VERSION 5.8 ;
BUSBITCHARS "[]" ;
DIVIDERCHAR "/" ;
UNITS
    DATABASE MICRONS 1000 ;
END UNITS

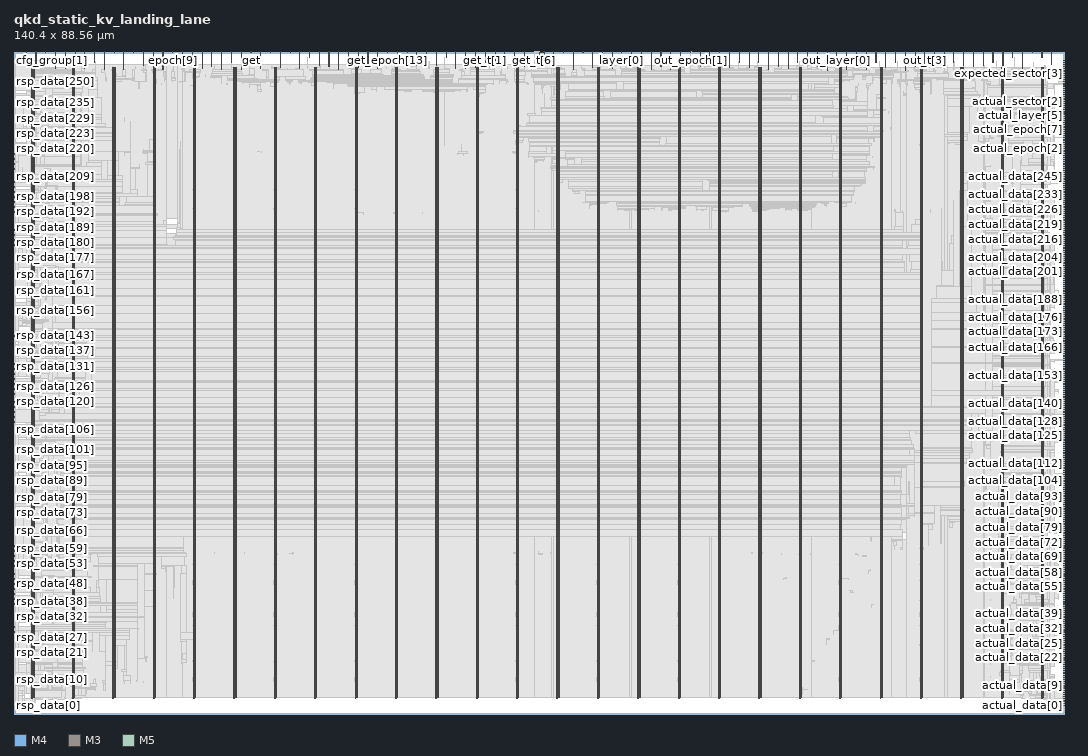
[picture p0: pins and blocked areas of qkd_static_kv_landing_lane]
MACRO qkd_static_kv_landing_lane
  FOREIGN qkd_static_kv_landing_lane 0 0 ;
  CLASS BLOCK ;
  SIZE 140.4 BY 88.56 ;
  PIN actual_data[0]
    DIRECTION INPUT ;
    USE SIGNAL ;
    PORT
      LAYER M4 ;
        RECT  140.316 1.152 140.4 1.176 ;
    END
  END actual_data[0]
  PIN actual_data[100]
    DIRECTION INPUT ;
    USE SIGNAL ;
    PORT
      LAYER M4 ;
        RECT  140.316 30 140.4 30.024 ;
    END
  END actual_data[100]
  PIN actual_data[101]
    DIRECTION INPUT ;
    USE SIGNAL ;
    PORT
      LAYER M4 ;
        RECT  140.316 30.288 140.4 30.312 ;
    END
  END actual_data[101]
  PIN actual_data[102]
    DIRECTION INPUT ;
    USE SIGNAL ;
    PORT
      LAYER M4 ;
        RECT  140.316 30.576 140.4 30.6 ;
    END
  END actual_data[102]
  PIN actual_data[103]
    DIRECTION INPUT ;
    USE SIGNAL ;
    PORT
      LAYER M4 ;
        RECT  140.316 30.864 140.4 30.888 ;
    END
  END actual_data[103]
  PIN actual_data[104]
    DIRECTION INPUT ;
    USE SIGNAL ;
    PORT
      LAYER M4 ;
        RECT  140.316 31.152 140.4 31.176 ;
    END
  END actual_data[104]
  PIN actual_data[105]
    DIRECTION INPUT ;
    USE SIGNAL ;
    PORT
      LAYER M4 ;
        RECT  140.316 31.44 140.4 31.464 ;
    END
  END actual_data[105]
  PIN actual_data[106]
    DIRECTION INPUT ;
    USE SIGNAL ;
    PORT
      LAYER M4 ;
        RECT  140.316 31.728 140.4 31.752 ;
    END
  END actual_data[106]
  PIN actual_data[107]
    DIRECTION INPUT ;
    USE SIGNAL ;
    PORT
      LAYER M4 ;
        RECT  140.316 32.016 140.4 32.04 ;
    END
  END actual_data[107]
  PIN actual_data[108]
    DIRECTION INPUT ;
    USE SIGNAL ;
    PORT
      LAYER M4 ;
        RECT  140.316 32.304 140.4 32.328 ;
    END
  END actual_data[108]
  PIN actual_data[109]
    DIRECTION INPUT ;
    USE SIGNAL ;
    PORT
      LAYER M4 ;
        RECT  140.316 32.592 140.4 32.616 ;
    END
  END actual_data[109]
  PIN actual_data[10]
    DIRECTION INPUT ;
    USE SIGNAL ;
    PORT
      LAYER M4 ;
        RECT  140.316 4.032 140.4 4.056 ;
    END
  END actual_data[10]
  PIN actual_data[110]
    DIRECTION INPUT ;
    USE SIGNAL ;
    PORT
      LAYER M4 ;
        RECT  140.316 32.88 140.4 32.904 ;
    END
  END actual_data[110]
  PIN actual_data[111]
    DIRECTION INPUT ;
    USE SIGNAL ;
    PORT
      LAYER M4 ;
        RECT  140.316 33.168 140.4 33.192 ;
    END
  END actual_data[111]
  PIN actual_data[112]
    DIRECTION INPUT ;
    USE SIGNAL ;
    PORT
      LAYER M4 ;
        RECT  140.316 33.456 140.4 33.48 ;
    END
  END actual_data[112]
  PIN actual_data[113]
    DIRECTION INPUT ;
    USE SIGNAL ;
    PORT
      LAYER M4 ;
        RECT  140.316 33.744 140.4 33.768 ;
    END
  END actual_data[113]
  PIN actual_data[114]
    DIRECTION INPUT ;
    USE SIGNAL ;
    PORT
      LAYER M4 ;
        RECT  140.316 34.032 140.4 34.056 ;
    END
  END actual_data[114]
  PIN actual_data[115]
    DIRECTION INPUT ;
    USE SIGNAL ;
    PORT
      LAYER M4 ;
        RECT  140.316 34.32 140.4 34.344 ;
    END
  END actual_data[115]
  PIN actual_data[116]
    DIRECTION INPUT ;
    USE SIGNAL ;
    PORT
      LAYER M4 ;
        RECT  140.316 34.608 140.4 34.632 ;
    END
  END actual_data[116]
  PIN actual_data[117]
    DIRECTION INPUT ;
    USE SIGNAL ;
    PORT
      LAYER M4 ;
        RECT  140.316 34.896 140.4 34.92 ;
    END
  END actual_data[117]
  PIN actual_data[118]
    DIRECTION INPUT ;
    USE SIGNAL ;
    PORT
      LAYER M4 ;
        RECT  140.316 35.184 140.4 35.208 ;
    END
  END actual_data[118]
  PIN actual_data[119]
    DIRECTION INPUT ;
    USE SIGNAL ;
    PORT
      LAYER M4 ;
        RECT  140.316 35.472 140.4 35.496 ;
    END
  END actual_data[119]
  PIN actual_data[11]
    DIRECTION INPUT ;
    USE SIGNAL ;
    PORT
      LAYER M4 ;
        RECT  140.316 4.32 140.4 4.344 ;
    END
  END actual_data[11]
  PIN actual_data[120]
    DIRECTION INPUT ;
    USE SIGNAL ;
    PORT
      LAYER M4 ;
        RECT  140.316 35.76 140.4 35.784 ;
    END
  END actual_data[120]
  PIN actual_data[121]
    DIRECTION INPUT ;
    USE SIGNAL ;
    PORT
      LAYER M4 ;
        RECT  140.316 36.048 140.4 36.072 ;
    END
  END actual_data[121]
  PIN actual_data[122]
    DIRECTION INPUT ;
    USE SIGNAL ;
    PORT
      LAYER M4 ;
        RECT  140.316 36.336 140.4 36.36 ;
    END
  END actual_data[122]
  PIN actual_data[123]
    DIRECTION INPUT ;
    USE SIGNAL ;
    PORT
      LAYER M4 ;
        RECT  140.316 36.624 140.4 36.648 ;
    END
  END actual_data[123]
  PIN actual_data[124]
    DIRECTION INPUT ;
    USE SIGNAL ;
    PORT
      LAYER M4 ;
        RECT  140.316 36.912 140.4 36.936 ;
    END
  END actual_data[124]
  PIN actual_data[125]
    DIRECTION INPUT ;
    USE SIGNAL ;
    PORT
      LAYER M4 ;
        RECT  140.316 37.2 140.4 37.224 ;
    END
  END actual_data[125]
  PIN actual_data[126]
    DIRECTION INPUT ;
    USE SIGNAL ;
    PORT
      LAYER M4 ;
        RECT  140.316 37.488 140.4 37.512 ;
    END
  END actual_data[126]
  PIN actual_data[127]
    DIRECTION INPUT ;
    USE SIGNAL ;
    PORT
      LAYER M4 ;
        RECT  140.316 37.776 140.4 37.8 ;
    END
  END actual_data[127]
  PIN actual_data[128]
    DIRECTION INPUT ;
    USE SIGNAL ;
    PORT
      LAYER M4 ;
        RECT  140.316 38.064 140.4 38.088 ;
    END
  END actual_data[128]
  PIN actual_data[129]
    DIRECTION INPUT ;
    USE SIGNAL ;
    PORT
      LAYER M4 ;
        RECT  140.316 38.352 140.4 38.376 ;
    END
  END actual_data[129]
  PIN actual_data[12]
    DIRECTION INPUT ;
    USE SIGNAL ;
    PORT
      LAYER M4 ;
        RECT  140.316 4.608 140.4 4.632 ;
    END
  END actual_data[12]
  PIN actual_data[130]
    DIRECTION INPUT ;
    USE SIGNAL ;
    PORT
      LAYER M4 ;
        RECT  140.316 38.64 140.4 38.664 ;
    END
  END actual_data[130]
  PIN actual_data[131]
    DIRECTION INPUT ;
    USE SIGNAL ;
    PORT
      LAYER M4 ;
        RECT  140.316 38.928 140.4 38.952 ;
    END
  END actual_data[131]
  PIN actual_data[132]
    DIRECTION INPUT ;
    USE SIGNAL ;
    PORT
      LAYER M4 ;
        RECT  140.316 39.216 140.4 39.24 ;
    END
  END actual_data[132]
  PIN actual_data[133]
    DIRECTION INPUT ;
    USE SIGNAL ;
    PORT
      LAYER M4 ;
        RECT  140.316 39.504 140.4 39.528 ;
    END
  END actual_data[133]
  PIN actual_data[134]
    DIRECTION INPUT ;
    USE SIGNAL ;
    PORT
      LAYER M4 ;
        RECT  140.316 39.792 140.4 39.816 ;
    END
  END actual_data[134]
  PIN actual_data[135]
    DIRECTION INPUT ;
    USE SIGNAL ;
    PORT
      LAYER M4 ;
        RECT  140.316 40.08 140.4 40.104 ;
    END
  END actual_data[135]
  PIN actual_data[136]
    DIRECTION INPUT ;
    USE SIGNAL ;
    PORT
      LAYER M4 ;
        RECT  140.316 40.368 140.4 40.392 ;
    END
  END actual_data[136]
  PIN actual_data[137]
    DIRECTION INPUT ;
    USE SIGNAL ;
    PORT
      LAYER M4 ;
        RECT  140.316 40.656 140.4 40.68 ;
    END
  END actual_data[137]
  PIN actual_data[138]
    DIRECTION INPUT ;
    USE SIGNAL ;
    PORT
      LAYER M4 ;
        RECT  140.316 40.944 140.4 40.968 ;
    END
  END actual_data[138]
  PIN actual_data[139]
    DIRECTION INPUT ;
    USE SIGNAL ;
    PORT
      LAYER M4 ;
        RECT  140.316 41.232 140.4 41.256 ;
    END
  END actual_data[139]
  PIN actual_data[13]
    DIRECTION INPUT ;
    USE SIGNAL ;
    PORT
      LAYER M4 ;
        RECT  140.316 4.896 140.4 4.92 ;
    END
  END actual_data[13]
  PIN actual_data[140]
    DIRECTION INPUT ;
    USE SIGNAL ;
    PORT
      LAYER M4 ;
        RECT  140.316 41.52 140.4 41.544 ;
    END
  END actual_data[140]
  PIN actual_data[141]
    DIRECTION INPUT ;
    USE SIGNAL ;
    PORT
      LAYER M4 ;
        RECT  140.316 41.808 140.4 41.832 ;
    END
  END actual_data[141]
  PIN actual_data[142]
    DIRECTION INPUT ;
    USE SIGNAL ;
    PORT
      LAYER M4 ;
        RECT  140.316 42.096 140.4 42.12 ;
    END
  END actual_data[142]
  PIN actual_data[143]
    DIRECTION INPUT ;
    USE SIGNAL ;
    PORT
      LAYER M4 ;
        RECT  140.316 42.384 140.4 42.408 ;
    END
  END actual_data[143]
  PIN actual_data[144]
    DIRECTION INPUT ;
    USE SIGNAL ;
    PORT
      LAYER M4 ;
        RECT  140.316 42.672 140.4 42.696 ;
    END
  END actual_data[144]
  PIN actual_data[145]
    DIRECTION INPUT ;
    USE SIGNAL ;
    PORT
      LAYER M4 ;
        RECT  140.316 42.96 140.4 42.984 ;
    END
  END actual_data[145]
  PIN actual_data[146]
    DIRECTION INPUT ;
    USE SIGNAL ;
    PORT
      LAYER M4 ;
        RECT  140.316 43.248 140.4 43.272 ;
    END
  END actual_data[146]
  PIN actual_data[147]
    DIRECTION INPUT ;
    USE SIGNAL ;
    PORT
      LAYER M4 ;
        RECT  140.316 43.536 140.4 43.56 ;
    END
  END actual_data[147]
  PIN actual_data[148]
    DIRECTION INPUT ;
    USE SIGNAL ;
    PORT
      LAYER M4 ;
        RECT  140.316 43.824 140.4 43.848 ;
    END
  END actual_data[148]
  PIN actual_data[149]
    DIRECTION INPUT ;
    USE SIGNAL ;
    PORT
      LAYER M4 ;
        RECT  140.316 44.112 140.4 44.136 ;
    END
  END actual_data[149]
  PIN actual_data[14]
    DIRECTION INPUT ;
    USE SIGNAL ;
    PORT
      LAYER M4 ;
        RECT  140.316 5.184 140.4 5.208 ;
    END
  END actual_data[14]
  PIN actual_data[150]
    DIRECTION INPUT ;
    USE SIGNAL ;
    PORT
      LAYER M4 ;
        RECT  140.316 44.4 140.4 44.424 ;
    END
  END actual_data[150]
  PIN actual_data[151]
    DIRECTION INPUT ;
    USE SIGNAL ;
    PORT
      LAYER M4 ;
        RECT  140.316 44.688 140.4 44.712 ;
    END
  END actual_data[151]
  PIN actual_data[152]
    DIRECTION INPUT ;
    USE SIGNAL ;
    PORT
      LAYER M4 ;
        RECT  140.316 44.976 140.4 45 ;
    END
  END actual_data[152]
  PIN actual_data[153]
    DIRECTION INPUT ;
    USE SIGNAL ;
    PORT
      LAYER M4 ;
        RECT  140.316 45.264 140.4 45.288 ;
    END
  END actual_data[153]
  PIN actual_data[154]
    DIRECTION INPUT ;
    USE SIGNAL ;
    PORT
      LAYER M4 ;
        RECT  140.316 45.552 140.4 45.576 ;
    END
  END actual_data[154]
  PIN actual_data[155]
    DIRECTION INPUT ;
    USE SIGNAL ;
    PORT
      LAYER M4 ;
        RECT  140.316 45.84 140.4 45.864 ;
    END
  END actual_data[155]
  PIN actual_data[156]
    DIRECTION INPUT ;
    USE SIGNAL ;
    PORT
      LAYER M4 ;
        RECT  140.316 46.128 140.4 46.152 ;
    END
  END actual_data[156]
  PIN actual_data[157]
    DIRECTION INPUT ;
    USE SIGNAL ;
    PORT
      LAYER M4 ;
        RECT  140.316 46.416 140.4 46.44 ;
    END
  END actual_data[157]
  PIN actual_data[158]
    DIRECTION INPUT ;
    USE SIGNAL ;
    PORT
      LAYER M4 ;
        RECT  140.316 46.704 140.4 46.728 ;
    END
  END actual_data[158]
  PIN actual_data[159]
    DIRECTION INPUT ;
    USE SIGNAL ;
    PORT
      LAYER M4 ;
        RECT  140.316 46.992 140.4 47.016 ;
    END
  END actual_data[159]
  PIN actual_data[15]
    DIRECTION INPUT ;
    USE SIGNAL ;
    PORT
      LAYER M4 ;
        RECT  140.316 5.472 140.4 5.496 ;
    END
  END actual_data[15]
  PIN actual_data[160]
    DIRECTION INPUT ;
    USE SIGNAL ;
    PORT
      LAYER M4 ;
        RECT  140.316 47.28 140.4 47.304 ;
    END
  END actual_data[160]
  PIN actual_data[161]
    DIRECTION INPUT ;
    USE SIGNAL ;
    PORT
      LAYER M4 ;
        RECT  140.316 47.568 140.4 47.592 ;
    END
  END actual_data[161]
  PIN actual_data[162]
    DIRECTION INPUT ;
    USE SIGNAL ;
    PORT
      LAYER M4 ;
        RECT  140.316 47.856 140.4 47.88 ;
    END
  END actual_data[162]
  PIN actual_data[163]
    DIRECTION INPUT ;
    USE SIGNAL ;
    PORT
      LAYER M4 ;
        RECT  140.316 48.144 140.4 48.168 ;
    END
  END actual_data[163]
  PIN actual_data[164]
    DIRECTION INPUT ;
    USE SIGNAL ;
    PORT
      LAYER M4 ;
        RECT  140.316 48.432 140.4 48.456 ;
    END
  END actual_data[164]
  PIN actual_data[165]
    DIRECTION INPUT ;
    USE SIGNAL ;
    PORT
      LAYER M4 ;
        RECT  140.316 48.72 140.4 48.744 ;
    END
  END actual_data[165]
  PIN actual_data[166]
    DIRECTION INPUT ;
    USE SIGNAL ;
    PORT
      LAYER M4 ;
        RECT  140.316 49.008 140.4 49.032 ;
    END
  END actual_data[166]
  PIN actual_data[167]
    DIRECTION INPUT ;
    USE SIGNAL ;
    PORT
      LAYER M4 ;
        RECT  140.316 49.296 140.4 49.32 ;
    END
  END actual_data[167]
  PIN actual_data[168]
    DIRECTION INPUT ;
    USE SIGNAL ;
    PORT
      LAYER M4 ;
        RECT  140.316 49.584 140.4 49.608 ;
    END
  END actual_data[168]
  PIN actual_data[169]
    DIRECTION INPUT ;
    USE SIGNAL ;
    PORT
      LAYER M4 ;
        RECT  140.316 49.872 140.4 49.896 ;
    END
  END actual_data[169]
  PIN actual_data[16]
    DIRECTION INPUT ;
    USE SIGNAL ;
    PORT
      LAYER M4 ;
        RECT  140.316 5.76 140.4 5.784 ;
    END
  END actual_data[16]
  PIN actual_data[170]
    DIRECTION INPUT ;
    USE SIGNAL ;
    PORT
      LAYER M4 ;
        RECT  140.316 50.16 140.4 50.184 ;
    END
  END actual_data[170]
  PIN actual_data[171]
    DIRECTION INPUT ;
    USE SIGNAL ;
    PORT
      LAYER M4 ;
        RECT  140.316 50.448 140.4 50.472 ;
    END
  END actual_data[171]
  PIN actual_data[172]
    DIRECTION INPUT ;
    USE SIGNAL ;
    PORT
      LAYER M4 ;
        RECT  140.316 50.784 140.4 50.808 ;
    END
  END actual_data[172]
  PIN actual_data[173]
    DIRECTION INPUT ;
    USE SIGNAL ;
    PORT
      LAYER M4 ;
        RECT  140.316 51.072 140.4 51.096 ;
    END
  END actual_data[173]
  PIN actual_data[174]
    DIRECTION INPUT ;
    USE SIGNAL ;
    PORT
      LAYER M4 ;
        RECT  140.316 51.36 140.4 51.384 ;
    END
  END actual_data[174]
  PIN actual_data[175]
    DIRECTION INPUT ;
    USE SIGNAL ;
    PORT
      LAYER M4 ;
        RECT  140.316 51.648 140.4 51.672 ;
    END
  END actual_data[175]
  PIN actual_data[176]
    DIRECTION INPUT ;
    USE SIGNAL ;
    PORT
      LAYER M4 ;
        RECT  140.316 51.936 140.4 51.96 ;
    END
  END actual_data[176]
  PIN actual_data[177]
    DIRECTION INPUT ;
    USE SIGNAL ;
    PORT
      LAYER M4 ;
        RECT  140.316 52.224 140.4 52.248 ;
    END
  END actual_data[177]
  PIN actual_data[178]
    DIRECTION INPUT ;
    USE SIGNAL ;
    PORT
      LAYER M4 ;
        RECT  140.316 52.512 140.4 52.536 ;
    END
  END actual_data[178]
  PIN actual_data[179]
    DIRECTION INPUT ;
    USE SIGNAL ;
    PORT
      LAYER M4 ;
        RECT  140.316 52.8 140.4 52.824 ;
    END
  END actual_data[179]
  PIN actual_data[17]
    DIRECTION INPUT ;
    USE SIGNAL ;
    PORT
      LAYER M4 ;
        RECT  140.316 6.048 140.4 6.072 ;
    END
  END actual_data[17]
  PIN actual_data[180]
    DIRECTION INPUT ;
    USE SIGNAL ;
    PORT
      LAYER M4 ;
        RECT  140.316 53.088 140.4 53.112 ;
    END
  END actual_data[180]
  PIN actual_data[181]
    DIRECTION INPUT ;
    USE SIGNAL ;
    PORT
      LAYER M4 ;
        RECT  140.316 53.376 140.4 53.4 ;
    END
  END actual_data[181]
  PIN actual_data[182]
    DIRECTION INPUT ;
    USE SIGNAL ;
    PORT
      LAYER M4 ;
        RECT  140.316 53.664 140.4 53.688 ;
    END
  END actual_data[182]
  PIN actual_data[183]
    DIRECTION INPUT ;
    USE SIGNAL ;
    PORT
      LAYER M4 ;
        RECT  140.316 53.952 140.4 53.976 ;
    END
  END actual_data[183]
  PIN actual_data[184]
    DIRECTION INPUT ;
    USE SIGNAL ;
    PORT
      LAYER M4 ;
        RECT  140.316 54.24 140.4 54.264 ;
    END
  END actual_data[184]
  PIN actual_data[185]
    DIRECTION INPUT ;
    USE SIGNAL ;
    PORT
      LAYER M4 ;
        RECT  140.316 54.528 140.4 54.552 ;
    END
  END actual_data[185]
  PIN actual_data[186]
    DIRECTION INPUT ;
    USE SIGNAL ;
    PORT
      LAYER M4 ;
        RECT  140.316 54.816 140.4 54.84 ;
    END
  END actual_data[186]
  PIN actual_data[187]
    DIRECTION INPUT ;
    USE SIGNAL ;
    PORT
      LAYER M4 ;
        RECT  140.316 55.104 140.4 55.128 ;
    END
  END actual_data[187]
  PIN actual_data[188]
    DIRECTION INPUT ;
    USE SIGNAL ;
    PORT
      LAYER M4 ;
        RECT  140.316 55.392 140.4 55.416 ;
    END
  END actual_data[188]
  PIN actual_data[189]
    DIRECTION INPUT ;
    USE SIGNAL ;
    PORT
      LAYER M4 ;
        RECT  140.316 55.68 140.4 55.704 ;
    END
  END actual_data[189]
  PIN actual_data[18]
    DIRECTION INPUT ;
    USE SIGNAL ;
    PORT
      LAYER M4 ;
        RECT  140.316 6.336 140.4 6.36 ;
    END
  END actual_data[18]
  PIN actual_data[190]
    DIRECTION INPUT ;
    USE SIGNAL ;
    PORT
      LAYER M4 ;
        RECT  140.316 55.968 140.4 55.992 ;
    END
  END actual_data[190]
  PIN actual_data[191]
    DIRECTION INPUT ;
    USE SIGNAL ;
    PORT
      LAYER M4 ;
        RECT  140.316 56.256 140.4 56.28 ;
    END
  END actual_data[191]
  PIN actual_data[192]
    DIRECTION INPUT ;
    USE SIGNAL ;
    PORT
      LAYER M4 ;
        RECT  140.316 56.544 140.4 56.568 ;
    END
  END actual_data[192]
  PIN actual_data[193]
    DIRECTION INPUT ;
    USE SIGNAL ;
    PORT
      LAYER M4 ;
        RECT  140.316 56.832 140.4 56.856 ;
    END
  END actual_data[193]
  PIN actual_data[194]
    DIRECTION INPUT ;
    USE SIGNAL ;
    PORT
      LAYER M4 ;
        RECT  140.316 57.12 140.4 57.144 ;
    END
  END actual_data[194]
  PIN actual_data[195]
    DIRECTION INPUT ;
    USE SIGNAL ;
    PORT
      LAYER M4 ;
        RECT  140.316 57.408 140.4 57.432 ;
    END
  END actual_data[195]
  PIN actual_data[196]
    DIRECTION INPUT ;
    USE SIGNAL ;
    PORT
      LAYER M4 ;
        RECT  140.316 57.696 140.4 57.72 ;
    END
  END actual_data[196]
  PIN actual_data[197]
    DIRECTION INPUT ;
    USE SIGNAL ;
    PORT
      LAYER M4 ;
        RECT  140.316 57.984 140.4 58.008 ;
    END
  END actual_data[197]
  PIN actual_data[198]
    DIRECTION INPUT ;
    USE SIGNAL ;
    PORT
      LAYER M4 ;
        RECT  140.316 58.272 140.4 58.296 ;
    END
  END actual_data[198]
  PIN actual_data[199]
    DIRECTION INPUT ;
    USE SIGNAL ;
    PORT
      LAYER M4 ;
        RECT  140.316 58.56 140.4 58.584 ;
    END
  END actual_data[199]
  PIN actual_data[19]
    DIRECTION INPUT ;
    USE SIGNAL ;
    PORT
      LAYER M4 ;
        RECT  140.316 6.624 140.4 6.648 ;
    END
  END actual_data[19]
  PIN actual_data[1]
    DIRECTION INPUT ;
    USE SIGNAL ;
    PORT
      LAYER M4 ;
        RECT  140.316 1.44 140.4 1.464 ;
    END
  END actual_data[1]
  PIN actual_data[200]
    DIRECTION INPUT ;
    USE SIGNAL ;
    PORT
      LAYER M4 ;
        RECT  140.316 58.848 140.4 58.872 ;
    END
  END actual_data[200]
  PIN actual_data[201]
    DIRECTION INPUT ;
    USE SIGNAL ;
    PORT
      LAYER M4 ;
        RECT  140.316 59.136 140.4 59.16 ;
    END
  END actual_data[201]
  PIN actual_data[202]
    DIRECTION INPUT ;
    USE SIGNAL ;
    PORT
      LAYER M4 ;
        RECT  140.316 59.424 140.4 59.448 ;
    END
  END actual_data[202]
  PIN actual_data[203]
    DIRECTION INPUT ;
    USE SIGNAL ;
    PORT
      LAYER M4 ;
        RECT  140.316 59.712 140.4 59.736 ;
    END
  END actual_data[203]
  PIN actual_data[204]
    DIRECTION INPUT ;
    USE SIGNAL ;
    PORT
      LAYER M4 ;
        RECT  140.316 60 140.4 60.024 ;
    END
  END actual_data[204]
  PIN actual_data[205]
    DIRECTION INPUT ;
    USE SIGNAL ;
    PORT
      LAYER M4 ;
        RECT  140.316 60.288 140.4 60.312 ;
    END
  END actual_data[205]
  PIN actual_data[206]
    DIRECTION INPUT ;
    USE SIGNAL ;
    PORT
      LAYER M4 ;
        RECT  140.316 60.576 140.4 60.6 ;
    END
  END actual_data[206]
  PIN actual_data[207]
    DIRECTION INPUT ;
    USE SIGNAL ;
    PORT
      LAYER M4 ;
        RECT  140.316 60.864 140.4 60.888 ;
    END
  END actual_data[207]
  PIN actual_data[208]
    DIRECTION INPUT ;
    USE SIGNAL ;
    PORT
      LAYER M4 ;
        RECT  140.316 61.152 140.4 61.176 ;
    END
  END actual_data[208]
  PIN actual_data[209]
    DIRECTION INPUT ;
    USE SIGNAL ;
    PORT
      LAYER M4 ;
        RECT  140.316 61.44 140.4 61.464 ;
    END
  END actual_data[209]
  PIN actual_data[20]
    DIRECTION INPUT ;
    USE SIGNAL ;
    PORT
      LAYER M4 ;
        RECT  140.316 6.912 140.4 6.936 ;
    END
  END actual_data[20]
  PIN actual_data[210]
    DIRECTION INPUT ;
    USE SIGNAL ;
    PORT
      LAYER M4 ;
        RECT  140.316 61.728 140.4 61.752 ;
    END
  END actual_data[210]
  PIN actual_data[211]
    DIRECTION INPUT ;
    USE SIGNAL ;
    PORT
      LAYER M4 ;
        RECT  140.316 62.016 140.4 62.04 ;
    END
  END actual_data[211]
  PIN actual_data[212]
    DIRECTION INPUT ;
    USE SIGNAL ;
    PORT
      LAYER M4 ;
        RECT  140.316 62.304 140.4 62.328 ;
    END
  END actual_data[212]
  PIN actual_data[213]
    DIRECTION INPUT ;
    USE SIGNAL ;
    PORT
      LAYER M4 ;
        RECT  140.316 62.592 140.4 62.616 ;
    END
  END actual_data[213]
  PIN actual_data[214]
    DIRECTION INPUT ;
    USE SIGNAL ;
    PORT
      LAYER M4 ;
        RECT  140.316 62.88 140.4 62.904 ;
    END
  END actual_data[214]
  PIN actual_data[215]
    DIRECTION INPUT ;
    USE SIGNAL ;
    PORT
      LAYER M4 ;
        RECT  140.316 63.168 140.4 63.192 ;
    END
  END actual_data[215]
  PIN actual_data[216]
    DIRECTION INPUT ;
    USE SIGNAL ;
    PORT
      LAYER M4 ;
        RECT  140.316 63.456 140.4 63.48 ;
    END
  END actual_data[216]
  PIN actual_data[217]
    DIRECTION INPUT ;
    USE SIGNAL ;
    PORT
      LAYER M4 ;
        RECT  140.316 63.744 140.4 63.768 ;
    END
  END actual_data[217]
  PIN actual_data[218]
    DIRECTION INPUT ;
    USE SIGNAL ;
    PORT
      LAYER M4 ;
        RECT  140.316 64.032 140.4 64.056 ;
    END
  END actual_data[218]
  PIN actual_data[219]
    DIRECTION INPUT ;
    USE SIGNAL ;
    PORT
      LAYER M4 ;
        RECT  140.316 64.32 140.4 64.344 ;
    END
  END actual_data[219]
  PIN actual_data[21]
    DIRECTION INPUT ;
    USE SIGNAL ;
    PORT
      LAYER M4 ;
        RECT  140.316 7.2 140.4 7.224 ;
    END
  END actual_data[21]
  PIN actual_data[220]
    DIRECTION INPUT ;
    USE SIGNAL ;
    PORT
      LAYER M4 ;
        RECT  140.316 64.608 140.4 64.632 ;
    END
  END actual_data[220]
  PIN actual_data[221]
    DIRECTION INPUT ;
    USE SIGNAL ;
    PORT
      LAYER M4 ;
        RECT  140.316 64.896 140.4 64.92 ;
    END
  END actual_data[221]
  PIN actual_data[222]
    DIRECTION INPUT ;
    USE SIGNAL ;
    PORT
      LAYER M4 ;
        RECT  140.316 65.184 140.4 65.208 ;
    END
  END actual_data[222]
  PIN actual_data[223]
    DIRECTION INPUT ;
    USE SIGNAL ;
    PORT
      LAYER M4 ;
        RECT  140.316 65.472 140.4 65.496 ;
    END
  END actual_data[223]
  PIN actual_data[224]
    DIRECTION INPUT ;
    USE SIGNAL ;
    PORT
      LAYER M4 ;
        RECT  140.316 65.76 140.4 65.784 ;
    END
  END actual_data[224]
  PIN actual_data[225]
    DIRECTION INPUT ;
    USE SIGNAL ;
    PORT
      LAYER M4 ;
        RECT  140.316 66.048 140.4 66.072 ;
    END
  END actual_data[225]
  PIN actual_data[226]
    DIRECTION INPUT ;
    USE SIGNAL ;
    PORT
      LAYER M4 ;
        RECT  140.316 66.336 140.4 66.36 ;
    END
  END actual_data[226]
  PIN actual_data[227]
    DIRECTION INPUT ;
    USE SIGNAL ;
    PORT
      LAYER M4 ;
        RECT  140.316 66.624 140.4 66.648 ;
    END
  END actual_data[227]
  PIN actual_data[228]
    DIRECTION INPUT ;
    USE SIGNAL ;
    PORT
      LAYER M4 ;
        RECT  140.316 66.912 140.4 66.936 ;
    END
  END actual_data[228]
  PIN actual_data[229]
    DIRECTION INPUT ;
    USE SIGNAL ;
    PORT
      LAYER M4 ;
        RECT  140.316 67.2 140.4 67.224 ;
    END
  END actual_data[229]
  PIN actual_data[22]
    DIRECTION INPUT ;
    USE SIGNAL ;
    PORT
      LAYER M4 ;
        RECT  140.316 7.488 140.4 7.512 ;
    END
  END actual_data[22]
  PIN actual_data[230]
    DIRECTION INPUT ;
    USE SIGNAL ;
    PORT
      LAYER M4 ;
        RECT  140.316 67.488 140.4 67.512 ;
    END
  END actual_data[230]
  PIN actual_data[231]
    DIRECTION INPUT ;
    USE SIGNAL ;
    PORT
      LAYER M4 ;
        RECT  140.316 67.776 140.4 67.8 ;
    END
  END actual_data[231]
  PIN actual_data[232]
    DIRECTION INPUT ;
    USE SIGNAL ;
    PORT
      LAYER M4 ;
        RECT  140.316 68.064 140.4 68.088 ;
    END
  END actual_data[232]
  PIN actual_data[233]
    DIRECTION INPUT ;
    USE SIGNAL ;
    PORT
      LAYER M4 ;
        RECT  140.316 68.352 140.4 68.376 ;
    END
  END actual_data[233]
  PIN actual_data[234]
    DIRECTION INPUT ;
    USE SIGNAL ;
    PORT
      LAYER M4 ;
        RECT  140.316 68.64 140.4 68.664 ;
    END
  END actual_data[234]
  PIN actual_data[235]
    DIRECTION INPUT ;
    USE SIGNAL ;
    PORT
      LAYER M4 ;
        RECT  140.316 68.928 140.4 68.952 ;
    END
  END actual_data[235]
  PIN actual_data[236]
    DIRECTION INPUT ;
    USE SIGNAL ;
    PORT
      LAYER M4 ;
        RECT  140.316 69.216 140.4 69.24 ;
    END
  END actual_data[236]
  PIN actual_data[237]
    DIRECTION INPUT ;
    USE SIGNAL ;
    PORT
      LAYER M4 ;
        RECT  140.316 69.504 140.4 69.528 ;
    END
  END actual_data[237]
  PIN actual_data[238]
    DIRECTION INPUT ;
    USE SIGNAL ;
    PORT
      LAYER M4 ;
        RECT  140.316 69.792 140.4 69.816 ;
    END
  END actual_data[238]
  PIN actual_data[239]
    DIRECTION INPUT ;
    USE SIGNAL ;
    PORT
      LAYER M4 ;
        RECT  140.316 70.08 140.4 70.104 ;
    END
  END actual_data[239]
  PIN actual_data[23]
    DIRECTION INPUT ;
    USE SIGNAL ;
    PORT
      LAYER M4 ;
        RECT  140.316 7.776 140.4 7.8 ;
    END
  END actual_data[23]
  PIN actual_data[240]
    DIRECTION INPUT ;
    USE SIGNAL ;
    PORT
      LAYER M4 ;
        RECT  140.316 70.368 140.4 70.392 ;
    END
  END actual_data[240]
  PIN actual_data[241]
    DIRECTION INPUT ;
    USE SIGNAL ;
    PORT
      LAYER M4 ;
        RECT  140.316 70.656 140.4 70.68 ;
    END
  END actual_data[241]
  PIN actual_data[242]
    DIRECTION INPUT ;
    USE SIGNAL ;
    PORT
      LAYER M4 ;
        RECT  140.316 70.944 140.4 70.968 ;
    END
  END actual_data[242]
  PIN actual_data[243]
    DIRECTION INPUT ;
    USE SIGNAL ;
    PORT
      LAYER M4 ;
        RECT  140.316 71.232 140.4 71.256 ;
    END
  END actual_data[243]
  PIN actual_data[244]
    DIRECTION INPUT ;
    USE SIGNAL ;
    PORT
      LAYER M4 ;
        RECT  140.316 71.52 140.4 71.544 ;
    END
  END actual_data[244]
  PIN actual_data[245]
    DIRECTION INPUT ;
    USE SIGNAL ;
    PORT
      LAYER M4 ;
        RECT  140.316 71.808 140.4 71.832 ;
    END
  END actual_data[245]
  PIN actual_data[246]
    DIRECTION INPUT ;
    USE SIGNAL ;
    PORT
      LAYER M4 ;
        RECT  140.316 72.096 140.4 72.12 ;
    END
  END actual_data[246]
  PIN actual_data[247]
    DIRECTION INPUT ;
    USE SIGNAL ;
    PORT
      LAYER M4 ;
        RECT  140.316 72.384 140.4 72.408 ;
    END
  END actual_data[247]
  PIN actual_data[248]
    DIRECTION INPUT ;
    USE SIGNAL ;
    PORT
      LAYER M4 ;
        RECT  140.316 72.672 140.4 72.696 ;
    END
  END actual_data[248]
  PIN actual_data[249]
    DIRECTION INPUT ;
    USE SIGNAL ;
    PORT
      LAYER M4 ;
        RECT  140.316 72.96 140.4 72.984 ;
    END
  END actual_data[249]
  PIN actual_data[24]
    DIRECTION INPUT ;
    USE SIGNAL ;
    PORT
      LAYER M4 ;
        RECT  140.316 8.064 140.4 8.088 ;
    END
  END actual_data[24]
  PIN actual_data[250]
    DIRECTION INPUT ;
    USE SIGNAL ;
    PORT
      LAYER M4 ;
        RECT  140.316 73.248 140.4 73.272 ;
    END
  END actual_data[250]
  PIN actual_data[251]
    DIRECTION INPUT ;
    USE SIGNAL ;
    PORT
      LAYER M4 ;
        RECT  140.316 73.536 140.4 73.56 ;
    END
  END actual_data[251]
  PIN actual_data[252]
    DIRECTION INPUT ;
    USE SIGNAL ;
    PORT
      LAYER M4 ;
        RECT  140.316 73.824 140.4 73.848 ;
    END
  END actual_data[252]
  PIN actual_data[253]
    DIRECTION INPUT ;
    USE SIGNAL ;
    PORT
      LAYER M4 ;
        RECT  140.316 74.112 140.4 74.136 ;
    END
  END actual_data[253]
  PIN actual_data[254]
    DIRECTION INPUT ;
    USE SIGNAL ;
    PORT
      LAYER M4 ;
        RECT  140.316 74.4 140.4 74.424 ;
    END
  END actual_data[254]
  PIN actual_data[255]
    DIRECTION INPUT ;
    USE SIGNAL ;
    PORT
      LAYER M4 ;
        RECT  140.316 74.688 140.4 74.712 ;
    END
  END actual_data[255]
  PIN actual_data[25]
    DIRECTION INPUT ;
    USE SIGNAL ;
    PORT
      LAYER M4 ;
        RECT  140.316 8.352 140.4 8.376 ;
    END
  END actual_data[25]
  PIN actual_data[26]
    DIRECTION INPUT ;
    USE SIGNAL ;
    PORT
      LAYER M4 ;
        RECT  140.316 8.64 140.4 8.664 ;
    END
  END actual_data[26]
  PIN actual_data[27]
    DIRECTION INPUT ;
    USE SIGNAL ;
    PORT
      LAYER M4 ;
        RECT  140.316 8.928 140.4 8.952 ;
    END
  END actual_data[27]
  PIN actual_data[28]
    DIRECTION INPUT ;
    USE SIGNAL ;
    PORT
      LAYER M4 ;
        RECT  140.316 9.216 140.4 9.24 ;
    END
  END actual_data[28]
  PIN actual_data[29]
    DIRECTION INPUT ;
    USE SIGNAL ;
    PORT
      LAYER M4 ;
        RECT  140.316 9.504 140.4 9.528 ;
    END
  END actual_data[29]
  PIN actual_data[2]
    DIRECTION INPUT ;
    USE SIGNAL ;
    PORT
      LAYER M4 ;
        RECT  140.316 1.728 140.4 1.752 ;
    END
  END actual_data[2]
  PIN actual_data[30]
    DIRECTION INPUT ;
    USE SIGNAL ;
    PORT
      LAYER M4 ;
        RECT  140.316 9.792 140.4 9.816 ;
    END
  END actual_data[30]
  PIN actual_data[31]
    DIRECTION INPUT ;
    USE SIGNAL ;
    PORT
      LAYER M4 ;
        RECT  140.316 10.08 140.4 10.104 ;
    END
  END actual_data[31]
  PIN actual_data[32]
    DIRECTION INPUT ;
    USE SIGNAL ;
    PORT
      LAYER M4 ;
        RECT  140.316 10.368 140.4 10.392 ;
    END
  END actual_data[32]
  PIN actual_data[33]
    DIRECTION INPUT ;
    USE SIGNAL ;
    PORT
      LAYER M4 ;
        RECT  140.316 10.656 140.4 10.68 ;
    END
  END actual_data[33]
  PIN actual_data[34]
    DIRECTION INPUT ;
    USE SIGNAL ;
    PORT
      LAYER M4 ;
        RECT  140.316 10.944 140.4 10.968 ;
    END
  END actual_data[34]
  PIN actual_data[35]
    DIRECTION INPUT ;
    USE SIGNAL ;
    PORT
      LAYER M4 ;
        RECT  140.316 11.232 140.4 11.256 ;
    END
  END actual_data[35]
  PIN actual_data[36]
    DIRECTION INPUT ;
    USE SIGNAL ;
    PORT
      LAYER M4 ;
        RECT  140.316 11.52 140.4 11.544 ;
    END
  END actual_data[36]
  PIN actual_data[37]
    DIRECTION INPUT ;
    USE SIGNAL ;
    PORT
      LAYER M4 ;
        RECT  140.316 11.808 140.4 11.832 ;
    END
  END actual_data[37]
  PIN actual_data[38]
    DIRECTION INPUT ;
    USE SIGNAL ;
    PORT
      LAYER M4 ;
        RECT  140.316 12.096 140.4 12.12 ;
    END
  END actual_data[38]
  PIN actual_data[39]
    DIRECTION INPUT ;
    USE SIGNAL ;
    PORT
      LAYER M4 ;
        RECT  140.316 12.384 140.4 12.408 ;
    END
  END actual_data[39]
  PIN actual_data[3]
    DIRECTION INPUT ;
    USE SIGNAL ;
    PORT
      LAYER M4 ;
        RECT  140.316 2.016 140.4 2.04 ;
    END
  END actual_data[3]
  PIN actual_data[40]
    DIRECTION INPUT ;
    USE SIGNAL ;
    PORT
      LAYER M4 ;
        RECT  140.316 12.672 140.4 12.696 ;
    END
  END actual_data[40]
  PIN actual_data[41]
    DIRECTION INPUT ;
    USE SIGNAL ;
    PORT
      LAYER M4 ;
        RECT  140.316 12.96 140.4 12.984 ;
    END
  END actual_data[41]
  PIN actual_data[42]
    DIRECTION INPUT ;
    USE SIGNAL ;
    PORT
      LAYER M4 ;
        RECT  140.316 13.248 140.4 13.272 ;
    END
  END actual_data[42]
  PIN actual_data[43]
    DIRECTION INPUT ;
    USE SIGNAL ;
    PORT
      LAYER M4 ;
        RECT  140.316 13.536 140.4 13.56 ;
    END
  END actual_data[43]
  PIN actual_data[44]
    DIRECTION INPUT ;
    USE SIGNAL ;
    PORT
      LAYER M4 ;
        RECT  140.316 13.824 140.4 13.848 ;
    END
  END actual_data[44]
  PIN actual_data[45]
    DIRECTION INPUT ;
    USE SIGNAL ;
    PORT
      LAYER M4 ;
        RECT  140.316 14.112 140.4 14.136 ;
    END
  END actual_data[45]
  PIN actual_data[46]
    DIRECTION INPUT ;
    USE SIGNAL ;
    PORT
      LAYER M4 ;
        RECT  140.316 14.4 140.4 14.424 ;
    END
  END actual_data[46]
  PIN actual_data[47]
    DIRECTION INPUT ;
    USE SIGNAL ;
    PORT
      LAYER M4 ;
        RECT  140.316 14.688 140.4 14.712 ;
    END
  END actual_data[47]
  PIN actual_data[48]
    DIRECTION INPUT ;
    USE SIGNAL ;
    PORT
      LAYER M4 ;
        RECT  140.316 14.976 140.4 15 ;
    END
  END actual_data[48]
  PIN actual_data[49]
    DIRECTION INPUT ;
    USE SIGNAL ;
    PORT
      LAYER M4 ;
        RECT  140.316 15.264 140.4 15.288 ;
    END
  END actual_data[49]
  PIN actual_data[4]
    DIRECTION INPUT ;
    USE SIGNAL ;
    PORT
      LAYER M4 ;
        RECT  140.316 2.304 140.4 2.328 ;
    END
  END actual_data[4]
  PIN actual_data[50]
    DIRECTION INPUT ;
    USE SIGNAL ;
    PORT
      LAYER M4 ;
        RECT  140.316 15.552 140.4 15.576 ;
    END
  END actual_data[50]
  PIN actual_data[51]
    DIRECTION INPUT ;
    USE SIGNAL ;
    PORT
      LAYER M4 ;
        RECT  140.316 15.84 140.4 15.864 ;
    END
  END actual_data[51]
  PIN actual_data[52]
    DIRECTION INPUT ;
    USE SIGNAL ;
    PORT
      LAYER M4 ;
        RECT  140.316 16.128 140.4 16.152 ;
    END
  END actual_data[52]
  PIN actual_data[53]
    DIRECTION INPUT ;
    USE SIGNAL ;
    PORT
      LAYER M4 ;
        RECT  140.316 16.416 140.4 16.44 ;
    END
  END actual_data[53]
  PIN actual_data[54]
    DIRECTION INPUT ;
    USE SIGNAL ;
    PORT
      LAYER M4 ;
        RECT  140.316 16.704 140.4 16.728 ;
    END
  END actual_data[54]
  PIN actual_data[55]
    DIRECTION INPUT ;
    USE SIGNAL ;
    PORT
      LAYER M4 ;
        RECT  140.316 16.992 140.4 17.016 ;
    END
  END actual_data[55]
  PIN actual_data[56]
    DIRECTION INPUT ;
    USE SIGNAL ;
    PORT
      LAYER M4 ;
        RECT  140.316 17.28 140.4 17.304 ;
    END
  END actual_data[56]
  PIN actual_data[57]
    DIRECTION INPUT ;
    USE SIGNAL ;
    PORT
      LAYER M4 ;
        RECT  140.316 17.568 140.4 17.592 ;
    END
  END actual_data[57]
  PIN actual_data[58]
    DIRECTION INPUT ;
    USE SIGNAL ;
    PORT
      LAYER M4 ;
        RECT  140.316 17.856 140.4 17.88 ;
    END
  END actual_data[58]
  PIN actual_data[59]
    DIRECTION INPUT ;
    USE SIGNAL ;
    PORT
      LAYER M4 ;
        RECT  140.316 18.144 140.4 18.168 ;
    END
  END actual_data[59]
  PIN actual_data[5]
    DIRECTION INPUT ;
    USE SIGNAL ;
    PORT
      LAYER M4 ;
        RECT  140.316 2.592 140.4 2.616 ;
    END
  END actual_data[5]
  PIN actual_data[60]
    DIRECTION INPUT ;
    USE SIGNAL ;
    PORT
      LAYER M4 ;
        RECT  140.316 18.432 140.4 18.456 ;
    END
  END actual_data[60]
  PIN actual_data[61]
    DIRECTION INPUT ;
    USE SIGNAL ;
    PORT
      LAYER M4 ;
        RECT  140.316 18.72 140.4 18.744 ;
    END
  END actual_data[61]
  PIN actual_data[62]
    DIRECTION INPUT ;
    USE SIGNAL ;
    PORT
      LAYER M4 ;
        RECT  140.316 19.008 140.4 19.032 ;
    END
  END actual_data[62]
  PIN actual_data[63]
    DIRECTION INPUT ;
    USE SIGNAL ;
    PORT
      LAYER M4 ;
        RECT  140.316 19.296 140.4 19.32 ;
    END
  END actual_data[63]
  PIN actual_data[64]
    DIRECTION INPUT ;
    USE SIGNAL ;
    PORT
      LAYER M4 ;
        RECT  140.316 19.584 140.4 19.608 ;
    END
  END actual_data[64]
  PIN actual_data[65]
    DIRECTION INPUT ;
    USE SIGNAL ;
    PORT
      LAYER M4 ;
        RECT  140.316 19.872 140.4 19.896 ;
    END
  END actual_data[65]
  PIN actual_data[66]
    DIRECTION INPUT ;
    USE SIGNAL ;
    PORT
      LAYER M4 ;
        RECT  140.316 20.16 140.4 20.184 ;
    END
  END actual_data[66]
  PIN actual_data[67]
    DIRECTION INPUT ;
    USE SIGNAL ;
    PORT
      LAYER M4 ;
        RECT  140.316 20.448 140.4 20.472 ;
    END
  END actual_data[67]
  PIN actual_data[68]
    DIRECTION INPUT ;
    USE SIGNAL ;
    PORT
      LAYER M4 ;
        RECT  140.316 20.736 140.4 20.76 ;
    END
  END actual_data[68]
  PIN actual_data[69]
    DIRECTION INPUT ;
    USE SIGNAL ;
    PORT
      LAYER M4 ;
        RECT  140.316 21.024 140.4 21.048 ;
    END
  END actual_data[69]
  PIN actual_data[6]
    DIRECTION INPUT ;
    USE SIGNAL ;
    PORT
      LAYER M4 ;
        RECT  140.316 2.88 140.4 2.904 ;
    END
  END actual_data[6]
  PIN actual_data[70]
    DIRECTION INPUT ;
    USE SIGNAL ;
    PORT
      LAYER M4 ;
        RECT  140.316 21.312 140.4 21.336 ;
    END
  END actual_data[70]
  PIN actual_data[71]
    DIRECTION INPUT ;
    USE SIGNAL ;
    PORT
      LAYER M4 ;
        RECT  140.316 21.6 140.4 21.624 ;
    END
  END actual_data[71]
  PIN actual_data[72]
    DIRECTION INPUT ;
    USE SIGNAL ;
    PORT
      LAYER M4 ;
        RECT  140.316 21.888 140.4 21.912 ;
    END
  END actual_data[72]
  PIN actual_data[73]
    DIRECTION INPUT ;
    USE SIGNAL ;
    PORT
      LAYER M4 ;
        RECT  140.316 22.176 140.4 22.2 ;
    END
  END actual_data[73]
  PIN actual_data[74]
    DIRECTION INPUT ;
    USE SIGNAL ;
    PORT
      LAYER M4 ;
        RECT  140.316 22.464 140.4 22.488 ;
    END
  END actual_data[74]
  PIN actual_data[75]
    DIRECTION INPUT ;
    USE SIGNAL ;
    PORT
      LAYER M4 ;
        RECT  140.316 22.752 140.4 22.776 ;
    END
  END actual_data[75]
  PIN actual_data[76]
    DIRECTION INPUT ;
    USE SIGNAL ;
    PORT
      LAYER M4 ;
        RECT  140.316 23.04 140.4 23.064 ;
    END
  END actual_data[76]
  PIN actual_data[77]
    DIRECTION INPUT ;
    USE SIGNAL ;
    PORT
      LAYER M4 ;
        RECT  140.316 23.328 140.4 23.352 ;
    END
  END actual_data[77]
  PIN actual_data[78]
    DIRECTION INPUT ;
    USE SIGNAL ;
    PORT
      LAYER M4 ;
        RECT  140.316 23.616 140.4 23.64 ;
    END
  END actual_data[78]
  PIN actual_data[79]
    DIRECTION INPUT ;
    USE SIGNAL ;
    PORT
      LAYER M4 ;
        RECT  140.316 23.904 140.4 23.928 ;
    END
  END actual_data[79]
  PIN actual_data[7]
    DIRECTION INPUT ;
    USE SIGNAL ;
    PORT
      LAYER M4 ;
        RECT  140.316 3.168 140.4 3.192 ;
    END
  END actual_data[7]
  PIN actual_data[80]
    DIRECTION INPUT ;
    USE SIGNAL ;
    PORT
      LAYER M4 ;
        RECT  140.316 24.192 140.4 24.216 ;
    END
  END actual_data[80]
  PIN actual_data[81]
    DIRECTION INPUT ;
    USE SIGNAL ;
    PORT
      LAYER M4 ;
        RECT  140.316 24.48 140.4 24.504 ;
    END
  END actual_data[81]
  PIN actual_data[82]
    DIRECTION INPUT ;
    USE SIGNAL ;
    PORT
      LAYER M4 ;
        RECT  140.316 24.816 140.4 24.84 ;
    END
  END actual_data[82]
  PIN actual_data[83]
    DIRECTION INPUT ;
    USE SIGNAL ;
    PORT
      LAYER M4 ;
        RECT  140.316 25.104 140.4 25.128 ;
    END
  END actual_data[83]
  PIN actual_data[84]
    DIRECTION INPUT ;
    USE SIGNAL ;
    PORT
      LAYER M4 ;
        RECT  140.316 25.392 140.4 25.416 ;
    END
  END actual_data[84]
  PIN actual_data[85]
    DIRECTION INPUT ;
    USE SIGNAL ;
    PORT
      LAYER M4 ;
        RECT  140.316 25.68 140.4 25.704 ;
    END
  END actual_data[85]
  PIN actual_data[86]
    DIRECTION INPUT ;
    USE SIGNAL ;
    PORT
      LAYER M4 ;
        RECT  140.316 25.968 140.4 25.992 ;
    END
  END actual_data[86]
  PIN actual_data[87]
    DIRECTION INPUT ;
    USE SIGNAL ;
    PORT
      LAYER M4 ;
        RECT  140.316 26.256 140.4 26.28 ;
    END
  END actual_data[87]
  PIN actual_data[88]
    DIRECTION INPUT ;
    USE SIGNAL ;
    PORT
      LAYER M4 ;
        RECT  140.316 26.544 140.4 26.568 ;
    END
  END actual_data[88]
  PIN actual_data[89]
    DIRECTION INPUT ;
    USE SIGNAL ;
    PORT
      LAYER M4 ;
        RECT  140.316 26.832 140.4 26.856 ;
    END
  END actual_data[89]
  PIN actual_data[8]
    DIRECTION INPUT ;
    USE SIGNAL ;
    PORT
      LAYER M4 ;
        RECT  140.316 3.456 140.4 3.48 ;
    END
  END actual_data[8]
  PIN actual_data[90]
    DIRECTION INPUT ;
    USE SIGNAL ;
    PORT
      LAYER M4 ;
        RECT  140.316 27.12 140.4 27.144 ;
    END
  END actual_data[90]
  PIN actual_data[91]
    DIRECTION INPUT ;
    USE SIGNAL ;
    PORT
      LAYER M4 ;
        RECT  140.316 27.408 140.4 27.432 ;
    END
  END actual_data[91]
  PIN actual_data[92]
    DIRECTION INPUT ;
    USE SIGNAL ;
    PORT
      LAYER M4 ;
        RECT  140.316 27.696 140.4 27.72 ;
    END
  END actual_data[92]
  PIN actual_data[93]
    DIRECTION INPUT ;
    USE SIGNAL ;
    PORT
      LAYER M4 ;
        RECT  140.316 27.984 140.4 28.008 ;
    END
  END actual_data[93]
  PIN actual_data[94]
    DIRECTION INPUT ;
    USE SIGNAL ;
    PORT
      LAYER M4 ;
        RECT  140.316 28.272 140.4 28.296 ;
    END
  END actual_data[94]
  PIN actual_data[95]
    DIRECTION INPUT ;
    USE SIGNAL ;
    PORT
      LAYER M4 ;
        RECT  140.316 28.56 140.4 28.584 ;
    END
  END actual_data[95]
  PIN actual_data[96]
    DIRECTION INPUT ;
    USE SIGNAL ;
    PORT
      LAYER M4 ;
        RECT  140.316 28.848 140.4 28.872 ;
    END
  END actual_data[96]
  PIN actual_data[97]
    DIRECTION INPUT ;
    USE SIGNAL ;
    PORT
      LAYER M4 ;
        RECT  140.316 29.136 140.4 29.16 ;
    END
  END actual_data[97]
  PIN actual_data[98]
    DIRECTION INPUT ;
    USE SIGNAL ;
    PORT
      LAYER M4 ;
        RECT  140.316 29.424 140.4 29.448 ;
    END
  END actual_data[98]
  PIN actual_data[99]
    DIRECTION INPUT ;
    USE SIGNAL ;
    PORT
      LAYER M4 ;
        RECT  140.316 29.712 140.4 29.736 ;
    END
  END actual_data[99]
  PIN actual_data[9]
    DIRECTION INPUT ;
    USE SIGNAL ;
    PORT
      LAYER M4 ;
        RECT  140.316 3.744 140.4 3.768 ;
    END
  END actual_data[9]
  PIN actual_epoch[0]
    DIRECTION INPUT ;
    USE SIGNAL ;
    PORT
      LAYER M4 ;
        RECT  140.316 74.976 140.4 75 ;
    END
  END actual_epoch[0]
  PIN actual_epoch[10]
    DIRECTION INPUT ;
    USE SIGNAL ;
    PORT
      LAYER M4 ;
        RECT  140.316 77.904 140.4 77.928 ;
    END
  END actual_epoch[10]
  PIN actual_epoch[11]
    DIRECTION INPUT ;
    USE SIGNAL ;
    PORT
      LAYER M4 ;
        RECT  140.316 78.192 140.4 78.216 ;
    END
  END actual_epoch[11]
  PIN actual_epoch[12]
    DIRECTION INPUT ;
    USE SIGNAL ;
    PORT
      LAYER M4 ;
        RECT  140.316 78.48 140.4 78.504 ;
    END
  END actual_epoch[12]
  PIN actual_epoch[13]
    DIRECTION INPUT ;
    USE SIGNAL ;
    PORT
      LAYER M4 ;
        RECT  140.316 78.768 140.4 78.792 ;
    END
  END actual_epoch[13]
  PIN actual_epoch[14]
    DIRECTION INPUT ;
    USE SIGNAL ;
    PORT
      LAYER M4 ;
        RECT  140.316 79.056 140.4 79.08 ;
    END
  END actual_epoch[14]
  PIN actual_epoch[15]
    DIRECTION INPUT ;
    USE SIGNAL ;
    PORT
      LAYER M4 ;
        RECT  140.316 79.344 140.4 79.368 ;
    END
  END actual_epoch[15]
  PIN actual_epoch[1]
    DIRECTION INPUT ;
    USE SIGNAL ;
    PORT
      LAYER M4 ;
        RECT  140.316 75.264 140.4 75.288 ;
    END
  END actual_epoch[1]
  PIN actual_epoch[2]
    DIRECTION INPUT ;
    USE SIGNAL ;
    PORT
      LAYER M4 ;
        RECT  140.316 75.552 140.4 75.576 ;
    END
  END actual_epoch[2]
  PIN actual_epoch[3]
    DIRECTION INPUT ;
    USE SIGNAL ;
    PORT
      LAYER M4 ;
        RECT  140.316 75.84 140.4 75.864 ;
    END
  END actual_epoch[3]
  PIN actual_epoch[4]
    DIRECTION INPUT ;
    USE SIGNAL ;
    PORT
      LAYER M4 ;
        RECT  140.316 76.128 140.4 76.152 ;
    END
  END actual_epoch[4]
  PIN actual_epoch[5]
    DIRECTION INPUT ;
    USE SIGNAL ;
    PORT
      LAYER M4 ;
        RECT  140.316 76.416 140.4 76.44 ;
    END
  END actual_epoch[5]
  PIN actual_epoch[6]
    DIRECTION INPUT ;
    USE SIGNAL ;
    PORT
      LAYER M4 ;
        RECT  140.316 76.752 140.4 76.776 ;
    END
  END actual_epoch[6]
  PIN actual_epoch[7]
    DIRECTION INPUT ;
    USE SIGNAL ;
    PORT
      LAYER M4 ;
        RECT  140.316 77.04 140.4 77.064 ;
    END
  END actual_epoch[7]
  PIN actual_epoch[8]
    DIRECTION INPUT ;
    USE SIGNAL ;
    PORT
      LAYER M4 ;
        RECT  140.316 77.328 140.4 77.352 ;
    END
  END actual_epoch[8]
  PIN actual_epoch[9]
    DIRECTION INPUT ;
    USE SIGNAL ;
    PORT
      LAYER M4 ;
        RECT  140.316 77.616 140.4 77.64 ;
    END
  END actual_epoch[9]
  PIN actual_layer[0]
    DIRECTION INPUT ;
    USE SIGNAL ;
    PORT
      LAYER M4 ;
        RECT  140.316 79.632 140.4 79.656 ;
    END
  END actual_layer[0]
  PIN actual_layer[1]
    DIRECTION INPUT ;
    USE SIGNAL ;
    PORT
      LAYER M4 ;
        RECT  140.316 79.92 140.4 79.944 ;
    END
  END actual_layer[1]
  PIN actual_layer[2]
    DIRECTION INPUT ;
    USE SIGNAL ;
    PORT
      LAYER M4 ;
        RECT  140.316 80.208 140.4 80.232 ;
    END
  END actual_layer[2]
  PIN actual_layer[3]
    DIRECTION INPUT ;
    USE SIGNAL ;
    PORT
      LAYER M4 ;
        RECT  140.316 80.496 140.4 80.52 ;
    END
  END actual_layer[3]
  PIN actual_layer[4]
    DIRECTION INPUT ;
    USE SIGNAL ;
    PORT
      LAYER M4 ;
        RECT  140.316 80.784 140.4 80.808 ;
    END
  END actual_layer[4]
  PIN actual_layer[5]
    DIRECTION INPUT ;
    USE SIGNAL ;
    PORT
      LAYER M4 ;
        RECT  140.316 81.072 140.4 81.096 ;
    END
  END actual_layer[5]
  PIN actual_sector[0]
    DIRECTION INPUT ;
    USE SIGNAL ;
    PORT
      LAYER M4 ;
        RECT  140.316 81.36 140.4 81.384 ;
    END
  END actual_sector[0]
  PIN actual_sector[1]
    DIRECTION INPUT ;
    USE SIGNAL ;
    PORT
      LAYER M4 ;
        RECT  140.316 81.648 140.4 81.672 ;
    END
  END actual_sector[1]
  PIN actual_sector[2]
    DIRECTION INPUT ;
    USE SIGNAL ;
    PORT
      LAYER M4 ;
        RECT  140.316 81.936 140.4 81.96 ;
    END
  END actual_sector[2]
  PIN actual_sector[3]
    DIRECTION INPUT ;
    USE SIGNAL ;
    PORT
      LAYER M4 ;
        RECT  140.316 82.224 140.4 82.248 ;
    END
  END actual_sector[3]
  PIN actual_sector[4]
    DIRECTION INPUT ;
    USE SIGNAL ;
    PORT
      LAYER M4 ;
        RECT  140.316 82.512 140.4 82.536 ;
    END
  END actual_sector[4]
  PIN actual_sector[5]
    DIRECTION INPUT ;
    USE SIGNAL ;
    PORT
      LAYER M4 ;
        RECT  140.316 82.8 140.4 82.824 ;
    END
  END actual_sector[5]
  PIN actual_sector[6]
    DIRECTION INPUT ;
    USE SIGNAL ;
    PORT
      LAYER M4 ;
        RECT  140.316 83.088 140.4 83.112 ;
    END
  END actual_sector[6]
  PIN actual_sector[7]
    DIRECTION INPUT ;
    USE SIGNAL ;
    PORT
      LAYER M4 ;
        RECT  140.316 83.376 140.4 83.4 ;
    END
  END actual_sector[7]
  PIN actual_sector[8]
    DIRECTION INPUT ;
    USE SIGNAL ;
    PORT
      LAYER M4 ;
        RECT  140.316 83.664 140.4 83.688 ;
    END
  END actual_sector[8]
  PIN actual_sector[9]
    DIRECTION INPUT ;
    USE SIGNAL ;
    PORT
      LAYER M4 ;
        RECT  140.316 83.952 140.4 83.976 ;
    END
  END actual_sector[9]
  PIN actual_valid
    DIRECTION INPUT ;
    USE SIGNAL ;
    PORT
      LAYER M4 ;
        RECT  140.316 84.24 140.4 84.264 ;
    END
  END actual_valid
  PIN arm
    DIRECTION INPUT ;
    USE SIGNAL ;
    PORT
      LAYER M3 ;
        RECT  1.656 88.522 1.674 88.56 ;
    END
    PORT
      LAYER M3 ;
        RECT  1.656 86.717 1.674 88.541 ;
    END
  END arm
  PIN cfg_group[0]
    DIRECTION INPUT ;
    USE SIGNAL ;
    PORT
      LAYER M5 ;
        RECT  2.928 88.476 2.952 88.56 ;
    END
    PORT
      LAYER M5 ;
        RECT  2.928 86.423 2.952 88.528 ;
    END
  END cfg_group[0]
  PIN cfg_group[1]
    DIRECTION INPUT ;
    USE SIGNAL ;
    PORT
      LAYER M3 ;
        RECT  4.248 88.522 4.266 88.56 ;
    END
    PORT
      LAYER M3 ;
        RECT  4.248 88.459 4.266 88.541 ;
    END
  END cfg_group[1]
  PIN cfg_group[2]
    DIRECTION INPUT ;
    USE SIGNAL ;
    PORT
      LAYER M5 ;
        RECT  5.568 88.476 5.592 88.56 ;
    END
    PORT
      LAYER M5 ;
        RECT  5.568 86.293 5.592 88.528 ;
    END
  END cfg_group[2]
  PIN cfg_stack[0]
    DIRECTION INPUT ;
    USE SIGNAL ;
    PORT
      LAYER M3 ;
        RECT  6.876 88.522 6.894 88.56 ;
    END
    PORT
      LAYER M3 ;
        RECT  6.876 86.369 6.894 88.541 ;
    END
  END cfg_stack[0]
  PIN cfg_stack[1]
    DIRECTION INPUT ;
    USE SIGNAL ;
    PORT
      LAYER M5 ;
        RECT  8.16 88.476 8.184 88.56 ;
    END
    PORT
      LAYER M5 ;
        RECT  8.16 87.445 8.184 88.528 ;
    END
  END cfg_stack[1]
  PIN ck
    DIRECTION INPUT ;
    USE SIGNAL ;
    PORT
      LAYER M3 ;
        RECT  70.2 88.522 70.218 88.56 ;
    END
  END ck
  PIN epoch[0]
    DIRECTION INPUT ;
    USE SIGNAL ;
    PORT
      LAYER M3 ;
        RECT  9.468 88.522 9.486 88.56 ;
    END
    PORT
      LAYER M3 ;
        RECT  9.468 86.261 9.486 88.541 ;
    END
  END epoch[0]
  PIN epoch[10]
    DIRECTION INPUT ;
    USE SIGNAL ;
    PORT
      LAYER M3 ;
        RECT  22.536 88.522 22.554 88.56 ;
    END
    PORT
      LAYER M3 ;
        RECT  22.536 86.684 22.554 88.541 ;
    END
  END epoch[10]
  PIN epoch[11]
    DIRECTION INPUT ;
    USE SIGNAL ;
    PORT
      LAYER M5 ;
        RECT  23.856 88.476 23.88 88.56 ;
    END
    PORT
      LAYER M5 ;
        RECT  23.856 87.157 23.88 88.528 ;
    END
  END epoch[11]
  PIN epoch[12]
    DIRECTION INPUT ;
    USE SIGNAL ;
    PORT
      LAYER M3 ;
        RECT  25.164 88.522 25.182 88.56 ;
    END
    PORT
      LAYER M3 ;
        RECT  25.164 86.305 25.182 88.541 ;
    END
  END epoch[12]
  PIN epoch[13]
    DIRECTION INPUT ;
    USE SIGNAL ;
    PORT
      LAYER M5 ;
        RECT  26.448 88.476 26.472 88.56 ;
    END
    PORT
      LAYER M5 ;
        RECT  26.448 86.629 26.472 88.528 ;
    END
  END epoch[13]
  PIN epoch[14]
    DIRECTION INPUT ;
    USE SIGNAL ;
    PORT
      LAYER M3 ;
        RECT  27.756 88.522 27.774 88.56 ;
    END
    PORT
      LAYER M3 ;
        RECT  27.756 86.225 27.774 88.541 ;
    END
  END epoch[14]
  PIN epoch[15]
    DIRECTION INPUT ;
    USE SIGNAL ;
    PORT
      LAYER M5 ;
        RECT  29.04 88.476 29.064 88.56 ;
    END
    PORT
      LAYER M5 ;
        RECT  29.04 87.157 29.064 88.528 ;
    END
  END epoch[15]
  PIN epoch[1]
    DIRECTION INPUT ;
    USE SIGNAL ;
    PORT
      LAYER M5 ;
        RECT  10.8 88.476 10.824 88.56 ;
    END
    PORT
      LAYER M5 ;
        RECT  10.8 87.157 10.824 88.528 ;
    END
  END epoch[1]
  PIN epoch[2]
    DIRECTION INPUT ;
    USE SIGNAL ;
    PORT
      LAYER M3 ;
        RECT  12.096 88.522 12.114 88.56 ;
    END
    PORT
      LAYER M3 ;
        RECT  12.096 86.225 12.114 88.541 ;
    END
  END epoch[2]
  PIN epoch[3]
    DIRECTION INPUT ;
    USE SIGNAL ;
    PORT
      LAYER M5 ;
        RECT  13.392 88.476 13.416 88.56 ;
    END
    PORT
      LAYER M5 ;
        RECT  13.392 88.451 13.416 88.528 ;
    END
  END epoch[3]
  PIN epoch[4]
    DIRECTION INPUT ;
    USE SIGNAL ;
    PORT
      LAYER M3 ;
        RECT  14.688 88.522 14.706 88.56 ;
    END
    PORT
      LAYER M3 ;
        RECT  14.688 86.225 14.706 88.541 ;
    END
  END epoch[4]
  PIN epoch[5]
    DIRECTION INPUT ;
    USE SIGNAL ;
    PORT
      LAYER M5 ;
        RECT  15.984 88.476 16.008 88.56 ;
    END
    PORT
      LAYER M5 ;
        RECT  15.984 88.451 16.008 88.528 ;
    END
  END epoch[5]
  PIN epoch[6]
    DIRECTION INPUT ;
    USE SIGNAL ;
    PORT
      LAYER M3 ;
        RECT  17.316 88.522 17.334 88.56 ;
    END
    PORT
      LAYER M3 ;
        RECT  17.316 86.684 17.334 88.541 ;
    END
  END epoch[6]
  PIN epoch[7]
    DIRECTION INPUT ;
    USE SIGNAL ;
    PORT
      LAYER M5 ;
        RECT  18.624 88.476 18.648 88.56 ;
    END
    PORT
      LAYER M5 ;
        RECT  18.624 86.423 18.648 88.528 ;
    END
  END epoch[7]
  PIN epoch[8]
    DIRECTION INPUT ;
    USE SIGNAL ;
    PORT
      LAYER M3 ;
        RECT  19.908 88.522 19.926 88.56 ;
    END
    PORT
      LAYER M3 ;
        RECT  19.908 86.189 19.926 88.541 ;
    END
  END epoch[8]
  PIN epoch[9]
    DIRECTION INPUT ;
    USE SIGNAL ;
    PORT
      LAYER M5 ;
        RECT  21.216 88.476 21.24 88.56 ;
    END
    PORT
      LAYER M5 ;
        RECT  21.216 88.451 21.24 88.528 ;
    END
  END epoch[9]
  PIN expected_put
    DIRECTION INPUT ;
    USE SIGNAL ;
    PORT
      LAYER M4 ;
        RECT  140.316 84.528 140.4 84.552 ;
    END
  END expected_put
  PIN expected_sector[0]
    DIRECTION INPUT ;
    USE SIGNAL ;
    PORT
      LAYER M4 ;
        RECT  140.316 84.816 140.4 84.84 ;
    END
  END expected_sector[0]
  PIN expected_sector[1]
    DIRECTION INPUT ;
    USE SIGNAL ;
    PORT
      LAYER M4 ;
        RECT  140.316 85.104 140.4 85.128 ;
    END
  END expected_sector[1]
  PIN expected_sector[2]
    DIRECTION INPUT ;
    USE SIGNAL ;
    PORT
      LAYER M4 ;
        RECT  140.316 85.392 140.4 85.416 ;
    END
  END expected_sector[2]
  PIN expected_sector[3]
    DIRECTION INPUT ;
    USE SIGNAL ;
    PORT
      LAYER M4 ;
        RECT  140.316 85.68 140.4 85.704 ;
    END
  END expected_sector[3]
  PIN expected_sector[4]
    DIRECTION INPUT ;
    USE SIGNAL ;
    PORT
      LAYER M4 ;
        RECT  140.316 85.968 140.4 85.992 ;
    END
  END expected_sector[4]
  PIN expected_sector[5]
    DIRECTION INPUT ;
    USE SIGNAL ;
    PORT
      LAYER M4 ;
        RECT  140.316 86.256 140.4 86.28 ;
    END
  END expected_sector[5]
  PIN expected_sector[6]
    DIRECTION INPUT ;
    USE SIGNAL ;
    PORT
      LAYER M4 ;
        RECT  140.316 86.544 140.4 86.568 ;
    END
  END expected_sector[6]
  PIN expected_sector[7]
    DIRECTION INPUT ;
    USE SIGNAL ;
    PORT
      LAYER M4 ;
        RECT  140.316 86.832 140.4 86.856 ;
    END
  END expected_sector[7]
  PIN expected_sector[8]
    DIRECTION INPUT ;
    USE SIGNAL ;
    PORT
      LAYER M4 ;
        RECT  140.316 87.12 140.4 87.144 ;
    END
  END expected_sector[8]
  PIN expected_sector[9]
    DIRECTION INPUT ;
    USE SIGNAL ;
    PORT
      LAYER M4 ;
        RECT  140.316 87.408 140.4 87.432 ;
    END
  END expected_sector[9]
  PIN fault
    DIRECTION OUTPUT ;
    USE SIGNAL ;
    PORT
      LAYER M3 ;
        RECT  30.384 88.522 30.402 88.56 ;
    END
    PORT
      LAYER M3 ;
        RECT  30.384 86.225 30.402 88.541 ;
    END
  END fault
  PIN get
    DIRECTION INPUT ;
    USE SIGNAL ;
    PORT
      LAYER M5 ;
        RECT  31.68 88.476 31.704 88.56 ;
    END
    PORT
      LAYER M5 ;
        RECT  31.68 88.451 31.704 88.528 ;
    END
  END get
  PIN get_epoch[0]
    DIRECTION INPUT ;
    USE SIGNAL ;
    PORT
      LAYER M3 ;
        RECT  32.976 88.522 32.994 88.56 ;
    END
    PORT
      LAYER M3 ;
        RECT  32.976 86.305 32.994 88.541 ;
    END
  END get_epoch[0]
  PIN get_epoch[10]
    DIRECTION INPUT ;
    USE SIGNAL ;
    PORT
      LAYER M3 ;
        RECT  46.044 88.522 46.062 88.56 ;
    END
    PORT
      LAYER M3 ;
        RECT  46.044 86.417 46.062 88.541 ;
    END
  END get_epoch[10]
  PIN get_epoch[11]
    DIRECTION INPUT ;
    USE SIGNAL ;
    PORT
      LAYER M5 ;
        RECT  47.328 88.476 47.352 88.56 ;
    END
    PORT
      LAYER M5 ;
        RECT  47.328 86.581 47.352 88.528 ;
    END
  END get_epoch[11]
  PIN get_epoch[12]
    DIRECTION INPUT ;
    USE SIGNAL ;
    PORT
      LAYER M3 ;
        RECT  48.636 88.522 48.654 88.56 ;
    END
    PORT
      LAYER M3 ;
        RECT  48.636 86.261 48.654 88.541 ;
    END
  END get_epoch[12]
  PIN get_epoch[13]
    DIRECTION INPUT ;
    USE SIGNAL ;
    PORT
      LAYER M5 ;
        RECT  49.968 88.476 49.992 88.56 ;
    END
    PORT
      LAYER M5 ;
        RECT  49.968 88.451 49.992 88.528 ;
    END
  END get_epoch[13]
  PIN get_epoch[14]
    DIRECTION INPUT ;
    USE SIGNAL ;
    PORT
      LAYER M3 ;
        RECT  51.264 88.522 51.282 88.56 ;
    END
    PORT
      LAYER M3 ;
        RECT  51.264 86.684 51.282 88.541 ;
    END
  END get_epoch[14]
  PIN get_epoch[15]
    DIRECTION INPUT ;
    USE SIGNAL ;
    PORT
      LAYER M5 ;
        RECT  52.56 88.476 52.584 88.56 ;
    END
    PORT
      LAYER M5 ;
        RECT  52.56 88.451 52.584 88.528 ;
    END
  END get_epoch[15]
  PIN get_epoch[1]
    DIRECTION INPUT ;
    USE SIGNAL ;
    PORT
      LAYER M5 ;
        RECT  34.272 88.476 34.296 88.56 ;
    END
    PORT
      LAYER M5 ;
        RECT  34.272 88.451 34.296 88.528 ;
    END
  END get_epoch[1]
  PIN get_epoch[2]
    DIRECTION INPUT ;
    USE SIGNAL ;
    PORT
      LAYER M3 ;
        RECT  35.604 88.522 35.622 88.56 ;
    END
    PORT
      LAYER M3 ;
        RECT  35.604 86.417 35.622 88.541 ;
    END
  END get_epoch[2]
  PIN get_epoch[3]
    DIRECTION INPUT ;
    USE SIGNAL ;
    PORT
      LAYER M5 ;
        RECT  36.912 88.476 36.936 88.56 ;
    END
    PORT
      LAYER M5 ;
        RECT  36.912 88.451 36.936 88.528 ;
    END
  END get_epoch[3]
  PIN get_epoch[4]
    DIRECTION INPUT ;
    USE SIGNAL ;
    PORT
      LAYER M3 ;
        RECT  38.196 88.522 38.214 88.56 ;
    END
    PORT
      LAYER M3 ;
        RECT  38.196 86.333 38.214 88.541 ;
    END
  END get_epoch[4]
  PIN get_epoch[5]
    DIRECTION INPUT ;
    USE SIGNAL ;
    PORT
      LAYER M5 ;
        RECT  39.504 88.476 39.528 88.56 ;
    END
    PORT
      LAYER M5 ;
        RECT  39.504 87.781 39.528 88.528 ;
    END
  END get_epoch[5]
  PIN get_epoch[6]
    DIRECTION INPUT ;
    USE SIGNAL ;
    PORT
      LAYER M3 ;
        RECT  40.824 88.522 40.842 88.56 ;
    END
    PORT
      LAYER M3 ;
        RECT  40.824 86.684 40.842 88.541 ;
    END
  END get_epoch[6]
  PIN get_epoch[7]
    DIRECTION INPUT ;
    USE SIGNAL ;
    PORT
      LAYER M5 ;
        RECT  42.096 88.476 42.12 88.56 ;
    END
    PORT
      LAYER M5 ;
        RECT  42.096 86.581 42.12 88.528 ;
    END
  END get_epoch[7]
  PIN get_epoch[8]
    DIRECTION INPUT ;
    USE SIGNAL ;
    PORT
      LAYER M3 ;
        RECT  43.416 88.522 43.434 88.56 ;
    END
    PORT
      LAYER M3 ;
        RECT  43.416 86.225 43.434 88.541 ;
    END
  END get_epoch[8]
  PIN get_epoch[9]
    DIRECTION INPUT ;
    USE SIGNAL ;
    PORT
      LAYER M5 ;
        RECT  44.736 88.476 44.76 88.56 ;
    END
    PORT
      LAYER M5 ;
        RECT  44.736 86.581 44.76 88.528 ;
    END
  END get_epoch[9]
  PIN get_layer[0]
    DIRECTION INPUT ;
    USE SIGNAL ;
    PORT
      LAYER M3 ;
        RECT  53.856 88.522 53.874 88.56 ;
    END
    PORT
      LAYER M3 ;
        RECT  53.856 86.684 53.874 88.541 ;
    END
  END get_layer[0]
  PIN get_layer[1]
    DIRECTION INPUT ;
    USE SIGNAL ;
    PORT
      LAYER M5 ;
        RECT  55.152 88.476 55.176 88.56 ;
    END
    PORT
      LAYER M5 ;
        RECT  55.152 87.157 55.176 88.528 ;
    END
  END get_layer[1]
  PIN get_layer[2]
    DIRECTION INPUT ;
    USE SIGNAL ;
    PORT
      LAYER M3 ;
        RECT  56.484 88.522 56.502 88.56 ;
    END
    PORT
      LAYER M3 ;
        RECT  56.484 86.684 56.502 88.541 ;
    END
  END get_layer[2]
  PIN get_layer[3]
    DIRECTION INPUT ;
    USE SIGNAL ;
    PORT
      LAYER M5 ;
        RECT  57.792 88.476 57.816 88.56 ;
    END
    PORT
      LAYER M5 ;
        RECT  57.792 87.781 57.816 88.528 ;
    END
  END get_layer[3]
  PIN get_layer[4]
    DIRECTION INPUT ;
    USE SIGNAL ;
    PORT
      LAYER M3 ;
        RECT  59.076 88.522 59.094 88.56 ;
    END
    PORT
      LAYER M3 ;
        RECT  59.076 86.305 59.094 88.541 ;
    END
  END get_layer[4]
  PIN get_layer[5]
    DIRECTION INPUT ;
    USE SIGNAL ;
    PORT
      LAYER M5 ;
        RECT  60.384 88.476 60.408 88.56 ;
    END
    PORT
      LAYER M5 ;
        RECT  60.384 86.341 60.408 88.528 ;
    END
  END get_layer[5]
  PIN get_t[0]
    DIRECTION INPUT ;
    USE SIGNAL ;
    PORT
      LAYER M3 ;
        RECT  61.704 88.522 61.722 88.56 ;
    END
    PORT
      LAYER M3 ;
        RECT  61.704 86.417 61.722 88.541 ;
    END
  END get_t[0]
  PIN get_t[10]
    DIRECTION INPUT ;
    USE SIGNAL ;
    PORT
      LAYER M3 ;
        RECT  74.772 88.522 74.79 88.56 ;
    END
    PORT
      LAYER M3 ;
        RECT  74.772 86.225 74.79 88.541 ;
    END
  END get_t[10]
  PIN get_t[11]
    DIRECTION INPUT ;
    USE SIGNAL ;
    PORT
      LAYER M5 ;
        RECT  76.08 88.476 76.104 88.56 ;
    END
    PORT
      LAYER M5 ;
        RECT  76.08 88.451 76.104 88.528 ;
    END
  END get_t[11]
  PIN get_t[12]
    DIRECTION INPUT ;
    USE SIGNAL ;
    PORT
      LAYER M3 ;
        RECT  77.364 88.522 77.382 88.56 ;
    END
    PORT
      LAYER M3 ;
        RECT  77.364 86.417 77.382 88.541 ;
    END
  END get_t[12]
  PIN get_t[13]
    DIRECTION INPUT ;
    USE SIGNAL ;
    PORT
      LAYER M5 ;
        RECT  78.672 88.476 78.696 88.56 ;
    END
    PORT
      LAYER M5 ;
        RECT  78.672 88.405 78.696 88.528 ;
    END
  END get_t[13]
  PIN get_t[1]
    DIRECTION INPUT ;
    USE SIGNAL ;
    PORT
      LAYER M5 ;
        RECT  63.024 88.476 63.048 88.56 ;
    END
    PORT
      LAYER M5 ;
        RECT  63.024 87.157 63.048 88.528 ;
    END
  END get_t[1]
  PIN get_t[2]
    DIRECTION INPUT ;
    USE SIGNAL ;
    PORT
      LAYER M3 ;
        RECT  64.332 88.522 64.35 88.56 ;
    END
    PORT
      LAYER M3 ;
        RECT  64.332 86.729 64.35 88.541 ;
    END
  END get_t[2]
  PIN get_t[3]
    DIRECTION INPUT ;
    USE SIGNAL ;
    PORT
      LAYER M5 ;
        RECT  65.616 88.476 65.64 88.56 ;
    END
    PORT
      LAYER M5 ;
        RECT  65.616 86.581 65.64 88.528 ;
    END
  END get_t[3]
  PIN get_t[4]
    DIRECTION INPUT ;
    USE SIGNAL ;
    PORT
      LAYER M3 ;
        RECT  66.924 88.522 66.942 88.56 ;
    END
    PORT
      LAYER M3 ;
        RECT  66.924 86.417 66.942 88.541 ;
    END
  END get_t[4]
  PIN get_t[5]
    DIRECTION INPUT ;
    USE SIGNAL ;
    PORT
      LAYER M5 ;
        RECT  68.208 88.476 68.232 88.56 ;
    END
    PORT
      LAYER M5 ;
        RECT  68.208 86.581 68.232 88.528 ;
    END
  END get_t[5]
  PIN get_t[6]
    DIRECTION INPUT ;
    USE SIGNAL ;
    PORT
      LAYER M3 ;
        RECT  69.552 88.522 69.57 88.56 ;
    END
  END get_t[6]
  PIN get_t[7]
    DIRECTION INPUT ;
    USE SIGNAL ;
    PORT
      LAYER M5 ;
        RECT  70.848 88.476 70.872 88.56 ;
    END
    PORT
      LAYER M5 ;
        RECT  70.224 87.781 70.872 88.499 ;
    END
    PORT
      LAYER M5 ;
        RECT  70.848 88.499 70.872 88.528 ;
    END
  END get_t[7]
  PIN get_t[8]
    DIRECTION INPUT ;
    USE SIGNAL ;
    PORT
      LAYER M3 ;
        RECT  72.144 88.522 72.162 88.56 ;
    END
    PORT
      LAYER M3 ;
        RECT  72.144 86.729 72.162 88.541 ;
    END
  END get_t[8]
  PIN get_t[9]
    DIRECTION INPUT ;
    USE SIGNAL ;
    PORT
      LAYER M5 ;
        RECT  73.44 88.476 73.464 88.56 ;
    END
    PORT
      LAYER M5 ;
        RECT  73.44 88.451 73.464 88.528 ;
    END
  END get_t[9]
  PIN get_v
    DIRECTION INPUT ;
    USE SIGNAL ;
    PORT
      LAYER M3 ;
        RECT  79.992 88.522 80.01 88.56 ;
    END
    PORT
      LAYER M3 ;
        RECT  79.992 86.369 80.01 88.541 ;
    END
  END get_v
  PIN layer[0]
    DIRECTION INPUT ;
    USE SIGNAL ;
    PORT
      LAYER M5 ;
        RECT  81.264 88.476 81.288 88.56 ;
    END
    PORT
      LAYER M5 ;
        RECT  81.264 88.451 81.288 88.528 ;
    END
  END layer[0]
  PIN layer[1]
    DIRECTION INPUT ;
    USE SIGNAL ;
    PORT
      LAYER M3 ;
        RECT  82.584 88.522 82.602 88.56 ;
    END
    PORT
      LAYER M3 ;
        RECT  82.584 86.729 82.602 88.541 ;
    END
  END layer[1]
  PIN layer[2]
    DIRECTION INPUT ;
    USE SIGNAL ;
    PORT
      LAYER M5 ;
        RECT  83.904 88.476 83.928 88.56 ;
    END
    PORT
      LAYER M5 ;
        RECT  83.904 87.781 83.928 88.528 ;
    END
  END layer[2]
  PIN layer[3]
    DIRECTION INPUT ;
    USE SIGNAL ;
    PORT
      LAYER M3 ;
        RECT  85.212 88.522 85.23 88.56 ;
    END
    PORT
      LAYER M3 ;
        RECT  85.212 86.225 85.23 88.541 ;
    END
  END layer[3]
  PIN layer[4]
    DIRECTION INPUT ;
    USE SIGNAL ;
    PORT
      LAYER M5 ;
        RECT  86.496 88.476 86.52 88.56 ;
    END
    PORT
      LAYER M5 ;
        RECT  86.496 86.581 86.52 88.528 ;
    END
  END layer[4]
  PIN layer[5]
    DIRECTION INPUT ;
    USE SIGNAL ;
    PORT
      LAYER M3 ;
        RECT  87.804 88.522 87.822 88.56 ;
    END
    PORT
      LAYER M3 ;
        RECT  87.804 86.225 87.822 88.541 ;
    END
  END layer[5]
  PIN out_epoch[0]
    DIRECTION OUTPUT ;
    USE SIGNAL ;
    PORT
      LAYER M5 ;
        RECT  89.136 88.476 89.16 88.56 ;
    END
    PORT
      LAYER M5 ;
        RECT  89.136 87.157 89.16 88.528 ;
    END
  END out_epoch[0]
  PIN out_epoch[10]
    DIRECTION OUTPUT ;
    USE SIGNAL ;
    PORT
      LAYER M5 ;
        RECT  102.192 88.476 102.216 88.56 ;
    END
    PORT
      LAYER M5 ;
        RECT  102.192 86.629 102.216 88.528 ;
    END
  END out_epoch[10]
  PIN out_epoch[11]
    DIRECTION OUTPUT ;
    USE SIGNAL ;
    PORT
      LAYER M3 ;
        RECT  103.5 88.522 103.518 88.56 ;
    END
    PORT
      LAYER M3 ;
        RECT  103.5 86.369 103.518 88.541 ;
    END
  END out_epoch[11]
  PIN out_epoch[12]
    DIRECTION OUTPUT ;
    USE SIGNAL ;
    PORT
      LAYER M5 ;
        RECT  104.784 88.476 104.808 88.56 ;
    END
    PORT
      LAYER M5 ;
        RECT  104.784 87.157 104.808 88.528 ;
    END
  END out_epoch[12]
  PIN out_epoch[13]
    DIRECTION OUTPUT ;
    USE SIGNAL ;
    PORT
      LAYER M3 ;
        RECT  106.092 88.522 106.11 88.56 ;
    END
    PORT
      LAYER M3 ;
        RECT  106.092 86.684 106.11 88.541 ;
    END
  END out_epoch[13]
  PIN out_epoch[14]
    DIRECTION OUTPUT ;
    USE SIGNAL ;
    PORT
      LAYER M5 ;
        RECT  107.376 88.476 107.4 88.56 ;
    END
    PORT
      LAYER M5 ;
        RECT  107.376 86.629 107.4 88.528 ;
    END
  END out_epoch[14]
  PIN out_epoch[15]
    DIRECTION OUTPUT ;
    USE SIGNAL ;
    PORT
      LAYER M3 ;
        RECT  108.72 88.522 108.738 88.56 ;
    END
    PORT
      LAYER M3 ;
        RECT  108.72 86.027 108.738 88.541 ;
    END
  END out_epoch[15]
  PIN out_epoch[1]
    DIRECTION OUTPUT ;
    USE SIGNAL ;
    PORT
      LAYER M3 ;
        RECT  90.432 88.522 90.45 88.56 ;
    END
    PORT
      LAYER M3 ;
        RECT  90.432 88.501 90.522 88.529 ;
    END
    PORT
      LAYER M3 ;
        RECT  90.432 88.529 90.45 88.541 ;
    END
  END out_epoch[1]
  PIN out_epoch[2]
    DIRECTION OUTPUT ;
    USE SIGNAL ;
    PORT
      LAYER M5 ;
        RECT  91.728 88.476 91.752 88.56 ;
    END
    PORT
      LAYER M5 ;
        RECT  91.728 86.581 91.752 88.528 ;
    END
  END out_epoch[2]
  PIN out_epoch[3]
    DIRECTION OUTPUT ;
    USE SIGNAL ;
    PORT
      LAYER M3 ;
        RECT  93.024 88.522 93.042 88.56 ;
    END
    PORT
      LAYER M3 ;
        RECT  93.024 86.729 93.042 88.541 ;
    END
  END out_epoch[3]
  PIN out_epoch[4]
    DIRECTION OUTPUT ;
    USE SIGNAL ;
    PORT
      LAYER M5 ;
        RECT  94.32 88.476 94.344 88.56 ;
    END
    PORT
      LAYER M5 ;
        RECT  94.32 88.405 94.344 88.528 ;
    END
  END out_epoch[4]
  PIN out_epoch[5]
    DIRECTION OUTPUT ;
    USE SIGNAL ;
    PORT
      LAYER M3 ;
        RECT  95.652 88.522 95.67 88.56 ;
    END
    PORT
      LAYER M3 ;
        RECT  95.652 86.459 95.67 88.541 ;
    END
  END out_epoch[5]
  PIN out_epoch[6]
    DIRECTION OUTPUT ;
    USE SIGNAL ;
    PORT
      LAYER M5 ;
        RECT  96.96 88.476 96.984 88.56 ;
    END
    PORT
      LAYER M5 ;
        RECT  96.96 87.157 96.984 88.528 ;
    END
  END out_epoch[6]
  PIN out_epoch[7]
    DIRECTION OUTPUT ;
    USE SIGNAL ;
    PORT
      LAYER M3 ;
        RECT  98.28 88.522 98.298 88.56 ;
    END
    PORT
      LAYER M3 ;
        RECT  98.28 86.495 98.298 88.541 ;
    END
  END out_epoch[7]
  PIN out_epoch[8]
    DIRECTION OUTPUT ;
    USE SIGNAL ;
    PORT
      LAYER M5 ;
        RECT  99.552 88.476 99.576 88.56 ;
    END
    PORT
      LAYER M5 ;
        RECT  99.552 87.157 99.576 88.528 ;
    END
  END out_epoch[8]
  PIN out_epoch[9]
    DIRECTION OUTPUT ;
    USE SIGNAL ;
    PORT
      LAYER M3 ;
        RECT  100.872 88.522 100.89 88.56 ;
    END
    PORT
      LAYER M3 ;
        RECT  100.872 86.189 100.89 88.541 ;
    END
  END out_epoch[9]
  PIN out_layer[0]
    DIRECTION OUTPUT ;
    USE SIGNAL ;
    PORT
      LAYER M5 ;
        RECT  110.016 88.476 110.04 88.56 ;
    END
    PORT
      LAYER M5 ;
        RECT  110.016 87.733 110.04 88.528 ;
    END
  END out_layer[0]
  PIN out_layer[1]
    DIRECTION OUTPUT ;
    USE SIGNAL ;
    PORT
      LAYER M3 ;
        RECT  111.312 88.522 111.33 88.56 ;
    END
    PORT
      LAYER M3 ;
        RECT  111.312 86.225 111.33 88.541 ;
    END
  END out_layer[1]
  PIN out_layer[2]
    DIRECTION OUTPUT ;
    USE SIGNAL ;
    PORT
      LAYER M5 ;
        RECT  112.608 88.476 112.632 88.56 ;
    END
    PORT
      LAYER M5 ;
        RECT  112.608 87.157 112.632 88.528 ;
    END
  END out_layer[2]
  PIN out_layer[3]
    DIRECTION OUTPUT ;
    USE SIGNAL ;
    PORT
      LAYER M3 ;
        RECT  113.94 88.522 113.958 88.56 ;
    END
    PORT
      LAYER M3 ;
        RECT  113.94 86.225 113.958 88.541 ;
    END
  END out_layer[3]
  PIN out_layer[4]
    DIRECTION OUTPUT ;
    USE SIGNAL ;
    PORT
      LAYER M5 ;
        RECT  115.248 88.476 115.272 88.56 ;
    END
    PORT
      LAYER M5 ;
        RECT  115.248 87.157 115.272 88.528 ;
    END
  END out_layer[4]
  PIN out_layer[5]
    DIRECTION OUTPUT ;
    USE SIGNAL ;
    PORT
      LAYER M3 ;
        RECT  116.532 88.522 116.55 88.56 ;
    END
    PORT
      LAYER M3 ;
        RECT  116.532 86.417 116.55 88.541 ;
    END
  END out_layer[5]
  PIN out_t[0]
    DIRECTION OUTPUT ;
    USE SIGNAL ;
    PORT
      LAYER M5 ;
        RECT  117.84 88.476 117.864 88.56 ;
    END
    PORT
      LAYER M5 ;
        RECT  117.84 87.157 117.864 88.528 ;
    END
  END out_t[0]
  PIN out_t[10]
    DIRECTION OUTPUT ;
    USE SIGNAL ;
    PORT
      LAYER M5 ;
        RECT  130.896 88.476 130.92 88.56 ;
    END
    PORT
      LAYER M5 ;
        RECT  130.896 87.157 130.92 88.528 ;
    END
  END out_t[10]
  PIN out_t[11]
    DIRECTION OUTPUT ;
    USE SIGNAL ;
    PORT
      LAYER M3 ;
        RECT  132.228 88.522 132.246 88.56 ;
    END
    PORT
      LAYER M3 ;
        RECT  132.228 86.684 132.246 88.541 ;
    END
  END out_t[11]
  PIN out_t[12]
    DIRECTION OUTPUT ;
    USE SIGNAL ;
    PORT
      LAYER M5 ;
        RECT  133.536 88.476 133.56 88.56 ;
    END
    PORT
      LAYER M5 ;
        RECT  133.536 87.733 133.56 88.528 ;
    END
  END out_t[12]
  PIN out_t[13]
    DIRECTION OUTPUT ;
    USE SIGNAL ;
    PORT
      LAYER M3 ;
        RECT  134.82 88.522 134.838 88.56 ;
    END
    PORT
      LAYER M3 ;
        RECT  134.82 86.369 134.838 88.541 ;
    END
  END out_t[13]
  PIN out_t[1]
    DIRECTION OUTPUT ;
    USE SIGNAL ;
    PORT
      LAYER M3 ;
        RECT  119.16 88.522 119.178 88.56 ;
    END
    PORT
      LAYER M3 ;
        RECT  119.16 85.991 119.178 88.541 ;
    END
  END out_t[1]
  PIN out_t[2]
    DIRECTION OUTPUT ;
    USE SIGNAL ;
    PORT
      LAYER M5 ;
        RECT  120.48 88.476 120.504 88.56 ;
    END
    PORT
      LAYER M5 ;
        RECT  120.48 86.629 120.504 88.528 ;
    END
  END out_t[2]
  PIN out_t[3]
    DIRECTION OUTPUT ;
    USE SIGNAL ;
    PORT
      LAYER M3 ;
        RECT  121.752 88.522 121.77 88.56 ;
    END
    PORT
      LAYER M3 ;
        RECT  121.752 86.417 121.77 88.541 ;
    END
  END out_t[3]
  PIN out_t[4]
    DIRECTION OUTPUT ;
    USE SIGNAL ;
    PORT
      LAYER M5 ;
        RECT  123.072 88.476 123.096 88.56 ;
    END
    PORT
      LAYER M5 ;
        RECT  123.072 86.629 123.096 88.528 ;
    END
  END out_t[4]
  PIN out_t[5]
    DIRECTION OUTPUT ;
    USE SIGNAL ;
    PORT
      LAYER M3 ;
        RECT  124.38 88.522 124.398 88.56 ;
    END
    PORT
      LAYER M3 ;
        RECT  124.38 86.684 124.398 88.541 ;
    END
  END out_t[5]
  PIN out_t[6]
    DIRECTION OUTPUT ;
    USE SIGNAL ;
    PORT
      LAYER M5 ;
        RECT  125.664 88.476 125.688 88.56 ;
    END
    PORT
      LAYER M5 ;
        RECT  125.664 87.157 125.688 88.528 ;
    END
  END out_t[6]
  PIN out_t[7]
    DIRECTION OUTPUT ;
    USE SIGNAL ;
    PORT
      LAYER M3 ;
        RECT  126.972 88.522 126.99 88.56 ;
    END
    PORT
      LAYER M3 ;
        RECT  126.972 86.684 126.99 88.541 ;
    END
  END out_t[7]
  PIN out_t[8]
    DIRECTION OUTPUT ;
    USE SIGNAL ;
    PORT
      LAYER M5 ;
        RECT  128.304 88.476 128.328 88.56 ;
    END
    PORT
      LAYER M5 ;
        RECT  128.304 86.629 128.328 88.528 ;
    END
  END out_t[8]
  PIN out_t[9]
    DIRECTION OUTPUT ;
    USE SIGNAL ;
    PORT
      LAYER M3 ;
        RECT  129.6 88.522 129.618 88.56 ;
    END
    PORT
      LAYER M3 ;
        RECT  129.6 86.684 129.618 88.541 ;
    END
  END out_t[9]
  PIN out_v
    DIRECTION OUTPUT ;
    USE SIGNAL ;
    PORT
      LAYER M5 ;
        RECT  136.128 88.476 136.152 88.56 ;
    END
    PORT
      LAYER M5 ;
        RECT  136.128 88.451 136.152 88.528 ;
    END
  END out_v
  PIN out_valid
    DIRECTION OUTPUT ;
    USE SIGNAL ;
    PORT
      LAYER M3 ;
        RECT  137.448 88.522 137.466 88.56 ;
    END
    PORT
      LAYER M3 ;
        RECT  137.448 87.787 137.466 88.541 ;
    END
  END out_valid
  PIN rsp_data[0]
    DIRECTION OUTPUT ;
    USE SIGNAL ;
    PORT
      LAYER M4 ;
        RECT  0 1.152 0.084 1.176 ;
    END
  END rsp_data[0]
  PIN rsp_data[100]
    DIRECTION OUTPUT ;
    USE SIGNAL ;
    PORT
      LAYER M4 ;
        RECT  0 34.992 0.084 35.016 ;
    END
  END rsp_data[100]
  PIN rsp_data[101]
    DIRECTION OUTPUT ;
    USE SIGNAL ;
    PORT
      LAYER M4 ;
        RECT  0 35.328 0.084 35.352 ;
    END
  END rsp_data[101]
  PIN rsp_data[102]
    DIRECTION OUTPUT ;
    USE SIGNAL ;
    PORT
      LAYER M4 ;
        RECT  0 35.664 0.084 35.688 ;
    END
  END rsp_data[102]
  PIN rsp_data[103]
    DIRECTION OUTPUT ;
    USE SIGNAL ;
    PORT
      LAYER M4 ;
        RECT  0 36 0.084 36.024 ;
    END
  END rsp_data[103]
  PIN rsp_data[104]
    DIRECTION OUTPUT ;
    USE SIGNAL ;
    PORT
      LAYER M4 ;
        RECT  0 36.336 0.084 36.36 ;
    END
  END rsp_data[104]
  PIN rsp_data[105]
    DIRECTION OUTPUT ;
    USE SIGNAL ;
    PORT
      LAYER M4 ;
        RECT  0 36.672 0.084 36.696 ;
    END
  END rsp_data[105]
  PIN rsp_data[106]
    DIRECTION OUTPUT ;
    USE SIGNAL ;
    PORT
      LAYER M4 ;
        RECT  0 37.008 0.084 37.032 ;
    END
  END rsp_data[106]
  PIN rsp_data[107]
    DIRECTION OUTPUT ;
    USE SIGNAL ;
    PORT
      LAYER M4 ;
        RECT  0 37.344 0.084 37.368 ;
    END
  END rsp_data[107]
  PIN rsp_data[108]
    DIRECTION OUTPUT ;
    USE SIGNAL ;
    PORT
      LAYER M4 ;
        RECT  0 37.68 0.084 37.704 ;
    END
  END rsp_data[108]
  PIN rsp_data[109]
    DIRECTION OUTPUT ;
    USE SIGNAL ;
    PORT
      LAYER M4 ;
        RECT  0 38.016 0.084 38.04 ;
    END
  END rsp_data[109]
  PIN rsp_data[10]
    DIRECTION OUTPUT ;
    USE SIGNAL ;
    PORT
      LAYER M4 ;
        RECT  0 4.56 0.084 4.584 ;
    END
  END rsp_data[10]
  PIN rsp_data[110]
    DIRECTION OUTPUT ;
    USE SIGNAL ;
    PORT
      LAYER M4 ;
        RECT  0 38.352 0.084 38.376 ;
    END
  END rsp_data[110]
  PIN rsp_data[111]
    DIRECTION OUTPUT ;
    USE SIGNAL ;
    PORT
      LAYER M4 ;
        RECT  0 38.688 0.084 38.712 ;
    END
  END rsp_data[111]
  PIN rsp_data[112]
    DIRECTION OUTPUT ;
    USE SIGNAL ;
    PORT
      LAYER M4 ;
        RECT  0 39.024 0.084 39.048 ;
    END
  END rsp_data[112]
  PIN rsp_data[113]
    DIRECTION OUTPUT ;
    USE SIGNAL ;
    PORT
      LAYER M4 ;
        RECT  0 39.36 0.084 39.384 ;
    END
  END rsp_data[113]
  PIN rsp_data[114]
    DIRECTION OUTPUT ;
    USE SIGNAL ;
    PORT
      LAYER M4 ;
        RECT  0 39.696 0.084 39.72 ;
    END
  END rsp_data[114]
  PIN rsp_data[115]
    DIRECTION OUTPUT ;
    USE SIGNAL ;
    PORT
      LAYER M4 ;
        RECT  0 40.032 0.084 40.056 ;
    END
  END rsp_data[115]
  PIN rsp_data[116]
    DIRECTION OUTPUT ;
    USE SIGNAL ;
    PORT
      LAYER M4 ;
        RECT  0 40.368 0.084 40.392 ;
    END
  END rsp_data[116]
  PIN rsp_data[117]
    DIRECTION OUTPUT ;
    USE SIGNAL ;
    PORT
      LAYER M4 ;
        RECT  0 40.704 0.084 40.728 ;
    END
  END rsp_data[117]
  PIN rsp_data[118]
    DIRECTION OUTPUT ;
    USE SIGNAL ;
    PORT
      LAYER M4 ;
        RECT  0 41.04 0.084 41.064 ;
    END
  END rsp_data[118]
  PIN rsp_data[119]
    DIRECTION OUTPUT ;
    USE SIGNAL ;
    PORT
      LAYER M4 ;
        RECT  0 41.376 0.084 41.4 ;
    END
  END rsp_data[119]
  PIN rsp_data[11]
    DIRECTION OUTPUT ;
    USE SIGNAL ;
    PORT
      LAYER M4 ;
        RECT  0 4.896 0.084 4.92 ;
    END
  END rsp_data[11]
  PIN rsp_data[120]
    DIRECTION OUTPUT ;
    USE SIGNAL ;
    PORT
      LAYER M4 ;
        RECT  0 41.712 0.084 41.736 ;
    END
  END rsp_data[120]
  PIN rsp_data[121]
    DIRECTION OUTPUT ;
    USE SIGNAL ;
    PORT
      LAYER M4 ;
        RECT  0 42.048 0.084 42.072 ;
    END
  END rsp_data[121]
  PIN rsp_data[122]
    DIRECTION OUTPUT ;
    USE SIGNAL ;
    PORT
      LAYER M4 ;
        RECT  0 42.432 0.084 42.456 ;
    END
  END rsp_data[122]
  PIN rsp_data[123]
    DIRECTION OUTPUT ;
    USE SIGNAL ;
    PORT
      LAYER M4 ;
        RECT  0 42.768 0.084 42.792 ;
    END
  END rsp_data[123]
  PIN rsp_data[124]
    DIRECTION OUTPUT ;
    USE SIGNAL ;
    PORT
      LAYER M4 ;
        RECT  0 43.104 0.084 43.128 ;
    END
  END rsp_data[124]
  PIN rsp_data[125]
    DIRECTION OUTPUT ;
    USE SIGNAL ;
    PORT
      LAYER M4 ;
        RECT  0 43.44 0.084 43.464 ;
    END
  END rsp_data[125]
  PIN rsp_data[126]
    DIRECTION OUTPUT ;
    USE SIGNAL ;
    PORT
      LAYER M4 ;
        RECT  0 43.776 0.084 43.8 ;
    END
  END rsp_data[126]
  PIN rsp_data[127]
    DIRECTION OUTPUT ;
    USE SIGNAL ;
    PORT
      LAYER M4 ;
        RECT  0 44.112 0.084 44.136 ;
    END
  END rsp_data[127]
  PIN rsp_data[128]
    DIRECTION OUTPUT ;
    USE SIGNAL ;
    PORT
      LAYER M4 ;
        RECT  0 44.448 0.084 44.472 ;
    END
  END rsp_data[128]
  PIN rsp_data[129]
    DIRECTION OUTPUT ;
    USE SIGNAL ;
    PORT
      LAYER M4 ;
        RECT  0 44.784 0.084 44.808 ;
    END
  END rsp_data[129]
  PIN rsp_data[12]
    DIRECTION OUTPUT ;
    USE SIGNAL ;
    PORT
      LAYER M4 ;
        RECT  0 5.232 0.084 5.256 ;
    END
  END rsp_data[12]
  PIN rsp_data[130]
    DIRECTION OUTPUT ;
    USE SIGNAL ;
    PORT
      LAYER M4 ;
        RECT  0 45.12 0.084 45.144 ;
    END
  END rsp_data[130]
  PIN rsp_data[131]
    DIRECTION OUTPUT ;
    USE SIGNAL ;
    PORT
      LAYER M4 ;
        RECT  0 45.456 0.084 45.48 ;
    END
  END rsp_data[131]
  PIN rsp_data[132]
    DIRECTION OUTPUT ;
    USE SIGNAL ;
    PORT
      LAYER M4 ;
        RECT  0 45.792 0.084 45.816 ;
    END
  END rsp_data[132]
  PIN rsp_data[133]
    DIRECTION OUTPUT ;
    USE SIGNAL ;
    PORT
      LAYER M4 ;
        RECT  0 46.128 0.084 46.152 ;
    END
  END rsp_data[133]
  PIN rsp_data[134]
    DIRECTION OUTPUT ;
    USE SIGNAL ;
    PORT
      LAYER M4 ;
        RECT  0 46.464 0.084 46.488 ;
    END
  END rsp_data[134]
  PIN rsp_data[135]
    DIRECTION OUTPUT ;
    USE SIGNAL ;
    PORT
      LAYER M4 ;
        RECT  0 46.8 0.084 46.824 ;
    END
  END rsp_data[135]
  PIN rsp_data[136]
    DIRECTION OUTPUT ;
    USE SIGNAL ;
    PORT
      LAYER M4 ;
        RECT  0 47.136 0.084 47.16 ;
    END
  END rsp_data[136]
  PIN rsp_data[137]
    DIRECTION OUTPUT ;
    USE SIGNAL ;
    PORT
      LAYER M4 ;
        RECT  0 47.472 0.084 47.496 ;
    END
  END rsp_data[137]
  PIN rsp_data[138]
    DIRECTION OUTPUT ;
    USE SIGNAL ;
    PORT
      LAYER M4 ;
        RECT  0 47.808 0.084 47.832 ;
    END
  END rsp_data[138]
  PIN rsp_data[139]
    DIRECTION OUTPUT ;
    USE SIGNAL ;
    PORT
      LAYER M4 ;
        RECT  0 48.144 0.084 48.168 ;
    END
  END rsp_data[139]
  PIN rsp_data[13]
    DIRECTION OUTPUT ;
    USE SIGNAL ;
    PORT
      LAYER M4 ;
        RECT  0 5.568 0.084 5.592 ;
    END
  END rsp_data[13]
  PIN rsp_data[140]
    DIRECTION OUTPUT ;
    USE SIGNAL ;
    PORT
      LAYER M4 ;
        RECT  0 48.48 0.084 48.504 ;
    END
  END rsp_data[140]
  PIN rsp_data[141]
    DIRECTION OUTPUT ;
    USE SIGNAL ;
    PORT
      LAYER M4 ;
        RECT  0 48.816 0.084 48.84 ;
    END
  END rsp_data[141]
  PIN rsp_data[142]
    DIRECTION OUTPUT ;
    USE SIGNAL ;
    PORT
      LAYER M4 ;
        RECT  0 49.152 0.084 49.176 ;
    END
  END rsp_data[142]
  PIN rsp_data[143]
    DIRECTION OUTPUT ;
    USE SIGNAL ;
    PORT
      LAYER M4 ;
        RECT  0 49.488 0.084 49.512 ;
    END
  END rsp_data[143]
  PIN rsp_data[144]
    DIRECTION OUTPUT ;
    USE SIGNAL ;
    PORT
      LAYER M4 ;
        RECT  0 49.824 0.084 49.848 ;
    END
  END rsp_data[144]
  PIN rsp_data[145]
    DIRECTION OUTPUT ;
    USE SIGNAL ;
    PORT
      LAYER M4 ;
        RECT  0 50.208 0.084 50.232 ;
    END
  END rsp_data[145]
  PIN rsp_data[146]
    DIRECTION OUTPUT ;
    USE SIGNAL ;
    PORT
      LAYER M4 ;
        RECT  0 50.544 0.084 50.568 ;
    END
  END rsp_data[146]
  PIN rsp_data[147]
    DIRECTION OUTPUT ;
    USE SIGNAL ;
    PORT
      LAYER M4 ;
        RECT  0 50.88 0.084 50.904 ;
    END
  END rsp_data[147]
  PIN rsp_data[148]
    DIRECTION OUTPUT ;
    USE SIGNAL ;
    PORT
      LAYER M4 ;
        RECT  0 51.216 0.084 51.24 ;
    END
  END rsp_data[148]
  PIN rsp_data[149]
    DIRECTION OUTPUT ;
    USE SIGNAL ;
    PORT
      LAYER M4 ;
        RECT  0 51.552 0.084 51.576 ;
    END
  END rsp_data[149]
  PIN rsp_data[14]
    DIRECTION OUTPUT ;
    USE SIGNAL ;
    PORT
      LAYER M4 ;
        RECT  0 5.904 0.084 5.928 ;
    END
  END rsp_data[14]
  PIN rsp_data[150]
    DIRECTION OUTPUT ;
    USE SIGNAL ;
    PORT
      LAYER M4 ;
        RECT  0 51.888 0.084 51.912 ;
    END
  END rsp_data[150]
  PIN rsp_data[151]
    DIRECTION OUTPUT ;
    USE SIGNAL ;
    PORT
      LAYER M4 ;
        RECT  0 52.224 0.084 52.248 ;
    END
  END rsp_data[151]
  PIN rsp_data[152]
    DIRECTION OUTPUT ;
    USE SIGNAL ;
    PORT
      LAYER M4 ;
        RECT  0 52.56 0.084 52.584 ;
    END
  END rsp_data[152]
  PIN rsp_data[153]
    DIRECTION OUTPUT ;
    USE SIGNAL ;
    PORT
      LAYER M4 ;
        RECT  0 52.896 0.084 52.92 ;
    END
  END rsp_data[153]
  PIN rsp_data[154]
    DIRECTION OUTPUT ;
    USE SIGNAL ;
    PORT
      LAYER M4 ;
        RECT  0 53.232 0.084 53.256 ;
    END
  END rsp_data[154]
  PIN rsp_data[155]
    DIRECTION OUTPUT ;
    USE SIGNAL ;
    PORT
      LAYER M4 ;
        RECT  0 53.568 0.084 53.592 ;
    END
  END rsp_data[155]
  PIN rsp_data[156]
    DIRECTION OUTPUT ;
    USE SIGNAL ;
    PORT
      LAYER M4 ;
        RECT  0 53.904 0.084 53.928 ;
    END
  END rsp_data[156]
  PIN rsp_data[157]
    DIRECTION OUTPUT ;
    USE SIGNAL ;
    PORT
      LAYER M4 ;
        RECT  0 54.24 0.084 54.264 ;
    END
  END rsp_data[157]
  PIN rsp_data[158]
    DIRECTION OUTPUT ;
    USE SIGNAL ;
    PORT
      LAYER M4 ;
        RECT  0 54.576 0.084 54.6 ;
    END
  END rsp_data[158]
  PIN rsp_data[159]
    DIRECTION OUTPUT ;
    USE SIGNAL ;
    PORT
      LAYER M4 ;
        RECT  0 54.912 0.084 54.936 ;
    END
  END rsp_data[159]
  PIN rsp_data[15]
    DIRECTION OUTPUT ;
    USE SIGNAL ;
    PORT
      LAYER M4 ;
        RECT  0 6.24 0.084 6.264 ;
    END
  END rsp_data[15]
  PIN rsp_data[160]
    DIRECTION OUTPUT ;
    USE SIGNAL ;
    PORT
      LAYER M4 ;
        RECT  0 55.248 0.084 55.272 ;
    END
  END rsp_data[160]
  PIN rsp_data[161]
    DIRECTION OUTPUT ;
    USE SIGNAL ;
    PORT
      LAYER M4 ;
        RECT  0 55.584 0.084 55.608 ;
    END
  END rsp_data[161]
  PIN rsp_data[162]
    DIRECTION OUTPUT ;
    USE SIGNAL ;
    PORT
      LAYER M4 ;
        RECT  0 55.92 0.084 55.944 ;
    END
  END rsp_data[162]
  PIN rsp_data[163]
    DIRECTION OUTPUT ;
    USE SIGNAL ;
    PORT
      LAYER M4 ;
        RECT  0 56.256 0.084 56.28 ;
    END
  END rsp_data[163]
  PIN rsp_data[164]
    DIRECTION OUTPUT ;
    USE SIGNAL ;
    PORT
      LAYER M4 ;
        RECT  0 56.592 0.084 56.616 ;
    END
  END rsp_data[164]
  PIN rsp_data[165]
    DIRECTION OUTPUT ;
    USE SIGNAL ;
    PORT
      LAYER M4 ;
        RECT  0 56.928 0.084 56.952 ;
    END
  END rsp_data[165]
  PIN rsp_data[166]
    DIRECTION OUTPUT ;
    USE SIGNAL ;
    PORT
      LAYER M4 ;
        RECT  0 57.264 0.084 57.288 ;
    END
  END rsp_data[166]
  PIN rsp_data[167]
    DIRECTION OUTPUT ;
    USE SIGNAL ;
    PORT
      LAYER M4 ;
        RECT  0 57.648 0.084 57.672 ;
    END
  END rsp_data[167]
  PIN rsp_data[168]
    DIRECTION OUTPUT ;
    USE SIGNAL ;
    PORT
      LAYER M4 ;
        RECT  0 57.984 0.084 58.008 ;
    END
  END rsp_data[168]
  PIN rsp_data[169]
    DIRECTION OUTPUT ;
    USE SIGNAL ;
    PORT
      LAYER M4 ;
        RECT  0 58.32 0.084 58.344 ;
    END
  END rsp_data[169]
  PIN rsp_data[16]
    DIRECTION OUTPUT ;
    USE SIGNAL ;
    PORT
      LAYER M4 ;
        RECT  0 6.576 0.084 6.6 ;
    END
  END rsp_data[16]
  PIN rsp_data[170]
    DIRECTION OUTPUT ;
    USE SIGNAL ;
    PORT
      LAYER M4 ;
        RECT  0 58.656 0.084 58.68 ;
    END
  END rsp_data[170]
  PIN rsp_data[171]
    DIRECTION OUTPUT ;
    USE SIGNAL ;
    PORT
      LAYER M4 ;
        RECT  0 58.992 0.084 59.016 ;
    END
  END rsp_data[171]
  PIN rsp_data[172]
    DIRECTION OUTPUT ;
    USE SIGNAL ;
    PORT
      LAYER M4 ;
        RECT  0 59.328 0.084 59.352 ;
    END
  END rsp_data[172]
  PIN rsp_data[173]
    DIRECTION OUTPUT ;
    USE SIGNAL ;
    PORT
      LAYER M4 ;
        RECT  0 59.664 0.084 59.688 ;
    END
  END rsp_data[173]
  PIN rsp_data[174]
    DIRECTION OUTPUT ;
    USE SIGNAL ;
    PORT
      LAYER M4 ;
        RECT  0 60 0.084 60.024 ;
    END
  END rsp_data[174]
  PIN rsp_data[175]
    DIRECTION OUTPUT ;
    USE SIGNAL ;
    PORT
      LAYER M4 ;
        RECT  0 60.336 0.084 60.36 ;
    END
  END rsp_data[175]
  PIN rsp_data[176]
    DIRECTION OUTPUT ;
    USE SIGNAL ;
    PORT
      LAYER M4 ;
        RECT  0 60.672 0.084 60.696 ;
    END
  END rsp_data[176]
  PIN rsp_data[177]
    DIRECTION OUTPUT ;
    USE SIGNAL ;
    PORT
      LAYER M4 ;
        RECT  0 61.008 0.084 61.032 ;
    END
  END rsp_data[177]
  PIN rsp_data[178]
    DIRECTION OUTPUT ;
    USE SIGNAL ;
    PORT
      LAYER M4 ;
        RECT  0 61.344 0.084 61.368 ;
    END
  END rsp_data[178]
  PIN rsp_data[179]
    DIRECTION OUTPUT ;
    USE SIGNAL ;
    PORT
      LAYER M4 ;
        RECT  0 61.68 0.084 61.704 ;
    END
  END rsp_data[179]
  PIN rsp_data[17]
    DIRECTION OUTPUT ;
    USE SIGNAL ;
    PORT
      LAYER M4 ;
        RECT  0 6.912 0.084 6.936 ;
    END
  END rsp_data[17]
  PIN rsp_data[180]
    DIRECTION OUTPUT ;
    USE SIGNAL ;
    PORT
      LAYER M4 ;
        RECT  0 62.016 0.084 62.04 ;
    END
  END rsp_data[180]
  PIN rsp_data[181]
    DIRECTION OUTPUT ;
    USE SIGNAL ;
    PORT
      LAYER M4 ;
        RECT  0 62.352 0.084 62.376 ;
    END
  END rsp_data[181]
  PIN rsp_data[182]
    DIRECTION OUTPUT ;
    USE SIGNAL ;
    PORT
      LAYER M4 ;
        RECT  0 62.688 0.084 62.712 ;
    END
  END rsp_data[182]
  PIN rsp_data[183]
    DIRECTION OUTPUT ;
    USE SIGNAL ;
    PORT
      LAYER M4 ;
        RECT  0 63.024 0.084 63.048 ;
    END
  END rsp_data[183]
  PIN rsp_data[184]
    DIRECTION OUTPUT ;
    USE SIGNAL ;
    PORT
      LAYER M4 ;
        RECT  0 63.36 0.084 63.384 ;
    END
  END rsp_data[184]
  PIN rsp_data[185]
    DIRECTION OUTPUT ;
    USE SIGNAL ;
    PORT
      LAYER M4 ;
        RECT  0 63.696 0.084 63.72 ;
    END
  END rsp_data[185]
  PIN rsp_data[186]
    DIRECTION OUTPUT ;
    USE SIGNAL ;
    PORT
      LAYER M4 ;
        RECT  0 64.032 0.084 64.056 ;
    END
  END rsp_data[186]
  PIN rsp_data[187]
    DIRECTION OUTPUT ;
    USE SIGNAL ;
    PORT
      LAYER M4 ;
        RECT  0 64.368 0.084 64.392 ;
    END
  END rsp_data[187]
  PIN rsp_data[188]
    DIRECTION OUTPUT ;
    USE SIGNAL ;
    PORT
      LAYER M4 ;
        RECT  0 64.704 0.084 64.728 ;
    END
  END rsp_data[188]
  PIN rsp_data[189]
    DIRECTION OUTPUT ;
    USE SIGNAL ;
    PORT
      LAYER M4 ;
        RECT  0 65.04 0.084 65.064 ;
    END
  END rsp_data[189]
  PIN rsp_data[18]
    DIRECTION OUTPUT ;
    USE SIGNAL ;
    PORT
      LAYER M4 ;
        RECT  0 7.248 0.084 7.272 ;
    END
  END rsp_data[18]
  PIN rsp_data[190]
    DIRECTION OUTPUT ;
    USE SIGNAL ;
    PORT
      LAYER M4 ;
        RECT  0 65.424 0.084 65.448 ;
    END
  END rsp_data[190]
  PIN rsp_data[191]
    DIRECTION OUTPUT ;
    USE SIGNAL ;
    PORT
      LAYER M4 ;
        RECT  0 65.76 0.084 65.784 ;
    END
  END rsp_data[191]
  PIN rsp_data[192]
    DIRECTION OUTPUT ;
    USE SIGNAL ;
    PORT
      LAYER M4 ;
        RECT  0 66.096 0.084 66.12 ;
    END
  END rsp_data[192]
  PIN rsp_data[193]
    DIRECTION OUTPUT ;
    USE SIGNAL ;
    PORT
      LAYER M4 ;
        RECT  0 66.432 0.084 66.456 ;
    END
  END rsp_data[193]
  PIN rsp_data[194]
    DIRECTION OUTPUT ;
    USE SIGNAL ;
    PORT
      LAYER M4 ;
        RECT  0 66.768 0.084 66.792 ;
    END
  END rsp_data[194]
  PIN rsp_data[195]
    DIRECTION OUTPUT ;
    USE SIGNAL ;
    PORT
      LAYER M4 ;
        RECT  0 67.104 0.084 67.128 ;
    END
  END rsp_data[195]
  PIN rsp_data[196]
    DIRECTION OUTPUT ;
    USE SIGNAL ;
    PORT
      LAYER M4 ;
        RECT  0 67.44 0.084 67.464 ;
    END
  END rsp_data[196]
  PIN rsp_data[197]
    DIRECTION OUTPUT ;
    USE SIGNAL ;
    PORT
      LAYER M4 ;
        RECT  0 67.776 0.084 67.8 ;
    END
  END rsp_data[197]
  PIN rsp_data[198]
    DIRECTION OUTPUT ;
    USE SIGNAL ;
    PORT
      LAYER M4 ;
        RECT  0 68.112 0.084 68.136 ;
    END
  END rsp_data[198]
  PIN rsp_data[199]
    DIRECTION OUTPUT ;
    USE SIGNAL ;
    PORT
      LAYER M4 ;
        RECT  0 68.448 0.084 68.472 ;
    END
  END rsp_data[199]
  PIN rsp_data[19]
    DIRECTION OUTPUT ;
    USE SIGNAL ;
    PORT
      LAYER M4 ;
        RECT  0 7.584 0.084 7.608 ;
    END
  END rsp_data[19]
  PIN rsp_data[1]
    DIRECTION OUTPUT ;
    USE SIGNAL ;
    PORT
      LAYER M4 ;
        RECT  0 1.488 0.084 1.512 ;
    END
  END rsp_data[1]
  PIN rsp_data[200]
    DIRECTION OUTPUT ;
    USE SIGNAL ;
    PORT
      LAYER M4 ;
        RECT  0 68.784 0.084 68.808 ;
    END
  END rsp_data[200]
  PIN rsp_data[201]
    DIRECTION OUTPUT ;
    USE SIGNAL ;
    PORT
      LAYER M4 ;
        RECT  0 69.12 0.084 69.144 ;
    END
  END rsp_data[201]
  PIN rsp_data[202]
    DIRECTION OUTPUT ;
    USE SIGNAL ;
    PORT
      LAYER M4 ;
        RECT  0 69.456 0.084 69.48 ;
    END
  END rsp_data[202]
  PIN rsp_data[203]
    DIRECTION OUTPUT ;
    USE SIGNAL ;
    PORT
      LAYER M4 ;
        RECT  0 69.792 0.084 69.816 ;
    END
  END rsp_data[203]
  PIN rsp_data[204]
    DIRECTION OUTPUT ;
    USE SIGNAL ;
    PORT
      LAYER M4 ;
        RECT  0 70.128 0.084 70.152 ;
    END
  END rsp_data[204]
  PIN rsp_data[205]
    DIRECTION OUTPUT ;
    USE SIGNAL ;
    PORT
      LAYER M4 ;
        RECT  0 70.464 0.084 70.488 ;
    END
  END rsp_data[205]
  PIN rsp_data[206]
    DIRECTION OUTPUT ;
    USE SIGNAL ;
    PORT
      LAYER M4 ;
        RECT  0 70.8 0.084 70.824 ;
    END
  END rsp_data[206]
  PIN rsp_data[207]
    DIRECTION OUTPUT ;
    USE SIGNAL ;
    PORT
      LAYER M4 ;
        RECT  0 71.136 0.084 71.16 ;
    END
  END rsp_data[207]
  PIN rsp_data[208]
    DIRECTION OUTPUT ;
    USE SIGNAL ;
    PORT
      LAYER M4 ;
        RECT  0 71.472 0.084 71.496 ;
    END
  END rsp_data[208]
  PIN rsp_data[209]
    DIRECTION OUTPUT ;
    USE SIGNAL ;
    PORT
      LAYER M4 ;
        RECT  0 71.808 0.084 71.832 ;
    END
  END rsp_data[209]
  PIN rsp_data[20]
    DIRECTION OUTPUT ;
    USE SIGNAL ;
    PORT
      LAYER M4 ;
        RECT  0 7.92 0.084 7.944 ;
    END
  END rsp_data[20]
  PIN rsp_data[210]
    DIRECTION OUTPUT ;
    USE SIGNAL ;
    PORT
      LAYER M4 ;
        RECT  0 72.144 0.084 72.168 ;
    END
  END rsp_data[210]
  PIN rsp_data[211]
    DIRECTION OUTPUT ;
    USE SIGNAL ;
    PORT
      LAYER M4 ;
        RECT  0 72.48 0.084 72.504 ;
    END
  END rsp_data[211]
  PIN rsp_data[212]
    DIRECTION OUTPUT ;
    USE SIGNAL ;
    PORT
      LAYER M4 ;
        RECT  0 72.864 0.084 72.888 ;
    END
  END rsp_data[212]
  PIN rsp_data[213]
    DIRECTION OUTPUT ;
    USE SIGNAL ;
    PORT
      LAYER M4 ;
        RECT  0 73.2 0.084 73.224 ;
    END
  END rsp_data[213]
  PIN rsp_data[214]
    DIRECTION OUTPUT ;
    USE SIGNAL ;
    PORT
      LAYER M4 ;
        RECT  0 73.536 0.084 73.56 ;
    END
  END rsp_data[214]
  PIN rsp_data[215]
    DIRECTION OUTPUT ;
    USE SIGNAL ;
    PORT
      LAYER M4 ;
        RECT  0 73.872 0.084 73.896 ;
    END
  END rsp_data[215]
  PIN rsp_data[216]
    DIRECTION OUTPUT ;
    USE SIGNAL ;
    PORT
      LAYER M4 ;
        RECT  0 74.208 0.084 74.232 ;
    END
  END rsp_data[216]
  PIN rsp_data[217]
    DIRECTION OUTPUT ;
    USE SIGNAL ;
    PORT
      LAYER M4 ;
        RECT  0 74.544 0.084 74.568 ;
    END
  END rsp_data[217]
  PIN rsp_data[218]
    DIRECTION OUTPUT ;
    USE SIGNAL ;
    PORT
      LAYER M4 ;
        RECT  0 74.88 0.084 74.904 ;
    END
  END rsp_data[218]
  PIN rsp_data[219]
    DIRECTION OUTPUT ;
    USE SIGNAL ;
    PORT
      LAYER M4 ;
        RECT  0 75.216 0.084 75.24 ;
    END
  END rsp_data[219]
  PIN rsp_data[21]
    DIRECTION OUTPUT ;
    USE SIGNAL ;
    PORT
      LAYER M4 ;
        RECT  0 8.256 0.084 8.28 ;
    END
  END rsp_data[21]
  PIN rsp_data[220]
    DIRECTION OUTPUT ;
    USE SIGNAL ;
    PORT
      LAYER M4 ;
        RECT  0 75.552 0.084 75.576 ;
    END
  END rsp_data[220]
  PIN rsp_data[221]
    DIRECTION OUTPUT ;
    USE SIGNAL ;
    PORT
      LAYER M4 ;
        RECT  0 75.888 0.084 75.912 ;
    END
  END rsp_data[221]
  PIN rsp_data[222]
    DIRECTION OUTPUT ;
    USE SIGNAL ;
    PORT
      LAYER M4 ;
        RECT  0 76.224 0.084 76.248 ;
    END
  END rsp_data[222]
  PIN rsp_data[223]
    DIRECTION OUTPUT ;
    USE SIGNAL ;
    PORT
      LAYER M4 ;
        RECT  0 76.56 0.084 76.584 ;
    END
  END rsp_data[223]
  PIN rsp_data[224]
    DIRECTION OUTPUT ;
    USE SIGNAL ;
    PORT
      LAYER M4 ;
        RECT  0 76.896 0.084 76.92 ;
    END
  END rsp_data[224]
  PIN rsp_data[225]
    DIRECTION OUTPUT ;
    USE SIGNAL ;
    PORT
      LAYER M4 ;
        RECT  0 77.232 0.084 77.256 ;
    END
  END rsp_data[225]
  PIN rsp_data[226]
    DIRECTION OUTPUT ;
    USE SIGNAL ;
    PORT
      LAYER M4 ;
        RECT  0 77.568 0.084 77.592 ;
    END
  END rsp_data[226]
  PIN rsp_data[227]
    DIRECTION OUTPUT ;
    USE SIGNAL ;
    PORT
      LAYER M4 ;
        RECT  0 77.904 0.084 77.928 ;
    END
  END rsp_data[227]
  PIN rsp_data[228]
    DIRECTION OUTPUT ;
    USE SIGNAL ;
    PORT
      LAYER M4 ;
        RECT  0 78.24 0.084 78.264 ;
    END
  END rsp_data[228]
  PIN rsp_data[229]
    DIRECTION OUTPUT ;
    USE SIGNAL ;
    PORT
      LAYER M4 ;
        RECT  0 78.576 0.084 78.6 ;
    END
  END rsp_data[229]
  PIN rsp_data[22]
    DIRECTION OUTPUT ;
    USE SIGNAL ;
    PORT
      LAYER M4 ;
        RECT  0 8.592 0.084 8.616 ;
    END
  END rsp_data[22]
  PIN rsp_data[230]
    DIRECTION OUTPUT ;
    USE SIGNAL ;
    PORT
      LAYER M4 ;
        RECT  0 78.912 0.084 78.936 ;
    END
  END rsp_data[230]
  PIN rsp_data[231]
    DIRECTION OUTPUT ;
    USE SIGNAL ;
    PORT
      LAYER M4 ;
        RECT  0 79.248 0.084 79.272 ;
    END
  END rsp_data[231]
  PIN rsp_data[232]
    DIRECTION OUTPUT ;
    USE SIGNAL ;
    PORT
      LAYER M4 ;
        RECT  0 79.584 0.084 79.608 ;
    END
  END rsp_data[232]
  PIN rsp_data[233]
    DIRECTION OUTPUT ;
    USE SIGNAL ;
    PORT
      LAYER M4 ;
        RECT  0 79.92 0.084 79.944 ;
    END
  END rsp_data[233]
  PIN rsp_data[234]
    DIRECTION OUTPUT ;
    USE SIGNAL ;
    PORT
      LAYER M4 ;
        RECT  0 80.256 0.084 80.28 ;
    END
  END rsp_data[234]
  PIN rsp_data[235]
    DIRECTION OUTPUT ;
    USE SIGNAL ;
    PORT
      LAYER M4 ;
        RECT  0 80.64 0.084 80.664 ;
    END
  END rsp_data[235]
  PIN rsp_data[236]
    DIRECTION OUTPUT ;
    USE SIGNAL ;
    PORT
      LAYER M4 ;
        RECT  0 80.976 0.084 81 ;
    END
  END rsp_data[236]
  PIN rsp_data[237]
    DIRECTION OUTPUT ;
    USE SIGNAL ;
    PORT
      LAYER M4 ;
        RECT  0 81.312 0.084 81.336 ;
    END
  END rsp_data[237]
  PIN rsp_data[238]
    DIRECTION OUTPUT ;
    USE SIGNAL ;
    PORT
      LAYER M4 ;
        RECT  0 81.648 0.084 81.672 ;
    END
  END rsp_data[238]
  PIN rsp_data[239]
    DIRECTION OUTPUT ;
    USE SIGNAL ;
    PORT
      LAYER M4 ;
        RECT  0 81.984 0.084 82.008 ;
    END
  END rsp_data[239]
  PIN rsp_data[23]
    DIRECTION OUTPUT ;
    USE SIGNAL ;
    PORT
      LAYER M4 ;
        RECT  0 8.928 0.084 8.952 ;
    END
  END rsp_data[23]
  PIN rsp_data[240]
    DIRECTION OUTPUT ;
    USE SIGNAL ;
    PORT
      LAYER M4 ;
        RECT  0 82.32 0.084 82.344 ;
    END
  END rsp_data[240]
  PIN rsp_data[241]
    DIRECTION OUTPUT ;
    USE SIGNAL ;
    PORT
      LAYER M4 ;
        RECT  0 82.656 0.084 82.68 ;
    END
  END rsp_data[241]
  PIN rsp_data[242]
    DIRECTION OUTPUT ;
    USE SIGNAL ;
    PORT
      LAYER M4 ;
        RECT  0 82.992 0.084 83.016 ;
    END
  END rsp_data[242]
  PIN rsp_data[243]
    DIRECTION OUTPUT ;
    USE SIGNAL ;
    PORT
      LAYER M4 ;
        RECT  0 83.328 0.084 83.352 ;
    END
  END rsp_data[243]
  PIN rsp_data[244]
    DIRECTION OUTPUT ;
    USE SIGNAL ;
    PORT
      LAYER M4 ;
        RECT  0 83.664 0.084 83.688 ;
    END
  END rsp_data[244]
  PIN rsp_data[245]
    DIRECTION OUTPUT ;
    USE SIGNAL ;
    PORT
      LAYER M4 ;
        RECT  0 84 0.084 84.024 ;
    END
  END rsp_data[245]
  PIN rsp_data[246]
    DIRECTION OUTPUT ;
    USE SIGNAL ;
    PORT
      LAYER M4 ;
        RECT  0 84.336 0.084 84.36 ;
    END
  END rsp_data[246]
  PIN rsp_data[247]
    DIRECTION OUTPUT ;
    USE SIGNAL ;
    PORT
      LAYER M4 ;
        RECT  0 84.672 0.084 84.696 ;
    END
  END rsp_data[247]
  PIN rsp_data[248]
    DIRECTION OUTPUT ;
    USE SIGNAL ;
    PORT
      LAYER M4 ;
        RECT  0 85.008 0.084 85.032 ;
    END
  END rsp_data[248]
  PIN rsp_data[249]
    DIRECTION OUTPUT ;
    USE SIGNAL ;
    PORT
      LAYER M4 ;
        RECT  0 85.344 0.084 85.368 ;
    END
  END rsp_data[249]
  PIN rsp_data[24]
    DIRECTION OUTPUT ;
    USE SIGNAL ;
    PORT
      LAYER M4 ;
        RECT  0 9.264 0.084 9.288 ;
    END
  END rsp_data[24]
  PIN rsp_data[250]
    DIRECTION OUTPUT ;
    USE SIGNAL ;
    PORT
      LAYER M4 ;
        RECT  0 85.68 0.084 85.704 ;
    END
  END rsp_data[250]
  PIN rsp_data[251]
    DIRECTION OUTPUT ;
    USE SIGNAL ;
    PORT
      LAYER M4 ;
        RECT  0 86.016 0.084 86.04 ;
    END
  END rsp_data[251]
  PIN rsp_data[252]
    DIRECTION OUTPUT ;
    USE SIGNAL ;
    PORT
      LAYER M4 ;
        RECT  0 86.352 0.084 86.376 ;
    END
  END rsp_data[252]
  PIN rsp_data[253]
    DIRECTION OUTPUT ;
    USE SIGNAL ;
    PORT
      LAYER M4 ;
        RECT  0 86.688 0.084 86.712 ;
    END
  END rsp_data[253]
  PIN rsp_data[254]
    DIRECTION OUTPUT ;
    USE SIGNAL ;
    PORT
      LAYER M4 ;
        RECT  0 87.024 0.084 87.048 ;
    END
  END rsp_data[254]
  PIN rsp_data[255]
    DIRECTION OUTPUT ;
    USE SIGNAL ;
    PORT
      LAYER M4 ;
        RECT  0 87.36 0.084 87.384 ;
    END
  END rsp_data[255]
  PIN rsp_data[25]
    DIRECTION OUTPUT ;
    USE SIGNAL ;
    PORT
      LAYER M4 ;
        RECT  0 9.6 0.084 9.624 ;
    END
  END rsp_data[25]
  PIN rsp_data[26]
    DIRECTION OUTPUT ;
    USE SIGNAL ;
    PORT
      LAYER M4 ;
        RECT  0 9.936 0.084 9.96 ;
    END
  END rsp_data[26]
  PIN rsp_data[27]
    DIRECTION OUTPUT ;
    USE SIGNAL ;
    PORT
      LAYER M4 ;
        RECT  0 10.272 0.084 10.296 ;
    END
  END rsp_data[27]
  PIN rsp_data[28]
    DIRECTION OUTPUT ;
    USE SIGNAL ;
    PORT
      LAYER M4 ;
        RECT  0 10.608 0.084 10.632 ;
    END
  END rsp_data[28]
  PIN rsp_data[29]
    DIRECTION OUTPUT ;
    USE SIGNAL ;
    PORT
      LAYER M4 ;
        RECT  0 10.944 0.084 10.968 ;
    END
  END rsp_data[29]
  PIN rsp_data[2]
    DIRECTION OUTPUT ;
    USE SIGNAL ;
    PORT
      LAYER M4 ;
        RECT  0 1.824 0.084 1.848 ;
    END
  END rsp_data[2]
  PIN rsp_data[30]
    DIRECTION OUTPUT ;
    USE SIGNAL ;
    PORT
      LAYER M4 ;
        RECT  0 11.28 0.084 11.304 ;
    END
  END rsp_data[30]
  PIN rsp_data[31]
    DIRECTION OUTPUT ;
    USE SIGNAL ;
    PORT
      LAYER M4 ;
        RECT  0 11.616 0.084 11.64 ;
    END
  END rsp_data[31]
  PIN rsp_data[32]
    DIRECTION OUTPUT ;
    USE SIGNAL ;
    PORT
      LAYER M4 ;
        RECT  0 12 0.084 12.024 ;
    END
  END rsp_data[32]
  PIN rsp_data[33]
    DIRECTION OUTPUT ;
    USE SIGNAL ;
    PORT
      LAYER M4 ;
        RECT  0 12.336 0.084 12.36 ;
    END
  END rsp_data[33]
  PIN rsp_data[34]
    DIRECTION OUTPUT ;
    USE SIGNAL ;
    PORT
      LAYER M4 ;
        RECT  0 12.672 0.084 12.696 ;
    END
  END rsp_data[34]
  PIN rsp_data[35]
    DIRECTION OUTPUT ;
    USE SIGNAL ;
    PORT
      LAYER M4 ;
        RECT  0 13.008 0.084 13.032 ;
    END
  END rsp_data[35]
  PIN rsp_data[36]
    DIRECTION OUTPUT ;
    USE SIGNAL ;
    PORT
      LAYER M4 ;
        RECT  0 13.344 0.084 13.368 ;
    END
  END rsp_data[36]
  PIN rsp_data[37]
    DIRECTION OUTPUT ;
    USE SIGNAL ;
    PORT
      LAYER M4 ;
        RECT  0 13.68 0.084 13.704 ;
    END
  END rsp_data[37]
  PIN rsp_data[38]
    DIRECTION OUTPUT ;
    USE SIGNAL ;
    PORT
      LAYER M4 ;
        RECT  0 14.016 0.084 14.04 ;
    END
  END rsp_data[38]
  PIN rsp_data[39]
    DIRECTION OUTPUT ;
    USE SIGNAL ;
    PORT
      LAYER M4 ;
        RECT  0 14.352 0.084 14.376 ;
    END
  END rsp_data[39]
  PIN rsp_data[3]
    DIRECTION OUTPUT ;
    USE SIGNAL ;
    PORT
      LAYER M4 ;
        RECT  0 2.16 0.084 2.184 ;
    END
  END rsp_data[3]
  PIN rsp_data[40]
    DIRECTION OUTPUT ;
    USE SIGNAL ;
    PORT
      LAYER M4 ;
        RECT  0 14.688 0.084 14.712 ;
    END
  END rsp_data[40]
  PIN rsp_data[41]
    DIRECTION OUTPUT ;
    USE SIGNAL ;
    PORT
      LAYER M4 ;
        RECT  0 15.024 0.084 15.048 ;
    END
  END rsp_data[41]
  PIN rsp_data[42]
    DIRECTION OUTPUT ;
    USE SIGNAL ;
    PORT
      LAYER M4 ;
        RECT  0 15.36 0.084 15.384 ;
    END
  END rsp_data[42]
  PIN rsp_data[43]
    DIRECTION OUTPUT ;
    USE SIGNAL ;
    PORT
      LAYER M4 ;
        RECT  0 15.696 0.084 15.72 ;
    END
  END rsp_data[43]
  PIN rsp_data[44]
    DIRECTION OUTPUT ;
    USE SIGNAL ;
    PORT
      LAYER M4 ;
        RECT  0 16.032 0.084 16.056 ;
    END
  END rsp_data[44]
  PIN rsp_data[45]
    DIRECTION OUTPUT ;
    USE SIGNAL ;
    PORT
      LAYER M4 ;
        RECT  0 16.368 0.084 16.392 ;
    END
  END rsp_data[45]
  PIN rsp_data[46]
    DIRECTION OUTPUT ;
    USE SIGNAL ;
    PORT
      LAYER M4 ;
        RECT  0 16.704 0.084 16.728 ;
    END
  END rsp_data[46]
  PIN rsp_data[47]
    DIRECTION OUTPUT ;
    USE SIGNAL ;
    PORT
      LAYER M4 ;
        RECT  0 17.04 0.084 17.064 ;
    END
  END rsp_data[47]
  PIN rsp_data[48]
    DIRECTION OUTPUT ;
    USE SIGNAL ;
    PORT
      LAYER M4 ;
        RECT  0 17.376 0.084 17.4 ;
    END
  END rsp_data[48]
  PIN rsp_data[49]
    DIRECTION OUTPUT ;
    USE SIGNAL ;
    PORT
      LAYER M4 ;
        RECT  0 17.712 0.084 17.736 ;
    END
  END rsp_data[49]
  PIN rsp_data[4]
    DIRECTION OUTPUT ;
    USE SIGNAL ;
    PORT
      LAYER M4 ;
        RECT  0 2.496 0.084 2.52 ;
    END
  END rsp_data[4]
  PIN rsp_data[50]
    DIRECTION OUTPUT ;
    USE SIGNAL ;
    PORT
      LAYER M4 ;
        RECT  0 18.048 0.084 18.072 ;
    END
  END rsp_data[50]
  PIN rsp_data[51]
    DIRECTION OUTPUT ;
    USE SIGNAL ;
    PORT
      LAYER M4 ;
        RECT  0 18.384 0.084 18.408 ;
    END
  END rsp_data[51]
  PIN rsp_data[52]
    DIRECTION OUTPUT ;
    USE SIGNAL ;
    PORT
      LAYER M4 ;
        RECT  0 18.72 0.084 18.744 ;
    END
  END rsp_data[52]
  PIN rsp_data[53]
    DIRECTION OUTPUT ;
    USE SIGNAL ;
    PORT
      LAYER M4 ;
        RECT  0 19.056 0.084 19.08 ;
    END
  END rsp_data[53]
  PIN rsp_data[54]
    DIRECTION OUTPUT ;
    USE SIGNAL ;
    PORT
      LAYER M4 ;
        RECT  0 19.44 0.084 19.464 ;
    END
  END rsp_data[54]
  PIN rsp_data[55]
    DIRECTION OUTPUT ;
    USE SIGNAL ;
    PORT
      LAYER M4 ;
        RECT  0 19.776 0.084 19.8 ;
    END
  END rsp_data[55]
  PIN rsp_data[56]
    DIRECTION OUTPUT ;
    USE SIGNAL ;
    PORT
      LAYER M4 ;
        RECT  0 20.112 0.084 20.136 ;
    END
  END rsp_data[56]
  PIN rsp_data[57]
    DIRECTION OUTPUT ;
    USE SIGNAL ;
    PORT
      LAYER M4 ;
        RECT  0 20.448 0.084 20.472 ;
    END
  END rsp_data[57]
  PIN rsp_data[58]
    DIRECTION OUTPUT ;
    USE SIGNAL ;
    PORT
      LAYER M4 ;
        RECT  0 20.784 0.084 20.808 ;
    END
  END rsp_data[58]
  PIN rsp_data[59]
    DIRECTION OUTPUT ;
    USE SIGNAL ;
    PORT
      LAYER M4 ;
        RECT  0 21.12 0.084 21.144 ;
    END
  END rsp_data[59]
  PIN rsp_data[5]
    DIRECTION OUTPUT ;
    USE SIGNAL ;
    PORT
      LAYER M4 ;
        RECT  0 2.832 0.084 2.856 ;
    END
  END rsp_data[5]
  PIN rsp_data[60]
    DIRECTION OUTPUT ;
    USE SIGNAL ;
    PORT
      LAYER M4 ;
        RECT  0 21.456 0.084 21.48 ;
    END
  END rsp_data[60]
  PIN rsp_data[61]
    DIRECTION OUTPUT ;
    USE SIGNAL ;
    PORT
      LAYER M4 ;
        RECT  0 21.792 0.084 21.816 ;
    END
  END rsp_data[61]
  PIN rsp_data[62]
    DIRECTION OUTPUT ;
    USE SIGNAL ;
    PORT
      LAYER M4 ;
        RECT  0 22.128 0.084 22.152 ;
    END
  END rsp_data[62]
  PIN rsp_data[63]
    DIRECTION OUTPUT ;
    USE SIGNAL ;
    PORT
      LAYER M4 ;
        RECT  0 22.464 0.084 22.488 ;
    END
  END rsp_data[63]
  PIN rsp_data[64]
    DIRECTION OUTPUT ;
    USE SIGNAL ;
    PORT
      LAYER M4 ;
        RECT  0 22.8 0.084 22.824 ;
    END
  END rsp_data[64]
  PIN rsp_data[65]
    DIRECTION OUTPUT ;
    USE SIGNAL ;
    PORT
      LAYER M4 ;
        RECT  0 23.136 0.084 23.16 ;
    END
  END rsp_data[65]
  PIN rsp_data[66]
    DIRECTION OUTPUT ;
    USE SIGNAL ;
    PORT
      LAYER M4 ;
        RECT  0 23.472 0.084 23.496 ;
    END
  END rsp_data[66]
  PIN rsp_data[67]
    DIRECTION OUTPUT ;
    USE SIGNAL ;
    PORT
      LAYER M4 ;
        RECT  0 23.808 0.084 23.832 ;
    END
  END rsp_data[67]
  PIN rsp_data[68]
    DIRECTION OUTPUT ;
    USE SIGNAL ;
    PORT
      LAYER M4 ;
        RECT  0 24.144 0.084 24.168 ;
    END
  END rsp_data[68]
  PIN rsp_data[69]
    DIRECTION OUTPUT ;
    USE SIGNAL ;
    PORT
      LAYER M4 ;
        RECT  0 24.48 0.084 24.504 ;
    END
  END rsp_data[69]
  PIN rsp_data[6]
    DIRECTION OUTPUT ;
    USE SIGNAL ;
    PORT
      LAYER M4 ;
        RECT  0 3.168 0.084 3.192 ;
    END
  END rsp_data[6]
  PIN rsp_data[70]
    DIRECTION OUTPUT ;
    USE SIGNAL ;
    PORT
      LAYER M4 ;
        RECT  0 24.816 0.084 24.84 ;
    END
  END rsp_data[70]
  PIN rsp_data[71]
    DIRECTION OUTPUT ;
    USE SIGNAL ;
    PORT
      LAYER M4 ;
        RECT  0 25.152 0.084 25.176 ;
    END
  END rsp_data[71]
  PIN rsp_data[72]
    DIRECTION OUTPUT ;
    USE SIGNAL ;
    PORT
      LAYER M4 ;
        RECT  0 25.488 0.084 25.512 ;
    END
  END rsp_data[72]
  PIN rsp_data[73]
    DIRECTION OUTPUT ;
    USE SIGNAL ;
    PORT
      LAYER M4 ;
        RECT  0 25.824 0.084 25.848 ;
    END
  END rsp_data[73]
  PIN rsp_data[74]
    DIRECTION OUTPUT ;
    USE SIGNAL ;
    PORT
      LAYER M4 ;
        RECT  0 26.16 0.084 26.184 ;
    END
  END rsp_data[74]
  PIN rsp_data[75]
    DIRECTION OUTPUT ;
    USE SIGNAL ;
    PORT
      LAYER M4 ;
        RECT  0 26.496 0.084 26.52 ;
    END
  END rsp_data[75]
  PIN rsp_data[76]
    DIRECTION OUTPUT ;
    USE SIGNAL ;
    PORT
      LAYER M4 ;
        RECT  0 26.832 0.084 26.856 ;
    END
  END rsp_data[76]
  PIN rsp_data[77]
    DIRECTION OUTPUT ;
    USE SIGNAL ;
    PORT
      LAYER M4 ;
        RECT  0 27.216 0.084 27.24 ;
    END
  END rsp_data[77]
  PIN rsp_data[78]
    DIRECTION OUTPUT ;
    USE SIGNAL ;
    PORT
      LAYER M4 ;
        RECT  0 27.552 0.084 27.576 ;
    END
  END rsp_data[78]
  PIN rsp_data[79]
    DIRECTION OUTPUT ;
    USE SIGNAL ;
    PORT
      LAYER M4 ;
        RECT  0 27.888 0.084 27.912 ;
    END
  END rsp_data[79]
  PIN rsp_data[7]
    DIRECTION OUTPUT ;
    USE SIGNAL ;
    PORT
      LAYER M4 ;
        RECT  0 3.504 0.084 3.528 ;
    END
  END rsp_data[7]
  PIN rsp_data[80]
    DIRECTION OUTPUT ;
    USE SIGNAL ;
    PORT
      LAYER M4 ;
        RECT  0 28.224 0.084 28.248 ;
    END
  END rsp_data[80]
  PIN rsp_data[81]
    DIRECTION OUTPUT ;
    USE SIGNAL ;
    PORT
      LAYER M4 ;
        RECT  0 28.56 0.084 28.584 ;
    END
  END rsp_data[81]
  PIN rsp_data[82]
    DIRECTION OUTPUT ;
    USE SIGNAL ;
    PORT
      LAYER M4 ;
        RECT  0 28.896 0.084 28.92 ;
    END
  END rsp_data[82]
  PIN rsp_data[83]
    DIRECTION OUTPUT ;
    USE SIGNAL ;
    PORT
      LAYER M4 ;
        RECT  0 29.232 0.084 29.256 ;
    END
  END rsp_data[83]
  PIN rsp_data[84]
    DIRECTION OUTPUT ;
    USE SIGNAL ;
    PORT
      LAYER M4 ;
        RECT  0 29.568 0.084 29.592 ;
    END
  END rsp_data[84]
  PIN rsp_data[85]
    DIRECTION OUTPUT ;
    USE SIGNAL ;
    PORT
      LAYER M4 ;
        RECT  0 29.904 0.084 29.928 ;
    END
  END rsp_data[85]
  PIN rsp_data[86]
    DIRECTION OUTPUT ;
    USE SIGNAL ;
    PORT
      LAYER M4 ;
        RECT  0 30.24 0.084 30.264 ;
    END
  END rsp_data[86]
  PIN rsp_data[87]
    DIRECTION OUTPUT ;
    USE SIGNAL ;
    PORT
      LAYER M4 ;
        RECT  0 30.576 0.084 30.6 ;
    END
  END rsp_data[87]
  PIN rsp_data[88]
    DIRECTION OUTPUT ;
    USE SIGNAL ;
    PORT
      LAYER M4 ;
        RECT  0 30.912 0.084 30.936 ;
    END
  END rsp_data[88]
  PIN rsp_data[89]
    DIRECTION OUTPUT ;
    USE SIGNAL ;
    PORT
      LAYER M4 ;
        RECT  0 31.248 0.084 31.272 ;
    END
  END rsp_data[89]
  PIN rsp_data[8]
    DIRECTION OUTPUT ;
    USE SIGNAL ;
    PORT
      LAYER M4 ;
        RECT  0 3.84 0.084 3.864 ;
    END
  END rsp_data[8]
  PIN rsp_data[90]
    DIRECTION OUTPUT ;
    USE SIGNAL ;
    PORT
      LAYER M4 ;
        RECT  0 31.584 0.084 31.608 ;
    END
  END rsp_data[90]
  PIN rsp_data[91]
    DIRECTION OUTPUT ;
    USE SIGNAL ;
    PORT
      LAYER M4 ;
        RECT  0 31.92 0.084 31.944 ;
    END
  END rsp_data[91]
  PIN rsp_data[92]
    DIRECTION OUTPUT ;
    USE SIGNAL ;
    PORT
      LAYER M4 ;
        RECT  0 32.256 0.084 32.28 ;
    END
  END rsp_data[92]
  PIN rsp_data[93]
    DIRECTION OUTPUT ;
    USE SIGNAL ;
    PORT
      LAYER M4 ;
        RECT  0 32.592 0.084 32.616 ;
    END
  END rsp_data[93]
  PIN rsp_data[94]
    DIRECTION OUTPUT ;
    USE SIGNAL ;
    PORT
      LAYER M4 ;
        RECT  0 32.928 0.084 32.952 ;
    END
  END rsp_data[94]
  PIN rsp_data[95]
    DIRECTION OUTPUT ;
    USE SIGNAL ;
    PORT
      LAYER M4 ;
        RECT  0 33.264 0.084 33.288 ;
    END
  END rsp_data[95]
  PIN rsp_data[96]
    DIRECTION OUTPUT ;
    USE SIGNAL ;
    PORT
      LAYER M4 ;
        RECT  0 33.6 0.084 33.624 ;
    END
  END rsp_data[96]
  PIN rsp_data[97]
    DIRECTION OUTPUT ;
    USE SIGNAL ;
    PORT
      LAYER M4 ;
        RECT  0 33.936 0.084 33.96 ;
    END
  END rsp_data[97]
  PIN rsp_data[98]
    DIRECTION OUTPUT ;
    USE SIGNAL ;
    PORT
      LAYER M4 ;
        RECT  0 34.272 0.084 34.296 ;
    END
  END rsp_data[98]
  PIN rsp_data[99]
    DIRECTION OUTPUT ;
    USE SIGNAL ;
    PORT
      LAYER M4 ;
        RECT  0 34.608 0.084 34.632 ;
    END
  END rsp_data[99]
  PIN rsp_data[9]
    DIRECTION OUTPUT ;
    USE SIGNAL ;
    PORT
      LAYER M4 ;
        RECT  0 4.224 0.084 4.248 ;
    END
  END rsp_data[9]
  PIN rst_n
    DIRECTION INPUT ;
    USE SIGNAL ;
    PORT
      LAYER M5 ;
        RECT  138.72 88.476 138.744 88.56 ;
    END
    PORT
      LAYER M5 ;
        RECT  138.72 86.867 138.744 88.528 ;
    END
  END rst_n
  PIN VDD
    DIRECTION INOUT ;
    USE POWER ;
    PORT
      LAYER M5 ;
        RECT  137.592 2.151 137.712 86.409 ;
        RECT  132.192 2.151 132.312 86.409 ;
        RECT  126.792 2.151 126.912 86.409 ;
        RECT  121.392 2.151 121.512 86.409 ;
        RECT  115.992 2.151 116.112 86.409 ;
        RECT  110.592 2.151 110.712 86.409 ;
        RECT  105.192 2.151 105.312 86.409 ;
        RECT  99.792 2.151 99.912 86.409 ;
        RECT  94.392 2.151 94.512 86.409 ;
        RECT  88.992 2.151 89.112 86.409 ;
        RECT  83.592 2.151 83.712 86.409 ;
        RECT  78.192 2.151 78.312 86.409 ;
        RECT  72.792 2.151 72.912 86.409 ;
        RECT  67.392 2.151 67.512 86.409 ;
        RECT  61.992 2.151 62.112 86.409 ;
        RECT  56.592 2.151 56.712 86.409 ;
        RECT  51.192 2.151 51.312 86.409 ;
        RECT  45.792 2.151 45.912 86.409 ;
        RECT  40.392 2.151 40.512 86.409 ;
        RECT  34.992 2.151 35.112 86.409 ;
        RECT  29.592 2.151 29.712 86.409 ;
        RECT  24.192 2.151 24.312 86.409 ;
        RECT  18.792 2.151 18.912 86.409 ;
        RECT  13.392 2.151 13.512 86.409 ;
        RECT  7.992 2.151 8.112 86.409 ;
        RECT  2.592 2.151 2.712 86.409 ;
    END
  END VDD
  PIN VSS
    DIRECTION INOUT ;
    USE GROUND ;
    PORT
      LAYER M5 ;
        RECT  137.4 2.137 137.52 86.423 ;
        RECT  132 2.137 132.12 86.423 ;
        RECT  126.6 2.137 126.72 86.423 ;
        RECT  121.2 2.137 121.32 86.423 ;
        RECT  115.8 2.137 115.92 86.423 ;
        RECT  110.4 2.137 110.52 86.423 ;
        RECT  105 2.137 105.12 86.423 ;
        RECT  99.6 2.137 99.72 86.423 ;
        RECT  94.2 2.137 94.32 86.423 ;
        RECT  88.8 2.137 88.92 86.423 ;
        RECT  83.4 2.137 83.52 86.423 ;
        RECT  78 2.137 78.12 86.423 ;
        RECT  72.6 2.137 72.72 86.423 ;
        RECT  67.2 2.137 67.32 86.423 ;
        RECT  61.8 2.137 61.92 86.423 ;
        RECT  56.4 2.137 56.52 86.423 ;
        RECT  51 2.137 51.12 86.423 ;
        RECT  45.6 2.137 45.72 86.423 ;
        RECT  40.2 2.137 40.32 86.423 ;
        RECT  34.8 2.137 34.92 86.423 ;
        RECT  29.4 2.137 29.52 86.423 ;
        RECT  24 2.137 24.12 86.423 ;
        RECT  18.6 2.137 18.72 86.423 ;
        RECT  13.2 2.137 13.32 86.423 ;
        RECT  7.8 2.137 7.92 86.423 ;
        RECT  2.4 2.137 2.52 86.423 ;
    END
  END VSS
  # OT_OBS_CLOSED layer=M5 d_um=1.536 added=281
  OBS
    LAYER RVTN ;
     RECT  2.16 2.16 138.24 2.295 ;
     RECT  2.16 2.565 138.24 2.835 ;
     RECT  2.16 3.105 138.24 3.375 ;
     RECT  2.16 3.645 138.24 3.915 ;
     RECT  2.16 4.185 138.24 4.455 ;
     RECT  2.16 4.725 138.24 4.995 ;
     RECT  2.16 5.265 138.24 5.535 ;
     RECT  2.16 5.805 138.24 6.075 ;
     RECT  2.16 6.345 138.24 6.615 ;
     RECT  2.16 6.885 138.24 7.155 ;
     RECT  2.16 7.425 138.24 7.695 ;
     RECT  2.16 7.965 138.24 8.235 ;
     RECT  2.16 8.505 138.24 8.775 ;
     RECT  2.16 9.045 138.24 9.315 ;
     RECT  2.16 9.585 138.24 9.855 ;
     RECT  2.16 10.125 138.24 10.395 ;
     RECT  2.16 10.665 138.24 10.935 ;
     RECT  2.16 11.205 138.24 11.475 ;
     RECT  2.16 11.745 138.24 12.015 ;
     RECT  2.16 12.285 138.24 12.555 ;
     RECT  2.16 12.825 138.24 13.095 ;
     RECT  2.16 13.365 138.24 13.635 ;
     RECT  2.16 13.905 138.24 14.175 ;
     RECT  2.16 14.445 138.24 14.715 ;
     RECT  2.16 14.985 138.24 15.255 ;
     RECT  2.16 15.525 138.24 15.795 ;
     RECT  2.16 16.065 138.24 16.335 ;
     RECT  2.16 16.605 138.24 16.875 ;
     RECT  2.16 17.145 138.24 17.415 ;
     RECT  2.16 17.685 138.24 17.955 ;
     RECT  2.16 18.225 138.24 18.495 ;
     RECT  2.16 18.765 138.24 19.035 ;
     RECT  2.16 19.305 138.24 19.575 ;
     RECT  2.16 19.845 138.24 20.115 ;
     RECT  2.16 20.385 138.24 20.655 ;
     RECT  2.16 20.925 138.24 21.195 ;
     RECT  2.16 21.465 138.24 21.6 ;
     RECT  2.16 21.6 20.412 21.735 ;
     RECT  119.34 21.6 138.24 21.735 ;
     RECT  2.16 22.005 20.412 22.275 ;
     RECT  119.34 22.005 138.24 22.275 ;
     RECT  2.16 22.545 20.412 22.815 ;
     RECT  119.34 22.545 138.24 22.815 ;
     RECT  2.16 23.085 20.412 23.355 ;
     RECT  119.34 23.085 138.24 23.355 ;
     RECT  2.16 23.625 20.412 23.895 ;
     RECT  119.34 23.625 138.24 23.895 ;
     RECT  2.16 24.165 20.412 24.435 ;
     RECT  119.34 24.165 138.24 24.435 ;
     RECT  2.16 24.705 20.412 24.975 ;
     RECT  119.34 24.705 138.24 24.975 ;
     RECT  2.16 25.245 20.412 25.515 ;
     RECT  119.34 25.245 138.24 25.515 ;
     RECT  2.16 25.785 20.412 26.055 ;
     RECT  119.34 25.785 138.24 26.055 ;
     RECT  2.16 26.325 20.412 26.595 ;
     RECT  119.34 26.325 138.24 26.595 ;
     RECT  2.16 26.865 20.412 27.135 ;
     RECT  119.34 26.865 138.24 27.135 ;
     RECT  2.16 27.405 20.412 27.675 ;
     RECT  119.34 27.405 138.24 27.675 ;
     RECT  2.16 27.945 20.412 28.215 ;
     RECT  119.34 27.945 138.24 28.215 ;
     RECT  2.16 28.485 20.412 28.755 ;
     RECT  119.34 28.485 138.24 28.755 ;
     RECT  2.16 29.025 20.412 29.295 ;
     RECT  119.34 29.025 138.24 29.295 ;
     RECT  2.16 29.565 20.412 29.835 ;
     RECT  119.34 29.565 138.24 29.835 ;
     RECT  2.16 30.105 20.412 30.375 ;
     RECT  119.34 30.105 138.24 30.375 ;
     RECT  2.16 30.645 20.412 30.915 ;
     RECT  119.34 30.645 138.24 30.915 ;
     RECT  2.16 31.185 20.412 31.455 ;
     RECT  119.34 31.185 138.24 31.455 ;
     RECT  2.16 31.725 20.412 31.995 ;
     RECT  119.34 31.725 138.24 31.995 ;
     RECT  2.16 32.265 20.412 32.535 ;
     RECT  119.34 32.265 138.24 32.535 ;
     RECT  2.16 32.805 20.412 33.075 ;
     RECT  119.34 32.805 138.24 33.075 ;
     RECT  2.16 33.345 20.412 33.615 ;
     RECT  119.34 33.345 138.24 33.615 ;
     RECT  2.16 33.885 20.412 34.155 ;
     RECT  119.34 33.885 138.24 34.155 ;
     RECT  2.16 34.425 20.412 34.695 ;
     RECT  119.34 34.425 138.24 34.695 ;
     RECT  2.16 34.965 20.412 35.235 ;
     RECT  119.34 34.965 138.24 35.235 ;
     RECT  2.16 35.505 20.412 35.775 ;
     RECT  119.34 35.505 138.24 35.775 ;
     RECT  2.16 36.045 20.412 36.315 ;
     RECT  119.34 36.045 138.24 36.315 ;
     RECT  2.16 36.585 20.412 36.855 ;
     RECT  119.34 36.585 138.24 36.855 ;
     RECT  2.16 37.125 20.412 37.395 ;
     RECT  119.34 37.125 138.24 37.395 ;
     RECT  2.16 37.665 20.412 37.935 ;
     RECT  119.34 37.665 138.24 37.935 ;
     RECT  2.16 38.205 20.412 38.475 ;
     RECT  119.34 38.205 138.24 38.475 ;
     RECT  2.16 38.745 20.412 39.015 ;
     RECT  119.34 38.745 138.24 39.015 ;
     RECT  2.16 39.285 20.412 39.555 ;
     RECT  119.34 39.285 138.24 39.555 ;
     RECT  2.16 39.825 20.412 40.095 ;
     RECT  119.34 39.825 138.24 40.095 ;
     RECT  2.16 40.365 20.412 40.635 ;
     RECT  119.34 40.365 138.24 40.635 ;
     RECT  2.16 40.905 20.412 41.175 ;
     RECT  119.34 40.905 138.24 41.175 ;
     RECT  2.16 41.445 20.412 41.715 ;
     RECT  119.34 41.445 138.24 41.715 ;
     RECT  2.16 41.985 20.412 42.255 ;
     RECT  119.34 41.985 138.24 42.255 ;
     RECT  2.16 42.525 20.412 42.795 ;
     RECT  119.34 42.525 138.24 42.795 ;
     RECT  2.16 43.065 20.412 43.335 ;
     RECT  119.34 43.065 138.24 43.335 ;
     RECT  2.16 43.605 20.412 43.875 ;
     RECT  119.34 43.605 138.24 43.875 ;
     RECT  2.16 44.145 20.412 44.415 ;
     RECT  119.34 44.145 138.24 44.415 ;
     RECT  2.16 44.685 20.412 44.955 ;
     RECT  119.34 44.685 138.24 44.955 ;
     RECT  2.16 45.225 20.412 45.495 ;
     RECT  119.34 45.225 138.24 45.495 ;
     RECT  2.16 45.765 20.412 46.035 ;
     RECT  119.34 45.765 138.24 46.035 ;
     RECT  2.16 46.305 20.412 46.575 ;
     RECT  119.34 46.305 138.24 46.575 ;
     RECT  2.16 46.845 20.412 47.115 ;
     RECT  119.34 46.845 138.24 47.115 ;
     RECT  2.16 47.385 20.412 47.655 ;
     RECT  119.34 47.385 138.24 47.655 ;
     RECT  2.16 47.925 20.412 48.195 ;
     RECT  119.34 47.925 138.24 48.195 ;
     RECT  2.16 48.465 20.412 48.735 ;
     RECT  119.34 48.465 138.24 48.735 ;
     RECT  2.16 49.005 20.412 49.275 ;
     RECT  119.34 49.005 138.24 49.275 ;
     RECT  2.16 49.545 20.412 49.815 ;
     RECT  119.34 49.545 138.24 49.815 ;
     RECT  2.16 50.085 20.412 50.355 ;
     RECT  119.34 50.085 138.24 50.355 ;
     RECT  2.16 50.625 20.412 50.895 ;
     RECT  119.34 50.625 138.24 50.895 ;
     RECT  2.16 51.165 20.412 51.435 ;
     RECT  119.34 51.165 138.24 51.435 ;
     RECT  2.16 51.705 20.412 51.975 ;
     RECT  119.34 51.705 138.24 51.975 ;
     RECT  2.16 52.245 20.412 52.515 ;
     RECT  119.34 52.245 138.24 52.515 ;
     RECT  2.16 52.785 20.412 53.055 ;
     RECT  119.34 52.785 138.24 53.055 ;
     RECT  2.16 53.325 20.412 53.595 ;
     RECT  119.34 53.325 138.24 53.595 ;
     RECT  2.16 53.865 20.412 54.135 ;
     RECT  119.34 53.865 138.24 54.135 ;
     RECT  2.16 54.405 20.412 54.675 ;
     RECT  119.34 54.405 138.24 54.675 ;
     RECT  2.16 54.945 20.412 55.215 ;
     RECT  119.34 54.945 138.24 55.215 ;
     RECT  2.16 55.485 20.412 55.755 ;
     RECT  119.34 55.485 138.24 55.755 ;
     RECT  2.16 56.025 20.412 56.295 ;
     RECT  119.34 56.025 138.24 56.295 ;
     RECT  2.16 56.565 20.412 56.835 ;
     RECT  119.34 56.565 138.24 56.835 ;
     RECT  2.16 57.105 20.412 57.375 ;
     RECT  119.34 57.105 138.24 57.375 ;
     RECT  2.16 57.645 20.412 57.915 ;
     RECT  119.34 57.645 138.24 57.915 ;
     RECT  2.16 58.185 20.412 58.455 ;
     RECT  119.34 58.185 138.24 58.455 ;
     RECT  2.16 58.725 20.412 58.995 ;
     RECT  119.34 58.725 138.24 58.995 ;
     RECT  2.16 59.265 20.412 59.535 ;
     RECT  119.34 59.265 138.24 59.535 ;
     RECT  2.16 59.805 20.412 60.075 ;
     RECT  119.34 59.805 138.24 60.075 ;
     RECT  2.16 60.345 20.412 60.615 ;
     RECT  119.34 60.345 138.24 60.615 ;
     RECT  2.16 60.885 20.412 61.155 ;
     RECT  119.34 60.885 138.24 61.155 ;
     RECT  2.16 61.425 20.412 61.695 ;
     RECT  119.34 61.425 138.24 61.695 ;
     RECT  2.16 61.965 20.412 62.235 ;
     RECT  119.34 61.965 138.24 62.235 ;
     RECT  2.16 62.505 20.412 62.775 ;
     RECT  119.34 62.505 138.24 62.775 ;
     RECT  2.16 63.045 20.412 63.315 ;
     RECT  119.34 63.045 138.24 63.315 ;
     RECT  2.16 63.585 20.412 63.855 ;
     RECT  119.34 63.585 138.24 63.855 ;
     RECT  2.16 64.125 20.412 64.395 ;
     RECT  119.34 64.125 138.24 64.395 ;
     RECT  2.16 64.665 20.412 64.935 ;
     RECT  119.34 64.665 138.24 64.935 ;
     RECT  2.16 65.205 20.412 65.475 ;
     RECT  119.34 65.205 138.24 65.475 ;
     RECT  2.16 65.745 20.412 66.015 ;
     RECT  119.34 65.745 138.24 66.015 ;
     RECT  2.16 66.285 20.412 66.555 ;
     RECT  119.34 66.285 138.24 66.555 ;
     RECT  2.16 66.825 20.412 66.96 ;
     RECT  119.34 66.825 138.24 66.96 ;
     RECT  2.16 66.96 138.24 67.095 ;
     RECT  2.16 67.365 138.24 67.635 ;
     RECT  2.16 67.905 138.24 68.175 ;
     RECT  2.16 68.445 138.24 68.715 ;
     RECT  2.16 68.985 138.24 69.255 ;
     RECT  2.16 69.525 138.24 69.795 ;
     RECT  2.16 70.065 138.24 70.335 ;
     RECT  2.16 70.605 138.24 70.875 ;
     RECT  2.16 71.145 138.24 71.415 ;
     RECT  2.16 71.685 138.24 71.955 ;
     RECT  2.16 72.225 138.24 72.495 ;
     RECT  2.16 72.765 138.24 73.035 ;
     RECT  2.16 73.305 138.24 73.575 ;
     RECT  2.16 73.845 138.24 74.115 ;
     RECT  2.16 74.385 138.24 74.655 ;
     RECT  2.16 74.925 138.24 75.195 ;
     RECT  2.16 75.465 138.24 75.735 ;
     RECT  2.16 76.005 138.24 76.275 ;
     RECT  2.16 76.545 138.24 76.815 ;
     RECT  2.16 77.085 138.24 77.355 ;
     RECT  2.16 77.625 138.24 77.895 ;
     RECT  2.16 78.165 138.24 78.435 ;
     RECT  2.16 78.705 138.24 78.975 ;
     RECT  2.16 79.245 138.24 79.515 ;
     RECT  2.16 79.785 138.24 80.055 ;
     RECT  2.16 80.325 138.24 80.595 ;
     RECT  2.16 80.865 138.24 81.135 ;
     RECT  2.16 81.405 138.24 81.675 ;
     RECT  2.16 81.945 138.24 82.215 ;
     RECT  2.16 82.485 138.24 82.755 ;
     RECT  2.16 83.025 138.24 83.295 ;
     RECT  2.16 83.565 138.24 83.835 ;
     RECT  2.16 84.105 138.24 84.375 ;
     RECT  2.16 84.645 138.24 84.915 ;
     RECT  2.16 85.185 138.24 85.455 ;
     RECT  2.16 85.725 138.24 85.995 ;
     RECT  2.16 86.265 138.24 86.4 ;
    LAYER RVTP ;
     RECT  2.16 2.295 138.24 2.565 ;
     RECT  2.16 2.835 138.24 3.105 ;
     RECT  2.16 3.375 138.24 3.645 ;
     RECT  2.16 3.915 138.24 4.185 ;
     RECT  2.16 4.455 138.24 4.725 ;
     RECT  2.16 4.995 138.24 5.265 ;
     RECT  2.16 5.535 138.24 5.805 ;
     RECT  2.16 6.075 138.24 6.345 ;
     RECT  2.16 6.615 138.24 6.885 ;
     RECT  2.16 7.155 138.24 7.425 ;
     RECT  2.16 7.695 138.24 7.965 ;
     RECT  2.16 8.235 138.24 8.505 ;
     RECT  2.16 8.775 138.24 9.045 ;
     RECT  2.16 9.315 138.24 9.585 ;
     RECT  2.16 9.855 138.24 10.125 ;
     RECT  2.16 10.395 138.24 10.665 ;
     RECT  2.16 10.935 138.24 11.205 ;
     RECT  2.16 11.475 138.24 11.745 ;
     RECT  2.16 12.015 138.24 12.285 ;
     RECT  2.16 12.555 138.24 12.825 ;
     RECT  2.16 13.095 138.24 13.365 ;
     RECT  2.16 13.635 138.24 13.905 ;
     RECT  2.16 14.175 138.24 14.445 ;
     RECT  2.16 14.715 138.24 14.985 ;
     RECT  2.16 15.255 138.24 15.525 ;
     RECT  2.16 15.795 138.24 16.065 ;
     RECT  2.16 16.335 138.24 16.605 ;
     RECT  2.16 16.875 138.24 17.145 ;
     RECT  2.16 17.415 138.24 17.685 ;
     RECT  2.16 17.955 138.24 18.225 ;
     RECT  2.16 18.495 138.24 18.765 ;
     RECT  2.16 19.035 138.24 19.305 ;
     RECT  2.16 19.575 138.24 19.845 ;
     RECT  2.16 20.115 138.24 20.385 ;
     RECT  2.16 20.655 138.24 20.925 ;
     RECT  2.16 21.195 138.24 21.465 ;
     RECT  2.16 21.735 20.412 22.005 ;
     RECT  119.34 21.735 138.24 22.005 ;
     RECT  2.16 22.275 20.412 22.545 ;
     RECT  119.34 22.275 138.24 22.545 ;
     RECT  2.16 22.815 20.412 23.085 ;
     RECT  119.34 22.815 138.24 23.085 ;
     RECT  2.16 23.355 20.412 23.625 ;
     RECT  119.34 23.355 138.24 23.625 ;
     RECT  2.16 23.895 20.412 24.165 ;
     RECT  119.34 23.895 138.24 24.165 ;
     RECT  2.16 24.435 20.412 24.705 ;
     RECT  119.34 24.435 138.24 24.705 ;
     RECT  2.16 24.975 20.412 25.245 ;
     RECT  119.34 24.975 138.24 25.245 ;
     RECT  2.16 25.515 20.412 25.785 ;
     RECT  119.34 25.515 138.24 25.785 ;
     RECT  2.16 26.055 20.412 26.325 ;
     RECT  119.34 26.055 138.24 26.325 ;
     RECT  2.16 26.595 20.412 26.865 ;
     RECT  119.34 26.595 138.24 26.865 ;
     RECT  2.16 27.135 20.412 27.405 ;
     RECT  119.34 27.135 138.24 27.405 ;
     RECT  2.16 27.675 20.412 27.945 ;
     RECT  119.34 27.675 138.24 27.945 ;
     RECT  2.16 28.215 20.412 28.485 ;
     RECT  119.34 28.215 138.24 28.485 ;
     RECT  2.16 28.755 20.412 29.025 ;
     RECT  119.34 28.755 138.24 29.025 ;
     RECT  2.16 29.295 20.412 29.565 ;
     RECT  119.34 29.295 138.24 29.565 ;
     RECT  2.16 29.835 20.412 30.105 ;
     RECT  119.34 29.835 138.24 30.105 ;
     RECT  2.16 30.375 20.412 30.645 ;
     RECT  119.34 30.375 138.24 30.645 ;
     RECT  2.16 30.915 20.412 31.185 ;
     RECT  119.34 30.915 138.24 31.185 ;
     RECT  2.16 31.455 20.412 31.725 ;
     RECT  119.34 31.455 138.24 31.725 ;
     RECT  2.16 31.995 20.412 32.265 ;
     RECT  119.34 31.995 138.24 32.265 ;
     RECT  2.16 32.535 20.412 32.805 ;
     RECT  119.34 32.535 138.24 32.805 ;
     RECT  2.16 33.075 20.412 33.345 ;
     RECT  119.34 33.075 138.24 33.345 ;
     RECT  2.16 33.615 20.412 33.885 ;
     RECT  119.34 33.615 138.24 33.885 ;
     RECT  2.16 34.155 20.412 34.425 ;
     RECT  119.34 34.155 138.24 34.425 ;
     RECT  2.16 34.695 20.412 34.965 ;
     RECT  119.34 34.695 138.24 34.965 ;
     RECT  2.16 35.235 20.412 35.505 ;
     RECT  119.34 35.235 138.24 35.505 ;
     RECT  2.16 35.775 20.412 36.045 ;
     RECT  119.34 35.775 138.24 36.045 ;
     RECT  2.16 36.315 20.412 36.585 ;
     RECT  119.34 36.315 138.24 36.585 ;
     RECT  2.16 36.855 20.412 37.125 ;
     RECT  119.34 36.855 138.24 37.125 ;
     RECT  2.16 37.395 20.412 37.665 ;
     RECT  119.34 37.395 138.24 37.665 ;
     RECT  2.16 37.935 20.412 38.205 ;
     RECT  119.34 37.935 138.24 38.205 ;
     RECT  2.16 38.475 20.412 38.745 ;
     RECT  119.34 38.475 138.24 38.745 ;
     RECT  2.16 39.015 20.412 39.285 ;
     RECT  119.34 39.015 138.24 39.285 ;
     RECT  2.16 39.555 20.412 39.825 ;
     RECT  119.34 39.555 138.24 39.825 ;
     RECT  2.16 40.095 20.412 40.365 ;
     RECT  119.34 40.095 138.24 40.365 ;
     RECT  2.16 40.635 20.412 40.905 ;
     RECT  119.34 40.635 138.24 40.905 ;
     RECT  2.16 41.175 20.412 41.445 ;
     RECT  119.34 41.175 138.24 41.445 ;
     RECT  2.16 41.715 20.412 41.985 ;
     RECT  119.34 41.715 138.24 41.985 ;
     RECT  2.16 42.255 20.412 42.525 ;
     RECT  119.34 42.255 138.24 42.525 ;
     RECT  2.16 42.795 20.412 43.065 ;
     RECT  119.34 42.795 138.24 43.065 ;
     RECT  2.16 43.335 20.412 43.605 ;
     RECT  119.34 43.335 138.24 43.605 ;
     RECT  2.16 43.875 20.412 44.145 ;
     RECT  119.34 43.875 138.24 44.145 ;
     RECT  2.16 44.415 20.412 44.685 ;
     RECT  119.34 44.415 138.24 44.685 ;
     RECT  2.16 44.955 20.412 45.225 ;
     RECT  119.34 44.955 138.24 45.225 ;
     RECT  2.16 45.495 20.412 45.765 ;
     RECT  119.34 45.495 138.24 45.765 ;
     RECT  2.16 46.035 20.412 46.305 ;
     RECT  119.34 46.035 138.24 46.305 ;
     RECT  2.16 46.575 20.412 46.845 ;
     RECT  119.34 46.575 138.24 46.845 ;
     RECT  2.16 47.115 20.412 47.385 ;
     RECT  119.34 47.115 138.24 47.385 ;
     RECT  2.16 47.655 20.412 47.925 ;
     RECT  119.34 47.655 138.24 47.925 ;
     RECT  2.16 48.195 20.412 48.465 ;
     RECT  119.34 48.195 138.24 48.465 ;
     RECT  2.16 48.735 20.412 49.005 ;
     RECT  119.34 48.735 138.24 49.005 ;
     RECT  2.16 49.275 20.412 49.545 ;
     RECT  119.34 49.275 138.24 49.545 ;
     RECT  2.16 49.815 20.412 50.085 ;
     RECT  119.34 49.815 138.24 50.085 ;
     RECT  2.16 50.355 20.412 50.625 ;
     RECT  119.34 50.355 138.24 50.625 ;
     RECT  2.16 50.895 20.412 51.165 ;
     RECT  119.34 50.895 138.24 51.165 ;
     RECT  2.16 51.435 20.412 51.705 ;
     RECT  119.34 51.435 138.24 51.705 ;
     RECT  2.16 51.975 20.412 52.245 ;
     RECT  119.34 51.975 138.24 52.245 ;
     RECT  2.16 52.515 20.412 52.785 ;
     RECT  119.34 52.515 138.24 52.785 ;
     RECT  2.16 53.055 20.412 53.325 ;
     RECT  119.34 53.055 138.24 53.325 ;
     RECT  2.16 53.595 20.412 53.865 ;
     RECT  119.34 53.595 138.24 53.865 ;
     RECT  2.16 54.135 20.412 54.405 ;
     RECT  119.34 54.135 138.24 54.405 ;
     RECT  2.16 54.675 20.412 54.945 ;
     RECT  119.34 54.675 138.24 54.945 ;
     RECT  2.16 55.215 20.412 55.485 ;
     RECT  119.34 55.215 138.24 55.485 ;
     RECT  2.16 55.755 20.412 56.025 ;
     RECT  119.34 55.755 138.24 56.025 ;
     RECT  2.16 56.295 20.412 56.565 ;
     RECT  119.34 56.295 138.24 56.565 ;
     RECT  2.16 56.835 20.412 57.105 ;
     RECT  119.34 56.835 138.24 57.105 ;
     RECT  2.16 57.375 20.412 57.645 ;
     RECT  119.34 57.375 138.24 57.645 ;
     RECT  2.16 57.915 20.412 58.185 ;
     RECT  119.34 57.915 138.24 58.185 ;
     RECT  2.16 58.455 20.412 58.725 ;
     RECT  119.34 58.455 138.24 58.725 ;
     RECT  2.16 58.995 20.412 59.265 ;
     RECT  119.34 58.995 138.24 59.265 ;
     RECT  2.16 59.535 20.412 59.805 ;
     RECT  119.34 59.535 138.24 59.805 ;
     RECT  2.16 60.075 20.412 60.345 ;
     RECT  119.34 60.075 138.24 60.345 ;
     RECT  2.16 60.615 20.412 60.885 ;
     RECT  119.34 60.615 138.24 60.885 ;
     RECT  2.16 61.155 20.412 61.425 ;
     RECT  119.34 61.155 138.24 61.425 ;
     RECT  2.16 61.695 20.412 61.965 ;
     RECT  119.34 61.695 138.24 61.965 ;
     RECT  2.16 62.235 20.412 62.505 ;
     RECT  119.34 62.235 138.24 62.505 ;
     RECT  2.16 62.775 20.412 63.045 ;
     RECT  119.34 62.775 138.24 63.045 ;
     RECT  2.16 63.315 20.412 63.585 ;
     RECT  119.34 63.315 138.24 63.585 ;
     RECT  2.16 63.855 20.412 64.125 ;
     RECT  119.34 63.855 138.24 64.125 ;
     RECT  2.16 64.395 20.412 64.665 ;
     RECT  119.34 64.395 138.24 64.665 ;
     RECT  2.16 64.935 20.412 65.205 ;
     RECT  119.34 64.935 138.24 65.205 ;
     RECT  2.16 65.475 20.412 65.745 ;
     RECT  119.34 65.475 138.24 65.745 ;
     RECT  2.16 66.015 20.412 66.285 ;
     RECT  119.34 66.015 138.24 66.285 ;
     RECT  2.16 66.555 20.412 66.825 ;
     RECT  119.34 66.555 138.24 66.825 ;
     RECT  2.16 67.095 138.24 67.365 ;
     RECT  2.16 67.635 138.24 67.905 ;
     RECT  2.16 68.175 138.24 68.445 ;
     RECT  2.16 68.715 138.24 68.985 ;
     RECT  2.16 69.255 138.24 69.525 ;
     RECT  2.16 69.795 138.24 70.065 ;
     RECT  2.16 70.335 138.24 70.605 ;
     RECT  2.16 70.875 138.24 71.145 ;
     RECT  2.16 71.415 138.24 71.685 ;
     RECT  2.16 71.955 138.24 72.225 ;
     RECT  2.16 72.495 138.24 72.765 ;
     RECT  2.16 73.035 138.24 73.305 ;
     RECT  2.16 73.575 138.24 73.845 ;
     RECT  2.16 74.115 138.24 74.385 ;
     RECT  2.16 74.655 138.24 74.925 ;
     RECT  2.16 75.195 138.24 75.465 ;
     RECT  2.16 75.735 138.24 76.005 ;
     RECT  2.16 76.275 138.24 76.545 ;
     RECT  2.16 76.815 138.24 77.085 ;
     RECT  2.16 77.355 138.24 77.625 ;
     RECT  2.16 77.895 138.24 78.165 ;
     RECT  2.16 78.435 138.24 78.705 ;
     RECT  2.16 78.975 138.24 79.245 ;
     RECT  2.16 79.515 138.24 79.785 ;
     RECT  2.16 80.055 138.24 80.325 ;
     RECT  2.16 80.595 138.24 80.865 ;
     RECT  2.16 81.135 138.24 81.405 ;
     RECT  2.16 81.675 138.24 81.945 ;
     RECT  2.16 82.215 138.24 82.485 ;
     RECT  2.16 82.755 138.24 83.025 ;
     RECT  2.16 83.295 138.24 83.565 ;
     RECT  2.16 83.835 138.24 84.105 ;
     RECT  2.16 84.375 138.24 84.645 ;
     RECT  2.16 84.915 138.24 85.185 ;
     RECT  2.16 85.455 138.24 85.725 ;
     RECT  2.16 85.995 138.24 86.265 ;
    LAYER M1 ;
     RECT  2.16 2.151 138.24 21.609 ;
     RECT  22.464 23.76 117.288 64.824 ;
     RECT  2.16 21.609 20.412 66.951 ;
     RECT  119.34 21.609 138.24 66.951 ;
     RECT  2.16 66.951 138.24 86.409 ;
    LAYER M2 ;
     RECT  0.103 38.376 0.139 38.394 ;
     RECT  0.103 55.926 0.139 58.554 ;
     RECT  0.139 84.276 0.175 84.294 ;
     RECT  0.103 8.244 0.535 11.124 ;
     RECT  0.103 18.126 0.535 18.144 ;
     RECT  0.103 19.476 0.535 19.494 ;
     RECT  0.103 20.466 0.535 21.996 ;
     RECT  0.103 32.706 0.535 32.994 ;
     RECT  0.103 35.406 0.535 35.424 ;
     RECT  0.103 37.296 0.535 37.314 ;
     RECT  0.103 39.726 0.535 39.744 ;
     RECT  0.103 41.076 0.535 41.634 ;
     RECT  0.103 45.126 0.535 46.764 ;
     RECT  0.103 47.826 0.535 48.186 ;
     RECT  0.103 49.176 0.535 49.464 ;
     RECT  0.103 50.436 0.535 50.814 ;
     RECT  0.103 53.334 0.535 53.352 ;
     RECT  0.103 59.706 0.535 60.264 ;
     RECT  0.103 61.596 0.535 61.614 ;
     RECT  0.103 67.266 0.535 67.824 ;
     RECT  0.103 71.856 0.535 73.764 ;
     RECT  0.103 74.556 0.535 74.844 ;
     RECT  0.175 84.276 0.535 84.744 ;
     RECT  0.535 61.164 1.147 62.226 ;
     RECT  0.535 63.018 1.147 63.036 ;
     RECT  0.535 19.476 1.219 21.996 ;
     RECT  0.103 80.136 1.291 80.154 ;
     RECT  0.535 85.806 1.651 85.824 ;
     RECT  0.103 2.808 1.723 6.678 ;
     RECT  0.535 7.506 1.723 11.124 ;
     RECT  0.103 25.146 1.723 26.514 ;
     RECT  0.103 28.926 1.723 30.564 ;
     RECT  0.535 32.238 1.723 32.994 ;
     RECT  0.535 35.316 1.723 35.424 ;
     RECT  0.535 36.936 1.723 37.314 ;
     RECT  0.103 42.426 1.723 42.444 ;
     RECT  0.103 43.776 1.723 44.064 ;
     RECT  0.535 45.126 1.723 48.186 ;
     RECT  0.103 51.786 1.723 51.894 ;
     RECT  0.535 52.686 1.723 53.352 ;
     RECT  0.103 54.576 1.723 55.044 ;
     RECT  1.147 61.164 1.723 63.036 ;
     RECT  0.535 67.176 1.723 67.824 ;
     RECT  0.103 68.886 1.723 69.354 ;
     RECT  0.103 76.248 1.723 76.464 ;
     RECT  0.103 77.256 1.723 78.624 ;
     RECT  0.103 82.656 1.723 82.944 ;
     RECT  0.535 84.078 1.723 84.744 ;
     RECT  0.139 38.376 1.759 38.736 ;
     RECT  1.723 42.426 1.759 42.624 ;
     RECT  0.139 55.926 1.759 58.716 ;
     RECT  1.723 77.256 1.759 78.966 ;
     RECT  1.723 2.808 2.16 11.394 ;
     RECT  0.103 12.186 2.16 13.392 ;
     RECT  0.103 14.184 2.16 14.202 ;
     RECT  0.103 15.228 2.16 15.246 ;
     RECT  0.103 16.236 2.16 16.794 ;
     RECT  0.535 17.694 2.16 18.144 ;
     RECT  1.219 19.476 2.16 22.644 ;
     RECT  1.723 25.146 2.16 26.784 ;
     RECT  0.103 27.684 2.16 28.134 ;
     RECT  1.723 28.926 2.16 31.104 ;
     RECT  1.723 31.896 2.16 32.994 ;
     RECT  0.103 34.056 2.16 34.074 ;
     RECT  1.723 35.316 2.16 37.584 ;
     RECT  1.759 38.376 2.16 38.934 ;
     RECT  0.535 39.726 2.16 41.634 ;
     RECT  1.759 42.426 2.16 42.714 ;
     RECT  1.723 43.776 2.16 44.334 ;
     RECT  1.723 45.126 2.16 48.384 ;
     RECT  0.535 49.176 2.16 50.886 ;
     RECT  1.723 51.786 2.16 53.784 ;
     RECT  1.723 54.576 2.16 55.134 ;
     RECT  1.759 55.926 2.16 58.914 ;
     RECT  0.535 59.706 2.16 60.336 ;
     RECT  1.723 61.164 2.16 63.234 ;
     RECT  0.103 64.026 2.16 65.664 ;
     RECT  1.723 67.176 2.16 69.714 ;
     RECT  0.103 70.506 2.16 71.064 ;
     RECT  0.535 71.856 2.16 75.222 ;
     RECT  1.723 76.176 2.16 76.464 ;
     RECT  1.759 77.256 2.16 79.164 ;
     RECT  1.291 80.064 2.16 80.154 ;
     RECT  0.103 81.036 2.16 81.702 ;
     RECT  1.723 82.656 2.16 83.214 ;
     RECT  1.723 84.006 2.16 84.744 ;
     RECT  1.651 85.806 2.16 86.058 ;
     RECT  2.16 2.151 2.335 86.409 ;
     RECT  2.335 2.07 2.731 86.409 ;
     RECT  2.731 2.07 3.055 86.454 ;
     RECT  3.055 1.998 3.487 86.454 ;
     RECT  3.487 1.926 5.207 86.454 ;
     RECT  5.207 1.926 6.871 86.409 ;
     RECT  6.871 1.926 7.799 86.904 ;
     RECT  7.799 2.106 9.059 86.904 ;
     RECT  9.059 2.151 20.412 86.904 ;
     RECT  20.412 60.696 20.435 61.254 ;
     RECT  20.412 25.524 20.471 41.094 ;
     RECT  20.471 28.926 20.507 41.094 ;
     RECT  20.412 48.978 20.507 58.644 ;
     RECT  20.507 28.926 21.047 30.132 ;
     RECT  20.412 45.54 21.083 45.954 ;
     RECT  20.507 48.978 21.083 50.184 ;
     RECT  21.083 48.978 21.119 48.996 ;
     RECT  21.083 49.788 21.307 50.184 ;
     RECT  20.507 50.976 21.307 58.644 ;
     RECT  21.307 49.788 21.343 58.644 ;
     RECT  20.435 61.236 21.379 61.254 ;
     RECT  21.343 49.788 21.443 58.716 ;
     RECT  21.379 61.128 21.479 61.254 ;
     RECT  20.507 30.888 21.515 41.094 ;
     RECT  21.515 30.888 21.551 32.364 ;
     RECT  21.443 49.788 21.659 58.644 ;
     RECT  20.412 62.01 21.659 64.224 ;
     RECT  20.412 42.498 21.695 44.604 ;
     RECT  21.659 49.788 21.695 50.148 ;
     RECT  21.659 52.866 21.695 56.394 ;
     RECT  21.659 57.546 21.695 57.564 ;
     RECT  21.659 62.01 21.695 63.27 ;
     RECT  21.659 64.206 21.695 64.224 ;
     RECT  21.659 50.976 21.731 52.119 ;
     RECT  21.695 53.028 21.731 55.98 ;
     RECT  20.412 64.98 21.919 65.466 ;
     RECT  20.412 66.222 21.919 86.904 ;
     RECT  20.412 48.096 22.099 48.114 ;
     RECT  21.695 42.498 22.207 42.894 ;
     RECT  22.099 48.096 22.207 48.294 ;
     RECT  20.412 2.151 22.464 23.922 ;
     RECT  20.471 25.524 22.464 28.134 ;
     RECT  21.047 29.466 22.464 30.132 ;
     RECT  21.551 31.23 22.464 32.364 ;
     RECT  21.515 33.12 22.464 41.094 ;
     RECT  22.207 41.994 22.464 42.894 ;
     RECT  21.695 43.776 22.464 44.604 ;
     RECT  21.083 45.54 22.464 45.558 ;
     RECT  22.207 47.736 22.464 48.294 ;
     RECT  21.695 49.788 22.464 50.076 ;
     RECT  21.731 51.336 22.464 52.119 ;
     RECT  21.731 53.028 22.464 53.046 ;
     RECT  21.731 54.036 22.464 55.98 ;
     RECT  21.479 61.236 22.464 61.254 ;
     RECT  21.695 62.046 22.464 62.694 ;
     RECT  21.919 64.98 22.464 86.904 ;
     RECT  22.464 2.151 69.611 86.904 ;
     RECT  69.611 2.151 71.887 86.679 ;
     RECT  71.887 2.151 72.167 86.724 ;
     RECT  72.167 2.151 82.363 86.679 ;
     RECT  82.363 2.151 82.607 86.724 ;
     RECT  90.427 88.506 90.527 88.524 ;
     RECT  82.607 2.151 93.019 86.679 ;
     RECT  93.019 2.151 93.263 86.724 ;
     RECT  93.263 2.151 106.583 86.679 ;
     RECT  106.583 2.151 117.288 86.409 ;
     RECT  117.288 24.336 118.255 28.044 ;
     RECT  117.288 29.232 118.471 36.882 ;
     RECT  117.288 38.016 118.471 40.428 ;
     RECT  118.255 24.336 118.543 28.278 ;
     RECT  118.543 24.336 118.579 28.314 ;
     RECT  118.471 29.232 118.579 40.428 ;
     RECT  117.288 41.454 118.579 86.409 ;
     RECT  117.288 2.151 119.34 23.346 ;
     RECT  118.579 24.336 119.34 86.409 ;
     RECT  119.34 2.151 124.375 86.409 ;
     RECT  124.375 2.151 124.799 86.679 ;
     RECT  124.799 2.151 126.931 86.409 ;
     RECT  126.931 2.151 126.995 86.679 ;
     RECT  126.995 2.151 129.595 86.409 ;
     RECT  129.595 2.151 129.767 86.679 ;
     RECT  129.767 2.151 132.151 86.409 ;
     RECT  132.151 2.151 132.251 86.679 ;
     RECT  132.251 2.151 134.707 86.409 ;
     RECT  134.707 2.106 136.759 86.409 ;
     RECT  136.759 2.034 137.623 86.409 ;
     RECT  137.623 1.998 138.24 86.409 ;
     RECT  138.24 1.998 138.479 23.346 ;
     RECT  138.24 24.21 138.479 64.386 ;
     RECT  138.479 1.998 138.515 17.676 ;
     RECT  138.479 25.56 138.515 64.386 ;
     RECT  138.24 80.334 138.515 82.008 ;
     RECT  138.515 1.998 138.551 7.218 ;
     RECT  138.479 18.54 138.551 23.346 ;
     RECT  138.515 25.56 138.551 47.34 ;
     RECT  138.515 48.168 138.551 62.838 ;
     RECT  138.24 65.142 138.551 68.976 ;
     RECT  138.24 69.804 138.551 70.092 ;
     RECT  138.24 70.848 138.551 72.288 ;
     RECT  138.24 73.278 138.551 77.958 ;
     RECT  138.24 79.02 138.947 79.038 ;
     RECT  138.24 83.61 139.019 84.366 ;
     RECT  138.551 48.168 139.055 50.148 ;
     RECT  138.551 74.97 139.055 77.958 ;
     RECT  138.551 1.998 139.091 5.328 ;
     RECT  138.551 6.354 139.091 7.218 ;
     RECT  138.515 8.208 139.091 11.844 ;
     RECT  138.515 12.87 139.091 17.676 ;
     RECT  138.551 18.54 139.091 23.184 ;
     RECT  138.551 25.56 139.091 26.586 ;
     RECT  138.551 27.72 139.091 35.028 ;
     RECT  138.551 35.82 139.091 46.098 ;
     RECT  138.551 47.088 139.091 47.34 ;
     RECT  139.055 48.168 139.091 49.878 ;
     RECT  138.551 50.94 139.091 51.768 ;
     RECT  138.551 52.794 139.091 53.388 ;
     RECT  138.551 54.378 139.091 62.766 ;
     RECT  138.515 63.828 139.091 63.846 ;
     RECT  138.551 65.142 139.091 68.166 ;
     RECT  138.551 68.958 139.091 68.976 ;
     RECT  138.551 69.804 139.091 69.822 ;
     RECT  138.551 71.73 139.091 72.288 ;
     RECT  138.551 73.278 139.091 74.106 ;
     RECT  139.055 74.97 139.091 74.988 ;
     RECT  139.055 75.78 139.091 77.958 ;
     RECT  138.515 80.91 139.091 82.008 ;
     RECT  139.019 83.646 139.091 84.366 ;
     RECT  139.091 19.044 139.127 19.062 ;
     RECT  139.091 45.702 139.127 46.098 ;
     RECT  139.091 59.814 139.127 59.832 ;
     RECT  139.091 74.088 139.127 74.106 ;
     RECT  139.091 81.45 139.127 82.008 ;
     RECT  138.24 85.23 139.127 85.752 ;
     RECT  139.091 15.498 139.631 16.56 ;
     RECT  139.091 20.088 139.631 21.69 ;
     RECT  138.479 24.21 139.631 24.732 ;
     RECT  139.091 36.558 139.631 37.188 ;
     RECT  139.091 41.418 139.631 41.94 ;
     RECT  139.091 43.11 139.631 43.326 ;
     RECT  139.091 48.78 139.631 48.798 ;
     RECT  139.091 52.794 139.631 52.812 ;
     RECT  139.091 56.61 139.631 56.628 ;
     RECT  139.091 65.142 139.631 65.736 ;
     RECT  139.127 81.684 139.631 82.008 ;
     RECT  139.091 84.15 139.631 84.366 ;
     RECT  139.091 33.696 139.667 33.714 ;
     RECT  139.631 81.684 139.667 81.702 ;
     RECT  139.127 85.734 139.667 85.752 ;
     RECT  139.091 2.07 140.279 3.474 ;
     RECT  140.279 2.07 140.315 2.088 ;
     RECT  140.279 2.916 140.315 3.474 ;
     RECT  139.091 10.44 140.315 10.458 ;
     RECT  139.091 11.52 140.315 11.538 ;
     RECT  139.631 16.11 140.315 16.56 ;
     RECT  139.631 20.592 140.315 20.61 ;
     RECT  139.631 21.672 140.315 21.69 ;
     RECT  139.631 24.714 140.315 24.732 ;
     RECT  139.091 31.428 140.315 32.094 ;
     RECT  139.091 40.032 140.315 40.662 ;
     RECT  139.631 41.652 140.315 41.94 ;
     RECT  139.091 44.388 140.315 44.406 ;
     RECT  139.127 45.702 140.315 45.72 ;
     RECT  139.091 47.322 140.315 47.34 ;
     RECT  139.091 61.704 140.315 61.722 ;
     RECT  139.091 62.748 140.315 62.766 ;
     RECT  139.631 65.142 140.315 65.16 ;
     RECT  139.091 66.798 140.315 67.86 ;
     RECT  138.551 70.92 140.315 70.938 ;
     RECT  139.091 77.13 140.315 77.148 ;
     RECT  139.631 84.15 140.315 84.168 ;
    LAYER M3 ;
     RECT  2.844 1.483 2.862 1.819 ;
     RECT  2.556 1.819 2.862 1.921 ;
     RECT  138.024 1.435 138.042 1.993 ;
     RECT  140.292 1.147 140.31 2.011 ;
     RECT  2.556 1.921 3.51 2.065 ;
     RECT  5.616 1.993 5.634 2.101 ;
     RECT  7.776 1.921 7.794 2.101 ;
     RECT  136.764 2.029 136.782 2.101 ;
     RECT  137.628 1.993 138.042 2.101 ;
     RECT  7.704 2.101 7.794 2.143 ;
     RECT  2.34 2.065 3.51 2.191 ;
     RECT  4.392 2.065 4.41 2.191 ;
     RECT  5.544 2.101 5.634 2.191 ;
     RECT  9.036 2.101 9.054 2.191 ;
     RECT  136.764 2.101 138.114 2.191 ;
     RECT  2.34 2.191 5.634 2.219 ;
     RECT  6.804 2.101 6.822 2.219 ;
     RECT  7.704 2.143 7.905 2.219 ;
     RECT  136.62 2.191 138.114 2.219 ;
     RECT  134.712 2.101 134.73 2.227 ;
     RECT  2.415 2.219 5.634 2.263 ;
     RECT  7.815 2.219 7.905 2.263 ;
     RECT  8.964 2.191 9.558 2.263 ;
     RECT  134.712 2.227 134.802 2.263 ;
     RECT  140.256 2.011 140.31 2.399 ;
     RECT  13.215 2.143 13.305 2.413 ;
     RECT  18.615 2.143 18.705 2.413 ;
     RECT  24.015 2.143 24.105 2.413 ;
     RECT  29.415 2.143 29.505 2.413 ;
     RECT  34.815 2.143 34.905 2.413 ;
     RECT  40.215 2.143 40.305 2.413 ;
     RECT  45.615 2.143 45.705 2.413 ;
     RECT  51.015 2.143 51.105 2.413 ;
     RECT  56.415 2.143 56.505 2.413 ;
     RECT  61.815 2.143 61.905 2.413 ;
     RECT  67.215 2.143 67.305 2.413 ;
     RECT  72.615 2.143 72.705 2.413 ;
     RECT  78.015 2.143 78.105 2.413 ;
     RECT  83.415 2.143 83.505 2.413 ;
     RECT  88.815 2.143 88.905 2.413 ;
     RECT  94.215 2.143 94.305 2.413 ;
     RECT  99.615 2.143 99.705 2.413 ;
     RECT  105.015 2.143 105.105 2.413 ;
     RECT  110.415 2.143 110.505 2.413 ;
     RECT  115.815 2.143 115.905 2.413 ;
     RECT  121.215 2.143 121.305 2.413 ;
     RECT  126.615 2.143 126.705 2.413 ;
     RECT  132.015 2.143 132.105 2.413 ;
     RECT  134.64 2.263 134.802 2.461 ;
     RECT  135.756 2.371 135.774 2.461 ;
     RECT  136.62 2.219 138.042 2.461 ;
     RECT  7.815 2.263 9.558 2.489 ;
     RECT  1.404 1.147 1.422 2.491 ;
     RECT  134.604 2.461 134.802 2.491 ;
     RECT  9.396 2.489 9.558 2.561 ;
     RECT  105.015 2.413 105.297 2.587 ;
     RECT  134.532 2.491 134.946 2.587 ;
     RECT  134.352 2.587 134.946 2.641 ;
     RECT  135.756 2.461 138.042 2.669 ;
     RECT  135.756 2.669 136.062 2.767 ;
     RECT  134.028 2.641 134.946 2.795 ;
     RECT  136.8 2.669 138.042 2.795 ;
     RECT  9.54 2.561 9.558 2.803 ;
     RECT  133.092 2.605 133.11 2.813 ;
     RECT  134.28 2.795 134.946 2.861 ;
     RECT  134.568 2.861 134.946 3.001 ;
     RECT  135.684 2.767 136.062 3.001 ;
     RECT  2.415 2.263 6.354 3.145 ;
     RECT  0.108 2.059 0.126 3.163 ;
     RECT  1.152 2.491 1.422 3.163 ;
     RECT  2.415 3.145 6.462 3.181 ;
     RECT  105.015 2.587 105.462 3.271 ;
     RECT  2.415 3.181 6.786 3.299 ;
     RECT  9.54 2.803 9.666 3.307 ;
     RECT  10.836 3.109 10.854 3.307 ;
     RECT  105.015 3.271 106.038 3.341 ;
     RECT  7.815 2.489 8.586 3.343 ;
     RECT  9.54 3.307 10.854 3.343 ;
     RECT  2.415 3.299 6.462 3.407 ;
     RECT  2.415 3.407 3.726 3.451 ;
     RECT  134.568 3.001 136.062 3.451 ;
     RECT  136.8 2.795 137.898 3.451 ;
     RECT  140.292 2.399 140.31 3.479 ;
     RECT  105.015 3.341 105.426 3.547 ;
     RECT  4.5 3.407 6.462 3.569 ;
     RECT  104.976 3.547 105.426 3.569 ;
     RECT  7.815 3.343 10.854 3.605 ;
     RECT  7.815 3.605 9.018 3.649 ;
     RECT  10.26 3.605 10.854 3.649 ;
     RECT  0.108 3.163 1.422 3.677 ;
     RECT  132.015 2.413 132.297 3.685 ;
     RECT  134.568 3.451 137.898 3.685 ;
     RECT  139.068 1.723 139.086 3.685 ;
     RECT  131.94 3.685 132.297 3.721 ;
     RECT  133.056 2.911 133.074 3.721 ;
     RECT  104.976 3.569 105.297 3.749 ;
     RECT  134.568 3.685 139.086 3.749 ;
     RECT  138.528 3.749 139.086 3.773 ;
     RECT  134.568 3.749 137.697 3.835 ;
     RECT  7.344 3.649 9.018 3.911 ;
     RECT  134.532 3.835 137.697 3.983 ;
     RECT  12.024 3.145 12.186 3.991 ;
     RECT  10.26 3.649 11.07 4.109 ;
     RECT  131.94 3.721 133.074 4.181 ;
     RECT  2.304 3.451 3.726 4.216 ;
     RECT  4.5 3.569 6.39 4.216 ;
     RECT  2.304 4.216 6.39 4.253 ;
     RECT  135.504 3.983 137.697 4.253 ;
     RECT  11.916 3.991 12.186 4.261 ;
     RECT  134.496 4.225 134.514 4.261 ;
     RECT  135.504 4.253 136.422 4.289 ;
     RECT  24.015 2.413 24.297 4.351 ;
     RECT  34.815 2.413 35.097 4.351 ;
     RECT  45.615 2.413 45.897 4.351 ;
     RECT  56.415 2.413 56.697 4.351 ;
     RECT  67.215 2.413 67.497 4.351 ;
     RECT  78.015 2.413 78.297 4.351 ;
     RECT  88.815 2.413 89.097 4.351 ;
     RECT  99.615 2.413 99.897 4.351 ;
     RECT  110.415 2.413 110.697 4.351 ;
     RECT  121.215 2.413 121.497 4.351 ;
     RECT  131.94 4.181 132.297 4.351 ;
     RECT  14.724 4.117 14.742 4.363 ;
     RECT  15.552 4.117 15.57 4.379 ;
     RECT  17.28 4.261 17.298 4.379 ;
     RECT  131.904 4.351 132.297 4.397 ;
     RECT  135.54 4.289 136.422 4.397 ;
     RECT  11.808 4.261 12.186 4.415 ;
     RECT  7.38 3.911 9.018 4.423 ;
     RECT  16.344 4.387 16.362 4.445 ;
     RECT  135.54 4.397 136.314 4.445 ;
     RECT  4.572 4.253 6.39 4.531 ;
     RECT  14.616 4.363 14.742 4.531 ;
     RECT  137.196 4.253 137.697 4.531 ;
     RECT  133.056 4.181 133.074 4.555 ;
     RECT  133.956 4.261 134.514 4.555 ;
     RECT  10.584 4.109 10.854 4.649 ;
     RECT  137.196 4.531 137.934 4.649 ;
     RECT  10.836 4.649 10.854 4.757 ;
     RECT  1.404 3.677 1.422 4.793 ;
     RECT  4.572 4.531 6.57 4.801 ;
     RECT  7.38 4.423 9.234 4.801 ;
     RECT  0.108 3.677 0.558 4.829 ;
     RECT  139.068 3.773 139.086 4.891 ;
     RECT  34.704 4.351 35.097 4.925 ;
     RECT  110.304 4.351 110.697 4.925 ;
     RECT  23.904 4.351 24.297 4.928 ;
     RECT  45.504 4.351 45.897 4.928 ;
     RECT  56.304 4.351 56.697 4.928 ;
     RECT  67.104 4.351 67.497 4.928 ;
     RECT  77.904 4.351 78.297 4.928 ;
     RECT  88.704 4.351 89.097 4.928 ;
     RECT  99.504 4.351 99.897 4.928 ;
     RECT  121.104 4.351 121.497 4.928 ;
     RECT  138.456 4.891 139.086 4.991 ;
     RECT  130.536 4.891 130.554 5.021 ;
     RECT  4.572 4.801 9.234 5.035 ;
     RECT  137.196 4.649 137.697 5.071 ;
     RECT  14.616 4.531 15.534 5.131 ;
     RECT  132.015 4.397 132.297 5.131 ;
     RECT  133.056 4.555 134.514 5.131 ;
     RECT  14.58 5.131 15.534 5.189 ;
     RECT  133.056 5.131 134.622 5.213 ;
     RECT  2.304 4.253 3.618 5.233 ;
     RECT  134.388 5.213 134.622 5.269 ;
     RECT  4.572 5.035 9.306 5.305 ;
     RECT  138.492 4.991 139.086 5.333 ;
     RECT  2.304 5.233 3.726 5.341 ;
     RECT  4.536 5.305 9.306 5.341 ;
     RECT  134.388 5.269 134.766 5.431 ;
     RECT  131.796 5.131 132.297 5.495 ;
     RECT  135.72 4.445 136.314 5.563 ;
     RECT  137.088 5.071 137.697 5.563 ;
     RECT  133.056 5.213 133.29 5.597 ;
     RECT  131.94 5.495 132.297 5.611 ;
     RECT  133.056 5.597 133.074 5.611 ;
     RECT  14.58 5.189 14.994 5.737 ;
     RECT  135.72 5.563 137.697 5.755 ;
     RECT  138.492 5.333 138.546 5.755 ;
     RECT  134.388 5.431 134.838 5.765 ;
     RECT  131.94 5.611 133.074 5.789 ;
     RECT  2.304 5.341 9.306 5.801 ;
     RECT  135.72 5.755 138.546 5.803 ;
     RECT  14.364 5.737 14.994 5.999 ;
     RECT  13.215 2.413 13.497 6.043 ;
     RECT  135.684 5.803 138.546 6.077 ;
     RECT  4.068 5.801 9.306 6.115 ;
     RECT  135.684 6.077 137.97 6.143 ;
     RECT  0.108 4.829 0.126 6.151 ;
     RECT  0.108 6.151 0.558 6.269 ;
     RECT  4.068 6.115 9.522 6.269 ;
     RECT  134.46 5.765 134.838 6.421 ;
     RECT  135.684 6.143 137.862 6.421 ;
     RECT  12.168 4.415 12.186 6.547 ;
     RECT  13.215 6.043 13.878 6.547 ;
     RECT  2.304 5.801 3.294 6.655 ;
     RECT  4.068 6.269 9.162 6.655 ;
     RECT  134.46 6.421 137.862 6.655 ;
     RECT  132.015 5.789 133.074 6.691 ;
     RECT  133.992 6.655 137.862 6.691 ;
     RECT  2.304 6.655 9.162 6.781 ;
     RECT  132.015 6.691 137.862 6.845 ;
     RECT  22.428 6.691 22.446 6.925 ;
     RECT  1.728 6.781 9.162 6.941 ;
     RECT  132.015 6.845 134.55 6.961 ;
     RECT  34.815 4.925 35.097 7.045 ;
     RECT  24.015 4.928 24.297 7.051 ;
     RECT  45.615 4.928 45.897 7.051 ;
     RECT  56.415 4.928 56.697 7.051 ;
     RECT  67.215 4.928 67.497 7.051 ;
     RECT  78.015 4.928 78.297 7.051 ;
     RECT  88.815 4.928 89.097 7.051 ;
     RECT  99.615 4.928 99.897 7.051 ;
     RECT  12.168 6.547 13.878 7.079 ;
     RECT  132.015 6.961 133.398 7.079 ;
     RECT  34.704 7.045 35.097 7.085 ;
     RECT  23.904 7.051 24.297 7.088 ;
     RECT  45.504 7.051 45.897 7.088 ;
     RECT  56.304 7.051 56.697 7.088 ;
     RECT  67.104 7.051 67.497 7.088 ;
     RECT  77.904 7.051 78.297 7.088 ;
     RECT  88.704 7.051 89.097 7.088 ;
     RECT  99.504 7.051 99.897 7.088 ;
     RECT  106.74 7.051 107.046 7.088 ;
     RECT  106.74 7.088 106.758 7.133 ;
     RECT  135.432 6.845 137.862 7.195 ;
     RECT  139.068 6.331 139.086 7.195 ;
     RECT  135.432 7.195 139.086 7.223 ;
     RECT  22.428 6.925 23.058 7.231 ;
     RECT  134.532 6.961 134.55 7.259 ;
     RECT  0.108 6.269 0.126 7.277 ;
     RECT  22.428 7.231 23.13 7.349 ;
     RECT  130.536 6.619 130.554 7.349 ;
     RECT  16.488 4.531 16.506 7.357 ;
     RECT  17.64 7.051 17.658 7.357 ;
     RECT  16.488 7.357 17.658 7.421 ;
     RECT  135.432 7.223 138.51 7.421 ;
     RECT  17.424 7.421 17.658 7.501 ;
     RECT  0.54 7.501 0.558 7.613 ;
     RECT  17.424 7.501 17.802 7.655 ;
     RECT  132.015 7.079 133.362 7.709 ;
     RECT  133.056 7.709 133.362 7.861 ;
     RECT  135.432 7.421 137.697 7.861 ;
     RECT  134.244 7.771 134.406 7.889 ;
     RECT  134.388 7.889 134.406 8.041 ;
     RECT  135.144 7.861 137.697 8.041 ;
     RECT  133.056 7.861 133.47 8.045 ;
     RECT  138.456 7.421 138.51 8.059 ;
     RECT  22.356 7.393 22.374 8.131 ;
     RECT  23.112 7.349 23.13 8.131 ;
     RECT  17.424 7.655 17.514 8.159 ;
     RECT  12.168 7.079 12.186 8.311 ;
     RECT  2.304 6.941 9.162 8.401 ;
     RECT  1.728 8.401 9.162 8.429 ;
     RECT  1.728 8.429 6.894 8.621 ;
     RECT  134.388 8.041 137.697 8.635 ;
     RECT  138.456 8.059 139.086 8.635 ;
     RECT  7.815 8.429 9.162 8.671 ;
     RECT  134.388 8.635 139.086 8.771 ;
     RECT  134.388 8.771 137.697 8.813 ;
     RECT  132.015 7.709 132.297 8.941 ;
     RECT  133.056 8.045 133.362 8.941 ;
     RECT  132.015 8.941 133.362 9.121 ;
     RECT  7.815 8.671 9.45 9.211 ;
     RECT  13.215 7.079 13.878 9.211 ;
     RECT  14.724 5.999 14.994 9.211 ;
     RECT  121.215 4.928 121.497 9.211 ;
     RECT  132.015 9.121 133.47 9.211 ;
     RECT  131.904 9.211 133.47 9.239 ;
     RECT  2.304 8.621 6.894 9.247 ;
     RECT  7.704 9.211 9.45 9.247 ;
     RECT  121.104 9.211 121.497 9.248 ;
     RECT  131.904 9.239 133.182 9.248 ;
     RECT  134.388 8.813 135.306 9.275 ;
     RECT  130.536 9.391 130.554 9.509 ;
     RECT  134.316 9.391 134.334 9.509 ;
     RECT  135.252 9.275 135.306 9.545 ;
     RECT  0.108 8.239 0.126 9.553 ;
     RECT  22.356 8.131 23.13 9.661 ;
     RECT  136.332 8.813 137.697 9.661 ;
     RECT  135.396 9.661 135.414 9.725 ;
     RECT  2.304 9.247 9.45 9.751 ;
     RECT  10.512 8.401 10.53 9.751 ;
     RECT  2.304 9.751 10.53 9.779 ;
     RECT  2.415 9.779 3.438 9.851 ;
     RECT  139.068 8.771 139.086 9.851 ;
     RECT  136.188 9.661 137.697 9.895 ;
     RECT  22.32 9.661 23.13 9.931 ;
     RECT  24.015 7.088 24.297 9.931 ;
     RECT  13.215 9.211 14.994 10.021 ;
     RECT  18.615 2.413 18.897 10.021 ;
     RECT  108.684 9.307 108.702 10.021 ;
     RECT  132.015 9.248 133.182 10.021 ;
     RECT  108.684 10.021 108.99 10.049 ;
     RECT  108.972 10.049 108.99 10.061 ;
     RECT  132.015 10.021 133.542 10.061 ;
     RECT  18.615 10.021 18.954 10.121 ;
     RECT  135.504 9.895 137.697 10.121 ;
     RECT  132.015 10.061 133.506 10.165 ;
     RECT  0.108 9.553 0.162 10.301 ;
     RECT  136.188 10.121 137.697 10.319 ;
     RECT  134.28 10.201 134.298 10.355 ;
     RECT  138.528 10.357 138.546 10.397 ;
     RECT  140.292 10.075 140.31 10.463 ;
     RECT  11.484 8.311 12.186 10.561 ;
     RECT  13.215 10.021 15.39 10.561 ;
     RECT  131.976 10.165 133.506 10.637 ;
     RECT  137.415 10.319 137.697 10.741 ;
     RECT  4.428 9.779 10.53 10.843 ;
     RECT  11.484 10.561 15.39 10.843 ;
     RECT  22.32 9.931 24.297 10.859 ;
     RECT  2.415 9.851 3.258 10.975 ;
     RECT  133.056 10.637 133.506 11.083 ;
     RECT  135.072 10.741 135.09 11.083 ;
     RECT  136.188 10.319 136.566 11.083 ;
     RECT  2.304 10.975 3.258 11.101 ;
     RECT  109.584 10.603 109.602 11.101 ;
     RECT  110.415 4.925 110.697 11.101 ;
     RECT  109.584 11.101 110.697 11.129 ;
     RECT  133.056 11.083 133.65 11.129 ;
     RECT  109.908 11.129 110.697 11.165 ;
     RECT  137.415 10.741 137.826 11.201 ;
     RECT  2.304 11.101 3.582 11.209 ;
     RECT  4.428 10.843 15.39 11.209 ;
     RECT  137.415 11.201 137.754 11.227 ;
     RECT  135.072 11.083 136.566 11.245 ;
     RECT  16.488 7.421 16.506 11.281 ;
     RECT  134.712 11.245 136.566 11.281 ;
     RECT  137.376 11.227 137.754 11.281 ;
     RECT  133.056 11.129 133.506 11.315 ;
     RECT  2.304 11.209 15.39 11.371 ;
     RECT  16.488 11.281 16.65 11.371 ;
     RECT  131.976 10.637 132.297 11.371 ;
     RECT  133.056 11.315 133.074 11.371 ;
     RECT  1.728 11.371 16.65 11.399 ;
     RECT  131.976 11.371 133.074 11.471 ;
     RECT  134.388 11.281 137.754 11.471 ;
     RECT  140.292 11.227 140.31 11.543 ;
     RECT  137.304 11.471 137.754 11.579 ;
     RECT  1.728 11.399 12.186 11.645 ;
     RECT  24.015 10.859 24.297 11.803 ;
     RECT  34.815 7.085 35.097 11.803 ;
     RECT  45.615 7.088 45.897 11.803 ;
     RECT  56.415 7.088 56.697 11.803 ;
     RECT  67.215 7.088 67.497 11.803 ;
     RECT  78.015 7.088 78.297 11.803 ;
     RECT  88.815 7.088 89.097 11.803 ;
     RECT  99.615 7.088 99.897 11.803 ;
     RECT  121.215 9.248 121.497 11.803 ;
     RECT  131.976 11.471 132.297 11.803 ;
     RECT  131.436 11.803 132.297 11.821 ;
     RECT  23.904 11.803 24.297 11.849 ;
     RECT  34.704 11.803 35.097 11.849 ;
     RECT  45.504 11.803 45.897 11.849 ;
     RECT  56.304 11.803 56.697 11.849 ;
     RECT  67.104 11.803 67.497 11.849 ;
     RECT  77.904 11.803 78.297 11.849 ;
     RECT  88.704 11.803 89.097 11.849 ;
     RECT  99.504 11.803 99.897 11.849 ;
     RECT  110.304 11.165 110.697 11.849 ;
     RECT  121.104 11.803 121.497 11.849 ;
     RECT  139.068 10.651 139.086 11.849 ;
     RECT  2.415 11.645 12.186 11.975 ;
     RECT  131.292 11.821 132.297 11.975 ;
     RECT  134.388 11.471 136.386 11.975 ;
     RECT  137.376 11.579 137.754 11.975 ;
     RECT  134.532 11.975 136.386 11.981 ;
     RECT  7.704 11.975 12.186 12.181 ;
     RECT  133.056 11.471 133.074 12.269 ;
     RECT  7.704 12.181 12.366 12.325 ;
     RECT  13.215 11.399 16.506 12.325 ;
     RECT  0.108 10.301 0.126 12.331 ;
     RECT  134.604 11.981 136.386 12.517 ;
     RECT  137.376 11.975 137.697 12.517 ;
     RECT  0.108 12.331 0.558 12.551 ;
     RECT  138.456 12.091 138.51 12.667 ;
     RECT  2.415 11.975 6.75 12.721 ;
     RECT  2.415 12.721 6.858 12.865 ;
     RECT  7.704 12.325 16.506 12.865 ;
     RECT  2.415 12.865 16.506 12.901 ;
     RECT  17.424 8.159 17.442 12.901 ;
     RECT  134.604 12.517 137.697 12.901 ;
     RECT  134.244 12.901 137.697 12.955 ;
     RECT  138.456 12.667 139.086 12.955 ;
     RECT  24.015 11.849 24.297 12.991 ;
     RECT  34.815 11.849 35.097 12.991 ;
     RECT  45.615 11.849 45.897 12.991 ;
     RECT  56.415 11.849 56.697 12.991 ;
     RECT  67.215 11.849 67.497 12.991 ;
     RECT  78.015 11.849 78.297 12.991 ;
     RECT  88.815 11.849 89.097 12.991 ;
     RECT  99.615 11.849 99.897 12.991 ;
     RECT  110.415 11.849 110.697 12.991 ;
     RECT  121.215 11.849 121.497 12.991 ;
     RECT  2.415 12.901 17.442 13.003 ;
     RECT  2.304 13.003 17.442 13.019 ;
     RECT  134.244 12.955 139.086 13.091 ;
     RECT  133.164 12.865 133.182 13.261 ;
     RECT  134.244 13.091 137.697 13.261 ;
     RECT  133.164 13.261 137.697 13.325 ;
     RECT  2.304 13.019 16.506 13.559 ;
     RECT  34.704 12.991 35.097 13.565 ;
     RECT  110.304 12.991 110.697 13.565 ;
     RECT  23.904 12.991 24.297 13.568 ;
     RECT  45.504 12.991 45.897 13.568 ;
     RECT  56.304 12.991 56.697 13.568 ;
     RECT  67.104 12.991 67.497 13.568 ;
     RECT  77.904 12.991 78.297 13.568 ;
     RECT  88.704 12.991 89.097 13.568 ;
     RECT  99.504 12.991 99.897 13.568 ;
     RECT  121.104 12.991 121.497 13.568 ;
     RECT  130.536 12.859 130.554 13.661 ;
     RECT  0.108 12.551 0.126 13.915 ;
     RECT  12.384 13.559 16.506 13.945 ;
     RECT  0.108 13.915 0.162 14.045 ;
     RECT  133.164 13.325 133.326 14.045 ;
     RECT  134.1 13.325 137.697 14.071 ;
     RECT  118.872 14.107 118.89 14.144 ;
     RECT  0.108 14.045 0.126 14.207 ;
     RECT  117.324 14.071 117.342 14.237 ;
     RECT  17.424 13.019 17.442 14.413 ;
     RECT  18.615 10.121 18.897 14.413 ;
     RECT  2.304 13.559 11.502 14.485 ;
     RECT  12.384 13.945 16.578 14.485 ;
     RECT  134.064 14.071 137.697 14.521 ;
     RECT  114.624 14.251 114.642 14.611 ;
     RECT  114.624 14.611 114.93 14.639 ;
     RECT  114.912 14.639 114.93 14.669 ;
     RECT  133.164 14.045 133.182 14.675 ;
     RECT  134.064 14.521 137.934 14.675 ;
     RECT  135.072 14.675 137.934 14.677 ;
     RECT  139.068 13.091 139.086 14.677 ;
     RECT  135.072 14.677 139.086 14.783 ;
     RECT  134.064 14.675 134.082 14.791 ;
     RECT  2.304 14.485 16.578 14.819 ;
     RECT  133.344 14.791 134.082 14.861 ;
     RECT  2.34 14.819 16.578 14.909 ;
     RECT  135.072 14.783 138.366 14.957 ;
     RECT  2.34 14.909 11.502 15.053 ;
     RECT  121.215 13.568 121.497 15.151 ;
     RECT  121.104 15.151 121.497 15.197 ;
     RECT  2.34 15.053 2.97 15.251 ;
     RECT  136.692 14.957 138.366 15.251 ;
     RECT  130.536 15.163 130.554 15.293 ;
     RECT  135.072 14.957 135.81 15.323 ;
     RECT  133.704 14.861 134.082 15.359 ;
     RECT  3.744 15.053 11.502 15.449 ;
     RECT  133.704 15.359 133.722 15.521 ;
     RECT  139.608 15.259 139.626 15.521 ;
     RECT  2.34 15.251 2.934 15.565 ;
     RECT  3.78 15.449 11.502 15.719 ;
     RECT  136.692 15.251 137.697 15.727 ;
     RECT  135.684 15.323 135.81 15.961 ;
     RECT  136.548 15.727 137.697 15.961 ;
     RECT  134.46 15.565 134.73 16.061 ;
     RECT  132.015 11.975 132.297 16.141 ;
     RECT  135.684 15.961 137.697 16.171 ;
     RECT  3.78 15.719 11.394 16.259 ;
     RECT  2.304 15.565 2.934 16.267 ;
     RECT  3.78 16.259 10.242 16.267 ;
     RECT  134.856 16.171 137.697 16.295 ;
     RECT  112.176 16.231 112.194 16.301 ;
     RECT  132.015 16.141 132.786 16.411 ;
     RECT  111.852 16.303 112.086 16.501 ;
     RECT  111.744 16.501 112.086 16.529 ;
     RECT  111.744 16.529 111.762 16.541 ;
     RECT  17.424 14.413 18.897 16.565 ;
     RECT  140.292 15.835 140.31 16.565 ;
     RECT  135.36 16.295 137.697 16.681 ;
     RECT  0.108 15.019 0.126 16.799 ;
     RECT  135.36 16.681 138.114 16.799 ;
     RECT  2.304 16.267 10.242 16.871 ;
     RECT  11.088 16.259 11.394 16.871 ;
     RECT  21.348 15.421 21.366 16.951 ;
     RECT  139.068 15.547 139.086 16.951 ;
     RECT  138.528 16.951 139.086 17.021 ;
     RECT  133.92 16.141 133.938 17.077 ;
     RECT  135.36 16.799 137.754 17.083 ;
     RECT  134.964 17.083 137.754 17.105 ;
     RECT  133.92 17.077 134.226 17.221 ;
     RECT  134.964 17.105 137.697 17.221 ;
     RECT  132.015 16.411 132.894 17.275 ;
     RECT  133.92 17.221 137.697 17.275 ;
     RECT  24.015 13.568 24.297 17.311 ;
     RECT  34.815 13.565 35.097 17.311 ;
     RECT  45.615 13.568 45.897 17.311 ;
     RECT  56.415 13.568 56.697 17.311 ;
     RECT  67.215 13.568 67.497 17.311 ;
     RECT  78.015 13.568 78.297 17.311 ;
     RECT  88.815 13.568 89.097 17.311 ;
     RECT  99.615 13.568 99.897 17.311 ;
     RECT  110.415 13.565 110.697 17.311 ;
     RECT  112.392 17.311 112.41 17.357 ;
     RECT  21.348 16.951 21.402 17.383 ;
     RECT  132.015 17.275 137.697 17.411 ;
     RECT  112.068 17.419 112.086 17.456 ;
     RECT  139.068 17.021 139.086 17.681 ;
     RECT  0.54 17.689 0.558 17.741 ;
     RECT  121.215 15.197 121.497 17.851 ;
     RECT  130.536 17.707 130.554 17.851 ;
     RECT  11.088 16.871 11.286 17.879 ;
     RECT  133.236 17.411 137.697 17.879 ;
     RECT  34.704 17.311 35.097 17.885 ;
     RECT  110.304 17.311 110.697 17.885 ;
     RECT  23.904 17.311 24.297 17.888 ;
     RECT  45.504 17.311 45.897 17.888 ;
     RECT  56.304 17.311 56.697 17.888 ;
     RECT  67.104 17.311 67.497 17.888 ;
     RECT  77.904 17.311 78.297 17.888 ;
     RECT  88.704 17.311 89.097 17.888 ;
     RECT  99.504 17.311 99.897 17.888 ;
     RECT  121.104 17.851 121.497 17.888 ;
     RECT  130.536 17.851 130.662 17.981 ;
     RECT  11.268 17.879 11.286 17.995 ;
     RECT  12.384 14.909 16.578 17.995 ;
     RECT  102.888 17.947 102.906 18.121 ;
     RECT  110.415 17.885 110.697 18.121 ;
     RECT  111.564 17.995 111.582 18.121 ;
     RECT  132.015 17.411 132.39 18.139 ;
     RECT  133.236 17.879 133.254 18.139 ;
     RECT  134.028 17.879 137.697 18.139 ;
     RECT  138.456 17.851 138.474 18.139 ;
     RECT  102.888 18.121 103.23 18.149 ;
     RECT  110.415 18.121 111.582 18.149 ;
     RECT  110.415 18.149 111.294 18.173 ;
     RECT  132.015 18.139 133.254 18.173 ;
     RECT  133.092 18.173 133.254 18.185 ;
     RECT  134.028 18.139 138.474 18.185 ;
     RECT  103.212 18.149 103.23 18.221 ;
     RECT  136.692 18.185 138.474 18.221 ;
     RECT  133.236 18.185 133.254 18.269 ;
     RECT  2.304 16.871 9.774 18.301 ;
     RECT  2.304 18.301 10.422 18.419 ;
     RECT  0.108 18.043 0.126 18.509 ;
     RECT  134.028 18.185 135.846 18.661 ;
     RECT  17.46 16.565 18.897 18.667 ;
     RECT  139.068 18.427 139.086 18.715 ;
     RECT  133.956 18.661 135.846 18.749 ;
     RECT  17.46 18.667 18.99 18.797 ;
     RECT  130.536 17.981 130.554 18.797 ;
     RECT  134.676 18.749 135.846 18.797 ;
     RECT  22.32 10.859 23.13 18.833 ;
     RECT  136.692 18.221 137.697 18.931 ;
     RECT  139.068 18.715 139.122 19.067 ;
     RECT  135.18 18.797 135.846 19.139 ;
     RECT  114.192 18.811 114.21 19.201 ;
     RECT  2.304 18.419 9.774 19.229 ;
     RECT  114.192 19.201 114.498 19.229 ;
     RECT  114.48 19.229 114.498 19.277 ;
     RECT  139.068 19.067 139.086 19.291 ;
     RECT  138.492 19.291 139.086 19.337 ;
     RECT  133.848 19.237 133.866 19.339 ;
     RECT  133.2 19.339 133.866 19.345 ;
     RECT  2.376 19.229 2.862 19.373 ;
     RECT  133.056 19.345 133.866 19.373 ;
     RECT  20.268 19.075 20.286 19.471 ;
     RECT  0.108 19.435 0.126 19.499 ;
     RECT  133.056 19.373 133.362 19.571 ;
     RECT  2.376 19.373 2.826 19.643 ;
     RECT  135.54 19.139 135.846 19.651 ;
     RECT  136.656 18.931 137.697 19.651 ;
     RECT  11.268 17.995 16.578 19.741 ;
     RECT  19.728 19.471 20.286 19.741 ;
     RECT  21.348 17.383 21.438 19.741 ;
     RECT  139.068 19.337 139.086 19.867 ;
     RECT  19.728 19.741 21.438 19.885 ;
     RECT  22.356 18.833 23.13 19.885 ;
     RECT  10.62 19.741 16.578 19.913 ;
     RECT  19.728 19.885 23.13 19.913 ;
     RECT  134.532 19.849 134.55 19.915 ;
     RECT  135.54 19.651 137.697 19.915 ;
     RECT  3.636 19.229 9.774 19.949 ;
     RECT  133.2 19.571 133.362 19.997 ;
     RECT  34.815 17.885 35.097 20.005 ;
     RECT  110.415 18.173 110.697 20.005 ;
     RECT  24.015 17.888 24.297 20.011 ;
     RECT  45.615 17.888 45.897 20.011 ;
     RECT  56.415 17.888 56.697 20.011 ;
     RECT  67.215 17.888 67.497 20.011 ;
     RECT  78.015 17.888 78.297 20.011 ;
     RECT  88.815 17.888 89.097 20.011 ;
     RECT  99.615 17.888 99.897 20.011 ;
     RECT  121.215 17.888 121.497 20.011 ;
     RECT  132.015 18.173 132.297 20.011 ;
     RECT  34.704 20.005 35.097 20.045 ;
     RECT  110.304 20.005 110.697 20.045 ;
     RECT  23.904 20.011 24.297 20.048 ;
     RECT  45.504 20.011 45.897 20.048 ;
     RECT  56.304 20.011 56.697 20.048 ;
     RECT  67.104 20.011 67.497 20.048 ;
     RECT  77.904 20.011 78.297 20.048 ;
     RECT  88.704 20.011 89.097 20.048 ;
     RECT  99.504 20.011 99.897 20.048 ;
     RECT  121.104 20.011 121.497 20.048 ;
     RECT  131.904 20.011 132.297 20.048 ;
     RECT  139.068 19.867 139.626 20.111 ;
     RECT  0.54 20.011 0.558 20.141 ;
     RECT  2.376 19.643 2.754 20.155 ;
     RECT  11.268 19.913 16.578 20.155 ;
     RECT  17.46 18.797 18.897 20.155 ;
     RECT  2.304 20.155 2.754 20.345 ;
     RECT  3.708 19.949 9.774 20.425 ;
     RECT  140.292 20.443 140.31 20.615 ;
     RECT  2.415 20.345 2.754 20.695 ;
     RECT  132.015 20.048 132.297 20.731 ;
     RECT  133.2 19.997 133.218 20.731 ;
     RECT  2.415 20.695 2.898 20.821 ;
     RECT  132.015 20.731 133.254 20.821 ;
     RECT  132.015 20.821 133.434 20.885 ;
     RECT  134.532 19.915 137.697 20.929 ;
     RECT  2.415 20.821 2.97 20.965 ;
     RECT  3.708 20.425 10.206 20.965 ;
     RECT  11.268 20.155 18.897 21.001 ;
     RECT  19.728 19.913 22.77 21.001 ;
     RECT  139.068 20.111 139.086 21.019 ;
     RECT  11.268 21.001 22.77 21.091 ;
     RECT  11.268 21.091 23.022 21.115 ;
     RECT  113.436 21.091 114.03 21.149 ;
     RECT  114.012 21.149 114.03 21.245 ;
     RECT  139.068 21.019 139.626 21.263 ;
     RECT  133.056 20.885 133.434 21.271 ;
     RECT  134.244 20.929 137.697 21.271 ;
     RECT  24.015 20.048 24.297 21.347 ;
     RECT  29.415 2.413 29.697 21.347 ;
     RECT  40.215 2.413 40.497 21.347 ;
     RECT  45.615 20.048 45.897 21.347 ;
     RECT  51.015 2.413 51.297 21.347 ;
     RECT  56.415 20.048 56.697 21.347 ;
     RECT  61.815 2.413 62.097 21.347 ;
     RECT  67.215 20.048 67.497 21.347 ;
     RECT  72.615 2.413 72.897 21.347 ;
     RECT  78.015 20.048 78.297 21.347 ;
     RECT  83.415 2.413 83.697 21.347 ;
     RECT  88.815 20.048 89.097 21.347 ;
     RECT  94.215 2.413 94.497 21.347 ;
     RECT  105.015 3.749 105.297 21.347 ;
     RECT  110.415 20.045 110.697 21.347 ;
     RECT  115.815 2.413 116.097 21.347 ;
     RECT  105.015 21.347 105.105 21.352 ;
     RECT  2.415 20.965 10.206 21.361 ;
     RECT  34.815 20.045 35.097 21.361 ;
     RECT  99.615 20.048 99.897 21.361 ;
     RECT  112.86 21.259 112.878 21.361 ;
     RECT  104.94 21.352 105.105 21.389 ;
     RECT  112.572 21.361 112.878 21.389 ;
     RECT  34.815 21.361 35.19 21.397 ;
     RECT  37.224 21.352 37.242 21.397 ;
     RECT  67.215 21.347 67.305 21.397 ;
     RECT  71.82 21.361 71.838 21.397 ;
     RECT  99.615 21.361 99.99 21.397 ;
     RECT  71.748 21.397 71.838 21.433 ;
     RECT  98.676 21.397 98.694 21.433 ;
     RECT  99.615 21.397 100.062 21.433 ;
     RECT  132.015 20.885 132.297 21.433 ;
     RECT  106.488 21.361 106.506 21.437 ;
     RECT  34.776 21.397 35.19 21.451 ;
     RECT  37.224 21.397 37.35 21.451 ;
     RECT  70.128 21.361 70.722 21.461 ;
     RECT  71.676 21.433 71.838 21.461 ;
     RECT  2.415 21.361 10.422 21.469 ;
     RECT  11.196 21.115 23.022 21.469 ;
     RECT  71.676 21.461 71.766 21.485 ;
     RECT  99.54 21.433 100.134 21.485 ;
     RECT  102.6 21.355 102.618 21.485 ;
     RECT  112.572 21.389 112.59 21.485 ;
     RECT  2.415 21.469 23.022 21.497 ;
     RECT  34.776 21.451 35.298 21.497 ;
     RECT  36.9 21.451 37.35 21.497 ;
     RECT  37.296 21.497 37.35 21.506 ;
     RECT  66.744 21.397 67.305 21.533 ;
     RECT  71.748 21.485 71.766 21.533 ;
     RECT  98.604 21.433 98.694 21.533 ;
     RECT  130.536 21.199 130.554 21.541 ;
     RECT  24.015 21.347 24.21 21.617 ;
     RECT  29.415 21.347 29.61 21.617 ;
     RECT  34.815 21.497 34.974 21.617 ;
     RECT  40.215 21.347 40.305 21.617 ;
     RECT  45.615 21.347 45.705 21.617 ;
     RECT  51.015 21.347 51.105 21.617 ;
     RECT  56.415 21.347 56.505 21.617 ;
     RECT  61.815 21.347 61.905 21.617 ;
     RECT  67.215 21.533 67.305 21.617 ;
     RECT  72.615 21.347 72.705 21.617 ;
     RECT  78.015 21.347 78.105 21.617 ;
     RECT  83.415 21.347 83.505 21.617 ;
     RECT  88.815 21.347 88.905 21.617 ;
     RECT  94.215 21.347 94.305 21.617 ;
     RECT  99.615 21.485 100.134 21.617 ;
     RECT  105.015 21.389 105.105 21.617 ;
     RECT  110.415 21.347 110.505 21.617 ;
     RECT  115.815 21.347 115.905 21.617 ;
     RECT  24.192 21.617 24.21 21.629 ;
     RECT  26.784 21.499 26.802 21.629 ;
     RECT  29.592 21.617 29.61 21.629 ;
     RECT  30.78 21.499 30.798 21.629 ;
     RECT  2.415 21.497 22.986 21.659 ;
     RECT  34.956 21.617 34.974 21.659 ;
     RECT  37.296 21.506 37.314 21.659 ;
     RECT  98.604 21.533 98.622 21.659 ;
     RECT  99.972 21.617 100.134 21.659 ;
     RECT  139.068 21.263 139.086 21.667 ;
     RECT  70.128 21.461 70.146 21.677 ;
     RECT  99.972 21.659 99.99 21.677 ;
     RECT  140.292 21.595 140.31 21.695 ;
     RECT  2.415 21.659 22.698 21.811 ;
     RECT  121.215 20.048 121.497 21.973 ;
     RECT  118.584 21.973 118.602 21.979 ;
     RECT  0.108 20.443 0.126 22.001 ;
     RECT  121.215 21.973 121.554 22.072 ;
     RECT  130.536 21.541 130.626 22.081 ;
     RECT  131.652 21.433 132.297 22.081 ;
     RECT  133.056 21.271 137.697 22.081 ;
     RECT  121.104 22.072 121.554 22.109 ;
     RECT  130.536 22.081 130.662 22.109 ;
     RECT  2.304 21.811 22.698 22.123 ;
     RECT  118.584 21.979 118.854 22.199 ;
     RECT  121.215 22.109 121.554 22.199 ;
     RECT  130.572 22.109 130.662 22.199 ;
     RECT  138.492 21.667 139.086 22.235 ;
     RECT  2.268 22.123 22.698 22.271 ;
     RECT  117.72 21.973 117.738 22.477 ;
     RECT  117.648 22.477 117.738 22.513 ;
     RECT  1.224 21.451 1.242 22.649 ;
     RECT  117.648 22.513 117.954 23.017 ;
     RECT  131.652 22.081 137.697 23.017 ;
     RECT  114.66 23.089 114.678 23.161 ;
     RECT  130.608 22.199 130.626 23.161 ;
     RECT  130.536 23.161 130.626 23.189 ;
     RECT  139.068 22.235 139.086 23.189 ;
     RECT  117.432 23.017 117.954 23.251 ;
     RECT  118.836 22.199 118.854 23.251 ;
     RECT  130.536 23.189 130.554 23.279 ;
     RECT  117.432 23.251 118.854 23.287 ;
     RECT  131.652 23.017 137.826 23.317 ;
     RECT  131.652 23.317 138.546 23.357 ;
     RECT  131.652 23.357 137.97 23.693 ;
     RECT  2.304 22.271 22.698 23.76 ;
     RECT  114.588 23.161 114.678 23.76 ;
     RECT  117.324 23.287 118.854 23.76 ;
     RECT  139.608 23.899 139.626 24.187 ;
     RECT  139.068 24.187 139.626 24.233 ;
     RECT  139.068 24.233 139.086 24.503 ;
     RECT  122.292 22.549 122.31 24.619 ;
     RECT  2.304 23.76 118.854 24.629 ;
     RECT  122.292 24.619 122.814 24.667 ;
     RECT  140.292 24.475 140.31 24.737 ;
     RECT  131.652 23.693 137.697 24.811 ;
     RECT  126.615 2.413 126.897 24.907 ;
     RECT  125.424 24.955 125.442 25.003 ;
     RECT  131.652 24.811 137.97 25.043 ;
     RECT  138.456 25.099 138.474 25.241 ;
     RECT  121.215 22.199 121.497 25.291 ;
     RECT  122.256 24.667 122.814 25.291 ;
     RECT  2.304 24.629 118.602 25.387 ;
     RECT  121.215 25.291 122.814 25.483 ;
     RECT  125.136 25.003 125.442 25.579 ;
     RECT  125.136 25.579 125.694 25.681 ;
     RECT  126.576 24.907 126.897 25.681 ;
     RECT  2.304 25.387 118.638 25.963 ;
     RECT  119.376 25.099 119.394 25.963 ;
     RECT  2.304 25.963 119.394 25.979 ;
     RECT  125.136 25.681 126.897 26.023 ;
     RECT  2.415 25.979 119.394 26.155 ;
     RECT  2.415 26.155 119.718 26.321 ;
     RECT  124.776 26.023 126.897 26.347 ;
     RECT  0.108 25.141 0.126 26.528 ;
     RECT  119.376 26.321 119.718 26.563 ;
     RECT  120.456 26.401 120.474 26.563 ;
     RECT  123.948 22.819 123.966 26.587 ;
     RECT  124.776 26.347 126.954 26.587 ;
     RECT  139.068 25.387 139.086 26.591 ;
     RECT  131.652 25.043 137.697 26.671 ;
     RECT  2.415 26.321 118.638 26.761 ;
     RECT  119.376 26.563 120.474 26.761 ;
     RECT  121.215 25.483 123.138 26.761 ;
     RECT  119.376 26.761 123.138 26.789 ;
     RECT  131.652 26.671 138.114 26.789 ;
     RECT  1.728 26.761 118.638 26.861 ;
     RECT  120.456 26.789 123.138 26.969 ;
     RECT  130.536 26.329 130.554 27.103 ;
     RECT  130.536 27.103 130.626 27.131 ;
     RECT  123.948 26.587 126.954 27.163 ;
     RECT  130.608 27.131 130.626 27.203 ;
     RECT  123.948 27.163 127.062 27.329 ;
     RECT  138.492 26.827 138.546 27.365 ;
     RECT  2.376 26.861 118.638 27.607 ;
     RECT  123.948 27.329 126.954 27.629 ;
     RECT  119.376 26.789 119.61 27.679 ;
     RECT  120.456 26.969 120.474 27.679 ;
     RECT  2.304 27.607 118.638 27.739 ;
     RECT  119.376 27.679 120.474 27.739 ;
     RECT  2.304 27.739 120.474 27.824 ;
     RECT  121.215 26.969 123.138 27.883 ;
     RECT  123.948 27.629 126.897 27.883 ;
     RECT  2.304 27.824 118.638 28.013 ;
     RECT  130.608 27.949 130.626 28.021 ;
     RECT  130.536 28.021 130.626 28.049 ;
     RECT  130.536 28.049 130.554 28.139 ;
     RECT  119.376 27.824 120.474 28.211 ;
     RECT  139.032 27.403 139.086 28.555 ;
     RECT  2.304 28.013 118.602 28.679 ;
     RECT  138.456 28.555 139.086 28.751 ;
     RECT  2.376 28.679 118.602 29.323 ;
     RECT  119.376 28.211 119.718 29.323 ;
     RECT  2.376 29.323 119.718 29.363 ;
     RECT  2.376 29.363 118.71 29.641 ;
     RECT  119.664 29.363 119.718 29.669 ;
     RECT  2.304 29.641 118.71 29.759 ;
     RECT  2.415 29.759 118.71 29.831 ;
     RECT  2.415 29.831 118.674 29.867 ;
     RECT  130.536 29.083 130.554 29.867 ;
     RECT  1.152 28.891 1.17 30.029 ;
     RECT  0.108 27.547 0.126 30.235 ;
     RECT  120.456 28.211 120.474 30.271 ;
     RECT  121.215 27.883 126.897 30.271 ;
     RECT  0.108 30.235 0.162 30.299 ;
     RECT  120.456 30.271 126.897 30.317 ;
     RECT  121.215 30.317 126.897 30.379 ;
     RECT  129.96 30.043 129.978 30.479 ;
     RECT  2.415 29.867 118.602 30.509 ;
     RECT  0.108 30.299 0.126 30.605 ;
     RECT  2.415 30.509 117.738 30.613 ;
     RECT  131.652 26.789 137.697 30.907 ;
     RECT  131.112 30.907 137.697 31.081 ;
     RECT  121.215 30.379 127.134 31.109 ;
     RECT  119.664 29.669 119.682 31.133 ;
     RECT  139.068 28.751 139.086 31.523 ;
     RECT  131.112 31.081 137.754 31.559 ;
     RECT  118.584 30.509 118.602 31.627 ;
     RECT  1.728 30.613 117.738 31.723 ;
     RECT  118.584 31.627 118.638 31.723 ;
     RECT  130.536 31.729 130.554 31.829 ;
     RECT  1.728 31.723 118.638 31.949 ;
     RECT  131.652 31.559 137.754 32.011 ;
     RECT  140.292 31.147 140.31 32.099 ;
     RECT  2.304 31.949 118.638 32.189 ;
     RECT  131.652 32.011 137.97 32.189 ;
     RECT  2.415 32.189 118.638 32.237 ;
     RECT  0.54 32.233 0.558 32.285 ;
     RECT  9.432 32.237 118.638 32.297 ;
     RECT  132.015 32.189 137.97 32.297 ;
     RECT  9.468 32.297 118.638 32.395 ;
     RECT  9.468 32.395 118.674 32.971 ;
     RECT  0.108 32.587 0.126 32.999 ;
     RECT  130.536 32.611 130.554 32.999 ;
     RECT  9.468 32.971 119.394 33.043 ;
     RECT  132.015 32.297 137.697 33.151 ;
     RECT  9.396 33.043 119.394 33.211 ;
     RECT  2.415 32.237 8.586 33.241 ;
     RECT  2.415 33.241 8.658 33.259 ;
     RECT  9.396 33.211 119.502 33.403 ;
     RECT  120.456 30.317 120.474 33.403 ;
     RECT  2.376 33.259 8.658 33.421 ;
     RECT  9.396 33.403 120.474 33.421 ;
     RECT  132.015 33.151 137.79 33.449 ;
     RECT  121.215 31.109 126.897 33.547 ;
     RECT  2.376 33.421 120.474 33.583 ;
     RECT  121.215 33.547 127.422 33.583 ;
     RECT  2.376 33.583 127.422 33.629 ;
     RECT  2.376 33.629 120.474 33.691 ;
     RECT  139.068 32.299 139.086 33.691 ;
     RECT  139.068 33.691 139.662 33.773 ;
     RECT  2.304 33.691 120.474 33.845 ;
     RECT  121.215 33.629 127.422 34.123 ;
     RECT  0.108 33.931 0.126 34.397 ;
     RECT  2.415 33.845 120.474 34.499 ;
     RECT  2.415 34.499 119.682 34.591 ;
     RECT  120.456 34.499 120.474 34.591 ;
     RECT  121.215 34.123 127.71 34.591 ;
     RECT  2.376 34.591 119.682 34.603 ;
     RECT  130.536 34.219 130.554 34.603 ;
     RECT  130.536 34.603 130.59 34.861 ;
     RECT  120.456 34.591 127.71 34.987 ;
     RECT  132.015 33.449 137.697 35.032 ;
     RECT  130.536 34.861 130.626 35.033 ;
     RECT  131.904 35.032 137.697 35.069 ;
     RECT  120.456 34.987 128.142 35.168 ;
     RECT  139.068 33.773 139.086 35.179 ;
     RECT  2.304 34.603 119.682 35.311 ;
     RECT  120.456 35.168 120.474 35.311 ;
     RECT  132.015 35.069 137.697 35.311 ;
     RECT  138.492 35.179 139.086 35.311 ;
     RECT  0.54 34.987 0.558 35.339 ;
     RECT  2.304 35.311 120.474 35.465 ;
     RECT  121.215 35.168 128.142 35.465 ;
     RECT  130.536 35.033 130.59 35.467 ;
     RECT  2.304 35.465 120.294 35.581 ;
     RECT  121.215 35.465 128.07 35.609 ;
     RECT  0.108 35.401 0.126 35.693 ;
     RECT  132.015 35.311 139.086 35.789 ;
     RECT  132.015 35.789 137.97 35.837 ;
     RECT  129.996 35.467 130.59 35.851 ;
     RECT  129.888 35.851 130.59 35.941 ;
     RECT  1.728 35.581 120.294 36.041 ;
     RECT  129.888 35.941 130.626 36.041 ;
     RECT  139.068 35.789 139.086 36.331 ;
     RECT  1.728 36.041 120.006 36.557 ;
     RECT  132.015 35.837 137.826 36.661 ;
     RECT  1.728 36.557 119.862 36.701 ;
     RECT  2.376 36.701 119.862 36.959 ;
     RECT  0.54 36.931 0.558 37.037 ;
     RECT  129.888 36.041 130.554 37.049 ;
     RECT  139.068 36.331 139.626 37.193 ;
     RECT  131.94 36.661 137.826 37.195 ;
     RECT  0.108 37.291 0.126 37.373 ;
     RECT  121.215 35.609 127.998 37.471 ;
     RECT  2.376 36.959 119.79 37.561 ;
     RECT  1.728 37.561 119.79 37.867 ;
     RECT  120.528 37.471 127.998 37.867 ;
     RECT  129.888 37.049 129.906 37.867 ;
     RECT  129.024 37.327 129.042 37.939 ;
     RECT  129.888 37.867 130.878 37.939 ;
     RECT  0.108 38.347 0.126 38.399 ;
     RECT  1.728 37.867 127.998 38.551 ;
     RECT  131.94 37.195 137.97 38.635 ;
     RECT  139.068 37.193 139.086 38.635 ;
     RECT  1.728 38.551 128.142 38.669 ;
     RECT  131.94 38.635 139.086 38.705 ;
     RECT  0.144 38.683 0.162 38.741 ;
     RECT  1.728 38.669 128.106 39.053 ;
     RECT  1.764 39.053 128.106 39.209 ;
     RECT  129.024 37.939 130.878 39.317 ;
     RECT  1.764 39.209 128.07 39.389 ;
     RECT  0.108 39.691 0.126 39.749 ;
     RECT  131.94 38.705 137.826 40.027 ;
     RECT  139.068 38.705 139.086 40.027 ;
     RECT  2.304 39.389 128.07 40.127 ;
     RECT  131.94 40.027 139.086 40.127 ;
     RECT  6.804 40.127 128.07 40.135 ;
     RECT  129.024 39.317 129.906 40.135 ;
     RECT  2.304 40.127 6.066 40.163 ;
     RECT  130.788 39.317 130.878 40.171 ;
     RECT  131.94 40.127 137.826 40.171 ;
     RECT  2.304 40.163 6.03 40.369 ;
     RECT  0.54 40.363 0.558 40.469 ;
     RECT  140.292 39.787 140.31 40.667 ;
     RECT  2.196 40.369 6.03 40.733 ;
     RECT  139.068 40.127 139.086 40.901 ;
     RECT  2.415 40.733 6.03 40.981 ;
     RECT  6.804 40.135 129.906 40.981 ;
     RECT  2.415 40.981 129.906 41.171 ;
     RECT  139.608 41.227 139.626 41.441 ;
     RECT  2.415 41.171 121.497 41.521 ;
     RECT  140.292 41.515 140.31 41.945 ;
     RECT  130.788 40.171 137.826 42.091 ;
     RECT  130.788 42.091 138.15 42.323 ;
     RECT  1.728 41.521 121.497 42.359 ;
     RECT  0.108 41.035 0.126 42.461 ;
     RECT  122.652 41.171 129.906 42.565 ;
     RECT  130.788 42.323 137.826 42.565 ;
     RECT  139.068 42.379 139.086 42.755 ;
     RECT  1.728 42.359 8.097 42.797 ;
     RECT  1.764 42.797 8.097 43.133 ;
     RECT  2.268 43.133 8.097 43.231 ;
     RECT  8.82 42.359 121.497 43.231 ;
     RECT  122.652 42.565 137.826 43.259 ;
     RECT  139.608 42.955 139.626 43.331 ;
     RECT  2.268 43.231 121.497 43.469 ;
     RECT  2.34 43.469 121.497 43.529 ;
     RECT  139.068 43.531 139.086 43.673 ;
     RECT  130.788 43.259 137.826 43.807 ;
     RECT  130.788 43.807 138.546 43.853 ;
     RECT  0.108 43.771 0.126 44.141 ;
     RECT  2.376 43.529 121.497 44.311 ;
     RECT  140.292 44.107 140.31 44.411 ;
     RECT  1.728 44.311 121.497 44.477 ;
     RECT  2.268 44.477 121.497 44.609 ;
     RECT  5.436 44.609 121.497 44.645 ;
     RECT  2.268 44.609 4.626 44.813 ;
     RECT  5.436 44.645 9.594 44.915 ;
     RECT  130.788 43.853 137.934 44.971 ;
     RECT  139.068 44.395 139.086 44.971 ;
     RECT  5.544 44.915 9.594 44.987 ;
     RECT  130.788 44.971 139.086 45.221 ;
     RECT  139.068 45.221 139.086 45.491 ;
     RECT  2.376 44.813 4.626 45.499 ;
     RECT  2.376 45.499 4.698 45.535 ;
     RECT  0.108 45.112 0.126 45.661 ;
     RECT  140.292 45.547 140.31 45.725 ;
     RECT  5.796 44.987 9.594 45.805 ;
     RECT  10.368 44.645 121.497 45.805 ;
     RECT  5.796 45.805 121.497 45.841 ;
     RECT  2.304 45.535 4.698 45.959 ;
     RECT  2.34 45.959 4.698 46.069 ;
     RECT  2.34 46.069 4.734 46.109 ;
     RECT  5.76 45.841 121.497 46.111 ;
     RECT  0.108 45.661 0.162 46.157 ;
     RECT  139.104 45.805 139.122 46.157 ;
     RECT  5.688 46.111 121.497 46.381 ;
     RECT  130.788 45.221 137.826 46.411 ;
     RECT  130.788 46.411 137.97 46.543 ;
     RECT  130.788 46.543 138.546 46.733 ;
     RECT  0.108 46.157 0.126 46.829 ;
     RECT  122.652 43.259 129.906 46.921 ;
     RECT  130.788 46.733 137.826 46.921 ;
     RECT  2.34 46.109 4.698 47.011 ;
     RECT  122.652 46.921 137.826 47.039 ;
     RECT  139.068 46.987 139.086 47.111 ;
     RECT  0.54 47.083 0.558 47.165 ;
     RECT  1.728 47.011 4.698 47.191 ;
     RECT  5.544 46.381 121.497 47.191 ;
     RECT  140.292 47.275 140.31 47.345 ;
     RECT  1.728 47.191 121.497 47.501 ;
     RECT  130.788 47.039 137.826 47.563 ;
     RECT  2.304 47.501 121.497 47.597 ;
     RECT  2.304 47.597 9.882 47.759 ;
     RECT  10.8 47.597 121.497 47.759 ;
     RECT  130.788 47.563 137.97 47.848 ;
     RECT  5.724 47.759 9.882 47.849 ;
     RECT  5.724 47.849 9.774 47.885 ;
     RECT  130.788 47.848 138.51 47.885 ;
     RECT  0.108 47.803 0.126 48.191 ;
     RECT  139.068 48.139 139.086 48.191 ;
     RECT  2.304 47.759 4.914 48.269 ;
     RECT  2.304 48.269 4.482 48.361 ;
     RECT  1.728 48.361 4.482 48.509 ;
     RECT  5.724 47.885 9.702 48.541 ;
     RECT  2.268 48.509 4.482 48.659 ;
     RECT  130.788 47.885 137.898 48.703 ;
     RECT  5.292 48.541 9.702 48.731 ;
     RECT  139.608 48.427 139.626 48.803 ;
     RECT  2.268 48.659 3.618 48.845 ;
     RECT  2.304 48.845 3.618 48.929 ;
     RECT  10.836 47.759 121.497 48.937 ;
     RECT  2.304 48.929 3.042 49.001 ;
     RECT  130.788 48.703 138.546 49.003 ;
     RECT  10.404 48.937 121.497 49.037 ;
     RECT  122.652 47.039 129.906 49.045 ;
     RECT  130.788 49.003 139.086 49.045 ;
     RECT  4.464 48.659 4.482 49.081 ;
     RECT  5.292 48.731 9.63 49.081 ;
     RECT  2.34 49.001 3.042 49.109 ;
     RECT  122.652 49.045 139.086 49.199 ;
     RECT  130.788 49.199 139.086 49.541 ;
     RECT  4.464 49.081 9.63 49.549 ;
     RECT  4.464 49.549 9.702 49.621 ;
     RECT  0.108 49.147 0.126 49.819 ;
     RECT  139.032 49.541 139.086 49.883 ;
     RECT  0.108 49.819 0.558 49.919 ;
     RECT  4.248 49.621 9.702 49.981 ;
     RECT  10.548 49.037 121.497 49.981 ;
     RECT  130.788 49.541 137.97 50.323 ;
     RECT  139.032 49.883 139.05 50.323 ;
     RECT  4.248 49.981 121.497 50.395 ;
     RECT  2.415 49.109 3.042 50.431 ;
     RECT  130.788 50.323 139.05 50.477 ;
     RECT  4.068 50.395 121.497 50.585 ;
     RECT  2.415 50.431 3.186 50.701 ;
     RECT  4.068 50.585 6.858 50.701 ;
     RECT  0.108 49.919 0.126 50.863 ;
     RECT  2.415 50.701 6.858 51.205 ;
     RECT  0.108 50.863 0.558 51.245 ;
     RECT  2.376 51.205 6.858 51.367 ;
     RECT  7.815 50.585 121.497 51.367 ;
     RECT  122.652 49.199 129.906 51.367 ;
     RECT  130.788 50.477 137.826 51.367 ;
     RECT  2.376 51.367 121.497 51.475 ;
     RECT  122.652 51.367 137.826 51.511 ;
     RECT  2.304 51.475 121.497 51.539 ;
     RECT  122.652 51.511 137.862 51.539 ;
     RECT  139.068 50.779 139.086 51.773 ;
     RECT  1.152 51.883 1.17 52.213 ;
     RECT  2.304 51.539 3.834 52.213 ;
     RECT  130.788 51.539 137.862 52.213 ;
     RECT  0.108 51.245 0.126 52.253 ;
     RECT  130.788 52.213 138.546 52.253 ;
     RECT  5.112 51.539 121.497 52.313 ;
     RECT  1.152 52.213 3.834 52.321 ;
     RECT  1.152 52.321 3.942 52.411 ;
     RECT  1.152 52.411 4.014 52.447 ;
     RECT  139.608 51.931 139.626 52.507 ;
     RECT  1.152 52.447 4.662 52.589 ;
     RECT  122.652 51.539 129.906 52.619 ;
     RECT  1.152 52.589 1.17 52.681 ;
     RECT  2.304 52.589 4.662 52.733 ;
     RECT  139.032 52.507 139.626 52.817 ;
     RECT  0.54 52.681 1.17 52.925 ;
     RECT  1.152 52.925 1.17 53.159 ;
     RECT  0.108 53.227 0.126 53.357 ;
     RECT  130.788 52.253 137.898 53.371 ;
     RECT  139.032 52.817 139.086 53.371 ;
     RECT  2.304 52.733 4.194 53.393 ;
     RECT  130.788 53.371 139.086 53.393 ;
     RECT  5.544 52.313 121.497 53.491 ;
     RECT  2.304 53.393 3.366 53.555 ;
     RECT  5.22 53.491 121.497 53.597 ;
     RECT  122.652 52.619 129.114 53.663 ;
     RECT  4.104 53.393 4.194 53.671 ;
     RECT  2.304 53.555 3.294 53.761 ;
     RECT  4.104 53.671 4.266 53.761 ;
     RECT  4.104 53.761 4.374 53.795 ;
     RECT  130.788 53.393 138.546 53.981 ;
     RECT  4.248 53.795 4.374 54.095 ;
     RECT  1.728 53.761 3.294 54.269 ;
     RECT  2.304 54.269 3.294 54.301 ;
     RECT  5.22 53.597 5.706 54.331 ;
     RECT  4.68 54.331 5.706 54.371 ;
     RECT  2.304 54.301 3.366 54.635 ;
     RECT  5.148 54.371 5.706 54.679 ;
     RECT  6.444 53.597 121.497 54.679 ;
     RECT  130.788 53.981 137.826 54.811 ;
     RECT  130.788 54.811 137.97 55.013 ;
     RECT  122.652 53.663 128.718 55.049 ;
     RECT  2.304 54.635 3.294 55.111 ;
     RECT  4.248 55.255 4.266 55.453 ;
     RECT  4.248 55.453 4.302 55.561 ;
     RECT  122.652 55.049 128.07 55.589 ;
     RECT  1.728 55.111 3.294 55.795 ;
     RECT  4.176 55.561 4.302 55.795 ;
     RECT  5.148 54.679 121.497 55.795 ;
     RECT  1.728 55.795 121.497 56.021 ;
     RECT  139.068 54.235 139.086 56.093 ;
     RECT  130.788 55.013 137.826 56.101 ;
     RECT  130.788 56.101 137.934 56.533 ;
     RECT  130.788 56.533 138.546 56.573 ;
     RECT  1.728 56.021 3.438 56.621 ;
     RECT  139.608 56.251 139.626 56.633 ;
     RECT  4.248 56.021 121.497 56.909 ;
     RECT  2.304 56.621 3.438 56.939 ;
     RECT  2.34 56.939 3.438 57.029 ;
     RECT  123.3 55.589 128.07 57.209 ;
     RECT  129.888 52.619 129.906 57.271 ;
     RECT  130.788 56.573 137.826 57.271 ;
     RECT  123.3 57.209 125.586 57.299 ;
     RECT  129.888 57.271 137.826 57.379 ;
     RECT  139.068 56.827 139.086 57.379 ;
     RECT  129.888 57.379 139.086 57.437 ;
     RECT  129.888 57.437 137.826 57.479 ;
     RECT  2.415 57.029 3.438 57.541 ;
     RECT  0.108 54.571 0.126 57.811 ;
     RECT  2.415 57.541 3.618 57.955 ;
     RECT  2.304 57.955 3.618 58.109 ;
     RECT  4.572 56.909 121.497 58.123 ;
     RECT  130.788 57.479 137.826 58.189 ;
     RECT  130.788 58.189 138.114 58.495 ;
     RECT  139.032 57.437 139.086 58.495 ;
     RECT  0.108 57.811 0.162 58.559 ;
     RECT  130.788 58.495 139.086 58.589 ;
     RECT  2.304 58.109 3.186 58.621 ;
     RECT  0.144 58.559 0.162 58.721 ;
     RECT  4.356 58.123 121.497 58.801 ;
     RECT  4.14 58.801 121.497 58.991 ;
     RECT  1.728 58.621 3.186 59.021 ;
     RECT  4.14 58.991 119.106 59.071 ;
     RECT  1.764 59.021 3.186 59.357 ;
     RECT  124.02 57.299 125.586 59.369 ;
     RECT  2.34 59.357 3.186 59.459 ;
     RECT  119.916 58.991 121.497 59.495 ;
     RECT  130.788 58.589 137.826 59.503 ;
     RECT  139.068 58.589 139.086 59.503 ;
     RECT  2.415 59.459 3.186 59.737 ;
     RECT  3.996 59.071 119.106 59.737 ;
     RECT  130.788 59.503 139.086 59.741 ;
     RECT  139.068 59.741 139.086 59.809 ;
     RECT  0.108 59.659 0.126 59.995 ;
     RECT  139.068 59.809 139.122 60.029 ;
     RECT  0.108 59.995 0.558 60.365 ;
     RECT  2.415 59.737 119.106 60.385 ;
     RECT  124.02 59.369 124.11 60.449 ;
     RECT  2.304 60.385 119.106 60.461 ;
     RECT  119.952 59.495 121.497 60.511 ;
     RECT  130.788 59.741 137.826 60.571 ;
     RECT  130.788 60.571 137.97 60.583 ;
     RECT  2.304 60.461 118.782 60.719 ;
     RECT  130.788 60.583 138.042 60.809 ;
     RECT  130.788 60.809 137.97 60.917 ;
     RECT  2.304 60.719 3.87 61.349 ;
     RECT  4.896 60.719 118.782 61.483 ;
     RECT  119.736 60.511 121.497 61.483 ;
     RECT  2.376 61.349 3.87 61.501 ;
     RECT  4.896 61.483 121.497 61.501 ;
     RECT  0.54 60.365 0.558 61.591 ;
     RECT  0.108 61.591 0.558 61.709 ;
     RECT  140.292 61.435 140.31 61.727 ;
     RECT  124.02 60.449 124.074 61.799 ;
     RECT  130.788 60.917 137.826 61.933 ;
     RECT  139.068 60.029 139.086 61.933 ;
     RECT  130.788 61.933 139.086 62.033 ;
     RECT  130.788 62.033 138.546 62.045 ;
     RECT  0.54 61.709 0.558 62.203 ;
     RECT  2.376 61.501 121.497 62.231 ;
     RECT  2.376 62.231 118.782 62.339 ;
     RECT  0.54 62.203 1.17 62.401 ;
     RECT  2.376 62.339 5.238 62.401 ;
     RECT  0.54 62.401 5.238 62.501 ;
     RECT  119.52 62.231 121.497 62.582 ;
     RECT  6.084 62.339 118.782 62.669 ;
     RECT  0.54 62.501 0.558 62.683 ;
     RECT  6.084 62.669 20.466 62.735 ;
     RECT  140.292 62.587 140.31 62.771 ;
     RECT  0.108 62.683 0.558 62.813 ;
     RECT  130.788 62.045 138.51 62.815 ;
     RECT  125.1 59.369 125.586 62.879 ;
     RECT  130.788 62.815 138.546 62.909 ;
     RECT  0.54 62.813 0.558 63.053 ;
     RECT  130.788 62.909 138.51 63.197 ;
     RECT  21.6 62.669 118.782 63.307 ;
     RECT  119.592 62.582 121.497 63.307 ;
     RECT  1.728 62.501 5.238 63.389 ;
     RECT  21.6 63.307 121.497 63.499 ;
     RECT  1.764 63.389 5.238 63.661 ;
     RECT  6.084 62.735 20.43 63.661 ;
     RECT  21.276 63.499 121.497 63.661 ;
     RECT  1.764 63.661 121.497 63.725 ;
     RECT  21.312 63.725 121.497 63.851 ;
     RECT  139.068 63.739 139.086 63.851 ;
     RECT  129.888 57.479 129.906 63.931 ;
     RECT  130.788 63.197 137.97 63.931 ;
     RECT  125.352 62.879 125.586 63.959 ;
     RECT  21.6 63.851 121.497 64.049 ;
     RECT  129.888 63.931 137.97 64.315 ;
     RECT  21.672 64.049 121.497 64.319 ;
     RECT  129.888 64.315 138.51 64.391 ;
     RECT  129.888 64.391 137.97 64.697 ;
     RECT  2.415 63.725 20.43 64.705 ;
     RECT  21.672 64.319 118.89 64.824 ;
     RECT  130.788 64.697 137.97 65.003 ;
     RECT  21.672 64.824 22.23 65.039 ;
     RECT  2.304 64.705 20.43 65.129 ;
     RECT  117.72 64.824 118.89 65.129 ;
     RECT  140.292 64.891 140.31 65.165 ;
     RECT  132.015 65.003 137.97 65.179 ;
     RECT  126.432 57.209 128.07 65.201 ;
     RECT  2.304 65.129 20.358 65.435 ;
     RECT  120.024 64.319 121.497 65.435 ;
     RECT  2.304 65.435 18.897 65.443 ;
     RECT  129.888 64.697 129.906 65.551 ;
     RECT  130.788 65.003 130.806 65.551 ;
     RECT  21.924 65.039 22.23 65.579 ;
     RECT  21.996 65.579 22.23 65.669 ;
     RECT  139.608 65.467 139.626 65.741 ;
     RECT  132.015 65.179 138.474 65.755 ;
     RECT  2.268 65.443 18.897 65.789 ;
     RECT  19.944 65.435 20.358 65.975 ;
     RECT  132.015 65.755 139.086 66.077 ;
     RECT  139.068 66.077 139.086 66.083 ;
     RECT  0.108 64.021 0.126 66.125 ;
     RECT  120.528 65.435 121.497 66.173 ;
     RECT  20.34 65.975 20.358 66.245 ;
     RECT  129.888 65.551 130.806 66.245 ;
     RECT  132.015 66.077 137.826 66.479 ;
     RECT  133.452 66.479 137.826 66.509 ;
     RECT  133.524 66.509 137.826 66.587 ;
     RECT  140.292 66.331 140.31 66.619 ;
     RECT  2.304 65.789 18.897 66.631 ;
     RECT  2.304 66.631 19.206 66.749 ;
     RECT  2.415 66.749 19.206 66.893 ;
     RECT  140.256 66.619 140.31 66.893 ;
     RECT  50.724 66.859 50.742 66.943 ;
     RECT  45.615 66.943 45.705 66.991 ;
     RECT  46.764 66.811 46.782 66.991 ;
     RECT  94.215 66.943 94.305 66.991 ;
     RECT  45.615 66.991 46.782 67.019 ;
     RECT  54.612 66.859 54.63 67.019 ;
     RECT  117.9 65.129 118.89 67.019 ;
     RECT  45.615 67.019 46.386 67.037 ;
     RECT  50.724 66.943 51.105 67.037 ;
     RECT  70.416 66.991 70.434 67.037 ;
     RECT  129.888 66.245 130.626 67.055 ;
     RECT  99.615 66.943 99.705 67.099 ;
     RECT  94.215 66.991 94.374 67.135 ;
     RECT  95.112 67.099 95.13 67.135 ;
     RECT  99.576 67.099 99.705 67.135 ;
     RECT  94.215 67.135 95.166 67.171 ;
     RECT  98.748 67.135 98.766 67.171 ;
     RECT  99.54 67.135 99.705 67.171 ;
     RECT  54.288 67.135 54.306 67.181 ;
     RECT  0.54 67.099 0.558 67.199 ;
     RECT  133.524 66.587 134.766 67.199 ;
     RECT  24.015 66.943 24.105 67.213 ;
     RECT  29.415 66.943 29.505 67.213 ;
     RECT  34.815 66.943 34.905 67.213 ;
     RECT  40.215 66.943 40.305 67.213 ;
     RECT  51.015 67.037 51.105 67.213 ;
     RECT  56.415 66.943 56.505 67.213 ;
     RECT  61.815 66.943 61.905 67.213 ;
     RECT  67.215 66.943 67.305 67.213 ;
     RECT  72.615 66.943 72.705 67.213 ;
     RECT  78.015 66.943 78.105 67.213 ;
     RECT  83.415 66.943 83.505 67.213 ;
     RECT  88.815 66.943 88.905 67.213 ;
     RECT  105.015 66.943 105.105 67.213 ;
     RECT  110.415 66.943 110.505 67.213 ;
     RECT  115.815 66.943 115.905 67.213 ;
     RECT  132.015 66.479 132.498 67.243 ;
     RECT  70.128 67.171 70.146 67.277 ;
     RECT  118.764 67.019 118.782 67.289 ;
     RECT  82.224 67.291 82.242 67.297 ;
     RECT  83.415 67.213 83.697 67.297 ;
     RECT  94.215 67.171 95.526 67.297 ;
     RECT  98.748 67.171 99.99 67.297 ;
     RECT  105.015 67.213 105.297 67.297 ;
     RECT  91.98 67.297 91.998 67.333 ;
     RECT  98.748 67.297 100.422 67.333 ;
     RECT  105.015 67.297 105.678 67.333 ;
     RECT  105.015 67.333 106.038 67.369 ;
     RECT  131.472 67.243 132.498 67.369 ;
     RECT  133.56 67.199 134.766 67.382 ;
     RECT  135.54 66.587 137.826 67.382 ;
     RECT  117.792 67.171 117.81 67.397 ;
     RECT  84.852 67.369 84.87 67.405 ;
     RECT  103.14 67.333 103.158 67.405 ;
     RECT  103.896 67.333 103.914 67.405 ;
     RECT  104.796 67.369 106.038 67.405 ;
     RECT  122.508 67.027 122.526 67.433 ;
     RECT  80.712 67.274 80.73 67.441 ;
     RECT  81.648 67.297 82.242 67.441 ;
     RECT  82.98 67.297 83.697 67.441 ;
     RECT  84.636 67.405 84.87 67.441 ;
     RECT  86.616 67.369 86.634 67.441 ;
     RECT  87.516 67.297 87.894 67.441 ;
     RECT  88.815 67.213 89.097 67.441 ;
     RECT  91.224 67.369 91.242 67.441 ;
     RECT  91.98 67.333 92.214 67.441 ;
     RECT  98.748 67.333 100.638 67.441 ;
     RECT  104.796 67.405 106.218 67.441 ;
     RECT  131.472 67.369 132.822 67.469 ;
     RECT  34.815 67.213 35.097 67.525 ;
     RECT  24.015 67.213 24.297 67.531 ;
     RECT  45.615 67.037 45.897 67.531 ;
     RECT  56.415 67.213 56.697 67.531 ;
     RECT  67.215 67.213 67.497 67.531 ;
     RECT  80.712 67.441 84.87 67.531 ;
     RECT  85.608 67.441 85.626 67.531 ;
     RECT  98.748 67.441 100.962 67.531 ;
     RECT  124.02 61.799 124.038 67.559 ;
     RECT  129.888 67.055 130.554 67.559 ;
     RECT  34.704 67.525 35.097 67.565 ;
     RECT  103.14 67.405 103.914 67.567 ;
     RECT  104.796 67.441 106.578 67.567 ;
     RECT  23.904 67.531 24.297 67.568 ;
     RECT  45.504 67.531 45.897 67.568 ;
     RECT  56.304 67.531 56.697 67.568 ;
     RECT  67.104 67.531 67.497 67.568 ;
     RECT  131.472 67.469 132.498 67.595 ;
     RECT  133.56 67.382 137.826 67.603 ;
     RECT  87.516 67.441 89.097 67.639 ;
     RECT  98.604 67.531 100.962 67.639 ;
     RECT  102.312 67.531 102.33 67.639 ;
     RECT  86.616 67.441 86.778 67.675 ;
     RECT  87.516 67.639 89.73 67.675 ;
     RECT  93.348 67.297 95.526 67.675 ;
     RECT  98.604 67.639 102.33 67.675 ;
     RECT  103.14 67.567 106.578 67.675 ;
     RECT  93.348 67.675 95.994 67.711 ;
     RECT  98.604 67.675 106.578 67.711 ;
     RECT  80.712 67.531 85.626 67.801 ;
     RECT  86.616 67.675 89.73 67.801 ;
     RECT  91.224 67.441 92.538 67.801 ;
     RECT  93.348 67.711 96.174 67.801 ;
     RECT  98.604 67.711 107.046 67.801 ;
     RECT  0.108 67.261 0.126 67.829 ;
     RECT  131.616 67.595 132.498 67.829 ;
     RECT  96.912 67.801 97.398 67.837 ;
     RECT  133.56 67.603 137.934 67.837 ;
     RECT  139.068 66.907 139.086 67.837 ;
     RECT  140.292 66.893 140.31 67.865 ;
     RECT  110.415 67.213 110.697 67.867 ;
     RECT  80.712 67.801 89.73 67.873 ;
     RECT  98.316 67.801 107.046 67.873 ;
     RECT  91.08 67.801 96.174 67.915 ;
     RECT  96.912 67.837 97.47 67.915 ;
     RECT  2.415 66.893 18.897 67.945 ;
     RECT  76.968 67.531 76.986 67.945 ;
     RECT  80.712 67.873 89.802 67.945 ;
     RECT  91.08 67.915 97.47 67.945 ;
     RECT  98.316 67.873 107.19 67.945 ;
     RECT  108.612 67.873 108.63 67.945 ;
     RECT  80.712 67.945 97.47 67.981 ;
     RECT  2.304 67.945 18.897 68.009 ;
     RECT  98.316 67.945 107.226 68.071 ;
     RECT  14.832 68.009 18.897 68.099 ;
     RECT  108.396 67.945 108.63 68.107 ;
     RECT  133.56 67.837 139.086 68.135 ;
     RECT  76.968 67.945 77.166 68.179 ;
     RECT  78.015 67.213 78.297 68.179 ;
     RECT  108.396 68.107 108.666 68.179 ;
     RECT  98.316 68.071 107.262 68.203 ;
     RECT  108.324 68.179 108.666 68.215 ;
     RECT  76.968 68.179 78.297 68.251 ;
     RECT  80.496 67.981 97.47 68.251 ;
     RECT  98.316 68.203 107.298 68.251 ;
     RECT  108.036 68.215 108.666 68.251 ;
     RECT  110.415 67.867 111.258 68.251 ;
     RECT  2.304 68.009 14.094 68.341 ;
     RECT  112.5 68.251 112.518 68.369 ;
     RECT  75.96 68.347 75.978 68.377 ;
     RECT  76.968 68.251 79.254 68.377 ;
     RECT  108.036 68.251 108.918 68.377 ;
     RECT  14.94 68.099 18.897 68.405 ;
     RECT  75.96 68.377 79.29 68.405 ;
     RECT  76.392 68.405 79.29 68.413 ;
     RECT  80.496 68.251 107.298 68.413 ;
     RECT  108.036 68.377 108.954 68.413 ;
     RECT  110.415 68.251 111.294 68.413 ;
     RECT  112.032 68.377 112.05 68.413 ;
     RECT  110.415 68.413 112.05 68.449 ;
     RECT  1.728 68.341 14.094 68.477 ;
     RECT  80.496 68.413 108.954 68.485 ;
     RECT  109.692 68.449 112.05 68.485 ;
     RECT  76.392 68.413 79.47 68.521 ;
     RECT  80.496 68.485 112.05 68.521 ;
     RECT  129.888 67.559 129.906 68.521 ;
     RECT  133.56 68.135 134.802 68.521 ;
     RECT  125.568 63.959 125.586 68.639 ;
     RECT  129.888 68.521 130.554 68.639 ;
     RECT  133.488 68.521 134.802 68.639 ;
     RECT  132.015 67.829 132.498 68.755 ;
     RECT  132.015 68.755 132.57 68.791 ;
     RECT  132.015 68.791 132.714 68.909 ;
     RECT  2.304 68.477 14.094 68.957 ;
     RECT  135.648 68.135 139.086 68.957 ;
     RECT  133.56 68.639 134.802 68.971 ;
     RECT  135.648 68.957 137.97 68.971 ;
     RECT  139.068 68.957 139.086 68.981 ;
     RECT  132.015 68.909 132.498 69.089 ;
     RECT  3.852 68.957 14.094 69.223 ;
     RECT  15.012 68.405 18.897 69.223 ;
     RECT  3.852 69.223 18.897 69.251 ;
     RECT  76.392 68.521 112.05 69.331 ;
     RECT  0.108 68.779 0.126 69.359 ;
     RECT  76.392 69.331 112.23 69.421 ;
     RECT  3.852 69.251 16.542 69.557 ;
     RECT  75.564 69.565 75.582 69.601 ;
     RECT  2.304 68.957 3.006 69.691 ;
     RECT  3.852 69.557 14.526 69.691 ;
     RECT  1.728 69.691 14.526 69.719 ;
     RECT  133.56 68.971 137.97 69.719 ;
     RECT  139.068 69.787 139.086 69.827 ;
     RECT  74.916 69.601 75.582 69.829 ;
     RECT  133.56 69.719 133.578 69.829 ;
     RECT  74.772 69.829 75.582 69.835 ;
     RECT  132.015 69.089 132.354 69.835 ;
     RECT  133.416 69.829 133.578 69.869 ;
     RECT  76.356 69.421 112.23 69.871 ;
     RECT  129.888 68.639 129.906 69.871 ;
     RECT  131.796 69.835 132.354 69.871 ;
     RECT  76.356 69.871 112.446 69.989 ;
     RECT  126.432 65.201 127.53 69.989 ;
     RECT  129.888 69.871 130.554 69.989 ;
     RECT  131.796 69.871 132.75 69.989 ;
     RECT  134.46 69.719 137.97 70.013 ;
     RECT  131.796 69.989 132.354 70.025 ;
     RECT  74.664 69.835 75.582 70.033 ;
     RECT  76.356 69.989 92.07 70.033 ;
     RECT  134.496 70.013 137.97 70.069 ;
     RECT  15.516 69.557 16.542 70.097 ;
     RECT  134.496 70.069 138.546 70.109 ;
     RECT  24.015 67.568 24.297 70.123 ;
     RECT  34.815 67.565 35.097 70.123 ;
     RECT  45.615 67.568 45.897 70.123 ;
     RECT  56.415 67.568 56.697 70.123 ;
     RECT  67.215 67.568 67.497 70.123 ;
     RECT  1.728 69.719 3.294 70.157 ;
     RECT  23.904 70.123 24.297 70.169 ;
     RECT  34.704 70.123 35.097 70.169 ;
     RECT  45.504 70.123 45.897 70.169 ;
     RECT  56.304 70.123 56.697 70.169 ;
     RECT  67.104 70.123 67.497 70.169 ;
     RECT  2.304 70.157 3.294 70.259 ;
     RECT  74.664 70.033 92.07 70.267 ;
     RECT  2.415 70.259 3.294 70.537 ;
     RECT  4.104 69.719 14.526 70.537 ;
     RECT  93.024 69.989 112.446 70.537 ;
     RECT  93.024 70.537 113.022 70.573 ;
     RECT  74.196 70.267 92.07 70.589 ;
     RECT  93.024 70.573 113.058 70.681 ;
     RECT  72.615 67.213 72.897 70.795 ;
     RECT  134.532 70.109 137.97 70.843 ;
     RECT  133.56 69.869 133.578 70.915 ;
     RECT  132.015 70.025 132.354 70.939 ;
     RECT  140.292 70.651 140.31 70.943 ;
     RECT  93.024 70.681 113.382 70.951 ;
     RECT  133.56 70.915 133.686 70.951 ;
     RECT  133.344 70.951 133.686 70.973 ;
     RECT  126.615 69.989 127.53 70.979 ;
     RECT  93.024 70.951 113.922 71.041 ;
     RECT  72.615 70.795 72.954 71.131 ;
     RECT  2.415 70.537 14.526 71.185 ;
     RECT  74.196 70.589 92.034 71.185 ;
     RECT  134.532 70.843 138.546 71.185 ;
     RECT  132.015 70.939 132.426 71.221 ;
     RECT  133.344 70.973 133.578 71.221 ;
     RECT  92.952 71.041 113.922 71.249 ;
     RECT  134.46 71.185 138.546 71.261 ;
     RECT  92.952 71.249 113.85 71.311 ;
     RECT  92.808 71.311 113.85 71.347 ;
     RECT  2.304 71.185 14.526 71.483 ;
     RECT  72.615 71.131 73.314 71.491 ;
     RECT  74.088 71.185 92.034 71.491 ;
     RECT  92.772 71.347 113.85 71.491 ;
     RECT  72.615 71.491 113.85 71.693 ;
     RECT  110.232 71.693 113.85 71.753 ;
     RECT  132.015 71.221 133.578 71.851 ;
     RECT  134.46 71.261 137.97 71.851 ;
     RECT  140.292 71.803 140.31 71.933 ;
     RECT  12.492 71.483 14.526 71.951 ;
     RECT  72.615 71.693 109.494 72.121 ;
     RECT  2.304 71.483 11.682 72.149 ;
     RECT  132.015 71.851 137.97 72.365 ;
     RECT  126.615 70.979 127.458 72.419 ;
     RECT  110.232 71.753 113.67 72.523 ;
     RECT  72.576 72.121 109.494 72.535 ;
     RECT  110.232 72.523 114.03 72.535 ;
     RECT  72.576 72.535 114.03 72.661 ;
     RECT  134.532 72.365 137.97 72.661 ;
     RECT  15.516 70.097 16.254 72.955 ;
     RECT  72 72.661 114.03 72.967 ;
     RECT  1.152 72.139 1.17 73.031 ;
     RECT  15.516 72.955 16.83 73.067 ;
     RECT  71.712 72.967 114.03 73.075 ;
     RECT  114.876 72.841 114.894 73.075 ;
     RECT  71.676 73.075 114.894 73.111 ;
     RECT  129.888 69.989 129.906 73.201 ;
     RECT  71.676 73.111 115.038 73.229 ;
     RECT  129.888 73.201 130.554 73.229 ;
     RECT  139.068 71.515 139.086 73.243 ;
     RECT  2.415 72.149 11.682 73.265 ;
     RECT  71.712 73.229 114.39 73.265 ;
     RECT  71.856 73.265 72.99 73.337 ;
     RECT  134.532 72.661 138.114 73.337 ;
     RECT  2.415 73.265 8.91 73.345 ;
     RECT  130.536 73.229 130.554 73.409 ;
     RECT  17.856 69.251 18.897 73.471 ;
     RECT  2.304 73.345 8.91 73.499 ;
     RECT  73.944 73.265 114.39 73.517 ;
     RECT  135.684 73.337 138.114 73.517 ;
     RECT  2.304 73.499 3.114 73.535 ;
     RECT  16.812 73.067 16.83 73.535 ;
     RECT  71.856 73.337 72.897 73.607 ;
     RECT  9.648 73.265 11.682 73.769 ;
     RECT  17.604 73.471 18.897 73.769 ;
     RECT  135.684 73.517 137.79 73.769 ;
     RECT  0.108 70.459 0.126 73.813 ;
     RECT  139.032 73.243 139.086 73.813 ;
     RECT  17.784 73.769 18.897 73.841 ;
     RECT  0.108 73.813 0.558 73.901 ;
     RECT  75.852 73.517 114.39 73.913 ;
     RECT  69.552 73.741 69.858 73.921 ;
     RECT  69.552 73.921 69.966 74.005 ;
     RECT  9.936 73.769 11.682 74.011 ;
     RECT  12.492 71.951 13.986 74.011 ;
     RECT  69.552 74.005 70.002 74.047 ;
     RECT  70.848 73.813 70.866 74.047 ;
     RECT  2.304 73.535 2.697 74.075 ;
     RECT  134.532 73.337 134.766 74.075 ;
     RECT  73.944 73.517 75.006 74.083 ;
     RECT  138.528 73.813 139.086 74.083 ;
     RECT  75.852 73.913 113.994 74.111 ;
     RECT  69.552 74.047 70.866 74.119 ;
     RECT  138.528 74.083 139.122 74.141 ;
     RECT  71.964 73.607 72.897 74.191 ;
     RECT  135.684 73.769 137.697 74.219 ;
     RECT  71.964 74.191 72.99 74.281 ;
     RECT  73.728 74.083 75.006 74.281 ;
     RECT  71.964 74.281 75.006 74.381 ;
     RECT  73.728 74.381 75.006 74.425 ;
     RECT  75.852 74.111 109.494 74.425 ;
     RECT  2.412 74.075 2.697 74.461 ;
     RECT  69.552 74.119 70.938 74.461 ;
     RECT  134.748 74.075 134.766 74.477 ;
     RECT  71.964 74.381 72.99 74.489 ;
     RECT  132.015 72.365 133.578 74.489 ;
     RECT  2.412 74.461 3.042 74.551 ;
     RECT  4.032 73.499 8.91 74.551 ;
     RECT  114.768 74.461 114.786 74.579 ;
     RECT  68.76 74.425 68.778 74.587 ;
     RECT  69.516 74.461 70.938 74.587 ;
     RECT  71.964 74.489 72.954 74.587 ;
     RECT  110.415 74.111 113.994 74.695 ;
     RECT  132.015 74.489 133.038 74.849 ;
     RECT  110.415 74.695 114.39 74.857 ;
     RECT  59.328 74.857 59.346 74.893 ;
     RECT  60.12 74.623 60.138 74.893 ;
     RECT  73.728 74.425 109.494 74.893 ;
     RECT  110.376 74.857 114.39 74.893 ;
     RECT  0.108 73.901 0.162 74.909 ;
     RECT  59.328 74.893 60.138 74.909 ;
     RECT  68.76 74.587 72.954 74.957 ;
     RECT  132.015 74.849 132.297 74.965 ;
     RECT  17.784 73.841 17.874 75.001 ;
     RECT  59.472 74.909 60.138 75.001 ;
     RECT  67.215 70.169 67.497 75.001 ;
     RECT  136.188 74.219 137.697 75.001 ;
     RECT  2.412 74.551 8.91 75.091 ;
     RECT  14.76 74.683 14.778 75.091 ;
     RECT  15.516 73.067 15.534 75.091 ;
     RECT  17.352 75.001 17.874 75.091 ;
     RECT  18.615 73.841 18.897 75.091 ;
     RECT  66.744 75.001 67.497 75.091 ;
     RECT  2.412 75.091 9.018 75.115 ;
     RECT  17.352 75.091 18.897 75.115 ;
     RECT  2.268 75.115 9.018 75.119 ;
     RECT  134.352 75.001 134.37 75.119 ;
     RECT  33.048 75.091 33.066 75.149 ;
     RECT  59.472 75.001 60.606 75.149 ;
     RECT  17.136 75.115 18.897 75.155 ;
     RECT  59.868 75.149 60.606 75.155 ;
     RECT  9.936 74.011 13.986 75.163 ;
     RECT  14.76 75.091 15.534 75.163 ;
     RECT  9.936 75.163 15.534 75.191 ;
     RECT  66.708 75.091 67.497 75.191 ;
     RECT  73.728 74.893 114.39 75.191 ;
     RECT  68.76 74.957 71.262 75.197 ;
     RECT  4.176 75.119 9.018 75.227 ;
     RECT  14.544 75.191 14.562 75.227 ;
     RECT  32.508 75.163 32.814 75.227 ;
     RECT  0.54 75.199 0.558 75.245 ;
     RECT  32.796 75.227 32.814 75.245 ;
     RECT  131.364 74.965 132.297 75.293 ;
     RECT  72.036 74.957 72.954 75.361 ;
     RECT  73.728 75.191 109.602 75.361 ;
     RECT  17.352 75.155 18.897 75.389 ;
     RECT  17.352 75.389 17.37 75.425 ;
     RECT  22.14 65.669 22.23 75.485 ;
     RECT  135.576 75.001 137.697 75.659 ;
     RECT  134.208 75.541 134.226 75.691 ;
     RECT  131.688 75.293 132.297 75.787 ;
     RECT  133.02 74.849 133.038 75.787 ;
     RECT  136.152 75.659 137.697 75.811 ;
     RECT  138.528 74.141 139.086 75.811 ;
     RECT  131.688 75.787 133.038 75.821 ;
     RECT  68.976 75.197 71.262 75.901 ;
     RECT  72.036 75.361 109.602 75.901 ;
     RECT  132.015 75.821 133.038 75.901 ;
     RECT  134.064 75.691 134.226 75.901 ;
     RECT  2.268 75.119 3.438 75.929 ;
     RECT  68.976 75.901 109.602 75.937 ;
     RECT  110.415 75.191 114.39 75.937 ;
     RECT  136.152 75.811 139.086 76.001 ;
     RECT  68.976 75.937 114.39 76.037 ;
     RECT  4.176 75.227 8.91 76.045 ;
     RECT  121.215 66.173 121.497 76.072 ;
     RECT  87.12 76.037 114.39 76.081 ;
     RECT  130.536 76.075 130.554 76.081 ;
     RECT  59.868 75.155 59.886 76.109 ;
     RECT  121.104 76.072 121.497 76.109 ;
     RECT  2.268 75.929 2.934 76.171 ;
     RECT  67.215 75.191 67.497 76.171 ;
     RECT  126.615 72.419 126.897 76.171 ;
     RECT  3.78 76.045 8.91 76.199 ;
     RECT  87.12 76.081 114.606 76.235 ;
     RECT  129.924 76.081 130.626 76.235 ;
     RECT  87.264 76.235 114.606 76.253 ;
     RECT  129.924 76.235 130.554 76.253 ;
     RECT  132.015 75.901 134.226 76.279 ;
     RECT  135 75.811 135.018 76.279 ;
     RECT  136.152 76.001 137.97 76.307 ;
     RECT  124.848 75.901 124.866 76.309 ;
     RECT  87.264 76.253 114.21 76.349 ;
     RECT  67.104 76.171 67.497 76.351 ;
     RECT  124.848 76.309 125.154 76.351 ;
     RECT  125.928 76.171 126.897 76.351 ;
     RECT  129.924 76.253 130.338 76.363 ;
     RECT  132.015 76.279 135.018 76.379 ;
     RECT  68.976 76.037 86.346 76.441 ;
     RECT  22.212 75.485 22.23 76.493 ;
     RECT  139.068 76.001 139.086 76.541 ;
     RECT  68.904 76.441 86.346 76.549 ;
     RECT  129.312 76.363 130.338 76.585 ;
     RECT  128.916 76.585 130.338 76.613 ;
     RECT  124.848 76.351 126.897 76.621 ;
     RECT  133.02 76.379 135.018 76.699 ;
     RECT  136.152 76.307 137.826 76.699 ;
     RECT  4.176 76.199 8.91 76.711 ;
     RECT  9.936 75.191 13.497 76.711 ;
     RECT  67.104 76.351 68.058 76.711 ;
     RECT  67.104 76.711 68.094 76.739 ;
     RECT  18.108 75.389 18.897 76.883 ;
     RECT  1.728 76.171 2.934 76.925 ;
     RECT  129.96 76.613 130.338 76.981 ;
     RECT  2.376 76.925 2.934 77.009 ;
     RECT  129.96 76.981 130.914 77.009 ;
     RECT  68.832 76.549 86.346 77.017 ;
     RECT  110.016 76.349 114.21 77.017 ;
     RECT  114.984 76.513 115.074 77.017 ;
     RECT  133.02 76.699 137.826 77.035 ;
     RECT  110.016 77.017 115.074 77.053 ;
     RECT  115.815 67.213 116.097 77.053 ;
     RECT  133.02 77.035 138.51 77.117 ;
     RECT  67.176 76.739 68.094 77.125 ;
     RECT  68.832 77.017 86.49 77.125 ;
     RECT  132.015 76.379 132.297 77.125 ;
     RECT  130.5 77.009 130.914 77.153 ;
     RECT  140.292 76.747 140.31 77.153 ;
     RECT  110.016 77.053 116.097 77.161 ;
     RECT  124.848 76.621 127.53 77.161 ;
     RECT  131.976 77.125 132.297 77.161 ;
     RECT  67.176 77.125 86.49 77.227 ;
     RECT  87.264 76.349 109.278 77.227 ;
     RECT  4.176 76.711 13.497 77.251 ;
     RECT  131.508 77.161 132.297 77.315 ;
     RECT  2.415 77.009 2.934 77.431 ;
     RECT  124.416 77.161 127.53 77.501 ;
     RECT  67.176 77.227 109.278 77.521 ;
     RECT  110.016 77.161 116.154 77.521 ;
     RECT  67.176 77.521 116.154 77.563 ;
     RECT  133.02 77.117 138.042 77.585 ;
     RECT  2.415 77.431 3.042 77.593 ;
     RECT  61.815 67.213 62.097 77.611 ;
     RECT  2.415 77.593 3.15 77.665 ;
     RECT  3.96 77.251 13.497 77.665 ;
     RECT  139.032 77.323 139.086 77.693 ;
     RECT  124.776 77.501 127.53 77.701 ;
     RECT  2.415 77.665 13.497 77.791 ;
     RECT  61.815 77.611 62.55 77.803 ;
     RECT  1.728 77.791 13.497 77.819 ;
     RECT  66.744 77.563 116.154 77.855 ;
     RECT  130.5 77.153 130.518 77.855 ;
     RECT  114.912 77.855 116.154 77.863 ;
     RECT  61.815 77.803 62.73 77.933 ;
     RECT  128.916 76.613 128.934 77.933 ;
     RECT  139.068 77.693 139.086 77.963 ;
     RECT  66.744 77.855 114.066 78.089 ;
     RECT  114.912 77.863 116.226 78.089 ;
     RECT  133.992 77.585 138.042 78.091 ;
     RECT  1.728 77.819 2.934 78.269 ;
     RECT  131.904 77.315 132.297 78.331 ;
     RECT  133.02 77.585 133.038 78.331 ;
     RECT  117.144 78.169 117.162 78.359 ;
     RECT  4.176 77.819 13.497 78.431 ;
     RECT  130.536 78.241 130.554 78.431 ;
     RECT  114.912 78.089 116.19 78.509 ;
     RECT  131.904 78.331 133.038 78.511 ;
     RECT  133.992 78.091 138.114 78.511 ;
     RECT  67.215 78.089 114.066 78.539 ;
     RECT  4.176 78.431 12.258 78.601 ;
     RECT  0.108 76.219 0.126 78.629 ;
     RECT  67.215 78.539 67.698 78.629 ;
     RECT  68.472 78.539 114.066 78.629 ;
     RECT  131.904 78.511 138.114 78.629 ;
     RECT  114.912 78.509 116.097 78.637 ;
     RECT  67.215 78.629 67.554 78.665 ;
     RECT  68.58 78.629 114.066 78.667 ;
     RECT  114.84 78.637 116.097 78.667 ;
     RECT  68.58 78.667 116.097 78.899 ;
     RECT  1.728 78.269 2.697 78.907 ;
     RECT  68.58 78.899 107.19 78.935 ;
     RECT  3.672 78.601 12.258 78.971 ;
     RECT  1.296 78.907 2.697 79.015 ;
     RECT  138.924 78.763 138.942 79.043 ;
     RECT  1.296 79.015 2.754 79.051 ;
     RECT  68.724 78.935 107.19 79.079 ;
     RECT  15.516 75.191 15.534 79.169 ;
     RECT  1.296 79.051 2.862 79.285 ;
     RECT  4.176 78.971 11.682 79.439 ;
     RECT  131.904 78.629 137.97 79.475 ;
     RECT  1.296 79.285 3.402 79.613 ;
     RECT  4.248 79.439 11.682 79.709 ;
     RECT  108.18 78.899 116.097 79.757 ;
     RECT  14.76 79.213 14.778 79.781 ;
     RECT  129.852 79.591 129.87 79.861 ;
     RECT  2.304 79.613 3.402 79.951 ;
     RECT  108.18 79.757 114.102 79.951 ;
     RECT  68.976 79.079 107.19 79.963 ;
     RECT  108 79.951 114.102 79.963 ;
     RECT  68.724 79.963 114.102 79.979 ;
     RECT  140.292 79.915 140.31 80.045 ;
     RECT  129.852 79.861 130.554 80.051 ;
     RECT  1.296 79.613 1.314 80.087 ;
     RECT  131.904 79.475 133.038 80.095 ;
     RECT  9.684 79.709 11.682 80.123 ;
     RECT  114.876 79.757 116.097 80.131 ;
     RECT  0.108 79.915 0.126 80.159 ;
     RECT  133.776 79.475 137.97 80.203 ;
     RECT  2.304 79.951 3.438 80.221 ;
     RECT  68.724 79.979 69.678 80.249 ;
     RECT  68.724 80.249 68.742 80.285 ;
     RECT  2.304 80.221 3.51 80.321 ;
     RECT  133.776 80.203 138.51 80.357 ;
     RECT  131.508 80.095 133.038 80.365 ;
     RECT  133.776 80.357 137.97 80.365 ;
     RECT  4.248 79.709 8.91 80.401 ;
     RECT  2.304 80.321 2.826 80.519 ;
     RECT  70.488 79.979 114.102 80.519 ;
     RECT  116.964 80.329 116.982 80.519 ;
     RECT  112.284 80.519 114.102 80.671 ;
     RECT  114.876 80.131 116.19 80.671 ;
     RECT  112.284 80.671 116.55 80.789 ;
     RECT  131.508 80.365 137.97 80.869 ;
     RECT  70.488 80.519 111.474 80.905 ;
     RECT  70.452 80.905 111.474 80.933 ;
     RECT  131.256 80.869 137.97 80.941 ;
     RECT  70.452 80.933 109.602 81.059 ;
     RECT  129.852 80.051 129.87 81.095 ;
     RECT  130.86 80.941 137.97 81.095 ;
     RECT  70.452 81.059 70.938 81.131 ;
     RECT  138.888 80.779 139.086 81.203 ;
     RECT  124.776 77.701 127.782 81.211 ;
     RECT  128.844 80.131 128.862 81.211 ;
     RECT  2.34 80.519 2.826 81.307 ;
     RECT  3.636 80.401 8.91 81.329 ;
     RECT  71.82 81.059 109.602 81.329 ;
     RECT  110.415 80.933 111.474 81.337 ;
     RECT  112.284 80.789 114.174 81.337 ;
     RECT  2.304 81.307 2.826 81.481 ;
     RECT  139.104 81.355 139.662 81.677 ;
     RECT  0.108 80.971 0.126 81.707 ;
     RECT  139.572 81.677 139.662 81.707 ;
     RECT  110.415 81.337 114.174 81.869 ;
     RECT  131.004 81.095 137.898 81.883 ;
     RECT  110.415 81.869 113.346 81.905 ;
     RECT  113.328 81.905 113.346 81.941 ;
     RECT  2.304 81.481 3.366 81.949 ;
     RECT  110.415 81.905 112.59 81.985 ;
     RECT  71.82 81.329 109.458 82.013 ;
     RECT  131.004 81.883 137.97 82.021 ;
     RECT  2.268 81.949 3.366 82.111 ;
     RECT  4.248 81.329 4.41 82.111 ;
     RECT  5.364 81.329 8.91 82.111 ;
     RECT  130.212 81.301 130.23 82.111 ;
     RECT  131.004 82.021 138.006 82.111 ;
     RECT  71.82 82.013 103.914 82.123 ;
     RECT  110.232 81.985 112.59 82.139 ;
     RECT  104.796 82.013 109.458 82.147 ;
     RECT  110.232 82.139 111.618 82.147 ;
     RECT  2.268 82.111 4.41 82.211 ;
     RECT  71.748 82.123 103.914 82.211 ;
     RECT  139.572 81.707 139.626 82.253 ;
     RECT  115.272 80.789 116.097 82.255 ;
     RECT  73.764 82.211 103.914 82.283 ;
     RECT  124.776 81.211 128.862 82.291 ;
     RECT  112.356 82.139 112.59 82.319 ;
     RECT  118.584 82.111 118.602 82.319 ;
     RECT  9.936 80.123 11.682 82.409 ;
     RECT  71.748 82.211 72.99 82.409 ;
     RECT  104.796 82.147 111.618 82.409 ;
     RECT  115.272 82.255 116.55 82.409 ;
     RECT  130.212 82.111 138.006 82.411 ;
     RECT  79.812 82.283 103.914 82.445 ;
     RECT  73.764 82.283 78.93 82.517 ;
     RECT  61.815 77.933 62.097 82.525 ;
     RECT  139.572 82.253 139.59 82.541 ;
     RECT  104.796 82.409 111.474 82.553 ;
     RECT  104.796 82.553 111.222 82.589 ;
     RECT  129.96 82.411 138.006 82.589 ;
     RECT  124.776 82.291 129.15 82.651 ;
     RECT  2.268 82.211 4.302 82.679 ;
     RECT  124.668 82.651 129.15 82.723 ;
     RECT  72.108 82.409 72.99 82.787 ;
     RECT  124.668 82.723 129.222 82.795 ;
     RECT  5.184 82.111 8.91 82.831 ;
     RECT  92.016 82.445 103.914 82.831 ;
     RECT  104.796 82.589 110.697 82.831 ;
     RECT  72.216 82.787 72.99 82.859 ;
     RECT  115.272 82.409 116.154 82.859 ;
     RECT  118.872 82.651 119.286 82.859 ;
     RECT  124.272 82.795 129.222 82.859 ;
     RECT  70.92 81.131 70.938 82.949 ;
     RECT  92.016 82.831 110.697 82.949 ;
     RECT  118.872 82.859 119.214 82.949 ;
     RECT  45.615 70.169 45.897 82.957 ;
     RECT  47.268 82.921 47.286 82.973 ;
     RECT  61.815 82.525 62.226 82.987 ;
     RECT  122.544 82.831 122.562 82.987 ;
     RECT  0.108 82.651 0.126 83.021 ;
     RECT  61.815 82.987 62.73 83.065 ;
     RECT  121.215 76.109 121.497 83.083 ;
     RECT  5.184 82.831 8.946 83.101 ;
     RECT  45.576 82.957 46.206 83.101 ;
     RECT  56.415 70.169 56.697 83.101 ;
     RECT  57.528 76.081 57.546 83.101 ;
     RECT  122.544 82.987 122.67 83.117 ;
     RECT  2.268 82.679 4.194 83.191 ;
     RECT  79.812 82.445 91.206 83.191 ;
     RECT  115.815 82.859 116.154 83.213 ;
     RECT  118.872 82.949 118.89 83.213 ;
     RECT  73.764 82.517 78.858 83.219 ;
     RECT  52.56 83.191 52.578 83.227 ;
     RECT  92.016 82.949 109.674 83.227 ;
     RECT  79.74 83.191 91.206 83.254 ;
     RECT  58.824 83.227 58.842 83.263 ;
     RECT  55.26 83.179 55.278 83.275 ;
     RECT  112.572 82.319 112.59 83.275 ;
     RECT  124.272 82.859 128.826 83.291 ;
     RECT  33.048 83.227 33.066 83.299 ;
     RECT  52.56 83.227 53.118 83.299 ;
     RECT  54.684 83.275 55.278 83.299 ;
     RECT  56.124 83.101 56.697 83.299 ;
     RECT  57.528 83.101 57.618 83.299 ;
     RECT  58.788 83.263 58.842 83.299 ;
     RECT  60.624 83.263 60.642 83.299 ;
     RECT  74.088 83.219 78.858 83.323 ;
     RECT  79.74 83.254 91.242 83.323 ;
     RECT  52.2 83.299 53.118 83.335 ;
     RECT  54.684 83.299 58.842 83.335 ;
     RECT  59.724 83.299 59.742 83.335 ;
     RECT  74.088 83.323 91.242 83.335 ;
     RECT  91.98 83.227 109.674 83.335 ;
     RECT  51.015 67.213 51.297 83.371 ;
     RECT  52.02 83.335 53.118 83.371 ;
     RECT  48.492 83.227 48.51 83.461 ;
     RECT  51.015 83.371 53.118 83.461 ;
     RECT  61.815 83.065 62.982 83.461 ;
     RECT  9.936 82.409 11.178 83.489 ;
     RECT  32.58 83.299 33.066 83.489 ;
     RECT  74.088 83.335 109.674 83.489 ;
     RECT  54.684 83.335 59.742 83.497 ;
     RECT  60.516 83.299 60.642 83.497 ;
     RECT  49.572 83.461 53.118 83.533 ;
     RECT  54.288 83.497 60.642 83.533 ;
     RECT  114.156 81.869 114.174 83.533 ;
     RECT  74.088 83.489 106.254 83.561 ;
     RECT  121.104 83.083 121.497 83.563 ;
     RECT  72.252 82.859 72.99 83.569 ;
     RECT  139.068 82.795 139.086 83.605 ;
     RECT  1.728 83.191 4.194 83.641 ;
     RECT  5.184 83.101 9.126 83.641 ;
     RECT  70.668 82.957 70.686 83.641 ;
     RECT  124.272 83.291 128.61 83.669 ;
     RECT  138.996 83.605 139.086 83.693 ;
     RECT  130.212 82.589 138.006 83.755 ;
     RECT  112.572 83.275 112.734 83.767 ;
     RECT  128.196 83.669 128.61 83.795 ;
     RECT  70.596 83.641 70.686 83.803 ;
     RECT  107.028 83.489 109.674 83.803 ;
     RECT  110.415 82.949 110.697 83.803 ;
     RECT  114.156 83.533 114.318 83.803 ;
     RECT  120.492 83.563 121.497 83.803 ;
     RECT  72.252 83.569 73.026 83.839 ;
     RECT  34.815 70.169 35.097 83.851 ;
     RECT  49.572 83.533 60.642 83.851 ;
     RECT  61.488 83.461 62.982 83.851 ;
     RECT  45.54 83.101 46.854 83.875 ;
     RECT  47.844 83.461 48.51 83.875 ;
     RECT  1.728 83.641 9.126 83.911 ;
     RECT  44.712 83.839 44.73 83.911 ;
     RECT  45.54 83.875 48.762 83.911 ;
     RECT  49.572 83.851 62.982 83.911 ;
     RECT  112.464 83.767 112.734 83.933 ;
     RECT  70.596 83.803 70.83 84.001 ;
     RECT  114.012 83.803 114.318 84.001 ;
     RECT  0.108 83.851 0.126 84.029 ;
     RECT  130.212 83.755 138.114 84.029 ;
     RECT  24.015 70.169 24.297 84.037 ;
     RECT  40.215 67.213 40.497 84.037 ;
     RECT  32.58 83.489 32.994 84.073 ;
     RECT  44.712 83.911 62.982 84.073 ;
     RECT  23.58 84.037 24.297 84.077 ;
     RECT  42.768 83.605 42.786 84.109 ;
     RECT  130.212 84.029 130.626 84.109 ;
     RECT  131.652 84.029 138.114 84.125 ;
     RECT  44.64 84.073 62.982 84.139 ;
     RECT  31.5 83.731 31.518 84.145 ;
     RECT  32.364 84.073 32.994 84.145 ;
     RECT  42.768 84.109 42.822 84.145 ;
     RECT  44.64 84.139 63.054 84.145 ;
     RECT  131.724 84.125 138.114 84.173 ;
     RECT  44.64 84.145 63.126 84.181 ;
     RECT  64.044 84.139 64.062 84.181 ;
     RECT  69.588 84.145 69.606 84.181 ;
     RECT  70.596 84.001 71.01 84.181 ;
     RECT  112.86 84.001 112.914 84.181 ;
     RECT  120.384 83.803 121.497 84.181 ;
     RECT  107.028 83.803 110.697 84.209 ;
     RECT  69.588 84.181 71.01 84.235 ;
     RECT  71.748 83.839 73.026 84.235 ;
     RECT  36.792 84.145 36.81 84.271 ;
     RECT  44.64 84.181 63.27 84.271 ;
     RECT  64.044 84.181 64.134 84.271 ;
     RECT  67.215 78.665 67.497 84.271 ;
     RECT  81.468 83.561 106.254 84.271 ;
     RECT  107.028 84.209 108.954 84.271 ;
     RECT  119.52 84.073 119.538 84.271 ;
     RECT  120.384 84.181 121.77 84.271 ;
     RECT  130.068 84.109 130.626 84.271 ;
     RECT  118.44 83.875 118.458 84.283 ;
     RECT  19.656 84.145 19.674 84.299 ;
     RECT  28.476 84.181 28.494 84.299 ;
     RECT  44.496 84.271 64.134 84.299 ;
     RECT  68.724 84.181 68.742 84.299 ;
     RECT  18.615 76.883 18.897 84.307 ;
     RECT  42.768 84.145 42.894 84.307 ;
     RECT  69.588 84.235 73.026 84.307 ;
     RECT  74.088 83.561 80.55 84.307 ;
     RECT  118.296 84.283 118.458 84.307 ;
     RECT  112.86 84.181 112.986 84.317 ;
     RECT  114.012 84.001 114.498 84.331 ;
     RECT  115.815 83.213 116.097 84.331 ;
     RECT  27.684 84.271 27.702 84.343 ;
     RECT  38.484 84.271 38.502 84.343 ;
     RECT  42.768 84.307 43.578 84.343 ;
     RECT  44.496 84.299 58.59 84.343 ;
     RECT  140.292 83.851 140.31 84.343 ;
     RECT  0.144 84.073 0.558 84.365 ;
     RECT  112.968 84.317 112.986 84.371 ;
     RECT  114.012 84.331 114.786 84.371 ;
     RECT  36.792 84.271 36.99 84.379 ;
     RECT  38.304 84.343 38.502 84.379 ;
     RECT  42.768 84.343 58.59 84.379 ;
     RECT  65.808 84.331 65.826 84.379 ;
     RECT  68.58 84.331 68.598 84.379 ;
     RECT  31.5 84.145 32.994 84.415 ;
     RECT  36.792 84.379 37.026 84.415 ;
     RECT  39.744 84.037 40.497 84.415 ;
     RECT  42.588 84.379 58.59 84.415 ;
     RECT  67.104 84.271 67.497 84.415 ;
     RECT  69.588 84.307 80.55 84.415 ;
     RECT  31.356 84.415 32.994 84.427 ;
     RECT  34.344 83.851 35.097 84.427 ;
     RECT  67.032 84.415 67.497 84.451 ;
     RECT  68.436 84.379 68.598 84.451 ;
     RECT  69.552 84.415 80.55 84.451 ;
     RECT  30.492 84.271 30.51 84.475 ;
     RECT  31.284 84.427 33.606 84.475 ;
     RECT  67.032 84.451 68.598 84.479 ;
     RECT  29.415 67.213 29.697 84.523 ;
     RECT  30.492 84.475 33.606 84.523 ;
     RECT  64.944 84.271 64.962 84.523 ;
     RECT  65.808 84.379 65.898 84.523 ;
     RECT  69.48 84.451 80.55 84.523 ;
     RECT  81.468 84.271 108.954 84.523 ;
     RECT  13.215 78.431 13.497 84.541 ;
     RECT  16.704 83.641 16.722 84.541 ;
     RECT  22.14 84.451 22.158 84.541 ;
     RECT  29.415 84.523 33.606 84.541 ;
     RECT  34.344 84.427 35.334 84.541 ;
     RECT  36.576 84.415 37.026 84.541 ;
     RECT  38.016 84.379 38.502 84.541 ;
     RECT  39.312 84.415 40.497 84.541 ;
     RECT  41.76 84.415 58.59 84.541 ;
     RECT  67.032 84.479 68.31 84.541 ;
     RECT  109.764 84.209 110.697 84.541 ;
     RECT  118.188 84.307 118.458 84.541 ;
     RECT  119.232 84.271 119.538 84.541 ;
     RECT  139.608 84.343 140.31 84.557 ;
     RECT  16.128 84.541 17.766 84.569 ;
     RECT  22.14 84.541 22.95 84.569 ;
     RECT  65.808 84.523 66.15 84.569 ;
     RECT  114.732 84.371 114.786 84.569 ;
     RECT  128.592 83.795 128.61 84.569 ;
     RECT  17.388 84.569 17.766 84.605 ;
     RECT  22.68 84.569 22.95 84.605 ;
     RECT  129.996 84.271 130.626 84.605 ;
     RECT  120.312 84.271 121.77 84.613 ;
     RECT  122.544 83.117 122.634 84.613 ;
     RECT  29.415 84.541 35.334 84.649 ;
     RECT  64.872 84.523 64.962 84.649 ;
     RECT  65.808 84.569 66.042 84.649 ;
     RECT  1.728 83.911 9.234 84.667 ;
     RECT  12.348 84.541 12.366 84.667 ;
     RECT  38.016 84.541 58.59 84.677 ;
     RECT  16.128 84.569 16.146 84.685 ;
     RECT  21.204 84.571 21.222 84.685 ;
     RECT  28.584 84.649 35.334 84.685 ;
     RECT  114.768 84.569 114.786 84.685 ;
     RECT  118.188 84.541 119.538 84.685 ;
     RECT  120.312 84.613 122.634 84.685 ;
     RECT  124.272 83.669 126.897 84.685 ;
     RECT  129.996 84.605 130.23 84.685 ;
     RECT  12.168 84.667 12.366 84.713 ;
     RECT  1.728 84.667 9.414 84.721 ;
     RECT  10.62 83.489 11.178 84.721 ;
     RECT  36.576 84.541 37.206 84.721 ;
     RECT  109.764 84.541 110.862 84.721 ;
     RECT  111.744 84.613 111.762 84.721 ;
     RECT  124.272 84.685 127.242 84.721 ;
     RECT  128.448 84.571 128.466 84.721 ;
     RECT  129.456 84.685 130.23 84.721 ;
     RECT  13.215 84.541 14.382 84.811 ;
     RECT  15.732 84.685 16.146 84.811 ;
     RECT  20.088 84.571 20.106 84.811 ;
     RECT  18.615 84.307 19.026 84.839 ;
     RECT  28.584 84.685 35.478 84.839 ;
     RECT  39.672 84.677 58.59 84.839 ;
     RECT  64.872 84.649 66.042 84.839 ;
     RECT  139.608 84.557 139.626 84.845 ;
     RECT  66.96 84.541 68.31 84.847 ;
     RECT  118.188 84.685 122.634 84.875 ;
     RECT  129.384 84.721 130.23 84.875 ;
     RECT  13.215 84.811 14.634 84.883 ;
     RECT  15.552 84.811 16.146 84.883 ;
     RECT  36.252 84.721 37.206 84.883 ;
     RECT  38.016 84.677 38.934 84.883 ;
     RECT  59.472 84.299 64.134 84.883 ;
     RECT  64.872 84.839 65.754 84.883 ;
     RECT  115.815 84.331 116.622 84.883 ;
     RECT  117.432 84.307 117.45 84.883 ;
     RECT  123.516 84.721 123.534 84.883 ;
     RECT  124.272 84.721 128.466 84.883 ;
     RECT  33.768 84.839 35.478 84.893 ;
     RECT  109.764 84.721 111.762 84.907 ;
     RECT  123.516 84.883 128.466 84.907 ;
     RECT  21.06 84.685 21.546 84.911 ;
     RECT  39.672 84.839 54.954 84.911 ;
     RECT  123.372 84.907 128.466 84.911 ;
     RECT  13.215 84.883 16.146 84.941 ;
     RECT  59.472 84.883 65.754 84.941 ;
     RECT  123.372 84.911 124.974 84.941 ;
     RECT  125.748 84.911 128.466 84.941 ;
     RECT  28.584 84.839 32.598 84.947 ;
     RECT  23.976 84.077 24.297 84.955 ;
     RECT  28.584 84.947 32.49 84.983 ;
     RECT  115.815 84.883 117.45 84.991 ;
     RECT  120.456 84.875 122.634 84.991 ;
     RECT  123.372 84.941 124.938 84.991 ;
     RECT  0.144 84.365 0.198 85.003 ;
     RECT  27.684 84.343 27.81 85.081 ;
     RECT  55.692 84.839 58.59 85.081 ;
     RECT  69.48 84.523 108.954 85.081 ;
     RECT  109.764 84.907 112.194 85.081 ;
     RECT  114.768 84.685 114.894 85.081 ;
     RECT  115.668 84.991 117.45 85.081 ;
     RECT  1.728 84.721 11.178 85.109 ;
     RECT  12.204 84.713 12.366 85.109 ;
     RECT  15.876 84.941 16.146 85.109 ;
     RECT  21.096 84.911 21.546 85.109 ;
     RECT  33.768 84.893 33.966 85.109 ;
     RECT  34.776 84.893 35.478 85.109 ;
     RECT  39.78 84.911 54.954 85.109 ;
     RECT  125.892 84.941 128.034 85.109 ;
     RECT  23.832 84.955 24.297 85.117 ;
     RECT  26.784 84.919 26.802 85.117 ;
     RECT  69.372 85.081 112.374 85.117 ;
     RECT  113.4 84.847 113.814 85.117 ;
     RECT  114.768 85.081 117.45 85.117 ;
     RECT  0.108 85.003 0.198 85.133 ;
     RECT  55.692 85.081 58.662 85.145 ;
     RECT  120.456 84.991 124.938 85.145 ;
     RECT  26.28 85.117 26.802 85.153 ;
     RECT  27.54 85.081 27.81 85.153 ;
     RECT  26.28 85.153 27.81 85.181 ;
     RECT  69.192 85.117 112.374 85.181 ;
     RECT  113.4 85.117 113.886 85.189 ;
     RECT  130.968 84.991 130.986 85.189 ;
     RECT  131.724 84.173 137.97 85.189 ;
     RECT  13.215 84.941 14.958 85.217 ;
     RECT  36.252 84.883 38.934 85.217 ;
     RECT  69.192 85.181 111.402 85.217 ;
     RECT  20.088 84.811 20.25 85.225 ;
     RECT  23.832 85.117 24.678 85.225 ;
     RECT  69.192 85.217 75.294 85.229 ;
     RECT  34.815 85.109 35.478 85.261 ;
     RECT  36.252 85.217 38.718 85.261 ;
     RECT  55.728 85.145 58.662 85.291 ;
     RECT  39.96 85.109 54.846 85.297 ;
     RECT  26.424 85.181 27.81 85.351 ;
     RECT  28.584 84.983 32.166 85.351 ;
     RECT  66.924 84.847 68.31 85.351 ;
     RECT  112.14 85.181 112.374 85.351 ;
     RECT  0.144 85.133 0.198 85.373 ;
     RECT  14.544 85.217 14.958 85.379 ;
     RECT  26.424 85.351 32.166 85.379 ;
     RECT  39.96 85.297 54.81 85.379 ;
     RECT  55.728 85.291 58.734 85.379 ;
     RECT  59.868 84.941 65.754 85.379 ;
     RECT  69.192 85.229 73.782 85.379 ;
     RECT  74.556 85.229 75.294 85.379 ;
     RECT  50.364 85.379 54.81 85.415 ;
     RECT  55.764 85.379 58.734 85.415 ;
     RECT  76.32 85.217 111.402 85.415 ;
     RECT  66.924 85.351 68.382 85.423 ;
     RECT  113.4 85.189 114.03 85.423 ;
     RECT  114.768 85.117 117.63 85.423 ;
     RECT  65.052 85.379 65.754 85.451 ;
     RECT  56.052 85.415 58.734 85.469 ;
     RECT  25.632 85.225 25.65 85.487 ;
     RECT  31.356 85.379 32.166 85.487 ;
     RECT  39.96 85.379 49.446 85.487 ;
     RECT  50.472 85.415 54.81 85.487 ;
     RECT  56.052 85.469 58.554 85.487 ;
     RECT  65.052 85.451 65.214 85.487 ;
     RECT  19.98 85.225 20.25 85.495 ;
     RECT  112.14 85.351 112.446 85.531 ;
     RECT  113.4 85.423 117.63 85.531 ;
     RECT  129.384 84.875 129.474 85.531 ;
     RECT  130.968 85.189 137.97 85.531 ;
     RECT  39.96 85.487 49.158 85.565 ;
     RECT  69.192 85.379 73.71 85.565 ;
     RECT  1.728 85.109 10.926 85.649 ;
     RECT  12.204 85.109 12.222 85.649 ;
     RECT  13.215 85.217 13.698 85.649 ;
     RECT  17.64 84.605 17.766 85.649 ;
     RECT  26.424 85.379 30.618 85.649 ;
     RECT  72.108 85.565 73.71 85.649 ;
     RECT  81.216 85.415 111.402 85.649 ;
     RECT  130.752 85.531 137.97 85.675 ;
     RECT  45.072 85.565 49.158 85.685 ;
     RECT  50.472 85.487 54.414 85.685 ;
     RECT  112.14 85.531 117.63 85.685 ;
     RECT  120.744 85.145 124.938 85.685 ;
     RECT  139.104 85.225 139.122 85.709 ;
     RECT  115.2 85.685 117.63 85.729 ;
     RECT  118.62 84.875 119.142 85.729 ;
     RECT  56.052 85.487 58.266 85.757 ;
     RECT  17.64 85.649 17.694 85.765 ;
     RECT  18.615 84.839 18.954 85.765 ;
     RECT  19.98 85.495 20.286 85.765 ;
     RECT  22.824 84.605 22.95 85.765 ;
     RECT  23.832 85.225 24.822 85.765 ;
     RECT  128.772 85.531 129.474 85.765 ;
     RECT  1.728 85.649 10.854 85.793 ;
     RECT  90.504 85.649 111.402 85.793 ;
     RECT  124.236 85.685 124.938 85.793 ;
     RECT  0.18 85.373 0.198 85.801 ;
     RECT  74.556 85.379 75.258 85.805 ;
     RECT  22.788 85.765 24.894 85.891 ;
     RECT  115.2 85.729 119.142 85.891 ;
     RECT  120.744 85.685 123.282 85.891 ;
     RECT  126 85.109 128.034 85.891 ;
     RECT  1.728 85.793 9.486 85.919 ;
     RECT  13.215 85.649 13.626 85.919 ;
     RECT  19.98 85.765 20.322 85.919 ;
     RECT  21.096 85.109 21.51 85.919 ;
     RECT  22.644 85.891 24.894 85.919 ;
     RECT  26.532 85.649 30.474 85.919 ;
     RECT  50.508 85.685 54.414 85.919 ;
     RECT  59.868 85.379 60.174 85.919 ;
     RECT  61.02 85.379 64.278 85.919 ;
     RECT  65.052 85.487 65.178 85.919 ;
     RECT  81.216 85.649 89.658 85.919 ;
     RECT  101.7 85.793 111.402 85.919 ;
     RECT  115.2 85.891 119.646 85.919 ;
     RECT  124.236 85.793 124.794 85.919 ;
     RECT  128.772 85.765 129.834 85.919 ;
     RECT  130.752 85.675 138.042 85.919 ;
     RECT  8.928 85.919 9.486 85.955 ;
     RECT  19.98 85.919 20.178 85.955 ;
     RECT  21.096 85.919 21.366 85.955 ;
     RECT  120.456 85.891 123.282 85.955 ;
     RECT  130.752 85.919 132.39 85.955 ;
     RECT  66.888 85.423 68.382 85.963 ;
     RECT  69.192 85.565 71.37 85.963 ;
     RECT  21.132 85.955 21.366 85.991 ;
     RECT  81.216 85.919 84.402 85.991 ;
     RECT  90.504 85.793 100.89 85.991 ;
     RECT  115.2 85.919 118.134 85.991 ;
     RECT  119.16 85.919 119.646 85.991 ;
     RECT  128.772 85.919 129.762 85.991 ;
     RECT  85.212 85.919 89.658 85.997 ;
     RECT  139.644 85.729 139.662 85.997 ;
     RECT  66.888 85.963 71.37 86 ;
     RECT  59.868 85.919 60.138 86.027 ;
     RECT  85.212 85.997 85.77 86.027 ;
     RECT  86.544 85.997 89.658 86.027 ;
     RECT  108.72 85.919 108.846 86.027 ;
     RECT  112.14 85.685 114.426 86.027 ;
     RECT  123.012 85.955 123.282 86.027 ;
     RECT  1.728 85.919 8.154 86.035 ;
     RECT  17.352 85.765 17.694 86.035 ;
     RECT  18.576 85.765 18.954 86.035 ;
     RECT  22.644 85.919 22.77 86.035 ;
     RECT  109.764 85.919 111.402 86.035 ;
     RECT  112.14 86.027 113.958 86.035 ;
     RECT  125.676 85.891 128.034 86.035 ;
     RECT  128.772 85.991 128.862 86.035 ;
     RECT  0.18 85.801 0.558 86.045 ;
     RECT  109.764 86.035 113.958 86.045 ;
     RECT  50.508 85.919 54.27 86.063 ;
     RECT  76.32 85.415 80.37 86.063 ;
     RECT  85.212 86.027 85.734 86.063 ;
     RECT  115.2 85.991 116.838 86.063 ;
     RECT  13.215 85.919 13.554 86.071 ;
     RECT  18.576 86.035 19.926 86.071 ;
     RECT  33.804 85.109 33.966 86.071 ;
     RECT  39.96 85.565 44.046 86.071 ;
     RECT  59.868 86.027 60.03 86.071 ;
     RECT  76.32 86.063 76.374 86.071 ;
     RECT  120.456 85.955 122.022 86.071 ;
     RECT  130.752 85.955 132.297 86.071 ;
     RECT  90.504 85.991 99.897 86.147 ;
     RECT  130.644 86.071 132.297 86.147 ;
     RECT  22.572 86.035 22.77 86.161 ;
     RECT  1.656 86.035 8.154 86.189 ;
     RECT  10.44 85.793 10.854 86.189 ;
     RECT  11.736 85.765 12.114 86.189 ;
     RECT  13.032 86.071 13.554 86.189 ;
     RECT  14.544 85.379 14.85 86.189 ;
     RECT  15.876 85.109 16.11 86.189 ;
     RECT  17.064 86.035 17.694 86.189 ;
     RECT  18.432 86.071 19.926 86.189 ;
     RECT  21.132 85.991 21.33 86.189 ;
     RECT  23.508 85.919 24.894 86.189 ;
     RECT  26.604 85.919 30.402 86.189 ;
     RECT  33.264 86.071 33.966 86.189 ;
     RECT  34.815 85.261 38.718 86.189 ;
     RECT  39.492 86.071 44.046 86.189 ;
     RECT  45.072 85.685 46.458 86.189 ;
     RECT  50.508 86.063 51.678 86.189 ;
     RECT  52.632 86.063 54.27 86.189 ;
     RECT  56.052 85.757 58.194 86.189 ;
     RECT  59.616 86.071 60.03 86.189 ;
     RECT  61.02 85.919 64.242 86.189 ;
     RECT  65.16 85.919 65.178 86.189 ;
     RECT  66.888 86 68.238 86.189 ;
     RECT  74.736 85.805 75.258 86.189 ;
     RECT  77.364 86.063 80.37 86.189 ;
     RECT  81.216 85.991 84.294 86.189 ;
     RECT  85.212 86.063 85.698 86.189 ;
     RECT  87.408 86.027 89.658 86.189 ;
     RECT  90.504 86.147 99.705 86.189 ;
     RECT  100.62 85.991 100.89 86.189 ;
     RECT  101.7 85.919 107.946 86.189 ;
     RECT  109.908 86.045 113.958 86.189 ;
     RECT  115.2 86.063 116.55 86.189 ;
     RECT  120.42 86.071 122.022 86.189 ;
     RECT  125.676 86.035 128.862 86.189 ;
     RECT  130.644 86.147 132.246 86.189 ;
     RECT  133.344 85.919 137.934 86.189 ;
     RECT  120.42 86.189 120.474 86.197 ;
     RECT  10.512 86.189 10.854 86.225 ;
     RECT  11.808 86.189 12.114 86.225 ;
     RECT  14.688 86.189 14.778 86.225 ;
     RECT  15.984 86.189 16.11 86.225 ;
     RECT  18.432 86.189 18.954 86.225 ;
     RECT  23.688 86.189 24.894 86.225 ;
     RECT  26.604 86.189 26.874 86.225 ;
     RECT  27.612 86.189 30.402 86.225 ;
     RECT  33.732 86.189 33.75 86.225 ;
     RECT  34.815 86.189 35.73 86.225 ;
     RECT  37.656 86.189 38.502 86.225 ;
     RECT  39.492 86.189 42.534 86.225 ;
     RECT  43.416 86.189 43.794 86.225 ;
     RECT  45.072 86.189 46.314 86.225 ;
     RECT  47.664 85.685 49.158 86.225 ;
     RECT  50.508 86.189 51.57 86.225 ;
     RECT  52.632 86.189 54.162 86.225 ;
     RECT  56.232 86.189 58.194 86.225 ;
     RECT  62.82 86.189 64.242 86.225 ;
     RECT  72.108 85.649 73.638 86.225 ;
     RECT  74.772 86.189 75.042 86.225 ;
     RECT  76.032 86.071 76.374 86.225 ;
     RECT  77.364 86.189 78.93 86.225 ;
     RECT  79.668 86.189 80.298 86.225 ;
     RECT  81.216 86.189 84.186 86.225 ;
     RECT  85.212 86.189 85.59 86.225 ;
     RECT  87.804 86.189 89.658 86.225 ;
     RECT  90.504 86.189 96.174 86.225 ;
     RECT  96.912 86.189 98.334 86.225 ;
     RECT  101.7 86.189 105.174 86.225 ;
     RECT  109.908 86.189 111.33 86.225 ;
     RECT  112.14 86.189 113.958 86.225 ;
     RECT  117.648 85.991 118.134 86.225 ;
     RECT  125.676 86.189 126.99 86.225 ;
     RECT  130.644 86.189 130.662 86.225 ;
     RECT  133.344 86.189 136.422 86.225 ;
     RECT  8.964 85.955 9.486 86.261 ;
     RECT  22.428 86.161 22.77 86.261 ;
     RECT  31.5 85.487 32.166 86.261 ;
     RECT  48.636 86.225 49.158 86.261 ;
     RECT  56.376 86.225 56.61 86.261 ;
     RECT  59.94 86.189 59.958 86.261 ;
     RECT  69.192 86 71.37 86.261 ;
     RECT  91.584 86.225 96.174 86.261 ;
     RECT  106.056 86.189 106.614 86.261 ;
     RECT  26.676 86.225 26.874 86.297 ;
     RECT  36.576 86.189 36.594 86.297 ;
     RECT  50.544 86.225 51.282 86.297 ;
     RECT  72.108 86.225 73.602 86.297 ;
     RECT  76.032 86.225 76.338 86.297 ;
     RECT  107.352 86.189 107.946 86.297 ;
     RECT  137.415 86.189 137.934 86.297 ;
     RECT  34.815 86.225 35.622 86.305 ;
     RECT  45.072 86.225 46.062 86.305 ;
     RECT  61.02 86.189 61.905 86.305 ;
     RECT  69.552 86.261 71.37 86.305 ;
     RECT  72.108 86.297 73.206 86.305 ;
     RECT  81.216 86.225 83.682 86.305 ;
     RECT  1.656 86.189 5.706 86.333 ;
     RECT  13.14 86.189 13.374 86.333 ;
     RECT  37.656 86.225 38.214 86.333 ;
     RECT  57.528 86.225 58.194 86.333 ;
     RECT  81.036 86.305 83.682 86.333 ;
     RECT  109.908 86.225 110.538 86.333 ;
     RECT  44.784 86.305 46.062 86.341 ;
     RECT  5.184 86.333 5.706 86.369 ;
     RECT  6.876 86.189 7.038 86.369 ;
     RECT  44.712 86.341 46.062 86.369 ;
     RECT  69.552 86.305 73.206 86.369 ;
     RECT  79.668 86.225 80.01 86.369 ;
     RECT  94.215 86.261 96.174 86.369 ;
     RECT  96.912 86.225 98.298 86.369 ;
     RECT  101.7 86.225 102.618 86.369 ;
     RECT  103.5 86.225 105.174 86.369 ;
     RECT  106.092 86.261 106.614 86.369 ;
     RECT  112.14 86.225 113.022 86.369 ;
     RECT  120.24 86.197 120.474 86.369 ;
     RECT  133.344 86.225 136.386 86.369 ;
     RECT  49.752 86.305 49.77 86.381 ;
     RECT  60.984 86.305 61.905 86.381 ;
     RECT  71.892 86.369 73.206 86.381 ;
     RECT  1.656 86.333 3.402 86.417 ;
     RECT  7.815 86.189 7.905 86.417 ;
     RECT  13.14 86.333 13.305 86.417 ;
     RECT  18.615 86.225 18.954 86.417 ;
     RECT  23.94 86.225 24.105 86.417 ;
     RECT  29.124 86.225 29.505 86.417 ;
     RECT  34.488 86.305 35.622 86.417 ;
     RECT  40.215 86.225 40.986 86.417 ;
     RECT  45.615 86.369 46.062 86.417 ;
     RECT  56.415 86.261 56.61 86.417 ;
     RECT  61.704 86.381 61.905 86.417 ;
     RECT  66.924 86.189 67.305 86.417 ;
     RECT  71.892 86.381 72.705 86.417 ;
     RECT  77.364 86.225 78.462 86.417 ;
     RECT  81.828 86.333 83.682 86.417 ;
     RECT  88.815 86.225 89.622 86.417 ;
     RECT  94.215 86.369 94.698 86.417 ;
     RECT  99.072 86.189 99.705 86.417 ;
     RECT  109.908 86.333 110.505 86.417 ;
     RECT  115.74 86.189 116.55 86.417 ;
     RECT  121.215 86.189 121.77 86.417 ;
     RECT  126.615 86.225 126.99 86.417 ;
     RECT  131.4 86.189 132.246 86.417 ;
     RECT  137.415 86.297 137.862 86.417 ;
     RECT  2.736 86.417 3.402 86.459 ;
     RECT  5.184 86.369 5.202 86.459 ;
     RECT  81.828 86.417 82.746 86.459 ;
     RECT  95.652 86.369 96.174 86.459 ;
     RECT  44.712 86.369 44.802 86.495 ;
     RECT  97.92 86.369 98.298 86.495 ;
     RECT  13.14 86.417 13.158 86.525 ;
     RECT  52.632 86.225 53.874 86.531 ;
     RECT  104.688 86.369 105.174 86.531 ;
     RECT  104.688 86.531 104.994 86.567 ;
     RECT  82.368 86.459 82.746 86.603 ;
     RECT  91.584 86.261 91.602 86.603 ;
     RECT  94.356 86.417 94.698 86.603 ;
     RECT  99.072 86.417 99.45 86.603 ;
     RECT  16.236 86.305 16.254 86.621 ;
     RECT  21.312 86.189 21.33 86.621 ;
     RECT  31.464 86.305 31.482 86.621 ;
     RECT  34.488 86.417 34.506 86.621 ;
     RECT  42.156 86.225 42.174 86.621 ;
     RECT  44.784 86.495 44.802 86.621 ;
     RECT  47.664 86.225 47.682 86.621 ;
     RECT  52.632 86.531 52.65 86.621 ;
     RECT  66.024 86.305 66.042 86.621 ;
     RECT  68.22 86.189 68.238 86.621 ;
     RECT  75.852 86.305 75.87 86.621 ;
     RECT  81.036 86.333 81.054 86.621 ;
     RECT  86.544 86.027 86.562 86.621 ;
     RECT  92.34 86.261 93.258 86.621 ;
     RECT  124.776 85.919 124.794 86.656 ;
     RECT  18.936 86.417 18.954 86.669 ;
     RECT  26.856 86.297 26.874 86.669 ;
     RECT  102.6 86.369 102.618 86.669 ;
     RECT  107.352 86.297 107.37 86.669 ;
     RECT  120.456 86.369 120.474 86.669 ;
     RECT  123.012 86.027 123.03 86.669 ;
     RECT  128.268 86.189 128.286 86.669 ;
     RECT  137.844 86.417 137.862 86.669 ;
     RECT  17.316 86.189 17.586 86.684 ;
     RECT  22.536 86.261 22.77 86.684 ;
     RECT  40.824 86.417 40.986 86.684 ;
     RECT  50.94 86.297 51.282 86.684 ;
     RECT  53.64 86.531 53.874 86.684 ;
     RECT  56.484 86.417 56.61 86.684 ;
     RECT  106.092 86.369 106.578 86.684 ;
     RECT  124.38 86.656 124.794 86.684 ;
     RECT  126.936 86.417 126.99 86.684 ;
     RECT  129.6 85.991 129.762 86.684 ;
     RECT  132.156 86.417 132.246 86.684 ;
     RECT  63.54 86.225 64.242 86.701 ;
     RECT  1.656 86.417 1.746 86.717 ;
     RECT  63.54 86.701 64.35 86.729 ;
     RECT  71.892 86.417 72.162 86.729 ;
     RECT  82.368 86.603 82.602 86.729 ;
     RECT  93.024 86.621 93.258 86.729 ;
     RECT  0.54 86.045 0.558 87.053 ;
     RECT  136.368 86.369 136.386 87.149 ;
     RECT  10.836 86.225 10.854 87.197 ;
     RECT  23.94 86.417 23.958 87.197 ;
     RECT  29.124 86.417 29.142 87.197 ;
     RECT  55.476 86.305 55.494 87.197 ;
     RECT  63.54 86.729 63.558 87.197 ;
     RECT  89.604 86.417 89.622 87.197 ;
     RECT  96.912 86.369 96.93 87.197 ;
     RECT  99.432 86.603 99.45 87.197 ;
     RECT  104.976 86.567 104.994 87.197 ;
     RECT  112.788 86.369 112.806 87.197 ;
     RECT  115.74 86.417 115.758 87.197 ;
     RECT  118.116 86.225 118.134 87.197 ;
     RECT  125.676 86.225 125.694 87.197 ;
     RECT  131.4 86.417 131.418 87.197 ;
     RECT  3.384 86.459 3.402 87.389 ;
     RECT  69.552 86.369 70.614 87.485 ;
     RECT  109.908 86.417 109.926 87.773 ;
     RECT  133.776 86.369 133.794 87.773 ;
     RECT  39.276 86.305 39.294 87.821 ;
     RECT  57.528 86.333 57.546 87.821 ;
     RECT  70.596 87.485 70.614 87.821 ;
     RECT  83.664 86.417 83.682 87.821 ;
     RECT  78.444 86.417 78.462 88.445 ;
     RECT  94.356 86.603 94.374 88.445 ;
     RECT  69.552 87.485 69.57 88.459 ;
     RECT  90.504 86.225 90.522 88.501 ;
     RECT  69.552 88.459 70.218 88.522 ;
     RECT  69.57 88.522 70.2 88.541 ;
    LAYER M4 ;
     RECT  0.084 1.152 0.137 1.176 ;
     RECT  0.06 1.176 0.137 1.488 ;
     RECT  0.084 1.488 0.137 1.512 ;
     RECT  0.06 1.512 0.137 1.824 ;
     RECT  0.084 1.824 0.137 1.848 ;
     RECT  0.06 1.848 0.137 2.16 ;
     RECT  0.084 2.16 0.137 2.184 ;
     RECT  0.06 2.184 0.137 2.496 ;
     RECT  0.084 2.496 0.137 2.52 ;
     RECT  0.06 2.52 0.137 2.832 ;
     RECT  0.084 2.832 0.137 2.856 ;
     RECT  0.06 2.856 0.137 3.168 ;
     RECT  0.084 3.168 0.137 3.192 ;
     RECT  0.06 3.192 0.137 3.504 ;
     RECT  0.084 3.504 0.137 3.528 ;
     RECT  0.06 3.528 0.137 3.84 ;
     RECT  0.084 3.84 0.137 3.864 ;
     RECT  0.06 3.864 0.137 4.224 ;
     RECT  0.084 4.224 0.137 4.248 ;
     RECT  0.06 4.248 0.137 4.56 ;
     RECT  0.084 4.56 0.137 4.584 ;
     RECT  0.06 4.584 0.137 4.896 ;
     RECT  0.084 4.896 0.137 4.92 ;
     RECT  0.06 4.92 0.137 5.232 ;
     RECT  0.084 5.232 0.137 5.256 ;
     RECT  0.06 5.256 0.137 5.568 ;
     RECT  0.084 5.568 0.137 5.592 ;
     RECT  0.06 5.592 0.137 5.904 ;
     RECT  0.084 5.904 0.137 5.928 ;
     RECT  0.06 5.928 0.137 6.24 ;
     RECT  0.084 6.24 0.137 6.264 ;
     RECT  0.06 6.264 0.137 6.576 ;
     RECT  0.084 6.576 0.137 6.6 ;
     RECT  0.06 6.6 0.137 6.912 ;
     RECT  0.084 6.912 0.137 6.936 ;
     RECT  0.06 6.936 0.137 7.248 ;
     RECT  0.084 7.248 0.137 7.272 ;
     RECT  0.06 7.272 0.137 7.584 ;
     RECT  0.084 7.584 0.137 7.608 ;
     RECT  0.06 7.608 0.137 7.92 ;
     RECT  0.084 7.92 0.137 7.944 ;
     RECT  0.06 7.944 0.137 8.256 ;
     RECT  0.084 8.256 0.137 8.28 ;
     RECT  0.06 8.28 0.137 8.592 ;
     RECT  0.084 8.592 0.137 8.616 ;
     RECT  0.06 8.616 0.137 8.928 ;
     RECT  0.084 8.928 0.137 8.952 ;
     RECT  0.06 8.952 0.137 9.264 ;
     RECT  0.084 9.264 0.137 9.288 ;
     RECT  0.06 9.288 0.137 9.6 ;
     RECT  0.084 9.6 0.137 9.624 ;
     RECT  0.06 9.624 0.137 9.936 ;
     RECT  0.084 9.936 0.137 9.96 ;
     RECT  0.06 9.96 0.137 10.272 ;
     RECT  0.084 10.272 0.137 10.296 ;
     RECT  0.06 10.296 0.137 10.608 ;
     RECT  0.084 10.608 0.137 10.632 ;
     RECT  0.06 10.632 0.137 10.944 ;
     RECT  0.084 10.944 0.137 10.968 ;
     RECT  0.06 10.968 0.137 11.28 ;
     RECT  0.084 11.28 0.137 11.304 ;
     RECT  0.06 11.304 0.137 11.616 ;
     RECT  0.084 11.616 0.137 11.64 ;
     RECT  0.06 11.64 0.137 12 ;
     RECT  0.084 12 0.137 12.024 ;
     RECT  0.06 12.024 0.137 12.336 ;
     RECT  0.084 12.336 0.137 12.36 ;
     RECT  0.06 12.36 0.137 12.672 ;
     RECT  0.084 12.672 0.137 12.696 ;
     RECT  0.06 12.696 0.137 13.008 ;
     RECT  0.084 13.008 0.137 13.032 ;
     RECT  0.06 13.032 0.137 13.344 ;
     RECT  0.084 13.344 0.137 13.368 ;
     RECT  0.06 13.368 0.137 13.68 ;
     RECT  0.084 13.68 0.137 13.704 ;
     RECT  0.06 13.704 0.137 14.016 ;
     RECT  0.084 14.016 0.137 14.04 ;
     RECT  0.06 14.04 0.137 14.352 ;
     RECT  0.084 14.352 0.137 14.376 ;
     RECT  0.06 14.376 0.137 14.688 ;
     RECT  0.084 14.688 0.137 14.712 ;
     RECT  0.06 14.712 0.137 15.024 ;
     RECT  0.084 15.024 0.137 15.048 ;
     RECT  0.06 15.048 0.137 15.36 ;
     RECT  0.084 15.36 0.137 15.384 ;
     RECT  0.06 15.384 0.137 15.696 ;
     RECT  0.084 15.696 0.137 15.72 ;
     RECT  0.06 15.72 0.137 16.032 ;
     RECT  0.084 16.032 0.137 16.056 ;
     RECT  0.06 16.056 0.137 16.368 ;
     RECT  0.084 16.368 0.137 16.392 ;
     RECT  0.06 16.392 0.137 16.704 ;
     RECT  0.084 16.704 0.137 16.728 ;
     RECT  0.06 16.728 0.137 17.04 ;
     RECT  0.084 17.04 0.137 17.064 ;
     RECT  0.06 17.064 0.137 17.376 ;
     RECT  0.084 17.376 0.137 17.4 ;
     RECT  0.06 17.4 0.137 17.712 ;
     RECT  0.084 17.712 0.137 17.736 ;
     RECT  0.06 17.736 0.137 18.048 ;
     RECT  0.084 18.048 0.137 18.072 ;
     RECT  0.06 18.072 0.137 18.384 ;
     RECT  0.084 18.384 0.137 18.408 ;
     RECT  0.06 18.408 0.137 18.72 ;
     RECT  0.084 18.72 0.137 18.744 ;
     RECT  0.06 18.744 0.137 19.056 ;
     RECT  0.084 19.056 0.137 19.08 ;
     RECT  0.06 19.08 0.137 19.44 ;
     RECT  0.084 19.44 0.137 19.464 ;
     RECT  0.06 19.464 0.137 19.776 ;
     RECT  0.084 19.776 0.137 19.8 ;
     RECT  0.06 19.8 0.137 20.112 ;
     RECT  0.084 20.112 0.137 20.136 ;
     RECT  0.06 20.136 0.137 20.448 ;
     RECT  0.084 20.448 0.137 20.472 ;
     RECT  0.06 20.472 0.137 20.784 ;
     RECT  0.084 20.784 0.137 20.808 ;
     RECT  0.06 20.808 0.137 21.12 ;
     RECT  0.084 21.12 0.137 21.144 ;
     RECT  0.06 21.144 0.137 21.456 ;
     RECT  0.084 21.456 0.137 21.48 ;
     RECT  0.06 21.48 0.137 21.792 ;
     RECT  0.084 21.792 0.137 21.816 ;
     RECT  0.06 21.816 0.137 22.128 ;
     RECT  0.084 22.128 0.137 22.152 ;
     RECT  0.06 22.152 0.137 22.464 ;
     RECT  0.084 22.464 0.137 22.488 ;
     RECT  0.06 22.488 0.137 22.8 ;
     RECT  0.084 22.8 0.137 22.824 ;
     RECT  0.06 22.824 0.137 23.136 ;
     RECT  0.084 23.136 0.137 23.16 ;
     RECT  0.06 23.16 0.137 23.472 ;
     RECT  0.084 23.472 0.137 23.496 ;
     RECT  0.06 23.496 0.137 23.808 ;
     RECT  0.084 23.808 0.137 23.832 ;
     RECT  0.06 23.832 0.137 24.144 ;
     RECT  0.084 24.144 0.137 24.168 ;
     RECT  0.06 24.168 0.137 24.48 ;
     RECT  0.084 24.48 0.137 24.504 ;
     RECT  0.06 24.504 0.137 24.816 ;
     RECT  0.084 24.816 0.137 24.84 ;
     RECT  0.06 24.84 0.137 25.152 ;
     RECT  0.084 25.152 0.137 25.176 ;
     RECT  0.06 25.176 0.137 25.488 ;
     RECT  0.084 25.488 0.137 25.512 ;
     RECT  0.06 25.512 0.137 25.824 ;
     RECT  0.084 25.824 0.137 25.848 ;
     RECT  0.06 25.848 0.137 26.16 ;
     RECT  0.084 26.16 0.137 26.184 ;
     RECT  0.06 26.184 0.137 26.496 ;
     RECT  0.084 26.496 0.137 26.52 ;
     RECT  0.06 26.52 0.137 26.832 ;
     RECT  0.084 26.832 0.137 26.856 ;
     RECT  0.06 26.856 0.137 27.216 ;
     RECT  0.084 27.216 0.137 27.24 ;
     RECT  0.06 27.24 0.137 27.552 ;
     RECT  0.084 27.552 0.137 27.576 ;
     RECT  0.06 27.576 0.137 27.888 ;
     RECT  0.084 27.888 0.137 27.912 ;
     RECT  0.06 27.912 0.137 28.224 ;
     RECT  0.084 28.224 0.137 28.248 ;
     RECT  0.06 28.248 0.137 28.56 ;
     RECT  0.084 28.56 0.137 28.584 ;
     RECT  0.06 28.584 0.137 28.896 ;
     RECT  0.084 28.896 0.137 28.92 ;
     RECT  0.06 28.92 0.137 29.232 ;
     RECT  0.084 29.232 0.137 29.256 ;
     RECT  0.06 29.256 0.137 29.568 ;
     RECT  0.084 29.568 0.137 29.592 ;
     RECT  0.06 29.592 0.137 29.904 ;
     RECT  0.084 29.904 0.137 29.928 ;
     RECT  0.06 29.928 0.137 30.24 ;
     RECT  0.084 30.24 0.137 30.264 ;
     RECT  0.06 30.264 0.137 30.576 ;
     RECT  0.084 30.576 0.137 30.6 ;
     RECT  0.06 30.6 0.137 30.912 ;
     RECT  0.084 30.912 0.137 30.936 ;
     RECT  0.06 30.936 0.137 31.248 ;
     RECT  0.084 31.248 0.137 31.272 ;
     RECT  0.06 31.272 0.137 31.584 ;
     RECT  0.084 31.584 0.137 31.608 ;
     RECT  0.06 31.608 0.137 31.92 ;
     RECT  0.084 31.92 0.137 31.944 ;
     RECT  0.06 31.944 0.137 32.256 ;
     RECT  0.084 32.256 0.137 32.28 ;
     RECT  0.06 32.28 0.137 32.592 ;
     RECT  0.084 32.592 0.137 32.616 ;
     RECT  0.06 32.616 0.137 32.928 ;
     RECT  0.084 32.928 0.137 32.952 ;
     RECT  0.06 32.952 0.137 33.264 ;
     RECT  0.084 33.264 0.137 33.288 ;
     RECT  0.06 33.288 0.137 33.6 ;
     RECT  0.084 33.6 0.137 33.624 ;
     RECT  0.06 33.624 0.137 33.936 ;
     RECT  0.084 33.936 0.137 33.96 ;
     RECT  0.06 33.96 0.137 34.272 ;
     RECT  0.084 34.272 0.137 34.296 ;
     RECT  0.06 34.296 0.137 34.608 ;
     RECT  0.084 34.608 0.137 34.632 ;
     RECT  0.06 34.632 0.137 34.992 ;
     RECT  0.084 34.992 0.137 35.016 ;
     RECT  0.06 35.016 0.137 35.328 ;
     RECT  0.084 35.328 0.137 35.352 ;
     RECT  0.06 35.352 0.137 35.664 ;
     RECT  0.084 35.664 0.137 35.688 ;
     RECT  0.06 35.688 0.137 36 ;
     RECT  0.084 36 0.137 36.024 ;
     RECT  0.06 36.024 0.137 36.336 ;
     RECT  0.084 36.336 0.137 36.36 ;
     RECT  0.06 36.36 0.137 36.672 ;
     RECT  0.084 36.672 0.137 36.696 ;
     RECT  0.06 36.696 0.137 37.008 ;
     RECT  0.084 37.008 0.137 37.032 ;
     RECT  0.06 37.032 0.137 37.344 ;
     RECT  0.084 37.344 0.137 37.368 ;
     RECT  0.06 37.368 0.137 37.68 ;
     RECT  0.084 37.68 0.137 37.704 ;
     RECT  0.06 37.704 0.137 38.016 ;
     RECT  0.084 38.016 0.137 38.04 ;
     RECT  0.06 38.04 0.137 38.352 ;
     RECT  0.084 38.352 0.137 38.376 ;
     RECT  0.06 38.376 0.137 38.688 ;
     RECT  0.084 38.688 0.137 38.712 ;
     RECT  0.06 38.712 0.137 39.024 ;
     RECT  0.084 39.024 0.137 39.048 ;
     RECT  0.06 39.048 0.137 39.36 ;
     RECT  0.084 39.36 0.137 39.384 ;
     RECT  0.06 39.384 0.137 39.696 ;
     RECT  0.084 39.696 0.137 39.72 ;
     RECT  0.06 39.72 0.137 40.032 ;
     RECT  0.084 40.032 0.137 40.056 ;
     RECT  0.06 40.056 0.137 40.368 ;
     RECT  0.084 40.368 0.137 40.392 ;
     RECT  0.06 40.392 0.137 40.704 ;
     RECT  0.084 40.704 0.137 40.728 ;
     RECT  0.06 40.728 0.137 41.04 ;
     RECT  0.084 41.04 0.137 41.064 ;
     RECT  0.06 41.064 0.137 41.376 ;
     RECT  0.084 41.376 0.137 41.4 ;
     RECT  0.06 41.4 0.137 41.712 ;
     RECT  0.084 41.712 0.137 41.736 ;
     RECT  0.06 41.736 0.137 42.048 ;
     RECT  0.084 42.048 0.137 42.072 ;
     RECT  0.06 42.072 0.137 42.432 ;
     RECT  0.084 42.432 0.137 42.456 ;
     RECT  0.06 42.456 0.137 42.768 ;
     RECT  0.084 42.768 0.137 42.792 ;
     RECT  0.06 42.792 0.137 43.104 ;
     RECT  0.084 43.104 0.137 43.128 ;
     RECT  0.06 43.128 0.137 43.44 ;
     RECT  0.084 43.44 0.137 43.464 ;
     RECT  0.06 43.464 0.137 43.776 ;
     RECT  0.084 43.776 0.137 43.8 ;
     RECT  0.06 43.8 0.137 44.112 ;
     RECT  0.084 44.112 0.137 44.136 ;
     RECT  0.06 44.136 0.137 44.448 ;
     RECT  0.084 44.448 0.137 44.472 ;
     RECT  0.06 44.472 0.137 44.784 ;
     RECT  0.084 44.784 0.137 44.808 ;
     RECT  0.06 44.808 0.137 45.12 ;
     RECT  0.084 45.12 0.137 45.144 ;
     RECT  0.06 45.144 0.137 45.456 ;
     RECT  0.084 45.456 0.137 45.48 ;
     RECT  0.06 45.48 0.137 45.792 ;
     RECT  0.084 45.792 0.137 45.816 ;
     RECT  0.06 45.816 0.137 46.128 ;
     RECT  0.084 46.128 0.137 46.152 ;
     RECT  0.06 46.152 0.137 46.464 ;
     RECT  0.084 46.464 0.137 46.488 ;
     RECT  0.06 46.488 0.137 46.8 ;
     RECT  0.084 46.8 0.137 46.824 ;
     RECT  0.06 46.824 0.137 47.136 ;
     RECT  0.084 47.136 0.137 47.16 ;
     RECT  0.06 47.16 0.137 47.472 ;
     RECT  0.084 47.472 0.137 47.496 ;
     RECT  0.06 47.496 0.137 47.808 ;
     RECT  0.084 47.808 0.137 47.832 ;
     RECT  0.06 47.832 0.137 48.144 ;
     RECT  0.084 48.144 0.137 48.168 ;
     RECT  0.06 48.168 0.137 48.48 ;
     RECT  0.084 48.48 0.137 48.504 ;
     RECT  0.06 48.504 0.137 48.816 ;
     RECT  0.084 48.816 0.137 48.84 ;
     RECT  0.06 48.84 0.137 49.152 ;
     RECT  0.084 49.152 0.137 49.176 ;
     RECT  0.06 49.176 0.137 49.488 ;
     RECT  0.084 49.488 0.137 49.512 ;
     RECT  0.06 49.512 0.137 49.824 ;
     RECT  0.084 49.824 0.137 49.848 ;
     RECT  0.06 49.848 0.137 50.208 ;
     RECT  0.084 50.208 0.137 50.232 ;
     RECT  0.06 50.232 0.137 50.544 ;
     RECT  0.084 50.544 0.137 50.568 ;
     RECT  0.06 50.568 0.137 50.88 ;
     RECT  0.084 50.88 0.137 50.904 ;
     RECT  0.06 50.904 0.137 51.216 ;
     RECT  0.084 51.216 0.137 51.24 ;
     RECT  0.06 51.24 0.137 51.552 ;
     RECT  0.084 51.552 0.137 51.576 ;
     RECT  0.06 51.576 0.137 51.888 ;
     RECT  0.084 51.888 0.137 51.912 ;
     RECT  0.06 51.912 0.137 52.224 ;
     RECT  0.084 52.224 0.137 52.248 ;
     RECT  0.06 52.248 0.137 52.56 ;
     RECT  0.084 52.56 0.137 52.584 ;
     RECT  0.06 52.584 0.137 52.896 ;
     RECT  0.084 52.896 0.137 52.92 ;
     RECT  0.06 52.92 0.137 53.232 ;
     RECT  0.084 53.232 0.137 53.256 ;
     RECT  0.06 53.256 0.137 53.568 ;
     RECT  0.084 53.568 0.137 53.592 ;
     RECT  0.06 53.592 0.137 53.904 ;
     RECT  0.084 53.904 0.137 53.928 ;
     RECT  0.06 53.928 0.137 54.24 ;
     RECT  0.084 54.24 0.137 54.264 ;
     RECT  0.06 54.264 0.137 54.576 ;
     RECT  0.084 54.576 0.137 54.6 ;
     RECT  0.06 54.6 0.137 54.912 ;
     RECT  0.084 54.912 0.137 54.936 ;
     RECT  0.06 54.936 0.137 55.248 ;
     RECT  0.084 55.248 0.137 55.272 ;
     RECT  0.06 55.272 0.137 55.584 ;
     RECT  0.084 55.584 0.137 55.608 ;
     RECT  0.06 55.608 0.137 55.92 ;
     RECT  0.084 55.92 0.137 55.944 ;
     RECT  0.06 55.944 0.137 56.256 ;
     RECT  0.084 56.256 0.137 56.28 ;
     RECT  0.06 56.28 0.137 56.592 ;
     RECT  0.084 56.592 0.137 56.616 ;
     RECT  0.06 56.616 0.137 56.928 ;
     RECT  0.084 56.928 0.137 56.952 ;
     RECT  0.06 56.952 0.137 57.264 ;
     RECT  0.084 57.264 0.137 57.288 ;
     RECT  0.06 57.288 0.137 57.648 ;
     RECT  0.084 57.648 0.137 57.672 ;
     RECT  0.06 57.672 0.137 57.984 ;
     RECT  0.084 57.984 0.137 58.008 ;
     RECT  0.06 58.008 0.137 58.32 ;
     RECT  0.084 58.32 0.137 58.344 ;
     RECT  0.06 58.344 0.137 58.656 ;
     RECT  0.084 58.656 0.137 58.68 ;
     RECT  0.06 58.68 0.137 58.992 ;
     RECT  0.084 58.992 0.137 59.016 ;
     RECT  0.06 59.016 0.137 59.328 ;
     RECT  0.084 59.328 0.137 59.352 ;
     RECT  0.06 59.352 0.137 59.664 ;
     RECT  0.084 59.664 0.137 59.688 ;
     RECT  0.06 59.688 0.137 60 ;
     RECT  0.084 60 0.137 60.024 ;
     RECT  0.06 60.024 0.137 60.336 ;
     RECT  0.084 60.336 0.137 60.36 ;
     RECT  0.06 60.36 0.137 60.672 ;
     RECT  0.084 60.672 0.137 60.696 ;
     RECT  0.06 60.696 0.137 61.008 ;
     RECT  0.084 61.008 0.137 61.032 ;
     RECT  0.06 61.032 0.137 61.344 ;
     RECT  0.084 61.344 0.137 61.368 ;
     RECT  0.06 61.368 0.137 61.68 ;
     RECT  0.084 61.68 0.137 61.704 ;
     RECT  0.06 61.704 0.137 62.016 ;
     RECT  0.084 62.016 0.137 62.04 ;
     RECT  0.06 62.04 0.137 62.352 ;
     RECT  0.084 62.352 0.137 62.376 ;
     RECT  0.06 62.376 0.137 62.688 ;
     RECT  0.084 62.688 0.137 62.712 ;
     RECT  0.06 62.712 0.137 63.024 ;
     RECT  0.084 63.024 0.137 63.048 ;
     RECT  0.06 63.048 0.137 63.36 ;
     RECT  0.084 63.36 0.137 63.384 ;
     RECT  0.06 63.384 0.137 63.696 ;
     RECT  0.084 63.696 0.137 63.72 ;
     RECT  0.06 63.72 0.137 64.032 ;
     RECT  0.084 64.032 0.137 64.056 ;
     RECT  0.06 64.056 0.137 64.368 ;
     RECT  0.084 64.368 0.137 64.392 ;
     RECT  0.06 64.392 0.137 64.704 ;
     RECT  0.084 64.704 0.137 64.728 ;
     RECT  0.06 64.728 0.137 65.04 ;
     RECT  0.084 65.04 0.137 65.064 ;
     RECT  0.06 65.064 0.137 65.424 ;
     RECT  0.084 65.424 0.137 65.448 ;
     RECT  0.06 65.448 0.137 65.76 ;
     RECT  0.084 65.76 0.137 65.784 ;
     RECT  0.06 65.784 0.137 66.096 ;
     RECT  0.084 66.096 0.137 66.12 ;
     RECT  0.06 66.12 0.137 66.432 ;
     RECT  0.084 66.432 0.137 66.456 ;
     RECT  0.06 66.456 0.137 66.768 ;
     RECT  0.084 66.768 0.137 66.792 ;
     RECT  0.06 66.792 0.137 67.104 ;
     RECT  0.084 67.104 0.137 67.128 ;
     RECT  0.06 67.128 0.137 67.44 ;
     RECT  0.084 67.44 0.137 67.464 ;
     RECT  0.06 67.464 0.137 67.776 ;
     RECT  0.084 67.776 0.137 67.8 ;
     RECT  0.06 67.8 0.137 68.112 ;
     RECT  0.084 68.112 0.137 68.136 ;
     RECT  0.06 68.136 0.137 68.448 ;
     RECT  0.084 68.448 0.137 68.472 ;
     RECT  0.06 68.472 0.137 68.784 ;
     RECT  0.084 68.784 0.137 68.808 ;
     RECT  0.06 68.808 0.137 69.12 ;
     RECT  0.084 69.12 0.137 69.144 ;
     RECT  0.06 69.144 0.137 69.456 ;
     RECT  0.084 69.456 0.137 69.48 ;
     RECT  0.06 69.48 0.137 69.792 ;
     RECT  0.084 69.792 0.137 69.816 ;
     RECT  0.06 69.816 0.137 70.128 ;
     RECT  0.084 70.128 0.137 70.152 ;
     RECT  0.06 70.152 0.137 70.464 ;
     RECT  0.084 70.464 0.137 70.488 ;
     RECT  0.06 70.488 0.137 70.8 ;
     RECT  0.084 70.8 0.137 70.824 ;
     RECT  0.06 70.824 0.137 71.136 ;
     RECT  0.084 71.136 0.137 71.16 ;
     RECT  0.06 71.16 0.137 71.472 ;
     RECT  0.084 71.472 0.137 71.496 ;
     RECT  0.06 71.496 0.137 71.808 ;
     RECT  0.084 71.808 0.137 71.832 ;
     RECT  0.06 71.832 0.137 72.144 ;
     RECT  0.084 72.144 0.137 72.168 ;
     RECT  0.06 72.168 0.137 72.48 ;
     RECT  0.084 72.48 0.137 72.504 ;
     RECT  0.06 72.504 0.137 72.864 ;
     RECT  0.084 72.864 0.137 72.888 ;
     RECT  0.06 72.888 0.137 73.2 ;
     RECT  0.084 73.2 0.137 73.224 ;
     RECT  0.06 73.224 0.137 73.536 ;
     RECT  0.084 73.536 0.137 73.56 ;
     RECT  0.06 73.56 0.137 73.872 ;
     RECT  0.084 73.872 0.137 73.896 ;
     RECT  0.06 73.896 0.137 74.208 ;
     RECT  0.084 74.208 0.137 74.232 ;
     RECT  0.06 74.232 0.137 74.544 ;
     RECT  0.084 74.544 0.137 74.568 ;
     RECT  0.06 74.568 0.137 74.88 ;
     RECT  0.084 74.88 0.137 74.904 ;
     RECT  0.06 74.904 0.137 75.216 ;
     RECT  0.084 75.216 0.137 75.24 ;
     RECT  0.06 75.24 0.137 75.552 ;
     RECT  0.084 75.552 0.137 75.576 ;
     RECT  0.06 75.576 0.137 75.888 ;
     RECT  0.084 75.888 0.137 75.912 ;
     RECT  0.06 75.912 0.137 76.224 ;
     RECT  0.084 76.224 0.137 76.248 ;
     RECT  0.06 76.248 0.137 76.56 ;
     RECT  0.084 76.56 0.137 76.584 ;
     RECT  0.06 76.584 0.137 76.896 ;
     RECT  0.084 76.896 0.137 76.92 ;
     RECT  0.06 76.92 0.137 77.232 ;
     RECT  0.084 77.232 0.137 77.256 ;
     RECT  0.06 77.256 0.137 77.568 ;
     RECT  0.084 77.568 0.137 77.592 ;
     RECT  0.06 77.592 0.137 77.904 ;
     RECT  0.084 77.904 0.137 77.928 ;
     RECT  0.06 77.928 0.137 78.24 ;
     RECT  0.084 78.24 0.137 78.264 ;
     RECT  0.06 78.264 0.137 78.576 ;
     RECT  0.084 78.576 0.137 78.6 ;
     RECT  0.06 78.6 0.137 78.912 ;
     RECT  0.084 78.912 0.137 78.936 ;
     RECT  0.06 78.936 0.137 79.248 ;
     RECT  0.084 79.248 0.137 79.272 ;
     RECT  0.06 79.272 0.137 79.584 ;
     RECT  0.084 79.584 0.137 79.608 ;
     RECT  0.06 79.608 0.137 79.92 ;
     RECT  0.084 79.92 0.137 79.944 ;
     RECT  0.06 79.944 0.137 80.256 ;
     RECT  0.084 80.256 0.137 80.28 ;
     RECT  0.06 80.28 0.137 80.64 ;
     RECT  0.084 80.64 0.137 80.664 ;
     RECT  0.06 80.664 0.137 80.976 ;
     RECT  0.084 80.976 0.137 81 ;
     RECT  0.06 81 0.137 81.312 ;
     RECT  0.084 81.312 0.137 81.336 ;
     RECT  0.06 81.336 0.137 81.648 ;
     RECT  0.084 81.648 0.137 81.672 ;
     RECT  0.06 81.672 0.137 81.984 ;
     RECT  0.084 81.984 0.137 82.008 ;
     RECT  0.06 82.008 0.137 82.32 ;
     RECT  0.084 82.32 0.137 82.344 ;
     RECT  0.06 82.344 0.137 82.656 ;
     RECT  0.084 82.656 0.137 82.68 ;
     RECT  0.06 82.68 0.137 82.992 ;
     RECT  0.084 82.992 0.137 83.016 ;
     RECT  0.06 83.016 0.137 83.328 ;
     RECT  0.084 83.328 0.137 83.352 ;
     RECT  0.06 83.352 0.137 83.664 ;
     RECT  0.084 83.664 0.137 83.688 ;
     RECT  0.06 83.688 0.137 84 ;
     RECT  0.084 84 0.137 84.024 ;
     RECT  0.06 84.024 0.137 84.336 ;
     RECT  0.084 84.336 0.137 84.36 ;
     RECT  0.06 84.36 0.137 84.672 ;
     RECT  0.084 84.672 0.137 84.696 ;
     RECT  0.06 84.696 0.137 85.008 ;
     RECT  0.084 85.008 0.137 85.032 ;
     RECT  0.06 85.032 0.137 85.344 ;
     RECT  0.084 85.344 0.137 85.368 ;
     RECT  0.06 85.368 0.137 85.68 ;
     RECT  0.084 85.68 0.137 85.704 ;
     RECT  0.06 85.704 0.137 86.016 ;
     RECT  0.084 86.016 0.137 86.04 ;
     RECT  0.06 86.04 0.137 86.352 ;
     RECT  0.084 86.352 0.137 86.376 ;
     RECT  0.06 86.376 0.137 86.688 ;
     RECT  0.084 86.688 0.137 86.712 ;
     RECT  0.06 86.712 0.137 87.024 ;
     RECT  0.084 87.024 0.137 87.048 ;
     RECT  0.06 87.048 0.137 87.36 ;
     RECT  0.084 87.36 0.137 87.384 ;
     RECT  0.137 9.6 0.173 15.816 ;
     RECT  0.137 30.24 0.173 32.28 ;
     RECT  0.137 33.264 0.173 40.728 ;
     RECT  0.137 46.128 0.173 46.152 ;
     RECT  0.137 57.984 0.173 63.72 ;
     RECT  0.137 1.152 0.569 3.864 ;
     RECT  0.137 5.568 0.569 8.616 ;
     RECT  0.173 11.184 0.569 15.816 ;
     RECT  0.137 17.04 0.569 20.136 ;
     RECT  0.173 30.912 0.569 32.28 ;
     RECT  0.173 33.264 0.569 38.04 ;
     RECT  0.137 47.136 0.569 47.496 ;
     RECT  0.137 49.824 0.569 49.848 ;
     RECT  0.137 51.216 0.569 54.264 ;
     RECT  0.173 58.992 0.569 63.72 ;
     RECT  0.137 65.76 0.569 67.128 ;
     RECT  0.137 73.872 0.569 75.912 ;
     RECT  0.569 1.152 1.181 2.52 ;
     RECT  0.137 28.896 1.181 28.92 ;
     RECT  0.569 51.888 1.181 52.584 ;
     RECT  0.137 71.472 1.181 72.168 ;
     RECT  0.137 21.456 1.253 27.24 ;
     RECT  0.137 78.24 1.325 82.344 ;
     RECT  1.181 1.152 1.433 2.088 ;
     RECT  1.433 1.488 2.408 2.088 ;
     RECT  0.569 3.84 2.408 3.864 ;
     RECT  0.569 5.568 2.408 5.592 ;
     RECT  0.569 6.912 2.408 8.616 ;
     RECT  0.173 9.6 2.408 9.624 ;
     RECT  0.569 11.184 2.408 11.64 ;
     RECT  0.569 13.008 2.408 15.816 ;
     RECT  0.569 17.04 2.408 17.4 ;
     RECT  0.569 18.48 2.408 19.8 ;
     RECT  1.253 22.128 2.408 27.24 ;
     RECT  0.569 30.912 2.408 31.944 ;
     RECT  0.569 33.264 2.408 36.696 ;
     RECT  0.569 37.68 2.408 38.04 ;
     RECT  0.173 39.024 2.408 40.728 ;
     RECT  0.137 42.048 2.408 43.464 ;
     RECT  0.137 44.448 2.408 44.808 ;
     RECT  0.569 47.472 2.408 47.496 ;
     RECT  0.137 48.48 2.408 48.84 ;
     RECT  1.181 52.56 2.408 52.584 ;
     RECT  0.569 53.568 2.408 54.264 ;
     RECT  0.137 55.584 2.408 55.608 ;
     RECT  0.137 56.592 2.408 56.616 ;
     RECT  0.569 58.992 2.408 59.352 ;
     RECT  0.569 60.672 2.408 60.696 ;
     RECT  0.569 62.784 2.408 63.72 ;
     RECT  0.569 65.76 2.408 66.792 ;
     RECT  0.137 68.112 2.408 68.472 ;
     RECT  0.137 69.456 2.408 70.152 ;
     RECT  1.181 71.472 2.408 71.496 ;
     RECT  0.569 74.64 2.408 75.912 ;
     RECT  0.137 76.896 2.408 76.92 ;
     RECT  1.325 78.24 2.408 78.264 ;
     RECT  1.325 79.248 2.408 82.344 ;
     RECT  0.137 83.328 2.408 87.384 ;
     RECT  2.408 1.488 2.512 87.384 ;
     RECT  2.512 1.488 2.704 86.232 ;
     RECT  2.704 81.984 2.729 82.632 ;
     RECT  2.704 15.792 2.765 15.816 ;
     RECT  2.704 66.768 2.765 66.792 ;
     RECT  2.704 22.992 2.801 25.512 ;
     RECT  2.704 68.928 2.801 70.008 ;
     RECT  2.704 9.6 2.837 9.624 ;
     RECT  2.704 71.472 2.837 71.544 ;
     RECT  2.704 74.64 2.837 75.144 ;
     RECT  2.704 80.64 2.837 80.664 ;
     RECT  2.704 1.488 2.873 2.232 ;
     RECT  2.704 85.104 2.909 86.232 ;
     RECT  2.704 41.904 3.125 43.032 ;
     RECT  2.704 39.312 3.347 40.584 ;
     RECT  3.125 41.904 3.347 42.792 ;
     RECT  3.347 42.432 3.349 42.792 ;
     RECT  3.347 39.312 3.385 40.296 ;
     RECT  2.704 83.856 3.413 83.88 ;
     RECT  2.512 87.36 3.413 87.384 ;
     RECT  2.704 33.6 3.449 34.872 ;
     RECT  2.704 44.976 3.587 45.72 ;
     RECT  2.704 7.152 3.593 7.176 ;
     RECT  2.704 11.184 3.593 11.208 ;
     RECT  2.704 13.92 3.593 14.28 ;
     RECT  3.449 34.224 3.685 34.872 ;
     RECT  2.704 36.288 3.685 36.504 ;
     RECT  2.704 48.48 3.685 48.504 ;
     RECT  2.704 18.432 3.701 19.08 ;
     RECT  3.685 47.472 3.731 48.504 ;
     RECT  2.909 85.104 3.769 85.224 ;
     RECT  3.587 45.696 3.805 45.72 ;
     RECT  3.805 45.696 3.845 46.104 ;
     RECT  2.704 21.6 3.877 21.624 ;
     RECT  2.801 22.992 3.877 23.016 ;
     RECT  2.837 74.64 3.877 74.664 ;
     RECT  2.704 31.92 3.913 31.944 ;
     RECT  2.909 86.208 3.949 86.232 ;
     RECT  3.349 42.432 3.953 42.456 ;
     RECT  3.685 34.224 3.971 36.504 ;
     RECT  3.877 9.456 3.973 9.48 ;
     RECT  3.949 19.776 3.985 19.8 ;
     RECT  2.801 24.096 3.985 25.512 ;
     RECT  3.949 86.208 3.989 86.328 ;
     RECT  3.973 8.544 4.019 9.48 ;
     RECT  3.989 86.256 4.097 86.328 ;
     RECT  3.877 74.64 4.115 75.096 ;
     RECT  2.704 28.416 4.165 29.64 ;
     RECT  2.873 2.208 4.169 2.232 ;
     RECT  3.731 47.472 4.169 48.264 ;
     RECT  3.913 31.104 4.201 31.944 ;
     RECT  2.801 69.984 4.201 70.008 ;
     RECT  2.837 71.52 4.201 71.544 ;
     RECT  3.385 39.888 4.205 40.296 ;
     RECT  3.971 35.616 4.213 36.504 ;
     RECT  2.801 68.928 4.213 68.952 ;
     RECT  4.201 30.96 4.237 31.944 ;
     RECT  3.877 33.072 4.237 33.096 ;
     RECT  4.201 69.984 4.259 71.544 ;
     RECT  3.877 21.6 4.273 23.016 ;
     RECT  3.985 24.096 4.273 26.136 ;
     RECT  4.259 70.128 4.285 71.544 ;
     RECT  4.213 35.616 4.3 37.08 ;
     RECT  4.213 68.256 4.3 68.952 ;
     RECT  4.22 88.464 4.307 88.488 ;
     RECT  4.273 21.024 4.345 26.136 ;
     RECT  4.165 28.08 4.381 29.64 ;
     RECT  2.704 64.848 4.385 64.872 ;
     RECT  4.345 21.024 4.417 26.52 ;
     RECT  4.381 27.6 4.417 29.64 ;
     RECT  4.285 70.656 4.453 71.544 ;
     RECT  4.069 72.912 4.453 72.936 ;
     RECT  4.417 21.024 4.493 29.64 ;
     RECT  4.345 58.128 4.499 58.152 ;
     RECT  4.453 70.656 4.499 72.936 ;
     RECT  3.877 51.264 4.525 51.288 ;
     RECT  3.805 66.336 4.525 66.36 ;
     RECT  3.593 14.256 4.549 14.28 ;
     RECT  4.129 15.456 4.549 15.48 ;
     RECT  4.093 53.76 4.549 53.784 ;
     RECT  2.704 78.624 4.549 78.648 ;
     RECT  4.549 14.256 4.595 15.48 ;
     RECT  4.549 53.76 4.595 54.36 ;
     RECT  4.549 78.624 4.595 79.464 ;
     RECT  4.525 3.216 4.597 3.24 ;
     RECT  3.913 4.224 4.597 4.248 ;
     RECT  4.237 30.96 4.597 33.096 ;
     RECT  3.971 34.224 4.597 34.632 ;
     RECT  4.597 30.96 4.601 34.632 ;
     RECT  4.525 42.144 4.604 42.168 ;
     RECT  4.525 66.336 4.633 66.504 ;
     RECT  4.595 79.248 4.637 79.464 ;
     RECT  4.205 40.272 4.645 40.296 ;
     RECT  4.604 41.328 4.645 42.168 ;
     RECT  2.704 38.112 4.669 38.136 ;
     RECT  2.704 52.704 4.673 52.728 ;
     RECT  4.645 40.272 4.691 42.168 ;
     RECT  4.595 54.336 4.709 54.36 ;
     RECT  2.729 82.608 4.741 82.632 ;
     RECT  4.019 8.544 4.745 8.568 ;
     RECT  3.845 46.08 4.745 46.104 ;
     RECT  4.3 68.256 4.745 68.28 ;
     RECT  4.499 72.384 4.817 72.936 ;
     RECT  3.769 84.864 4.853 85.224 ;
     RECT  3.985 19.776 4.957 19.896 ;
     RECT  4.493 21.024 4.957 23.784 ;
     RECT  4.691 40.272 5.033 40.968 ;
     RECT  3.841 62.304 5.036 62.328 ;
     RECT  4.597 3.216 5.077 4.248 ;
     RECT  4.525 5.712 5.077 5.736 ;
     RECT  4.633 66.192 5.101 66.504 ;
     RECT  5.036 61.536 5.123 62.328 ;
     RECT  4.237 50.112 5.137 50.136 ;
     RECT  4.525 51.264 5.137 51.528 ;
     RECT  5.101 66.192 5.141 66.888 ;
     RECT  5.077 3.216 5.164 5.736 ;
     RECT  5.164 5.712 5.173 5.736 ;
     RECT  3.805 6.816 5.173 6.84 ;
     RECT  4.169 48.24 5.173 48.264 ;
     RECT  5.137 50.112 5.173 51.528 ;
     RECT  5.164 3.216 5.177 4.44 ;
     RECT  4.129 12.336 5.209 12.36 ;
     RECT  5.173 5.712 5.213 6.84 ;
     RECT  4.595 14.256 5.213 14.808 ;
     RECT  5.173 48.24 5.213 51.528 ;
     RECT  4.741 82.608 5.213 82.728 ;
     RECT  4.853 84.96 5.213 85.224 ;
     RECT  4.201 16.512 5.245 16.536 ;
     RECT  5.209 12 5.249 12.36 ;
     RECT  5.245 15.984 5.249 16.536 ;
     RECT  4.705 43.344 5.281 43.368 ;
     RECT  4.115 75.072 5.281 75.096 ;
     RECT  4.601 33.552 5.285 34.632 ;
     RECT  5.281 75.072 5.321 75.432 ;
     RECT  4.669 37.584 5.389 38.136 ;
     RECT  4.309 81.024 5.389 81.048 ;
     RECT  5.389 81.024 5.429 81.48 ;
     RECT  4.601 30.96 5.461 32.52 ;
     RECT  5.213 85.2 5.461 85.224 ;
     RECT  4.097 86.256 5.461 86.28 ;
     RECT  3.701 18.432 5.465 18.456 ;
     RECT  4.3 35.616 5.497 36.504 ;
     RECT  3.985 60 5.533 60.024 ;
     RECT  5.141 66.864 5.533 66.888 ;
     RECT  4.499 70.656 5.533 70.68 ;
     RECT  5.461 85.2 5.557 86.28 ;
     RECT  5.533 59.808 5.573 60.024 ;
     RECT  4.525 64.128 5.573 64.152 ;
     RECT  5.533 46.704 5.605 46.728 ;
     RECT  5.213 48.24 5.605 50.808 ;
     RECT  5.461 30.864 5.641 32.52 ;
     RECT  5.569 68.64 5.641 68.664 ;
     RECT  5.533 70.176 5.641 70.68 ;
     RECT  5.429 81.456 5.641 81.48 ;
     RECT  5.612 58.704 5.653 58.728 ;
     RECT  5.573 59.808 5.653 59.832 ;
     RECT  5.653 58.704 5.699 59.832 ;
     RECT  5.605 46.704 5.747 50.808 ;
     RECT  4.957 19.776 5.749 23.784 ;
     RECT  4.493 25.056 5.749 29.64 ;
     RECT  5.677 55.824 5.749 55.848 ;
     RECT  4.237 56.88 5.749 56.904 ;
     RECT  5.389 37.488 5.753 38.136 ;
     RECT  5.213 6.24 5.756 6.84 ;
     RECT  5.749 19.776 5.789 29.64 ;
     RECT  5.753 37.584 5.789 38.136 ;
     RECT  5.749 55.824 5.795 56.904 ;
     RECT  4.957 10.272 5.797 10.296 ;
     RECT  5.249 15.984 5.821 16.008 ;
     RECT  5.789 26.496 5.821 29.64 ;
     RECT  5.641 30.816 5.821 32.52 ;
     RECT  5.285 33.552 5.821 33.624 ;
     RECT  5.641 70.128 5.821 70.68 ;
     RECT  5.821 26.496 5.825 33.624 ;
     RECT  5.033 40.944 5.825 40.968 ;
     RECT  5.029 77.568 5.825 77.592 ;
     RECT  5.641 81.456 5.825 82.056 ;
     RECT  5.756 6.24 5.843 7.272 ;
     RECT  5.699 59.424 5.891 59.832 ;
     RECT  5.843 6.24 5.897 6.408 ;
     RECT  5.795 56.4 5.897 56.904 ;
     RECT  5.845 60.816 5.932 60.84 ;
     RECT  5.789 19.776 5.997 25.512 ;
     RECT  4.691 42.048 6.001 42.168 ;
     RECT  5.281 43.248 6.001 43.368 ;
     RECT  5.747 49.2 6.005 50.808 ;
     RECT  5.797 10.272 6.035 10.872 ;
     RECT  5.789 37.632 6.037 38.136 ;
     RECT  6.001 42.048 6.041 43.368 ;
     RECT  5.249 12 6.073 12.024 ;
     RECT  5.997 19.776 6.077 23.928 ;
     RECT  6.041 42.768 6.085 43.368 ;
     RECT  6.073 11.904 6.113 12.024 ;
     RECT  5.825 26.784 6.185 33.624 ;
     RECT  5.857 44.976 6.217 45 ;
     RECT  6.005 50.544 6.217 50.808 ;
     RECT  4.817 72.912 6.221 72.936 ;
     RECT  6.085 43.248 6.229 43.368 ;
     RECT  5.747 47.856 6.275 48.216 ;
     RECT  5.321 75.408 6.284 75.432 ;
     RECT  6.217 44.976 6.301 45.048 ;
     RECT  5.821 14.832 6.329 16.008 ;
     RECT  6.329 14.832 6.353 15.48 ;
     RECT  5.533 66.864 6.361 67.224 ;
     RECT  5.641 68.64 6.361 68.904 ;
     RECT  6.229 43.248 6.365 43.8 ;
     RECT  5.317 13.056 6.397 13.08 ;
     RECT  6.284 75.408 6.397 75.672 ;
     RECT  4.637 79.248 6.421 79.272 ;
     RECT  5.389 39.744 6.433 39.768 ;
     RECT  6.353 14.784 6.437 15.48 ;
     RECT  6.365 43.296 6.437 43.8 ;
     RECT  5.497 34.704 6.473 36.504 ;
     RECT  6.433 39.744 6.473 39.864 ;
     RECT  6.421 79.248 6.501 79.752 ;
     RECT  5.997 25.056 6.509 25.512 ;
     RECT  6.361 66.864 6.517 68.904 ;
     RECT  6.301 44.976 6.545 45 ;
     RECT  5.825 82.032 6.563 82.056 ;
     RECT  6.035 10.272 6.653 10.296 ;
     RECT  6.185 26.784 6.659 33.528 ;
     RECT  5.677 18.192 6.716 18.216 ;
     RECT  6.716 18.192 6.803 18.6 ;
     RECT  5.177 3.936 6.805 4.44 ;
     RECT  6.517 66.48 6.829 68.904 ;
     RECT  5.821 69.888 6.829 70.68 ;
     RECT  6.829 66.48 6.833 70.68 ;
     RECT  6.803 18.192 6.865 18.456 ;
     RECT  6.275 48.192 6.865 48.216 ;
     RECT  6.005 49.2 6.865 49.224 ;
     RECT  5.891 59.424 6.865 59.448 ;
     RECT  6.829 25.776 6.901 25.8 ;
     RECT  6.659 26.784 6.901 30.6 ;
     RECT  6.473 39.84 6.901 39.864 ;
     RECT  5.747 46.704 6.901 46.728 ;
     RECT  5.123 62.304 6.901 62.328 ;
     RECT  6.865 17.616 6.973 18.456 ;
     RECT  6.473 34.704 6.973 35.688 ;
     RECT  5.965 53.568 7.009 53.592 ;
     RECT  6.077 20.832 7.052 23.928 ;
     RECT  6.113 11.904 7.117 11.928 ;
     RECT  6.833 70.128 7.117 70.68 ;
     RECT  6.253 72 7.117 72.024 ;
     RECT  6.865 59.424 7.189 59.784 ;
     RECT  6.833 66.48 7.189 69.144 ;
     RECT  6.973 34.656 7.225 35.688 ;
     RECT  7.009 53.568 7.333 54.456 ;
     RECT  7.045 83.232 7.381 83.256 ;
     RECT  7.117 11.424 7.405 11.928 ;
     RECT  7.189 59.184 7.405 59.784 ;
     RECT  7.369 63.744 7.477 63.768 ;
     RECT  6.501 79.728 7.525 79.752 ;
     RECT  5.897 56.4 7.649 56.424 ;
     RECT  7.405 10.944 7.669 11.928 ;
     RECT  6.397 13.056 7.669 13.608 ;
     RECT  7.649 56.4 7.693 56.856 ;
     RECT  6.901 62.304 7.801 62.712 ;
     RECT  6.805 3.936 7.808 5.112 ;
     RECT  5.897 6.384 7.808 6.408 ;
     RECT  6.937 7.92 7.808 7.944 ;
     RECT  7.649 9.216 7.808 9.24 ;
     RECT  7.669 10.944 7.808 13.608 ;
     RECT  6.437 15.168 7.808 15.48 ;
     RECT  6.973 16.656 7.808 18.456 ;
     RECT  6.289 19.632 7.808 19.656 ;
     RECT  7.052 20.832 7.808 24.648 ;
     RECT  6.901 25.776 7.808 30.6 ;
     RECT  6.659 31.824 7.808 33.528 ;
     RECT  7.225 34.608 7.808 35.688 ;
     RECT  6.037 37.632 7.808 38.664 ;
     RECT  6.901 39.84 7.808 40.056 ;
     RECT  6.437 43.296 7.808 43.32 ;
     RECT  6.901 46.032 7.808 46.728 ;
     RECT  6.865 48.192 7.808 49.224 ;
     RECT  6.217 50.544 7.808 50.856 ;
     RECT  6.217 51.84 7.808 51.864 ;
     RECT  7.333 52.992 7.808 54.456 ;
     RECT  7.693 55.968 7.808 56.856 ;
     RECT  7.405 59.184 7.808 60.216 ;
     RECT  7.801 61.632 7.808 62.712 ;
     RECT  7.477 63.744 7.808 65.016 ;
     RECT  7.189 66.144 7.808 69.144 ;
     RECT  7.117 70.128 7.808 72.024 ;
     RECT  6.397 75.408 7.808 76.392 ;
     RECT  6.253 77.952 7.808 77.976 ;
     RECT  7.525 79.728 7.808 80.472 ;
     RECT  7.381 82.704 7.808 83.256 ;
     RECT  5.557 85.2 7.808 86.328 ;
     RECT  7.808 2.148 7.912 86.412 ;
     RECT  7.912 2.418 8.104 86.328 ;
     RECT  8.104 53.568 8.165 56.856 ;
     RECT  8.104 59.184 8.165 63.384 ;
     RECT  8.104 18.432 8.201 18.456 ;
     RECT  8.165 59.184 8.237 63.144 ;
     RECT  8.165 55.248 8.243 56.856 ;
     RECT  8.104 74.64 8.243 75.432 ;
     RECT  8.104 13.584 8.245 14.952 ;
     RECT  8.104 16.656 8.273 16.68 ;
     RECT  8.243 74.64 8.273 75.144 ;
     RECT  8.243 55.248 8.284 55.272 ;
     RECT  8.104 48.432 8.417 49.224 ;
     RECT  8.245 13.584 8.489 13.608 ;
     RECT  8.104 3.936 8.597 4.968 ;
     RECT  8.104 6.384 8.597 6.408 ;
     RECT  8.104 43.296 8.675 44.04 ;
     RECT  8.597 3.936 8.741 4.44 ;
     RECT  8.165 53.568 8.813 54.12 ;
     RECT  8.104 37.008 8.849 37.704 ;
     RECT  8.104 64.416 8.921 68.952 ;
     RECT  8.104 20.928 8.957 31.416 ;
     RECT  8.741 3.936 9.029 3.96 ;
     RECT  8.104 50.544 9.059 50.856 ;
     RECT  8.104 45.792 9.097 45.96 ;
     RECT  8.957 23.568 9.157 31.416 ;
     RECT  8.104 32.496 9.157 34.68 ;
     RECT  9.157 23.568 9.165 34.68 ;
     RECT  8.104 39.312 9.173 41.496 ;
     RECT  8.237 59.568 9.241 63.144 ;
     RECT  8.921 64.416 9.241 67.656 ;
     RECT  9.165 34.176 9.245 34.68 ;
     RECT  9.173 39.312 9.245 40.488 ;
     RECT  9.165 23.568 9.353 32.904 ;
     RECT  9.245 34.272 9.353 34.68 ;
     RECT  9.097 45.792 9.385 46.68 ;
     RECT  8.104 84.144 9.385 84.168 ;
     RECT  8.104 85.2 9.385 86.328 ;
     RECT  8.104 52.224 9.529 52.248 ;
     RECT  8.813 53.568 9.529 53.688 ;
     RECT  9.245 39.312 9.601 39.48 ;
     RECT  8.243 56.832 9.685 56.856 ;
     RECT  9.529 52.224 9.733 53.688 ;
     RECT  9.457 58.224 9.781 58.248 ;
     RECT  9.781 36 9.853 36.024 ;
     RECT  8.849 37.008 9.853 37.368 ;
     RECT  9.059 50.736 9.889 50.856 ;
     RECT  9.733 52.128 9.889 53.688 ;
     RECT  9.353 34.368 9.961 34.68 ;
     RECT  9.173 41.472 10.001 41.496 ;
     RECT  9.685 56.736 10.069 56.856 ;
     RECT  9.781 57.936 10.069 58.248 ;
     RECT  9.241 59.568 10.069 67.656 ;
     RECT  8.957 22.32 10.105 22.536 ;
     RECT  9.353 23.616 10.213 32.904 ;
     RECT  9.961 34.368 10.213 35.016 ;
     RECT  9.853 36 10.213 37.368 ;
     RECT  9.245 40.464 10.213 40.488 ;
     RECT  8.957 20.928 10.261 20.952 ;
     RECT  10.105 22.224 10.261 22.536 ;
     RECT  9.385 45.792 10.285 46.872 ;
     RECT  8.417 48.432 10.285 49.032 ;
     RECT  10.261 20.928 10.307 22.536 ;
     RECT  10.307 21.12 10.321 22.536 ;
     RECT  10.213 23.616 10.321 33.048 ;
     RECT  10.069 55.872 10.361 67.656 ;
     RECT  10.361 64.704 10.397 67.656 ;
     RECT  9.601 38.448 10.537 39.48 ;
     RECT  10.213 40.464 10.537 40.968 ;
     RECT  9.889 50.736 10.541 53.688 ;
     RECT  10.361 55.872 10.541 63.576 ;
     RECT  10.541 56.448 10.685 63.576 ;
     RECT  10.213 34.368 10.717 37.368 ;
     RECT  10.541 50.736 10.717 51.72 ;
     RECT  9.385 84.144 10.781 86.328 ;
     RECT  8.149 87.456 10.781 87.48 ;
     RECT  10.321 21.12 10.793 33.048 ;
     RECT  8.675 43.296 10.837 43.32 ;
     RECT  10.321 44.448 10.837 44.472 ;
     RECT  10.285 45.792 10.837 49.032 ;
     RECT  10.717 50.112 10.861 51.72 ;
     RECT  10.837 43.296 10.865 49.032 ;
     RECT  10.781 84.144 10.865 87.48 ;
     RECT  10.865 43.296 10.883 48.984 ;
     RECT  10.883 43.296 10.901 43.656 ;
     RECT  10.541 52.848 10.933 53.688 ;
     RECT  8.104 10.848 10.973 10.872 ;
     RECT  10.933 52.848 11.045 53.88 ;
     RECT  10.793 23.616 11.077 33.048 ;
     RECT  10.717 34.128 11.077 37.368 ;
     RECT  10.793 21.12 11.189 22.344 ;
     RECT  11.077 23.616 11.329 37.368 ;
     RECT  10.537 38.448 11.329 40.968 ;
     RECT  11.189 21.12 11.365 22.248 ;
     RECT  11.365 20.448 11.411 22.248 ;
     RECT  11.461 68.064 11.473 68.088 ;
     RECT  11.329 23.616 11.509 40.968 ;
     RECT  10.249 42.096 11.509 42.12 ;
     RECT  11.509 23.616 11.513 42.12 ;
     RECT  11.473 68.064 11.548 68.424 ;
     RECT  10.397 64.704 11.581 66.744 ;
     RECT  11.513 24.144 11.585 42.12 ;
     RECT  10.685 56.736 11.693 63.576 ;
     RECT  11.585 24.24 11.756 42.12 ;
     RECT  10.861 50.016 11.765 51.72 ;
     RECT  11.693 58.656 11.765 63.576 ;
     RECT  11.756 24.24 11.873 42.168 ;
     RECT  11.545 55.248 11.941 55.272 ;
     RECT  11.693 56.736 11.941 57.624 ;
     RECT  11.411 20.448 11.945 20.472 ;
     RECT  11.873 24.624 11.945 42.168 ;
     RECT  11.765 58.896 12.013 63.576 ;
     RECT  11.581 64.704 12.013 66.792 ;
     RECT  11.945 42 12.049 42.168 ;
     RECT  10.901 43.584 12.049 43.656 ;
     RECT  12.013 58.896 12.053 66.792 ;
     RECT  11.045 53.232 12.085 53.88 ;
     RECT  11.941 55.248 12.085 57.624 ;
     RECT  12.049 42 12.121 43.656 ;
     RECT  12.053 60.576 12.121 66.792 ;
     RECT  11.765 51.168 12.188 51.72 ;
     RECT  12.085 53.232 12.188 57.624 ;
     RECT  12.121 42 12.481 43.896 ;
     RECT  10.883 45.024 12.481 48.984 ;
     RECT  11.411 21.6 12.733 22.248 ;
     RECT  12.733 21.6 12.913 22.776 ;
     RECT  12.913 21.6 12.949 23.304 ;
     RECT  12.949 21.6 12.985 23.4 ;
     RECT  11.765 50.016 13.021 50.136 ;
     RECT  12.188 51.168 13.021 57.624 ;
     RECT  12.481 42 13.057 48.984 ;
     RECT  13.021 50.016 13.057 57.624 ;
     RECT  12.053 58.896 13.093 59.592 ;
     RECT  12.121 60.576 13.093 67.032 ;
     RECT  10.865 84.144 13.093 86.328 ;
     RECT  10.865 87.456 13.093 87.48 ;
     RECT  13.093 84.144 13.18 88.44 ;
     RECT  10.249 3.312 13.208 3.336 ;
     RECT  12.524 12.336 13.208 12.36 ;
     RECT  8.245 14.928 13.208 14.952 ;
     RECT  12.985 21.504 13.208 23.4 ;
     RECT  11.945 24.624 13.208 40.968 ;
     RECT  13.057 42 13.208 57.624 ;
     RECT  13.093 58.896 13.208 67.032 ;
     RECT  11.548 68.4 13.208 68.424 ;
     RECT  8.273 75.12 13.208 75.144 ;
     RECT  13.18 84.144 13.208 86.412 ;
     RECT  13.208 2.148 13.312 86.412 ;
     RECT  13.18 87.456 13.427 88.44 ;
     RECT  13.312 2.418 13.504 86.328 ;
     RECT  13.504 21.504 14.069 63.864 ;
     RECT  13.504 14.928 14.105 14.952 ;
     RECT  14.069 56.88 14.141 63.864 ;
     RECT  13.504 64.896 14.141 66.792 ;
     RECT  13.504 17.616 14.531 17.976 ;
     RECT  13.504 12.336 14.533 12.504 ;
     RECT  13.504 75.12 14.533 75.144 ;
     RECT  13.504 6 14.54 6.024 ;
     RECT  14.54 5.136 14.581 6.024 ;
     RECT  13.504 3.312 14.627 3.336 ;
     RECT  14.581 4.368 14.627 6.024 ;
     RECT  14.627 4.368 14.668 4.44 ;
     RECT  14.533 75.12 14.705 75.192 ;
     RECT  14.069 21.504 14.753 55.56 ;
     RECT  14.141 65.664 14.753 66.792 ;
     RECT  14.705 74.688 14.789 75.192 ;
     RECT  14.627 6 14.819 6.024 ;
     RECT  14.533 11.952 14.965 12.504 ;
     RECT  14.965 11.664 15.205 12.504 ;
     RECT  14.581 13.536 15.205 13.56 ;
     RECT  14.141 56.88 15.205 57.144 ;
     RECT  14.141 58.416 15.205 63.864 ;
     RECT  14.753 65.808 15.253 66.792 ;
     RECT  14.753 51.168 15.445 55.56 ;
     RECT  15.205 56.88 15.445 63.864 ;
     RECT  14.753 21.504 15.539 50.088 ;
     RECT  15.253 65.808 15.581 67.272 ;
     RECT  14.929 68.352 15.581 68.376 ;
     RECT  15.013 17.376 15.685 17.4 ;
     RECT  15.445 18.72 15.685 18.744 ;
     RECT  15.445 51.168 15.685 63.864 ;
     RECT  15.539 21.6 15.973 50.088 ;
     RECT  15.685 51.168 15.973 64.392 ;
     RECT  13.427 87.456 15.973 87.48 ;
     RECT  15.581 65.808 16.045 66.744 ;
     RECT  15.973 21.6 16.163 64.392 ;
     RECT  13.504 84.144 16.225 86.328 ;
     RECT  15.973 87.456 16.225 88.44 ;
     RECT  16.163 60.336 16.229 64.392 ;
     RECT  16.229 60.336 16.301 63.624 ;
     RECT  16.225 84.144 16.307 88.44 ;
     RECT  15.685 17.376 16.309 18.744 ;
     RECT  16.307 84.144 16.309 87.48 ;
     RECT  16.045 65.52 16.373 66.744 ;
     RECT  16.373 65.52 16.405 66.264 ;
     RECT  14.668 4.416 16.453 4.44 ;
     RECT  13.504 79.488 16.501 79.512 ;
     RECT  14.789 75.12 16.549 75.192 ;
     RECT  16.163 21.6 16.553 59.256 ;
     RECT  16.405 64.656 16.595 66.264 ;
     RECT  16.453 4.416 16.597 4.488 ;
     RECT  16.595 66.144 16.691 66.264 ;
     RECT  16.189 67.776 16.748 67.8 ;
     RECT  16.553 21.6 16.805 58.92 ;
     RECT  16.748 67.776 16.835 68.376 ;
     RECT  16.757 72.96 16.841 72.984 ;
     RECT  16.691 66.144 16.949 66.168 ;
     RECT  14.773 7.392 17.021 7.416 ;
     RECT  16.301 60.336 17.021 63.576 ;
     RECT  16.549 75.12 17.165 75.288 ;
     RECT  16.805 21.6 17.269 23.304 ;
     RECT  16.595 64.656 17.273 64.68 ;
     RECT  17.021 63.552 17.363 63.576 ;
     RECT  16.805 57.408 17.411 58.92 ;
     RECT  17.165 75.168 17.605 75.288 ;
     RECT  17.269 21.456 17.881 23.304 ;
     RECT  16.805 24.432 17.881 56.088 ;
     RECT  16.835 67.776 17.989 67.848 ;
     RECT  17.605 75.168 18.181 75.528 ;
     RECT  18.229 66.432 18.421 66.456 ;
     RECT  17.989 67.776 18.421 68.76 ;
     RECT  17.881 21.456 18.469 56.088 ;
     RECT  17.749 2.496 18.608 2.52 ;
     RECT  16.597 4.128 18.608 4.488 ;
     RECT  16.885 8.976 18.608 9 ;
     RECT  16.357 10.608 18.608 10.632 ;
     RECT  15.205 11.664 18.608 13.56 ;
     RECT  16.309 17.376 18.608 18.792 ;
     RECT  18.469 21.408 18.608 56.088 ;
     RECT  17.411 57.408 18.608 58.536 ;
     RECT  17.021 60.336 18.608 62.328 ;
     RECT  18.177 64.992 18.608 65.016 ;
     RECT  18.421 66.432 18.608 68.76 ;
     RECT  17.941 69.792 18.608 69.816 ;
     RECT  16.405 70.8 18.608 70.824 ;
     RECT  18.181 75.168 18.608 75.768 ;
     RECT  13.504 77.328 18.608 77.352 ;
     RECT  16.501 79.488 18.608 79.56 ;
     RECT  16.309 84.144 18.608 86.328 ;
     RECT  18.608 2.148 18.613 86.412 ;
     RECT  16.309 87.456 18.613 87.48 ;
     RECT  18.613 2.148 18.712 87.48 ;
     RECT  18.712 2.418 18.904 87.48 ;
     RECT  18.904 84.144 18.965 87.48 ;
     RECT  18.904 64.992 19.325 65.016 ;
     RECT  18.904 21.36 19.933 51.384 ;
     RECT  18.904 52.848 19.933 58.536 ;
     RECT  19.933 21.36 19.957 58.536 ;
     RECT  19.957 21.312 20.005 58.536 ;
     RECT  18.904 59.568 20.005 62.472 ;
     RECT  18.904 66.816 20.005 66.84 ;
     RECT  20.005 21.312 20.041 62.472 ;
     RECT  18.904 11.664 20.101 13.896 ;
     RECT  20.005 66.48 20.101 66.84 ;
     RECT  20.041 21.312 20.252 63.336 ;
     RECT  20.252 21.312 20.339 63.816 ;
     RECT  20.339 21.312 20.677 63.72 ;
     RECT  18.904 3.648 20.869 4.92 ;
     RECT  18.904 16.368 21.013 19.08 ;
     RECT  20.677 20.88 21.013 63.72 ;
     RECT  20.965 6.816 21.061 6.84 ;
     RECT  18.965 87.456 21.205 87.48 ;
     RECT  18.965 84.144 21.301 86.328 ;
     RECT  21.205 87.456 21.301 88.44 ;
     RECT  21.301 84.144 21.347 88.44 ;
     RECT  20.869 3.648 21.349 5.544 ;
     RECT  21.347 84.144 21.385 87.48 ;
     RECT  21.349 3.552 21.445 5.544 ;
     RECT  21.061 6.816 21.493 7.08 ;
     RECT  20.101 11.664 21.589 14.664 ;
     RECT  21.013 16.368 21.589 63.72 ;
     RECT  21.589 16.368 21.781 63.816 ;
     RECT  18.904 10.608 21.829 10.632 ;
     RECT  21.589 11.664 21.829 14.952 ;
     RECT  18.904 2.496 21.877 2.52 ;
     RECT  21.445 3.552 21.877 5.592 ;
     RECT  21.877 2.496 21.925 5.592 ;
     RECT  21.493 6.816 21.925 7.704 ;
     RECT  18.904 8.976 21.973 9 ;
     RECT  21.829 10.608 22.069 14.952 ;
     RECT  20.101 66.144 22.165 66.84 ;
     RECT  18.904 67.824 22.165 68.76 ;
     RECT  18.904 75.168 22.201 75.768 ;
     RECT  18.904 77.328 22.201 77.352 ;
     RECT  21.781 16.272 22.536 63.816 ;
     RECT  20.293 64.992 22.536 65.016 ;
     RECT  21.385 84.144 23.564 86.328 ;
     RECT  23.564 84.048 23.845 86.328 ;
     RECT  21.385 87.456 23.845 87.48 ;
     RECT  23.845 84.048 23.969 87.48 ;
     RECT  21.925 2.496 24.008 7.704 ;
     RECT  21.973 8.784 24.008 9 ;
     RECT  22.069 10.032 24.008 14.952 ;
     RECT  22.536 16.272 24.008 65.016 ;
     RECT  22.165 66.144 24.008 68.76 ;
     RECT  18.904 69.792 24.008 70.824 ;
     RECT  22.201 75.168 24.008 77.352 ;
     RECT  18.904 79.488 24.008 79.56 ;
     RECT  23.969 84.048 24.008 86.412 ;
     RECT  24.008 2.148 24.112 65.016 ;
     RECT  24.008 66.144 24.112 86.412 ;
     RECT  24.112 2.418 24.304 65.016 ;
     RECT  24.112 66.144 24.304 86.328 ;
     RECT  24.304 84.144 26.437 86.328 ;
     RECT  23.969 87.456 26.437 87.48 ;
     RECT  26.437 84.144 26.885 87.48 ;
     RECT  26.885 84.144 29.029 86.328 ;
     RECT  26.885 87.456 29.029 87.48 ;
     RECT  29.029 84.144 29.153 87.48 ;
     RECT  24.304 2.496 29.408 7.704 ;
     RECT  24.304 8.784 29.408 8.808 ;
     RECT  24.304 10.032 29.408 10.056 ;
     RECT  24.304 11.136 29.408 14.952 ;
     RECT  24.304 16.272 29.408 65.016 ;
     RECT  24.304 66.144 29.408 68.76 ;
     RECT  24.304 69.792 29.408 70.824 ;
     RECT  24.304 75.168 29.408 77.352 ;
     RECT  24.304 79.488 29.408 79.56 ;
     RECT  29.153 84.144 29.408 86.412 ;
     RECT  29.408 2.148 29.512 65.016 ;
     RECT  29.408 66.144 29.512 86.412 ;
     RECT  29.512 2.418 29.704 65.016 ;
     RECT  29.512 66.144 29.704 86.328 ;
     RECT  29.704 84.144 31.453 86.328 ;
     RECT  29.153 87.456 31.453 87.48 ;
     RECT  31.453 84.144 31.477 87.48 ;
     RECT  31.477 84.144 31.537 88.44 ;
     RECT  31.537 87.456 31.715 88.44 ;
     RECT  31.537 84.144 32.821 86.328 ;
     RECT  29.704 75.168 33.037 77.352 ;
     RECT  32.821 83.232 33.077 86.328 ;
     RECT  31.715 87.456 34.261 87.48 ;
     RECT  33.077 84.144 34.333 86.328 ;
     RECT  34.333 83.856 34.477 86.328 ;
     RECT  34.261 87.456 34.477 88.44 ;
     RECT  34.477 83.856 34.547 88.44 ;
     RECT  34.547 83.856 34.561 87.48 ;
     RECT  29.704 2.496 34.808 7.704 ;
     RECT  29.704 8.784 34.808 8.808 ;
     RECT  29.704 10.032 34.808 10.056 ;
     RECT  29.704 11.136 34.808 14.952 ;
     RECT  29.704 16.272 34.808 65.016 ;
     RECT  29.704 66.144 34.808 68.76 ;
     RECT  29.704 69.792 34.808 70.824 ;
     RECT  33.037 75.12 34.808 77.352 ;
     RECT  29.704 79.488 34.808 79.56 ;
     RECT  34.561 83.856 34.808 86.412 ;
     RECT  34.808 2.148 34.912 65.016 ;
     RECT  34.808 66.144 34.912 86.412 ;
     RECT  34.912 2.418 35.104 65.016 ;
     RECT  34.912 66.144 35.104 86.328 ;
     RECT  34.561 87.456 36.565 87.48 ;
     RECT  36.565 87.456 36.947 88.44 ;
     RECT  35.104 83.856 37.685 86.328 ;
     RECT  37.685 83.856 38.195 86.088 ;
     RECT  36.947 87.456 39.265 87.48 ;
     RECT  39.265 87.456 39.539 87.816 ;
     RECT  35.104 2.496 40.208 7.704 ;
     RECT  35.104 8.784 40.208 8.808 ;
     RECT  35.104 10.032 40.208 10.056 ;
     RECT  35.104 11.136 40.208 14.952 ;
     RECT  35.104 16.272 40.208 65.016 ;
     RECT  35.104 66.144 40.208 68.76 ;
     RECT  35.104 69.792 40.208 70.824 ;
     RECT  35.104 75.12 40.208 77.352 ;
     RECT  35.104 79.488 40.208 79.56 ;
     RECT  38.195 83.856 40.208 85.992 ;
     RECT  40.208 2.148 40.312 65.016 ;
     RECT  40.208 66.144 40.312 86.412 ;
     RECT  40.312 2.418 40.504 65.016 ;
     RECT  40.312 66.144 40.504 86.142 ;
     RECT  40.504 83.856 42.085 85.992 ;
     RECT  39.539 87.456 42.085 87.48 ;
     RECT  42.085 83.856 42.185 87.48 ;
     RECT  42.185 83.856 43.765 85.992 ;
     RECT  43.765 83.856 44.725 86.088 ;
     RECT  42.185 87.456 44.725 87.48 ;
     RECT  44.725 83.856 44.813 87.48 ;
     RECT  44.813 83.856 45.493 86.412 ;
     RECT  40.504 2.496 45.608 7.704 ;
     RECT  40.504 8.784 45.608 8.808 ;
     RECT  40.504 10.032 45.608 10.056 ;
     RECT  40.504 11.136 45.608 14.952 ;
     RECT  40.504 16.272 45.608 65.016 ;
     RECT  40.504 66.144 45.608 68.76 ;
     RECT  40.504 69.792 45.608 70.824 ;
     RECT  40.504 75.12 45.608 77.352 ;
     RECT  40.504 79.488 45.608 79.56 ;
     RECT  45.493 83.376 45.608 86.412 ;
     RECT  45.608 2.148 45.712 65.016 ;
     RECT  45.608 66.144 45.712 86.412 ;
     RECT  45.712 2.418 45.904 65.016 ;
     RECT  45.712 66.144 45.904 86.142 ;
     RECT  45.904 83.856 47.257 85.992 ;
     RECT  47.257 82.944 47.317 85.992 ;
     RECT  44.813 87.456 47.317 87.48 ;
     RECT  47.317 82.944 47.693 87.48 ;
     RECT  47.693 82.944 49.724 85.992 ;
     RECT  47.693 87.456 49.765 87.48 ;
     RECT  49.724 82.944 49.811 86.376 ;
     RECT  49.765 87.456 50.003 88.44 ;
     RECT  45.904 2.496 51.008 7.704 ;
     RECT  45.904 8.784 51.008 8.808 ;
     RECT  45.904 10.032 51.008 10.056 ;
     RECT  45.904 11.136 51.008 14.952 ;
     RECT  45.904 16.272 51.008 65.016 ;
     RECT  45.904 66.144 51.008 68.76 ;
     RECT  45.904 69.792 51.008 70.824 ;
     RECT  45.904 75.12 51.008 77.352 ;
     RECT  45.904 79.488 51.008 79.56 ;
     RECT  49.811 82.944 51.008 85.992 ;
     RECT  51.008 2.148 51.112 65.016 ;
     RECT  51.008 66.144 51.112 86.412 ;
     RECT  51.112 2.418 51.304 65.016 ;
     RECT  51.112 66.144 51.304 86.142 ;
     RECT  50.003 87.456 52.549 87.48 ;
     RECT  51.304 82.944 52.621 85.992 ;
     RECT  52.549 87.456 52.621 88.44 ;
     RECT  52.621 82.944 52.691 88.44 ;
     RECT  52.691 82.944 52.705 87.48 ;
     RECT  51.304 75.12 54.277 77.352 ;
     RECT  51.304 66.144 54.641 68.76 ;
     RECT  52.705 87.456 55.141 87.48 ;
     RECT  55.141 87.168 55.505 87.48 ;
     RECT  51.304 2.496 56.408 7.704 ;
     RECT  51.304 8.784 56.408 8.808 ;
     RECT  51.304 10.032 56.408 10.056 ;
     RECT  51.304 11.136 56.408 14.952 ;
     RECT  51.304 16.272 56.408 65.016 ;
     RECT  54.641 66.144 56.408 66.504 ;
     RECT  54.641 67.536 56.408 68.76 ;
     RECT  51.304 69.792 56.408 70.824 ;
     RECT  54.277 75.12 56.408 77.64 ;
     RECT  51.304 79.488 56.408 79.56 ;
     RECT  52.705 82.944 56.408 85.992 ;
     RECT  56.408 2.148 56.512 65.016 ;
     RECT  56.408 66.144 56.512 86.412 ;
     RECT  56.512 2.418 56.704 65.016 ;
     RECT  56.512 66.144 56.704 86.142 ;
     RECT  55.505 87.456 57.517 87.48 ;
     RECT  57.517 87.456 57.827 87.816 ;
     RECT  56.704 75.12 59.317 77.64 ;
     RECT  56.704 82.944 60.373 85.992 ;
     RECT  56.704 2.496 61.808 7.704 ;
     RECT  56.704 8.784 61.808 8.808 ;
     RECT  56.704 10.032 61.808 10.056 ;
     RECT  56.704 11.136 61.808 14.952 ;
     RECT  56.704 16.272 61.808 65.016 ;
     RECT  56.704 66.144 61.808 66.504 ;
     RECT  56.704 67.536 61.808 68.76 ;
     RECT  56.704 69.792 61.808 70.824 ;
     RECT  59.317 74.88 61.808 77.64 ;
     RECT  56.704 79.488 61.808 79.56 ;
     RECT  60.373 82.944 61.808 86.376 ;
     RECT  61.808 2.148 61.912 65.016 ;
     RECT  61.808 66.144 61.912 86.412 ;
     RECT  61.912 2.418 62.104 65.016 ;
     RECT  61.912 66.144 62.104 86.142 ;
     RECT  57.827 87.456 63.013 87.48 ;
     RECT  63.013 87.168 63.569 87.48 ;
     RECT  62.104 82.944 65.605 85.992 ;
     RECT  63.569 87.456 65.605 87.48 ;
     RECT  65.605 82.944 66.053 87.48 ;
     RECT  62.104 2.496 67.208 7.704 ;
     RECT  62.104 8.784 67.208 8.808 ;
     RECT  62.104 10.032 67.208 10.056 ;
     RECT  62.104 11.136 67.208 14.952 ;
     RECT  62.104 16.272 67.208 65.016 ;
     RECT  62.104 66.144 67.208 66.504 ;
     RECT  62.104 67.536 67.208 68.76 ;
     RECT  62.104 69.792 67.208 70.824 ;
     RECT  62.104 74.88 67.208 77.928 ;
     RECT  62.104 79.488 67.208 79.56 ;
     RECT  66.053 82.944 67.208 85.992 ;
     RECT  67.208 2.148 67.312 65.016 ;
     RECT  67.312 2.418 67.504 65.016 ;
     RECT  67.208 66.144 67.504 86.412 ;
     RECT  67.504 82.944 68.165 86.412 ;
     RECT  66.053 87.456 68.165 87.48 ;
     RECT  68.165 82.944 68.249 87.48 ;
     RECT  67.504 75.168 68.629 79.56 ;
     RECT  68.629 75.168 68.749 79.992 ;
     RECT  68.749 74.448 68.753 79.992 ;
     RECT  68.249 82.944 68.897 85.992 ;
     RECT  68.753 74.448 69.793 79.56 ;
     RECT  68.249 87.456 69.941 87.48 ;
     RECT  69.793 74.016 70.013 79.56 ;
     RECT  67.504 66.144 70.117 66.504 ;
     RECT  67.504 67.536 70.117 68.76 ;
     RECT  70.172 88.464 70.259 88.488 ;
     RECT  70.117 66.144 70.445 68.76 ;
     RECT  68.897 82.944 70.585 85.752 ;
     RECT  70.585 87.792 70.883 87.816 ;
     RECT  70.013 74.112 70.909 79.56 ;
     RECT  70.585 82.944 71.18 85.8 ;
     RECT  71.18 82.944 71.267 86.184 ;
     RECT  71.267 82.944 71.708 85.752 ;
     RECT  70.441 81.072 71.845 81.096 ;
     RECT  70.909 74.112 72.133 79.752 ;
     RECT  72.133 73.536 72.373 79.752 ;
     RECT  71.845 81.024 72.373 81.096 ;
     RECT  67.504 2.496 72.608 7.704 ;
     RECT  67.504 8.784 72.608 8.808 ;
     RECT  67.504 10.032 72.608 10.056 ;
     RECT  67.504 11.136 72.608 14.952 ;
     RECT  67.504 16.272 72.608 65.016 ;
     RECT  70.445 66.144 72.608 66.504 ;
     RECT  70.445 67.536 72.608 68.76 ;
     RECT  67.504 69.792 72.608 70.824 ;
     RECT  72.373 73.536 72.608 81.144 ;
     RECT  71.708 82.128 72.608 85.752 ;
     RECT  72.608 2.148 72.712 65.016 ;
     RECT  72.608 66.144 72.712 86.412 ;
     RECT  72.712 2.418 72.904 65.016 ;
     RECT  72.712 66.144 72.904 86.376 ;
     RECT  72.904 69.792 72.965 71.928 ;
     RECT  72.904 82.848 73.235 86.376 ;
     RECT  72.965 71.136 73.325 71.928 ;
     RECT  72.904 80.832 73.427 81.576 ;
     RECT  73.189 88.416 73.475 88.44 ;
     RECT  72.904 74.256 73.657 79.8 ;
     RECT  73.657 74.256 73.969 79.608 ;
     RECT  72.965 69.792 74.185 70.152 ;
     RECT  73.325 71.136 74.185 71.88 ;
     RECT  73.235 82.848 74.545 85.752 ;
     RECT  74.185 69.792 74.653 71.88 ;
     RECT  74.653 69.792 74.729 73.08 ;
     RECT  73.969 74.064 75.157 79.608 ;
     RECT  73.427 80.832 75.157 80.904 ;
     RECT  75.157 74.064 75.251 80.904 ;
     RECT  74.729 71.664 75.373 73.08 ;
     RECT  75.251 74.64 75.481 80.904 ;
     RECT  75.373 71.664 75.769 73.512 ;
     RECT  74.545 82.848 75.841 85.8 ;
     RECT  74.729 69.792 75.913 70.296 ;
     RECT  75.769 71.424 75.913 73.512 ;
     RECT  75.841 82.848 75.925 86.616 ;
     RECT  72.904 67.536 75.973 68.76 ;
     RECT  75.913 69.792 75.973 73.512 ;
     RECT  75.877 88.416 76.115 88.44 ;
     RECT  75.973 67.536 76.345 73.512 ;
     RECT  75.481 74.64 76.345 81.432 ;
     RECT  76.345 67.536 76.997 81.432 ;
     RECT  75.925 82.848 77.461 85.8 ;
     RECT  76.997 67.632 77.569 81.432 ;
     RECT  77.461 82.8 77.569 85.8 ;
     RECT  72.904 2.496 78.008 7.704 ;
     RECT  72.904 8.784 78.008 8.808 ;
     RECT  72.904 10.032 78.008 10.056 ;
     RECT  72.904 11.136 78.008 14.952 ;
     RECT  72.904 16.272 78.008 65.016 ;
     RECT  72.904 66.144 78.008 66.504 ;
     RECT  77.569 67.632 78.008 85.8 ;
     RECT  78.008 2.148 78.112 65.016 ;
     RECT  78.008 66.144 78.112 86.412 ;
     RECT  78.112 2.418 78.304 65.016 ;
     RECT  78.112 66.144 78.304 86.142 ;
     RECT  78.433 88.416 78.707 88.44 ;
     RECT  78.304 67.632 79.481 85.8 ;
     RECT  79.481 67.632 80.449 68.808 ;
     RECT  79.481 69.792 80.449 85.8 ;
     RECT  78.304 66.144 80.701 66.504 ;
     RECT  80.449 67.632 80.701 85.8 ;
     RECT  80.701 66.144 81.025 85.8 ;
     RECT  81.025 66.144 81.109 86.616 ;
     RECT  81.061 88.416 81.299 88.44 ;
     RECT  81.109 66.144 82.141 85.8 ;
     RECT  82.141 66.144 82.253 85.992 ;
     RECT  82.253 67.632 82.285 85.992 ;
     RECT  78.304 2.496 83.408 7.704 ;
     RECT  78.304 8.784 83.408 8.808 ;
     RECT  78.304 10.032 83.408 10.056 ;
     RECT  78.304 11.136 83.408 14.952 ;
     RECT  78.304 16.272 83.408 65.016 ;
     RECT  82.253 66.144 83.408 66.504 ;
     RECT  82.285 67.632 83.408 86.04 ;
     RECT  83.408 2.148 83.512 65.016 ;
     RECT  83.408 66.144 83.512 86.412 ;
     RECT  83.512 2.418 83.704 65.016 ;
     RECT  83.512 66.144 83.704 86.142 ;
     RECT  83.653 87.792 83.939 87.816 ;
     RECT  83.704 67.536 86.485 86.04 ;
     RECT  86.485 67.536 86.573 86.616 ;
     RECT  86.573 67.536 86.681 86.04 ;
     RECT  86.681 67.632 87.653 86.04 ;
     RECT  83.704 2.496 88.808 7.704 ;
     RECT  83.704 8.784 88.808 8.808 ;
     RECT  83.704 10.032 88.808 10.056 ;
     RECT  83.704 11.136 88.808 14.952 ;
     RECT  83.704 16.272 88.808 65.016 ;
     RECT  83.704 66.144 88.808 66.504 ;
     RECT  87.653 67.632 88.808 78.744 ;
     RECT  87.653 79.776 88.808 86.04 ;
     RECT  88.808 2.148 88.912 65.016 ;
     RECT  88.808 66.144 88.912 86.412 ;
     RECT  88.912 2.418 89.104 65.016 ;
     RECT  88.912 66.144 89.104 86.142 ;
     RECT  89.125 87.168 89.633 87.192 ;
     RECT  89.104 67.536 91.717 86.04 ;
     RECT  91.717 67.536 92.369 86.616 ;
     RECT  89.104 2.496 94.208 7.704 ;
     RECT  89.104 8.784 94.208 8.808 ;
     RECT  89.104 10.032 94.208 10.056 ;
     RECT  89.104 11.136 94.208 14.952 ;
     RECT  89.104 16.272 94.208 65.016 ;
     RECT  89.104 66.144 94.208 66.504 ;
     RECT  92.369 67.536 94.208 86.04 ;
     RECT  94.208 2.148 94.312 65.016 ;
     RECT  94.208 66.144 94.312 86.412 ;
     RECT  94.301 88.416 94.385 88.44 ;
     RECT  94.312 2.418 94.504 65.016 ;
     RECT  94.312 66.144 94.504 86.142 ;
     RECT  94.504 67.536 95.753 86.04 ;
     RECT  95.753 67.536 96.829 81.144 ;
     RECT  95.753 82.272 96.829 86.04 ;
     RECT  96.901 87.168 96.995 87.192 ;
     RECT  94.504 66.144 98.725 66.504 ;
     RECT  96.829 67.536 98.725 86.04 ;
     RECT  99.421 87.168 99.587 87.192 ;
     RECT  94.504 2.496 99.608 7.704 ;
     RECT  94.504 8.784 99.608 8.808 ;
     RECT  94.504 10.032 99.608 10.056 ;
     RECT  94.504 11.136 99.608 14.952 ;
     RECT  94.504 16.272 99.608 65.016 ;
     RECT  98.725 66.144 99.608 86.04 ;
     RECT  99.608 2.148 99.712 65.016 ;
     RECT  99.608 66.144 99.712 86.412 ;
     RECT  99.712 2.418 99.904 65.016 ;
     RECT  99.712 66.144 99.904 86.142 ;
     RECT  99.904 67.536 102.181 86.04 ;
     RECT  102.181 67.536 102.629 86.664 ;
     RECT  102.629 67.536 103.313 86.04 ;
     RECT  104.773 87.168 105.005 87.192 ;
     RECT  99.904 2.496 105.008 7.704 ;
     RECT  99.904 8.784 105.008 8.808 ;
     RECT  99.904 10.032 105.008 10.056 ;
     RECT  99.904 11.136 105.008 14.952 ;
     RECT  99.904 16.272 105.008 65.016 ;
     RECT  99.904 66.144 105.008 66.504 ;
     RECT  103.313 67.776 105.008 86.04 ;
     RECT  105.008 2.148 105.112 65.016 ;
     RECT  105.008 66.144 105.112 86.412 ;
     RECT  105.112 2.418 105.304 65.016 ;
     RECT  105.112 66.144 105.304 86.142 ;
     RECT  105.304 67.872 105.797 86.04 ;
     RECT  105.797 68.16 106.229 86.04 ;
     RECT  106.229 68.208 107.324 86.04 ;
     RECT  107.324 68.208 107.411 86.664 ;
     RECT  107.411 68.208 107.795 86.04 ;
     RECT  105.304 8.784 108.673 8.808 ;
     RECT  105.304 10.032 108.673 10.056 ;
     RECT  107.795 68.448 108.893 86.04 ;
     RECT  108.673 8.784 109.001 10.056 ;
     RECT  108.893 68.688 109.073 86.04 ;
     RECT  109.073 68.736 109.361 86.04 ;
     RECT  109.361 68.88 109.42 86.04 ;
     RECT  105.304 11.136 109.573 14.952 ;
     RECT  109.897 87.744 110.051 87.768 ;
     RECT  105.304 2.496 110.408 7.704 ;
     RECT  109.001 8.784 110.408 9.336 ;
     RECT  109.573 10.608 110.408 14.952 ;
     RECT  105.304 16.272 110.408 65.016 ;
     RECT  105.304 66.144 110.408 66.504 ;
     RECT  109.42 68.88 110.408 80.904 ;
     RECT  109.42 81.936 110.408 86.04 ;
     RECT  110.408 2.148 110.512 65.016 ;
     RECT  110.408 66.144 110.512 86.412 ;
     RECT  110.512 2.418 110.704 65.016 ;
     RECT  110.512 66.144 110.704 86.142 ;
     RECT  110.704 67.872 111.313 80.808 ;
     RECT  111.313 68.496 111.413 80.808 ;
     RECT  111.413 68.496 111.449 80.376 ;
     RECT  111.449 68.496 111.557 80.328 ;
     RECT  110.704 81.936 111.733 85.464 ;
     RECT  111.557 69.024 111.953 80.328 ;
     RECT  111.953 69.024 112.097 74.136 ;
     RECT  110.704 16.272 112.205 65.016 ;
     RECT  112.097 70.8 112.457 74.136 ;
     RECT  112.457 71.232 112.529 74.136 ;
     RECT  112.529 71.232 112.565 72.888 ;
     RECT  111.953 75.456 112.597 80.328 ;
     RECT  111.733 81.552 112.597 85.464 ;
     RECT  112.565 72.336 112.673 72.888 ;
     RECT  112.565 71.232 112.709 71.352 ;
     RECT  112.597 87.168 112.817 87.192 ;
     RECT  112.709 71.232 112.835 71.256 ;
     RECT  112.673 72.432 112.853 72.888 ;
     RECT  112.597 75.456 112.993 85.464 ;
     RECT  112.993 75.36 113.033 85.464 ;
     RECT  113.033 75.36 113.069 76.824 ;
     RECT  113.033 78.048 113.285 85.464 ;
     RECT  112.529 74.112 113.461 74.136 ;
     RECT  113.069 75.36 113.461 76.488 ;
     RECT  113.461 74.112 113.465 76.488 ;
     RECT  113.465 74.112 113.501 76.248 ;
     RECT  113.501 74.64 113.507 76.248 ;
     RECT  113.507 74.64 113.545 74.664 ;
     RECT  113.285 81.936 113.573 85.464 ;
     RECT  112.853 72.528 113.717 72.888 ;
     RECT  113.717 72.528 113.933 72.6 ;
     RECT  113.285 78.048 113.933 80.904 ;
     RECT  113.933 80.88 114.005 80.904 ;
     RECT  113.933 72.528 114.041 72.552 ;
     RECT  110.704 11.664 114.181 14.952 ;
     RECT  113.933 78.048 114.221 79.752 ;
     RECT  114.221 78.048 114.397 78.168 ;
     RECT  113.507 76.08 114.973 76.248 ;
     RECT  114.397 77.712 114.973 78.168 ;
     RECT  115.237 87.168 115.769 87.192 ;
     RECT  110.704 2.496 115.808 7.704 ;
     RECT  110.704 8.784 115.808 9.24 ;
     RECT  110.704 10.608 115.808 10.632 ;
     RECT  114.181 11.664 115.808 15.192 ;
     RECT  112.205 16.32 115.808 65.016 ;
     RECT  110.704 66.144 115.808 66.504 ;
     RECT  112.097 69.024 115.808 69.816 ;
     RECT  114.973 76.08 115.808 78.168 ;
     RECT  114.221 79.536 115.808 79.752 ;
     RECT  113.573 81.936 115.808 85.224 ;
     RECT  115.808 2.148 115.912 65.016 ;
     RECT  115.808 66.144 115.912 86.412 ;
     RECT  115.912 2.418 116.104 65.016 ;
     RECT  115.912 66.144 116.104 86.142 ;
     RECT  116.104 78.48 116.243 78.504 ;
     RECT  116.104 79.728 116.243 80.664 ;
     RECT  116.104 16.32 117.216 65.016 ;
     RECT  117.216 16.32 117.389 63.72 ;
     RECT  117.216 64.992 117.857 65.016 ;
     RECT  117.829 87.168 118.145 87.192 ;
     RECT  117.389 24.624 118.613 63.72 ;
     RECT  118.613 24.624 118.649 60.456 ;
     RECT  118.649 24.624 119.081 45.768 ;
     RECT  119.081 24.624 119.117 45.672 ;
     RECT  118.649 46.896 119.117 60.456 ;
     RECT  118.613 61.488 119.189 63.72 ;
     RECT  119.117 53.232 119.549 56.04 ;
     RECT  119.117 42.864 119.585 43.656 ;
     RECT  119.189 61.872 119.585 63.72 ;
     RECT  119.585 61.872 119.621 63.144 ;
     RECT  119.585 42.864 119.657 43.272 ;
     RECT  119.621 61.872 119.657 62.664 ;
     RECT  119.657 62.544 119.693 62.568 ;
     RECT  119.117 57.456 119.729 58.824 ;
     RECT  119.117 49.392 119.765 49.416 ;
     RECT  119.729 57.648 119.765 58.44 ;
     RECT  119.117 24.624 119.801 41.448 ;
     RECT  119.117 50.544 119.801 50.76 ;
     RECT  119.549 53.232 119.801 55.56 ;
     RECT  119.801 24.624 119.837 37.896 ;
     RECT  119.801 55.536 119.837 55.56 ;
     RECT  119.837 36.528 119.873 37.896 ;
     RECT  119.801 39.312 119.909 41.448 ;
     RECT  119.909 39.312 119.945 41.064 ;
     RECT  119.657 42.864 119.945 42.888 ;
     RECT  119.801 53.232 119.945 54.216 ;
     RECT  119.945 39.312 119.981 39.336 ;
     RECT  119.117 51.888 119.981 51.912 ;
     RECT  119.765 57.648 119.981 57.672 ;
     RECT  119.873 36.528 120.017 37.176 ;
     RECT  119.117 46.896 120.089 46.92 ;
     RECT  119.945 41.04 120.161 41.064 ;
     RECT  120.428 86.64 120.515 86.664 ;
     RECT  116.104 66.144 121.093 66.504 ;
     RECT  116.104 2.496 121.208 7.704 ;
     RECT  116.104 8.784 121.208 9.24 ;
     RECT  116.104 10.608 121.208 10.632 ;
     RECT  116.104 11.664 121.208 15.192 ;
     RECT  117.389 16.32 121.208 23.592 ;
     RECT  119.837 24.624 121.208 35.496 ;
     RECT  120.017 37.152 121.208 37.176 ;
     RECT  119.945 53.424 121.208 53.448 ;
     RECT  121.093 65.952 121.208 66.504 ;
     RECT  116.104 69.024 121.208 69.816 ;
     RECT  116.104 76.08 121.208 76.104 ;
     RECT  116.104 81.936 121.208 85.224 ;
     RECT  121.208 2.148 121.312 86.412 ;
     RECT  121.312 2.418 121.504 86.142 ;
     RECT  121.504 24.624 122.825 35.496 ;
     RECT  123.001 86.64 123.107 86.664 ;
     RECT  121.504 81.888 123.401 85.368 ;
     RECT  123.401 81.888 123.689 85.32 ;
     RECT  124.405 77.472 124.837 77.496 ;
     RECT  121.504 76.08 125.077 76.104 ;
     RECT  124.837 77.472 125.123 77.928 ;
     RECT  124.789 80.784 125.125 80.808 ;
     RECT  123.689 81.888 125.125 85.224 ;
     RECT  125.077 76.08 125.165 76.344 ;
     RECT  125.621 87.168 125.705 87.192 ;
     RECT  121.504 2.496 126.608 7.704 ;
     RECT  121.504 8.784 126.608 9.24 ;
     RECT  121.504 10.608 126.608 10.632 ;
     RECT  121.504 11.664 126.608 15.192 ;
     RECT  121.504 16.32 126.608 23.592 ;
     RECT  122.825 24.912 126.608 35.496 ;
     RECT  121.504 37.152 126.608 37.176 ;
     RECT  121.504 65.952 126.608 66.504 ;
     RECT  121.504 69.024 126.608 69.048 ;
     RECT  125.165 76.08 126.608 76.104 ;
     RECT  125.123 77.904 126.608 77.928 ;
     RECT  125.893 79.632 126.608 79.656 ;
     RECT  125.125 80.784 126.608 85.224 ;
     RECT  126.608 2.148 126.712 86.412 ;
     RECT  126.712 2.418 126.904 86.142 ;
     RECT  126.904 26.352 126.965 35.496 ;
     RECT  126.965 27.168 127.073 35.496 ;
     RECT  128.252 86.64 128.339 86.664 ;
     RECT  126.904 80.784 128.477 84.936 ;
     RECT  126.904 77.904 128.945 77.928 ;
     RECT  126.904 76.08 129.301 76.104 ;
     RECT  129.301 76.08 129.349 76.392 ;
     RECT  129.349 75.264 129.395 76.392 ;
     RECT  128.477 80.784 129.989 84.6 ;
     RECT  127.073 27.456 130.025 35.496 ;
     RECT  129.989 82.752 130.097 84.6 ;
     RECT  126.904 11.664 130.525 15.192 ;
     RECT  129.395 75.264 130.525 76.104 ;
     RECT  130.025 27.456 130.601 35.304 ;
     RECT  130.097 82.752 130.601 84.312 ;
     RECT  130.885 87.168 131.429 87.192 ;
     RECT  126.904 65.952 131.461 66.504 ;
     RECT  131.461 65.952 131.605 67.272 ;
     RECT  131.633 46.752 131.677 46.776 ;
     RECT  126.904 69.024 131.785 69.048 ;
     RECT  131.317 45.648 131.893 45.672 ;
     RECT  126.904 2.496 132.008 7.704 ;
     RECT  126.904 8.784 132.008 9.24 ;
     RECT  126.904 10.608 132.008 10.632 ;
     RECT  130.525 11.664 132.008 15.288 ;
     RECT  126.904 16.32 132.008 23.592 ;
     RECT  130.601 27.456 132.008 35.256 ;
     RECT  126.904 37.152 132.008 37.176 ;
     RECT  131.893 43.296 132.008 43.32 ;
     RECT  131.893 44.88 132.008 45.672 ;
     RECT  131.677 46.752 132.008 46.872 ;
     RECT  131.713 47.904 132.008 47.928 ;
     RECT  131.605 65.52 132.008 67.272 ;
     RECT  131.785 69.024 132.008 69.864 ;
     RECT  130.525 75.264 132.008 76.248 ;
     RECT  129.989 80.784 132.008 81.672 ;
     RECT  130.601 82.752 132.008 84.168 ;
     RECT  132.008 2.148 132.112 86.412 ;
     RECT  132.112 2.418 132.304 86.142 ;
     RECT  132.304 42.48 132.581 43.32 ;
     RECT  132.304 68.784 132.604 69.864 ;
     RECT  132.304 78.336 132.707 78.696 ;
     RECT  132.304 10.608 132.833 25.176 ;
     RECT  132.304 54.096 132.851 56.28 ;
     RECT  132.304 79.728 132.851 85.512 ;
     RECT  132.707 78.672 132.877 78.696 ;
     RECT  132.851 56.16 132.913 56.28 ;
     RECT  132.833 11.088 132.94 25.176 ;
     RECT  132.304 52.992 132.947 53.016 ;
     RECT  132.304 75.552 133.091 77.256 ;
     RECT  132.304 72.336 133.121 72.408 ;
     RECT  132.851 54.096 133.229 54.648 ;
     RECT  132.304 2.496 133.285 7.704 ;
     RECT  132.304 8.784 133.285 9.24 ;
     RECT  132.304 39.792 133.285 40.44 ;
     RECT  132.581 42.48 133.285 43.176 ;
     RECT  132.304 63.216 133.301 64.248 ;
     RECT  133.301 63.792 133.333 64.248 ;
     RECT  132.304 65.52 133.333 66.504 ;
     RECT  133.333 63.792 133.379 66.504 ;
     RECT  132.304 26.256 133.429 35.256 ;
     RECT  132.604 69.024 133.445 69.864 ;
     RECT  133.229 54.096 133.481 54.12 ;
     RECT  133.379 65.952 133.481 66.504 ;
     RECT  133.285 2.496 133.513 9.24 ;
     RECT  132.304 37.152 133.513 37.176 ;
     RECT  133.429 26.256 133.585 35.688 ;
     RECT  133.285 39.792 133.621 43.176 ;
     RECT  133.585 26.256 133.657 35.976 ;
     RECT  133.513 37.008 133.657 37.176 ;
     RECT  133.525 87.744 133.805 87.768 ;
     RECT  133.091 75.552 133.877 76.392 ;
     RECT  132.851 80.784 133.945 85.512 ;
     RECT  133.297 38.16 133.981 38.184 ;
     RECT  133.621 39.696 133.981 43.176 ;
     RECT  132.304 46.848 133.981 46.872 ;
     RECT  132.94 11.088 134.093 25.128 ;
     RECT  133.877 75.552 134.093 75.816 ;
     RECT  133.945 80.352 134.161 85.512 ;
     RECT  132.304 70.944 134.197 70.968 ;
     RECT  133.121 72.336 134.197 72.36 ;
     RECT  134.093 75.552 134.197 75.72 ;
     RECT  133.657 79.248 134.197 79.272 ;
     RECT  132.304 47.904 134.233 47.928 ;
     RECT  134.197 70.944 134.237 72.36 ;
     RECT  133.729 67.776 134.377 67.8 ;
     RECT  133.657 26.256 134.413 37.176 ;
     RECT  134.237 70.944 134.444 71.88 ;
     RECT  133.981 38.16 134.449 43.176 ;
     RECT  133.445 69.024 134.449 69.048 ;
     RECT  134.444 70.08 134.449 71.88 ;
     RECT  134.161 80.352 134.485 85.56 ;
     RECT  134.413 26.208 134.521 37.176 ;
     RECT  134.233 47.904 134.521 48.168 ;
     RECT  132.304 49.536 134.521 49.56 ;
     RECT  133.657 59.328 134.521 59.352 ;
     RECT  134.521 26.16 134.525 37.176 ;
     RECT  133.657 52.944 134.529 52.968 ;
     RECT  134.525 34.176 134.533 37.176 ;
     RECT  134.449 38.16 134.533 44.088 ;
     RECT  133.481 65.952 134.579 65.976 ;
     RECT  134.529 52.416 134.593 52.968 ;
     RECT  134.485 80.256 134.629 85.656 ;
     RECT  133.369 51.312 134.64 51.336 ;
     RECT  133.379 64.944 134.675 64.968 ;
     RECT  133.693 62.64 134.677 62.664 ;
     RECT  133.379 63.792 134.677 63.816 ;
     RECT  132.913 56.16 134.705 56.184 ;
     RECT  132.304 73.488 134.725 73.512 ;
     RECT  134.197 75.264 134.725 75.72 ;
     RECT  133.981 46.752 134.732 46.872 ;
     RECT  134.521 47.904 134.732 49.56 ;
     RECT  134.197 78.864 134.737 79.272 ;
     RECT  134.629 80.256 134.737 86.088 ;
     RECT  134.725 73.488 134.771 75.72 ;
     RECT  134.449 69.024 134.773 71.88 ;
     RECT  134.737 78.864 134.773 86.088 ;
     RECT  134.771 73.488 134.812 75.144 ;
     RECT  134.377 67.728 134.813 67.8 ;
     RECT  134.773 68.976 134.813 71.88 ;
     RECT  134.533 34.176 134.849 44.088 ;
     RECT  134.677 62.64 134.849 63.816 ;
     RECT  134.732 46.752 134.867 49.56 ;
     RECT  133.513 2.496 134.915 10.056 ;
     RECT  134.093 16.176 134.917 25.128 ;
     RECT  134.525 26.16 134.917 33.144 ;
     RECT  134.867 46.848 134.917 49.56 ;
     RECT  134.917 46.848 135.001 50.76 ;
     RECT  134.773 78.24 135.011 86.088 ;
     RECT  134.917 16.176 135.029 33.144 ;
     RECT  134.813 69.984 135.101 71.88 ;
     RECT  134.813 68.976 135.173 69 ;
     RECT  135.101 69.984 135.173 70.008 ;
     RECT  135.001 46.848 135.245 49.896 ;
     RECT  135.101 71.616 135.253 71.88 ;
     RECT  134.521 59.328 135.26 59.832 ;
     RECT  135.26 59.232 135.301 59.832 ;
     RECT  135.301 59.232 135.347 59.88 ;
     RECT  134.593 52.416 135.352 53.544 ;
     RECT  134.093 11.088 135.353 14.952 ;
     RECT  134.813 67.728 135.421 67.752 ;
     RECT  135.164 76.896 135.421 76.92 ;
     RECT  135.029 16.224 135.493 33.144 ;
     RECT  134.849 34.176 135.493 42.744 ;
     RECT  134.849 63.264 135.605 63.816 ;
     RECT  134.593 57.552 135.641 57.576 ;
     RECT  135.352 52.416 135.683 53.592 ;
     RECT  135.683 52.416 135.692 53.016 ;
     RECT  135.421 76.704 135.709 76.92 ;
     RECT  135.011 78.24 135.709 85.656 ;
     RECT  134.915 2.496 135.713 5.832 ;
     RECT  134.915 7.392 135.713 10.056 ;
     RECT  135.493 16.224 135.713 42.744 ;
     RECT  134.849 44.064 135.713 44.088 ;
     RECT  135.245 47.184 135.713 49.896 ;
     RECT  135.713 47.184 135.749 49.032 ;
     RECT  135.713 16.224 135.779 28.584 ;
     RECT  135.692 51.792 135.779 53.016 ;
     RECT  135.713 2.496 135.785 5.592 ;
     RECT  135.353 11.088 135.785 12.552 ;
     RECT  135.713 29.616 135.785 42.744 ;
     RECT  135.785 30.672 135.821 42.744 ;
     RECT  135.821 33.024 135.857 42.744 ;
     RECT  135.821 30.672 135.865 31.896 ;
     RECT  135.347 59.856 135.893 59.88 ;
     RECT  135.865 30.672 135.929 30.984 ;
     RECT  135.98 60.288 136.021 60.312 ;
     RECT  136.021 60.288 136.067 61.032 ;
     RECT  134.629 66.096 136.073 66.12 ;
     RECT  134.812 75.12 136.073 75.144 ;
     RECT  135.857 37.632 136.109 42.744 ;
     RECT  133.945 45.168 136.109 45.192 ;
     RECT  135.709 76.704 136.117 85.656 ;
     RECT  136.117 76.704 136.141 86.088 ;
     RECT  136.021 88.416 136.163 88.44 ;
     RECT  135.857 33.024 136.204 36.552 ;
     RECT  135.779 24.288 136.211 28.584 ;
     RECT  135.785 2.592 136.253 5.592 ;
     RECT  135.779 16.224 136.253 22.92 ;
     RECT  136.211 24.288 136.253 28.536 ;
     RECT  135.817 54.72 136.253 54.744 ;
     RECT  134.812 73.488 136.253 73.512 ;
     RECT  135.421 67.392 136.261 67.752 ;
     RECT  136.141 76.56 136.261 86.088 ;
     RECT  136.109 38.832 136.289 42.744 ;
     RECT  135.457 58.656 136.289 58.728 ;
     RECT  135.713 7.392 136.307 9.96 ;
     RECT  136.253 2.64 136.325 5.592 ;
     RECT  135.353 13.536 136.325 14.952 ;
     RECT  135.749 47.184 136.325 48.168 ;
     RECT  136.261 76.56 136.357 86.568 ;
     RECT  136.261 67.248 136.364 67.752 ;
     RECT  136.204 33.12 136.397 36.552 ;
     RECT  135.253 71.616 136.397 72.408 ;
     RECT  136.364 67.248 136.405 67.8 ;
     RECT  134.989 55.872 136.412 55.896 ;
     RECT  136.412 55.872 136.453 55.944 ;
     RECT  136.357 76.56 136.693 87.144 ;
     RECT  135.779 52.416 136.789 53.016 ;
     RECT  136.693 76.56 136.789 87.816 ;
     RECT  136.325 3.312 137.408 5.592 ;
     RECT  136.307 7.632 137.408 7.992 ;
     RECT  136.307 9.072 137.408 9.96 ;
     RECT  135.785 11.232 137.408 12.552 ;
     RECT  136.325 13.536 137.408 14.424 ;
     RECT  136.253 16.224 137.408 22.776 ;
     RECT  136.253 24.288 137.408 28.488 ;
     RECT  135.785 29.616 137.408 29.64 ;
     RECT  135.929 30.672 137.408 30.84 ;
     RECT  136.397 33.408 137.408 36.552 ;
     RECT  136.109 37.632 137.408 37.656 ;
     RECT  136.289 38.832 137.408 41.496 ;
     RECT  136.289 42.72 137.408 42.744 ;
     RECT  136.693 45.024 137.408 45.048 ;
     RECT  136.325 48.144 137.408 48.168 ;
     RECT  136.789 51.888 137.408 53.016 ;
     RECT  136.453 55.248 137.408 55.944 ;
     RECT  136.597 57.024 137.408 57.048 ;
     RECT  136.289 58.656 137.408 58.68 ;
     RECT  136.067 61.008 137.408 61.032 ;
     RECT  135.605 63.264 137.408 63.288 ;
     RECT  136.405 64.416 137.408 64.44 ;
     RECT  136.405 66.672 137.408 67.8 ;
     RECT  136.397 71.616 137.408 71.64 ;
     RECT  136.789 76.176 137.408 87.816 ;
     RECT  137.408 2.148 137.477 87.816 ;
     RECT  137.477 2.148 137.704 87.432 ;
     RECT  137.704 35.184 137.981 35.832 ;
     RECT  137.704 68.352 137.981 80.52 ;
     RECT  137.704 81.888 137.981 87.432 ;
     RECT  137.981 81.888 138.035 82.056 ;
     RECT  137.981 73.824 138.053 80.52 ;
     RECT  138.053 78.096 138.877 80.52 ;
     RECT  138.035 81.888 138.877 81.96 ;
     RECT  137.704 26.832 139.021 27.144 ;
     RECT  137.704 28.56 139.021 28.584 ;
     RECT  137.704 52.224 139.021 52.248 ;
     RECT  137.704 53.376 139.021 54.84 ;
     RECT  137.704 56.544 139.021 57.432 ;
     RECT  137.704 58.56 139.021 58.584 ;
     RECT  137.981 68.352 139.021 72.696 ;
     RECT  138.053 73.824 139.021 77.064 ;
     RECT  138.877 78.096 139.021 81.96 ;
     RECT  138.013 1.44 139.057 1.464 ;
     RECT  137.704 3.744 139.057 3.768 ;
     RECT  137.704 4.896 139.057 6.072 ;
     RECT  137.704 7.2 139.057 8.664 ;
     RECT  137.704 10.368 139.057 10.392 ;
     RECT  137.704 12.096 139.057 12.984 ;
     RECT  137.704 14.688 139.057 15 ;
     RECT  137.704 16.992 139.057 18.168 ;
     RECT  137.704 19.296 139.057 19.32 ;
     RECT  137.704 22.176 139.057 22.2 ;
     RECT  137.704 23.328 139.057 23.64 ;
     RECT  137.704 24.816 139.057 25.128 ;
     RECT  139.021 26.832 139.057 28.584 ;
     RECT  137.704 32.016 139.057 32.04 ;
     RECT  137.981 35.184 139.057 35.784 ;
     RECT  137.704 37.2 139.057 38.664 ;
     RECT  137.704 40.944 139.057 40.968 ;
     RECT  137.704 42.096 139.057 42.12 ;
     RECT  137.704 43.824 139.057 43.848 ;
     RECT  137.704 44.976 139.057 45 ;
     RECT  137.704 46.416 139.057 50.472 ;
     RECT  139.021 52.224 139.057 54.84 ;
     RECT  139.021 56.544 139.057 58.584 ;
     RECT  137.704 59.712 139.057 60.6 ;
     RECT  137.704 62.016 139.057 66.072 ;
     RECT  139.021 68.352 139.057 81.96 ;
     RECT  137.981 83.088 139.057 87.432 ;
     RECT  139.057 42.096 139.093 45.288 ;
     RECT  139.057 46.416 139.093 87.432 ;
     RECT  139.057 1.44 139.597 40.968 ;
     RECT  139.093 42.096 139.597 87.432 ;
     RECT  139.597 1.44 140.281 87.432 ;
     RECT  140.281 1.152 140.316 1.176 ;
     RECT  140.281 1.176 140.364 1.44 ;
     RECT  140.281 1.44 140.316 1.464 ;
     RECT  140.281 1.464 140.364 1.728 ;
     RECT  140.281 1.728 140.316 1.752 ;
     RECT  140.281 1.752 140.364 2.016 ;
     RECT  140.281 2.016 140.316 2.04 ;
     RECT  140.281 2.04 140.364 2.304 ;
     RECT  140.281 2.304 140.316 2.328 ;
     RECT  140.281 2.328 140.364 2.592 ;
     RECT  140.281 2.592 140.316 2.616 ;
     RECT  140.281 2.616 140.364 2.88 ;
     RECT  140.281 2.88 140.316 2.904 ;
     RECT  140.281 2.904 140.364 3.168 ;
     RECT  140.281 3.168 140.316 3.192 ;
     RECT  140.281 3.192 140.364 3.456 ;
     RECT  140.281 3.456 140.316 3.48 ;
     RECT  140.281 3.48 140.364 3.744 ;
     RECT  140.281 3.744 140.316 3.768 ;
     RECT  140.281 3.768 140.364 4.032 ;
     RECT  140.281 4.032 140.316 4.056 ;
     RECT  140.281 4.056 140.364 4.32 ;
     RECT  140.281 4.32 140.316 4.344 ;
     RECT  140.281 4.344 140.364 4.608 ;
     RECT  140.281 4.608 140.316 4.632 ;
     RECT  140.281 4.632 140.364 4.896 ;
     RECT  140.281 4.896 140.316 4.92 ;
     RECT  140.281 4.92 140.364 5.184 ;
     RECT  140.281 5.184 140.316 5.208 ;
     RECT  140.281 5.208 140.364 5.472 ;
     RECT  140.281 5.472 140.316 5.496 ;
     RECT  140.281 5.496 140.364 5.76 ;
     RECT  140.281 5.76 140.316 5.784 ;
     RECT  140.281 5.784 140.364 6.048 ;
     RECT  140.281 6.048 140.316 6.072 ;
     RECT  140.281 6.072 140.364 6.336 ;
     RECT  140.281 6.336 140.316 6.36 ;
     RECT  140.281 6.36 140.364 6.624 ;
     RECT  140.281 6.624 140.316 6.648 ;
     RECT  140.281 6.648 140.364 6.912 ;
     RECT  140.281 6.912 140.316 6.936 ;
     RECT  140.281 6.936 140.364 7.2 ;
     RECT  140.281 7.2 140.316 7.224 ;
     RECT  140.281 7.224 140.364 7.488 ;
     RECT  140.281 7.488 140.316 7.512 ;
     RECT  140.281 7.512 140.364 7.776 ;
     RECT  140.281 7.776 140.316 7.8 ;
     RECT  140.281 7.8 140.364 8.064 ;
     RECT  140.281 8.064 140.316 8.088 ;
     RECT  140.281 8.088 140.364 8.352 ;
     RECT  140.281 8.352 140.316 8.376 ;
     RECT  140.281 8.376 140.364 8.64 ;
     RECT  140.281 8.64 140.316 8.664 ;
     RECT  140.281 8.664 140.364 8.928 ;
     RECT  140.281 8.928 140.316 8.952 ;
     RECT  140.281 8.952 140.364 9.216 ;
     RECT  140.281 9.216 140.316 9.24 ;
     RECT  140.281 9.24 140.364 9.504 ;
     RECT  140.281 9.504 140.316 9.528 ;
     RECT  140.281 9.528 140.364 9.792 ;
     RECT  140.281 9.792 140.316 9.816 ;
     RECT  140.281 9.816 140.364 10.08 ;
     RECT  140.281 10.08 140.316 10.104 ;
     RECT  140.281 10.104 140.364 10.368 ;
     RECT  140.281 10.368 140.316 10.392 ;
     RECT  140.281 10.392 140.364 10.656 ;
     RECT  140.281 10.656 140.316 10.68 ;
     RECT  140.281 10.68 140.364 10.944 ;
     RECT  140.281 10.944 140.316 10.968 ;
     RECT  140.281 10.968 140.364 11.232 ;
     RECT  140.281 11.232 140.316 11.256 ;
     RECT  140.281 11.256 140.364 11.52 ;
     RECT  140.281 11.52 140.316 11.544 ;
     RECT  140.281 11.544 140.364 11.808 ;
     RECT  140.281 11.808 140.316 11.832 ;
     RECT  140.281 11.832 140.364 12.096 ;
     RECT  140.281 12.096 140.316 12.12 ;
     RECT  140.281 12.12 140.364 12.384 ;
     RECT  140.281 12.384 140.316 12.408 ;
     RECT  140.281 12.408 140.364 12.672 ;
     RECT  140.281 12.672 140.316 12.696 ;
     RECT  140.281 12.696 140.364 12.96 ;
     RECT  140.281 12.96 140.316 12.984 ;
     RECT  140.281 12.984 140.364 13.248 ;
     RECT  140.281 13.248 140.316 13.272 ;
     RECT  140.281 13.272 140.364 13.536 ;
     RECT  140.281 13.536 140.316 13.56 ;
     RECT  140.281 13.56 140.364 13.824 ;
     RECT  140.281 13.824 140.316 13.848 ;
     RECT  140.281 13.848 140.364 14.112 ;
     RECT  140.281 14.112 140.316 14.136 ;
     RECT  140.281 14.136 140.364 14.4 ;
     RECT  140.281 14.4 140.316 14.424 ;
     RECT  140.281 14.424 140.364 14.688 ;
     RECT  140.281 14.688 140.316 14.712 ;
     RECT  140.281 14.712 140.364 14.976 ;
     RECT  140.281 14.976 140.316 15 ;
     RECT  140.281 15 140.364 15.264 ;
     RECT  140.281 15.264 140.316 15.288 ;
     RECT  140.281 15.288 140.364 15.552 ;
     RECT  140.281 15.552 140.316 15.576 ;
     RECT  140.281 15.576 140.364 15.84 ;
     RECT  140.281 15.84 140.316 15.864 ;
     RECT  140.281 15.864 140.364 16.128 ;
     RECT  140.281 16.128 140.316 16.152 ;
     RECT  140.281 16.152 140.364 16.416 ;
     RECT  140.281 16.416 140.316 16.44 ;
     RECT  140.281 16.44 140.364 16.704 ;
     RECT  140.281 16.704 140.316 16.728 ;
     RECT  140.281 16.728 140.364 16.992 ;
     RECT  140.281 16.992 140.316 17.016 ;
     RECT  140.281 17.016 140.364 17.28 ;
     RECT  140.281 17.28 140.316 17.304 ;
     RECT  140.281 17.304 140.364 17.568 ;
     RECT  140.281 17.568 140.316 17.592 ;
     RECT  140.281 17.592 140.364 17.856 ;
     RECT  140.281 17.856 140.316 17.88 ;
     RECT  140.281 17.88 140.364 18.144 ;
     RECT  140.281 18.144 140.316 18.168 ;
     RECT  140.281 18.168 140.364 18.432 ;
     RECT  140.281 18.432 140.316 18.456 ;
     RECT  140.281 18.456 140.364 18.72 ;
     RECT  140.281 18.72 140.316 18.744 ;
     RECT  140.281 18.744 140.364 19.008 ;
     RECT  140.281 19.008 140.316 19.032 ;
     RECT  140.281 19.032 140.364 19.296 ;
     RECT  140.281 19.296 140.316 19.32 ;
     RECT  140.281 19.32 140.364 19.584 ;
     RECT  140.281 19.584 140.316 19.608 ;
     RECT  140.281 19.608 140.364 19.872 ;
     RECT  140.281 19.872 140.316 19.896 ;
     RECT  140.281 19.896 140.364 20.16 ;
     RECT  140.281 20.16 140.316 20.184 ;
     RECT  140.281 20.184 140.364 20.448 ;
     RECT  140.281 20.448 140.316 20.472 ;
     RECT  140.281 20.472 140.364 20.736 ;
     RECT  140.281 20.736 140.316 20.76 ;
     RECT  140.281 20.76 140.364 21.024 ;
     RECT  140.281 21.024 140.316 21.048 ;
     RECT  140.281 21.048 140.364 21.312 ;
     RECT  140.281 21.312 140.316 21.336 ;
     RECT  140.281 21.336 140.364 21.6 ;
     RECT  140.281 21.6 140.316 21.624 ;
     RECT  140.281 21.624 140.364 21.888 ;
     RECT  140.281 21.888 140.316 21.912 ;
     RECT  140.281 21.912 140.364 22.176 ;
     RECT  140.281 22.176 140.316 22.2 ;
     RECT  140.281 22.2 140.364 22.464 ;
     RECT  140.281 22.464 140.316 22.488 ;
     RECT  140.281 22.488 140.364 22.752 ;
     RECT  140.281 22.752 140.316 22.776 ;
     RECT  140.281 22.776 140.364 23.04 ;
     RECT  140.281 23.04 140.316 23.064 ;
     RECT  140.281 23.064 140.364 23.328 ;
     RECT  140.281 23.328 140.316 23.352 ;
     RECT  140.281 23.352 140.364 23.616 ;
     RECT  140.281 23.616 140.316 23.64 ;
     RECT  140.281 23.64 140.364 23.904 ;
     RECT  140.281 23.904 140.316 23.928 ;
     RECT  140.281 23.928 140.364 24.192 ;
     RECT  140.281 24.192 140.316 24.216 ;
     RECT  140.281 24.216 140.364 24.48 ;
     RECT  140.281 24.48 140.316 24.504 ;
     RECT  140.281 24.504 140.364 24.816 ;
     RECT  140.281 24.816 140.316 24.84 ;
     RECT  140.281 24.84 140.364 25.104 ;
     RECT  140.281 25.104 140.316 25.128 ;
     RECT  140.281 25.128 140.364 25.392 ;
     RECT  140.281 25.392 140.316 25.416 ;
     RECT  140.281 25.416 140.364 25.68 ;
     RECT  140.281 25.68 140.316 25.704 ;
     RECT  140.281 25.704 140.364 25.968 ;
     RECT  140.281 25.968 140.316 25.992 ;
     RECT  140.281 25.992 140.364 26.256 ;
     RECT  140.281 26.256 140.316 26.28 ;
     RECT  140.281 26.28 140.364 26.544 ;
     RECT  140.281 26.544 140.316 26.568 ;
     RECT  140.281 26.568 140.364 26.832 ;
     RECT  140.281 26.832 140.316 26.856 ;
     RECT  140.281 26.856 140.364 27.12 ;
     RECT  140.281 27.12 140.316 27.144 ;
     RECT  140.281 27.144 140.364 27.408 ;
     RECT  140.281 27.408 140.316 27.432 ;
     RECT  140.281 27.432 140.364 27.696 ;
     RECT  140.281 27.696 140.316 27.72 ;
     RECT  140.281 27.72 140.364 27.984 ;
     RECT  140.281 27.984 140.316 28.008 ;
     RECT  140.281 28.008 140.364 28.272 ;
     RECT  140.281 28.272 140.316 28.296 ;
     RECT  140.281 28.296 140.364 28.56 ;
     RECT  140.281 28.56 140.316 28.584 ;
     RECT  140.281 28.584 140.364 28.848 ;
     RECT  140.281 28.848 140.316 28.872 ;
     RECT  140.281 28.872 140.364 29.136 ;
     RECT  140.281 29.136 140.316 29.16 ;
     RECT  140.281 29.16 140.364 29.424 ;
     RECT  140.281 29.424 140.316 29.448 ;
     RECT  140.281 29.448 140.364 29.712 ;
     RECT  140.281 29.712 140.316 29.736 ;
     RECT  140.281 29.736 140.364 30 ;
     RECT  140.281 30 140.316 30.024 ;
     RECT  140.281 30.024 140.364 30.288 ;
     RECT  140.281 30.288 140.316 30.312 ;
     RECT  140.281 30.312 140.364 30.576 ;
     RECT  140.281 30.576 140.316 30.6 ;
     RECT  140.281 30.6 140.364 30.864 ;
     RECT  140.281 30.864 140.316 30.888 ;
     RECT  140.281 30.888 140.364 31.152 ;
     RECT  140.281 31.152 140.316 31.176 ;
     RECT  140.281 31.176 140.364 31.44 ;
     RECT  140.281 31.44 140.316 31.464 ;
     RECT  140.281 31.464 140.364 31.728 ;
     RECT  140.281 31.728 140.316 31.752 ;
     RECT  140.281 31.752 140.364 32.016 ;
     RECT  140.281 32.016 140.316 32.04 ;
     RECT  140.281 32.04 140.364 32.304 ;
     RECT  140.281 32.304 140.316 32.328 ;
     RECT  140.281 32.328 140.364 32.592 ;
     RECT  140.281 32.592 140.316 32.616 ;
     RECT  140.281 32.616 140.364 32.88 ;
     RECT  140.281 32.88 140.316 32.904 ;
     RECT  140.281 32.904 140.364 33.168 ;
     RECT  140.281 33.168 140.316 33.192 ;
     RECT  140.281 33.192 140.364 33.456 ;
     RECT  140.281 33.456 140.316 33.48 ;
     RECT  140.281 33.48 140.364 33.744 ;
     RECT  140.281 33.744 140.316 33.768 ;
     RECT  140.281 33.768 140.364 34.032 ;
     RECT  140.281 34.032 140.316 34.056 ;
     RECT  140.281 34.056 140.364 34.32 ;
     RECT  140.281 34.32 140.316 34.344 ;
     RECT  140.281 34.344 140.364 34.608 ;
     RECT  140.281 34.608 140.316 34.632 ;
     RECT  140.281 34.632 140.364 34.896 ;
     RECT  140.281 34.896 140.316 34.92 ;
     RECT  140.281 34.92 140.364 35.184 ;
     RECT  140.281 35.184 140.316 35.208 ;
     RECT  140.281 35.208 140.364 35.472 ;
     RECT  140.281 35.472 140.316 35.496 ;
     RECT  140.281 35.496 140.364 35.76 ;
     RECT  140.281 35.76 140.316 35.784 ;
     RECT  140.281 35.784 140.364 36.048 ;
     RECT  140.281 36.048 140.316 36.072 ;
     RECT  140.281 36.072 140.364 36.336 ;
     RECT  140.281 36.336 140.316 36.36 ;
     RECT  140.281 36.36 140.364 36.624 ;
     RECT  140.281 36.624 140.316 36.648 ;
     RECT  140.281 36.648 140.364 36.912 ;
     RECT  140.281 36.912 140.316 36.936 ;
     RECT  140.281 36.936 140.364 37.2 ;
     RECT  140.281 37.2 140.316 37.224 ;
     RECT  140.281 37.224 140.364 37.488 ;
     RECT  140.281 37.488 140.316 37.512 ;
     RECT  140.281 37.512 140.364 37.776 ;
     RECT  140.281 37.776 140.316 37.8 ;
     RECT  140.281 37.8 140.364 38.064 ;
     RECT  140.281 38.064 140.316 38.088 ;
     RECT  140.281 38.088 140.364 38.352 ;
     RECT  140.281 38.352 140.316 38.376 ;
     RECT  140.281 38.376 140.364 38.64 ;
     RECT  140.281 38.64 140.316 38.664 ;
     RECT  140.281 38.664 140.364 38.928 ;
     RECT  140.281 38.928 140.316 38.952 ;
     RECT  140.281 38.952 140.364 39.216 ;
     RECT  140.281 39.216 140.316 39.24 ;
     RECT  140.281 39.24 140.364 39.504 ;
     RECT  140.281 39.504 140.316 39.528 ;
     RECT  140.281 39.528 140.364 39.792 ;
     RECT  140.281 39.792 140.316 39.816 ;
     RECT  140.281 39.816 140.364 40.08 ;
     RECT  140.281 40.08 140.316 40.104 ;
     RECT  140.281 40.104 140.364 40.368 ;
     RECT  140.281 40.368 140.316 40.392 ;
     RECT  140.281 40.392 140.364 40.656 ;
     RECT  140.281 40.656 140.316 40.68 ;
     RECT  140.281 40.68 140.364 40.944 ;
     RECT  140.281 40.944 140.316 40.968 ;
     RECT  140.281 40.968 140.364 41.232 ;
     RECT  140.281 41.232 140.316 41.256 ;
     RECT  140.281 41.256 140.364 41.52 ;
     RECT  140.281 41.52 140.316 41.544 ;
     RECT  140.281 41.544 140.364 41.808 ;
     RECT  140.281 41.808 140.316 41.832 ;
     RECT  140.281 41.832 140.364 42.096 ;
     RECT  140.281 42.096 140.316 42.12 ;
     RECT  140.281 42.12 140.364 42.384 ;
     RECT  140.281 42.384 140.316 42.408 ;
     RECT  140.281 42.408 140.364 42.672 ;
     RECT  140.281 42.672 140.316 42.696 ;
     RECT  140.281 42.696 140.364 42.96 ;
     RECT  140.281 42.96 140.316 42.984 ;
     RECT  140.281 42.984 140.364 43.248 ;
     RECT  140.281 43.248 140.316 43.272 ;
     RECT  140.281 43.272 140.364 43.536 ;
     RECT  140.281 43.536 140.316 43.56 ;
     RECT  140.281 43.56 140.364 43.824 ;
     RECT  140.281 43.824 140.316 43.848 ;
     RECT  140.281 43.848 140.364 44.112 ;
     RECT  140.281 44.112 140.316 44.136 ;
     RECT  140.281 44.136 140.364 44.4 ;
     RECT  140.281 44.4 140.316 44.424 ;
     RECT  140.281 44.424 140.364 44.688 ;
     RECT  140.281 44.688 140.316 44.712 ;
     RECT  140.281 44.712 140.364 44.976 ;
     RECT  140.281 44.976 140.316 45 ;
     RECT  140.281 45 140.364 45.264 ;
     RECT  140.281 45.264 140.316 45.288 ;
     RECT  140.281 45.288 140.364 45.552 ;
     RECT  140.281 45.552 140.316 45.576 ;
     RECT  140.281 45.576 140.364 45.84 ;
     RECT  140.281 45.84 140.316 45.864 ;
     RECT  140.281 45.864 140.364 46.128 ;
     RECT  140.281 46.128 140.316 46.152 ;
     RECT  140.281 46.152 140.364 46.416 ;
     RECT  140.281 46.416 140.316 46.44 ;
     RECT  140.281 46.44 140.364 46.704 ;
     RECT  140.281 46.704 140.316 46.728 ;
     RECT  140.281 46.728 140.364 46.992 ;
     RECT  140.281 46.992 140.316 47.016 ;
     RECT  140.281 47.016 140.364 47.28 ;
     RECT  140.281 47.28 140.316 47.304 ;
     RECT  140.281 47.304 140.364 47.568 ;
     RECT  140.281 47.568 140.316 47.592 ;
     RECT  140.281 47.592 140.364 47.856 ;
     RECT  140.281 47.856 140.316 47.88 ;
     RECT  140.281 47.88 140.364 48.144 ;
     RECT  140.281 48.144 140.316 48.168 ;
     RECT  140.281 48.168 140.364 48.432 ;
     RECT  140.281 48.432 140.316 48.456 ;
     RECT  140.281 48.456 140.364 48.72 ;
     RECT  140.281 48.72 140.316 48.744 ;
     RECT  140.281 48.744 140.364 49.008 ;
     RECT  140.281 49.008 140.316 49.032 ;
     RECT  140.281 49.032 140.364 49.296 ;
     RECT  140.281 49.296 140.316 49.32 ;
     RECT  140.281 49.32 140.364 49.584 ;
     RECT  140.281 49.584 140.316 49.608 ;
     RECT  140.281 49.608 140.364 49.872 ;
     RECT  140.281 49.872 140.316 49.896 ;
     RECT  140.281 49.896 140.364 50.16 ;
     RECT  140.281 50.16 140.316 50.184 ;
     RECT  140.281 50.184 140.364 50.448 ;
     RECT  140.281 50.448 140.316 50.472 ;
     RECT  140.281 50.472 140.364 50.784 ;
     RECT  140.281 50.784 140.316 50.808 ;
     RECT  140.281 50.808 140.364 51.072 ;
     RECT  140.281 51.072 140.316 51.096 ;
     RECT  140.281 51.096 140.364 51.36 ;
     RECT  140.281 51.36 140.316 51.384 ;
     RECT  140.281 51.384 140.364 51.648 ;
     RECT  140.281 51.648 140.316 51.672 ;
     RECT  140.281 51.672 140.364 51.936 ;
     RECT  140.281 51.936 140.316 51.96 ;
     RECT  140.281 51.96 140.364 52.224 ;
     RECT  140.281 52.224 140.316 52.248 ;
     RECT  140.281 52.248 140.364 52.512 ;
     RECT  140.281 52.512 140.316 52.536 ;
     RECT  140.281 52.536 140.364 52.8 ;
     RECT  140.281 52.8 140.316 52.824 ;
     RECT  140.281 52.824 140.364 53.088 ;
     RECT  140.281 53.088 140.316 53.112 ;
     RECT  140.281 53.112 140.364 53.376 ;
     RECT  140.281 53.376 140.316 53.4 ;
     RECT  140.281 53.4 140.364 53.664 ;
     RECT  140.281 53.664 140.316 53.688 ;
     RECT  140.281 53.688 140.364 53.952 ;
     RECT  140.281 53.952 140.316 53.976 ;
     RECT  140.281 53.976 140.364 54.24 ;
     RECT  140.281 54.24 140.316 54.264 ;
     RECT  140.281 54.264 140.364 54.528 ;
     RECT  140.281 54.528 140.316 54.552 ;
     RECT  140.281 54.552 140.364 54.816 ;
     RECT  140.281 54.816 140.316 54.84 ;
     RECT  140.281 54.84 140.364 55.104 ;
     RECT  140.281 55.104 140.316 55.128 ;
     RECT  140.281 55.128 140.364 55.392 ;
     RECT  140.281 55.392 140.316 55.416 ;
     RECT  140.281 55.416 140.364 55.68 ;
     RECT  140.281 55.68 140.316 55.704 ;
     RECT  140.281 55.704 140.364 55.968 ;
     RECT  140.281 55.968 140.316 55.992 ;
     RECT  140.281 55.992 140.364 56.256 ;
     RECT  140.281 56.256 140.316 56.28 ;
     RECT  140.281 56.28 140.364 56.544 ;
     RECT  140.281 56.544 140.316 56.568 ;
     RECT  140.281 56.568 140.364 56.832 ;
     RECT  140.281 56.832 140.316 56.856 ;
     RECT  140.281 56.856 140.364 57.12 ;
     RECT  140.281 57.12 140.316 57.144 ;
     RECT  140.281 57.144 140.364 57.408 ;
     RECT  140.281 57.408 140.316 57.432 ;
     RECT  140.281 57.432 140.364 57.696 ;
     RECT  140.281 57.696 140.316 57.72 ;
     RECT  140.281 57.72 140.364 57.984 ;
     RECT  140.281 57.984 140.316 58.008 ;
     RECT  140.281 58.008 140.364 58.272 ;
     RECT  140.281 58.272 140.316 58.296 ;
     RECT  140.281 58.296 140.364 58.56 ;
     RECT  140.281 58.56 140.316 58.584 ;
     RECT  140.281 58.584 140.364 58.848 ;
     RECT  140.281 58.848 140.316 58.872 ;
     RECT  140.281 58.872 140.364 59.136 ;
     RECT  140.281 59.136 140.316 59.16 ;
     RECT  140.281 59.16 140.364 59.424 ;
     RECT  140.281 59.424 140.316 59.448 ;
     RECT  140.281 59.448 140.364 59.712 ;
     RECT  140.281 59.712 140.316 59.736 ;
     RECT  140.281 59.736 140.364 60 ;
     RECT  140.281 60 140.316 60.024 ;
     RECT  140.281 60.024 140.364 60.288 ;
     RECT  140.281 60.288 140.316 60.312 ;
     RECT  140.281 60.312 140.364 60.576 ;
     RECT  140.281 60.576 140.316 60.6 ;
     RECT  140.281 60.6 140.364 60.864 ;
     RECT  140.281 60.864 140.316 60.888 ;
     RECT  140.281 60.888 140.364 61.152 ;
     RECT  140.281 61.152 140.316 61.176 ;
     RECT  140.281 61.176 140.364 61.44 ;
     RECT  140.281 61.44 140.316 61.464 ;
     RECT  140.281 61.464 140.364 61.728 ;
     RECT  140.281 61.728 140.316 61.752 ;
     RECT  140.281 61.752 140.364 62.016 ;
     RECT  140.281 62.016 140.316 62.04 ;
     RECT  140.281 62.04 140.364 62.304 ;
     RECT  140.281 62.304 140.316 62.328 ;
     RECT  140.281 62.328 140.364 62.592 ;
     RECT  140.281 62.592 140.316 62.616 ;
     RECT  140.281 62.616 140.364 62.88 ;
     RECT  140.281 62.88 140.316 62.904 ;
     RECT  140.281 62.904 140.364 63.168 ;
     RECT  140.281 63.168 140.316 63.192 ;
     RECT  140.281 63.192 140.364 63.456 ;
     RECT  140.281 63.456 140.316 63.48 ;
     RECT  140.281 63.48 140.364 63.744 ;
     RECT  140.281 63.744 140.316 63.768 ;
     RECT  140.281 63.768 140.364 64.032 ;
     RECT  140.281 64.032 140.316 64.056 ;
     RECT  140.281 64.056 140.364 64.32 ;
     RECT  140.281 64.32 140.316 64.344 ;
     RECT  140.281 64.344 140.364 64.608 ;
     RECT  140.281 64.608 140.316 64.632 ;
     RECT  140.281 64.632 140.364 64.896 ;
     RECT  140.281 64.896 140.316 64.92 ;
     RECT  140.281 64.92 140.364 65.184 ;
     RECT  140.281 65.184 140.316 65.208 ;
     RECT  140.281 65.208 140.364 65.472 ;
     RECT  140.281 65.472 140.316 65.496 ;
     RECT  140.281 65.496 140.364 65.76 ;
     RECT  140.281 65.76 140.316 65.784 ;
     RECT  140.281 65.784 140.364 66.048 ;
     RECT  140.281 66.048 140.316 66.072 ;
     RECT  140.281 66.072 140.364 66.336 ;
     RECT  140.281 66.336 140.316 66.36 ;
     RECT  140.281 66.36 140.364 66.624 ;
     RECT  140.281 66.624 140.316 66.648 ;
     RECT  140.281 66.648 140.364 66.912 ;
     RECT  140.281 66.912 140.316 66.936 ;
     RECT  140.281 66.936 140.364 67.2 ;
     RECT  140.281 67.2 140.316 67.224 ;
     RECT  140.281 67.224 140.364 67.488 ;
     RECT  140.281 67.488 140.316 67.512 ;
     RECT  140.281 67.512 140.364 67.776 ;
     RECT  140.281 67.776 140.316 67.8 ;
     RECT  140.281 67.8 140.364 68.064 ;
     RECT  140.281 68.064 140.316 68.088 ;
     RECT  140.281 68.088 140.364 68.352 ;
     RECT  140.281 68.352 140.316 68.376 ;
     RECT  140.281 68.376 140.364 68.64 ;
     RECT  140.281 68.64 140.316 68.664 ;
     RECT  140.281 68.664 140.364 68.928 ;
     RECT  140.281 68.928 140.316 68.952 ;
     RECT  140.281 68.952 140.364 69.216 ;
     RECT  140.281 69.216 140.316 69.24 ;
     RECT  140.281 69.24 140.364 69.504 ;
     RECT  140.281 69.504 140.316 69.528 ;
     RECT  140.281 69.528 140.364 69.792 ;
     RECT  140.281 69.792 140.316 69.816 ;
     RECT  140.281 69.816 140.364 70.08 ;
     RECT  140.281 70.08 140.316 70.104 ;
     RECT  140.281 70.104 140.364 70.368 ;
     RECT  140.281 70.368 140.316 70.392 ;
     RECT  140.281 70.392 140.364 70.656 ;
     RECT  140.281 70.656 140.316 70.68 ;
     RECT  140.281 70.68 140.364 70.944 ;
     RECT  140.281 70.944 140.316 70.968 ;
     RECT  140.281 70.968 140.364 71.232 ;
     RECT  140.281 71.232 140.316 71.256 ;
     RECT  140.281 71.256 140.364 71.52 ;
     RECT  140.281 71.52 140.316 71.544 ;
     RECT  140.281 71.544 140.364 71.808 ;
     RECT  140.281 71.808 140.316 71.832 ;
     RECT  140.281 71.832 140.364 72.096 ;
     RECT  140.281 72.096 140.316 72.12 ;
     RECT  140.281 72.12 140.364 72.384 ;
     RECT  140.281 72.384 140.316 72.408 ;
     RECT  140.281 72.408 140.364 72.672 ;
     RECT  140.281 72.672 140.316 72.696 ;
     RECT  140.281 72.696 140.364 72.96 ;
     RECT  140.281 72.96 140.316 72.984 ;
     RECT  140.281 72.984 140.364 73.248 ;
     RECT  140.281 73.248 140.316 73.272 ;
     RECT  140.281 73.272 140.364 73.536 ;
     RECT  140.281 73.536 140.316 73.56 ;
     RECT  140.281 73.56 140.364 73.824 ;
     RECT  140.281 73.824 140.316 73.848 ;
     RECT  140.281 73.848 140.364 74.112 ;
     RECT  140.281 74.112 140.316 74.136 ;
     RECT  140.281 74.136 140.364 74.4 ;
     RECT  140.281 74.4 140.316 74.424 ;
     RECT  140.281 74.424 140.364 74.688 ;
     RECT  140.281 74.688 140.316 74.712 ;
     RECT  140.281 74.712 140.364 74.976 ;
     RECT  140.281 74.976 140.316 75 ;
     RECT  140.281 75 140.364 75.264 ;
     RECT  140.281 75.264 140.316 75.288 ;
     RECT  140.281 75.288 140.364 75.552 ;
     RECT  140.281 75.552 140.316 75.576 ;
     RECT  140.281 75.576 140.364 75.84 ;
     RECT  140.281 75.84 140.316 75.864 ;
     RECT  140.281 75.864 140.364 76.128 ;
     RECT  140.281 76.128 140.316 76.152 ;
     RECT  140.281 76.152 140.364 76.416 ;
     RECT  140.281 76.416 140.316 76.44 ;
     RECT  140.281 76.44 140.364 76.752 ;
     RECT  140.281 76.752 140.316 76.776 ;
     RECT  140.281 76.776 140.364 77.04 ;
     RECT  140.281 77.04 140.316 77.064 ;
     RECT  140.281 77.064 140.364 77.328 ;
     RECT  140.281 77.328 140.316 77.352 ;
     RECT  140.281 77.352 140.364 77.616 ;
     RECT  140.281 77.616 140.316 77.64 ;
     RECT  140.281 77.64 140.364 77.904 ;
     RECT  140.281 77.904 140.316 77.928 ;
     RECT  140.281 77.928 140.364 78.192 ;
     RECT  140.281 78.192 140.316 78.216 ;
     RECT  140.281 78.216 140.364 78.48 ;
     RECT  140.281 78.48 140.316 78.504 ;
     RECT  140.281 78.504 140.364 78.768 ;
     RECT  140.281 78.768 140.316 78.792 ;
     RECT  140.281 78.792 140.364 79.056 ;
     RECT  140.281 79.056 140.316 79.08 ;
     RECT  140.281 79.08 140.364 79.344 ;
     RECT  140.281 79.344 140.316 79.368 ;
     RECT  140.281 79.368 140.364 79.632 ;
     RECT  140.281 79.632 140.316 79.656 ;
     RECT  140.281 79.656 140.364 79.92 ;
     RECT  140.281 79.92 140.316 79.944 ;
     RECT  140.281 79.944 140.364 80.208 ;
     RECT  140.281 80.208 140.316 80.232 ;
     RECT  140.281 80.232 140.364 80.496 ;
     RECT  140.281 80.496 140.316 80.52 ;
     RECT  140.281 80.52 140.364 80.784 ;
     RECT  140.281 80.784 140.316 80.808 ;
     RECT  140.281 80.808 140.364 81.072 ;
     RECT  140.281 81.072 140.316 81.096 ;
     RECT  140.281 81.096 140.364 81.36 ;
     RECT  140.281 81.36 140.316 81.384 ;
     RECT  140.281 81.384 140.364 81.648 ;
     RECT  140.281 81.648 140.316 81.672 ;
     RECT  140.281 81.672 140.364 81.936 ;
     RECT  140.281 81.936 140.316 81.96 ;
     RECT  140.281 81.96 140.364 82.224 ;
     RECT  140.281 82.224 140.316 82.248 ;
     RECT  140.281 82.248 140.364 82.512 ;
     RECT  140.281 82.512 140.316 82.536 ;
     RECT  140.281 82.536 140.364 82.8 ;
     RECT  140.281 82.8 140.316 82.824 ;
     RECT  140.281 82.824 140.364 83.088 ;
     RECT  140.281 83.088 140.316 83.112 ;
     RECT  140.281 83.112 140.364 83.376 ;
     RECT  140.281 83.376 140.316 83.4 ;
     RECT  140.281 83.4 140.364 83.664 ;
     RECT  140.281 83.664 140.316 83.688 ;
     RECT  140.281 83.688 140.364 83.952 ;
     RECT  140.281 83.952 140.316 83.976 ;
     RECT  140.281 83.976 140.364 84.24 ;
     RECT  140.281 84.24 140.316 84.264 ;
     RECT  140.281 84.264 140.364 84.528 ;
     RECT  140.281 84.528 140.316 84.552 ;
     RECT  140.281 84.552 140.364 84.816 ;
     RECT  140.281 84.816 140.316 84.84 ;
     RECT  140.281 84.84 140.364 85.104 ;
     RECT  140.281 85.104 140.316 85.128 ;
     RECT  140.281 85.128 140.364 85.392 ;
     RECT  140.281 85.392 140.316 85.416 ;
     RECT  140.281 85.416 140.364 85.68 ;
     RECT  140.281 85.68 140.316 85.704 ;
     RECT  140.281 85.704 140.364 85.968 ;
     RECT  140.281 85.968 140.316 85.992 ;
     RECT  140.281 85.992 140.364 86.256 ;
     RECT  140.281 86.256 140.316 86.28 ;
     RECT  140.281 86.28 140.364 86.544 ;
     RECT  140.281 86.544 140.316 86.568 ;
     RECT  140.281 86.568 140.364 86.832 ;
     RECT  140.281 86.832 140.316 86.856 ;
     RECT  140.281 86.856 140.364 87.12 ;
     RECT  140.281 87.12 140.316 87.144 ;
     RECT  140.281 87.144 140.364 87.408 ;
     RECT  140.281 87.408 140.316 87.432 ;
    LAYER M5 ;
     RECT  2.4 2.137 2.52 2.151 ;
     RECT  7.8 2.137 7.92 2.151 ;
     RECT  13.2 2.137 13.32 2.151 ;
     RECT  18.6 2.137 18.72 2.151 ;
     RECT  24 2.137 24.12 2.151 ;
     RECT  29.4 2.137 29.52 2.151 ;
     RECT  34.8 2.137 34.92 2.151 ;
     RECT  40.2 2.137 40.32 2.151 ;
     RECT  45.6 2.137 45.72 2.151 ;
     RECT  51 2.137 51.12 2.151 ;
     RECT  56.4 2.137 56.52 2.151 ;
     RECT  61.8 2.137 61.92 2.151 ;
     RECT  67.2 2.137 67.32 2.151 ;
     RECT  72.6 2.137 72.72 2.151 ;
     RECT  78 2.137 78.12 2.151 ;
     RECT  83.4 2.137 83.52 2.151 ;
     RECT  88.8 2.137 88.92 2.151 ;
     RECT  94.2 2.137 94.32 2.151 ;
     RECT  99.6 2.137 99.72 2.151 ;
     RECT  105 2.137 105.12 2.151 ;
     RECT  110.4 2.137 110.52 2.151 ;
     RECT  115.8 2.137 115.92 2.151 ;
     RECT  121.2 2.137 121.32 2.151 ;
     RECT  126.6 2.137 126.72 2.151 ;
     RECT  132 2.137 132.12 2.151 ;
     RECT  137.4 2.137 137.52 2.151 ;
     RECT  18.6 2.151 18.912 2.485 ;
     RECT  132 2.151 132.312 2.773 ;
     RECT  134.88 2.821 134.904 3.349 ;
     RECT  21.888 3.301 21.912 3.541 ;
     RECT  17.76 2.485 18.912 3.637 ;
     RECT  134.88 3.349 134.952 4.019 ;
     RECT  136.176 3.301 136.2 4.067 ;
     RECT  16.608 4.117 16.632 4.405 ;
     RECT  16.608 4.405 16.776 4.453 ;
     RECT  134.88 4.019 134.904 4.549 ;
     RECT  5.808 4.405 5.832 5.029 ;
     RECT  7.8 2.151 8.112 5.077 ;
     RECT  131.904 2.773 132.312 5.171 ;
     RECT  134.544 4.549 134.904 5.171 ;
     RECT  21.36 3.541 21.912 5.509 ;
     RECT  5.088 5.029 5.832 5.747 ;
     RECT  20.88 5.509 21.912 5.797 ;
     RECT  14.592 3.301 14.616 5.989 ;
     RECT  14.592 5.989 14.808 6.035 ;
     RECT  6.816 5.077 8.112 6.419 ;
     RECT  14.784 6.035 14.808 7.427 ;
     RECT  20.88 5.797 22.056 7.621 ;
     RECT  7.8 6.419 8.112 7.909 ;
     RECT  16.464 4.453 16.776 8.965 ;
     RECT  17.76 3.637 19.752 8.965 ;
     RECT  133.296 7.909 133.32 9.155 ;
     RECT  7.68 7.909 8.112 9.251 ;
     RECT  3.984 8.533 4.008 9.491 ;
     RECT  136.272 7.381 136.296 9.539 ;
     RECT  16.464 8.965 19.752 10.597 ;
     RECT  5.808 5.747 5.832 10.837 ;
     RECT  5.808 10.837 6.024 10.883 ;
     RECT  14.976 11.653 15 11.701 ;
     RECT  7.8 9.251 8.112 11.893 ;
     RECT  14.976 11.701 15.288 11.941 ;
     RECT  13.2 2.151 13.512 12.325 ;
     RECT  12.576 12.325 13.512 12.469 ;
     RECT  14.544 11.941 15.288 12.469 ;
     RECT  7.68 11.893 8.112 12.515 ;
     RECT  134.88 5.171 134.904 14.101 ;
     RECT  134.64 14.101 134.904 14.147 ;
     RECT  7.8 12.515 8.112 14.197 ;
     RECT  114.624 3.829 114.648 14.291 ;
     RECT  20.88 7.621 22.152 14.389 ;
     RECT  16.368 10.597 19.752 14.629 ;
     RECT  20.88 14.389 22.776 14.629 ;
     RECT  6 10.883 6.024 14.773 ;
     RECT  6 14.773 6.408 14.867 ;
     RECT  16.368 14.629 22.776 14.867 ;
     RECT  7.8 14.197 8.232 14.963 ;
     RECT  12.576 12.469 15.288 14.963 ;
     RECT  6.24 14.867 6.408 15.349 ;
     RECT  7.8 14.963 8.112 15.349 ;
     RECT  4.56 14.773 4.584 15.491 ;
     RECT  13.2 14.963 15.288 17.941 ;
     RECT  16.368 14.867 22.152 17.941 ;
     RECT  133.344 16.357 133.368 18.037 ;
     RECT  133.344 18.037 133.464 18.179 ;
     RECT  6.24 15.349 8.112 18.181 ;
     RECT  114.192 15.157 114.216 18.851 ;
     RECT  13.2 17.941 22.152 19.237 ;
     RECT  133.344 18.179 133.368 19.379 ;
     RECT  5.904 18.181 8.112 19.667 ;
     RECT  7.8 19.667 8.112 21.061 ;
     RECT  5.904 19.667 6.792 21.155 ;
     RECT  11.376 20.437 11.4 21.155 ;
     RECT  13.2 19.237 22.488 21.205 ;
     RECT  13.2 21.205 22.584 21.347 ;
     RECT  34.8 2.151 35.112 21.349 ;
     RECT  115.8 2.151 116.112 21.445 ;
     RECT  117.36 14.197 117.384 21.445 ;
     RECT  34.8 21.349 35.208 21.539 ;
     RECT  10.272 20.917 10.296 21.589 ;
     RECT  10.272 21.589 10.536 21.635 ;
     RECT  99.6 2.151 99.912 21.637 ;
     RECT  5.904 21.155 5.928 22.117 ;
     RECT  7.8 21.061 8.76 22.117 ;
     RECT  132 5.171 132.312 22.117 ;
     RECT  4.416 22.693 4.44 22.741 ;
     RECT  5.904 22.117 8.76 22.835 ;
     RECT  5.904 22.835 8.112 22.931 ;
     RECT  4.224 22.741 4.44 23.027 ;
     RECT  5.904 22.931 6.744 23.027 ;
     RECT  136.032 22.021 136.056 23.317 ;
     RECT  4.416 23.027 4.44 23.555 ;
     RECT  115.8 21.445 117.384 23.603 ;
     RECT  13.2 21.347 22.488 23.651 ;
     RECT  7.8 22.931 8.112 23.893 ;
     RECT  5.904 23.027 5.928 24.277 ;
     RECT  5.76 24.277 5.928 24.323 ;
     RECT  132 22.117 132.888 24.469 ;
     RECT  7.104 23.893 8.112 24.659 ;
     RECT  13.2 23.651 22.2 24.661 ;
     RECT  13.2 24.661 22.392 24.947 ;
     RECT  132 24.469 133.32 25.187 ;
     RECT  10.512 21.635 10.536 25.715 ;
     RECT  10.848 26.197 10.872 26.339 ;
     RECT  135.744 23.317 136.056 26.437 ;
     RECT  134.64 14.147 134.664 26.533 ;
     RECT  135.744 26.437 136.392 26.533 ;
     RECT  13.2 24.947 22.152 26.869 ;
     RECT  13.2 26.869 22.392 27.059 ;
     RECT  7.8 24.659 8.112 27.301 ;
     RECT  117.36 23.603 117.384 27.349 ;
     RECT  117.36 27.349 117.48 27.539 ;
     RECT  132 25.187 132.312 27.877 ;
     RECT  133.296 25.187 133.32 27.877 ;
     RECT  134.64 26.533 136.392 27.877 ;
     RECT  137.4 2.151 137.712 27.877 ;
     RECT  7.8 27.301 9.096 28.019 ;
     RECT  134.64 27.877 137.712 28.547 ;
     RECT  132 27.877 133.32 28.691 ;
     RECT  117.36 27.539 117.384 29.221 ;
     RECT  117.36 29.221 117.432 29.411 ;
     RECT  9.744 28.453 9.768 29.699 ;
     RECT  135.744 28.547 137.712 30.661 ;
     RECT  134.64 28.547 134.664 30.757 ;
     RECT  135.648 30.661 137.712 30.757 ;
     RECT  132 28.691 132.312 30.805 ;
     RECT  133.296 28.691 133.32 30.805 ;
     RECT  134.496 30.757 137.712 30.805 ;
     RECT  5.76 24.323 5.784 31.045 ;
     RECT  5.76 31.045 6.12 31.091 ;
     RECT  13.2 27.059 22.152 31.237 ;
     RECT  6.096 31.091 6.12 31.285 ;
     RECT  132 30.805 133.32 31.285 ;
     RECT  134.4 30.805 137.712 31.285 ;
     RECT  6.096 31.285 6.648 31.861 ;
     RECT  7.8 28.019 8.112 31.861 ;
     RECT  12.912 31.237 22.152 32.053 ;
     RECT  117.36 29.411 117.384 32.197 ;
     RECT  12.912 32.053 22.392 32.243 ;
     RECT  131.616 31.285 137.712 32.243 ;
     RECT  6.096 31.861 8.112 32.485 ;
     RECT  9.168 31.861 9.192 32.485 ;
     RECT  117.36 32.197 117.432 32.485 ;
     RECT  6.096 32.485 9.192 32.531 ;
     RECT  134.64 32.243 137.712 32.531 ;
     RECT  11.52 31.285 11.544 32.581 ;
     RECT  12.912 32.243 22.152 32.581 ;
     RECT  6.096 32.531 9.096 33.059 ;
     RECT  117.36 32.485 117.48 33.109 ;
     RECT  117.36 33.109 117.576 33.347 ;
     RECT  132 32.243 133.32 33.395 ;
     RECT  121.2 2.151 121.512 33.589 ;
     RECT  7.8 33.059 9.096 33.635 ;
     RECT  11.52 32.581 22.152 33.635 ;
     RECT  134.64 32.531 134.712 34.069 ;
     RECT  135.744 32.531 137.712 34.069 ;
     RECT  133.296 33.395 133.32 34.117 ;
     RECT  133.296 34.117 133.464 34.165 ;
     RECT  3.936 34.741 3.96 34.837 ;
     RECT  3.696 34.837 3.96 34.883 ;
     RECT  133.296 34.165 133.656 34.883 ;
     RECT  134.64 34.069 137.712 34.979 ;
     RECT  3.696 34.883 3.72 35.459 ;
     RECT  6.096 33.059 6.12 35.699 ;
     RECT  133.296 34.883 133.464 35.699 ;
     RECT  134.64 34.979 134.76 36.515 ;
     RECT  4.224 36.469 4.248 37.091 ;
     RECT  117.36 33.347 117.384 37.187 ;
     RECT  134.64 36.515 134.712 37.573 ;
     RECT  135.792 34.979 137.712 37.573 ;
     RECT  6.048 35.845 6.072 37.621 ;
     RECT  7.8 33.635 8.112 37.621 ;
     RECT  6.048 37.621 8.112 38.147 ;
     RECT  134.544 37.573 137.712 38.387 ;
     RECT  2.4 2.151 2.712 39.301 ;
     RECT  117.36 39.253 117.384 39.635 ;
     RECT  132 33.395 132.312 39.781 ;
     RECT  133.296 35.699 133.32 39.781 ;
     RECT  7.8 38.147 8.112 40.021 ;
     RECT  117.408 40.069 117.432 40.259 ;
     RECT  13.2 33.635 22.152 40.549 ;
     RECT  7.8 40.021 8.76 40.595 ;
     RECT  11.52 33.635 11.544 40.597 ;
     RECT  13.2 40.549 22.344 40.739 ;
     RECT  134.64 38.387 137.712 41.075 ;
     RECT  4.656 40.261 4.68 41.363 ;
     RECT  132 39.781 133.32 41.557 ;
     RECT  11.52 40.597 11.592 41.605 ;
     RECT  11.52 41.605 11.832 41.651 ;
     RECT  132 41.557 133.512 41.939 ;
     RECT  2.4 39.301 3.336 42.803 ;
     RECT  6.048 38.147 6.072 42.803 ;
     RECT  132 41.939 133.32 42.851 ;
     RECT  7.8 40.595 8.112 43.285 ;
     RECT  132 42.851 132.312 43.285 ;
     RECT  11.808 41.651 11.832 43.573 ;
     RECT  7.8 43.285 8.664 44.051 ;
     RECT  13.2 40.739 22.152 44.533 ;
     RECT  13.2 44.533 22.344 44.723 ;
     RECT  2.4 42.803 2.712 44.965 ;
     RECT  6.24 43.765 6.264 45.059 ;
     RECT  10.848 43.573 11.832 45.059 ;
     RECT  10.848 45.059 10.872 45.155 ;
     RECT  131.904 43.285 132.312 45.637 ;
     RECT  2.4 44.965 3.576 45.731 ;
     RECT  13.2 44.723 22.152 45.733 ;
     RECT  13.2 45.733 22.296 45.877 ;
     RECT  7.8 44.051 8.112 46.021 ;
     RECT  12.144 45.109 12.168 46.067 ;
     RECT  13.2 45.877 22.392 46.067 ;
     RECT  131.664 45.637 132.312 46.787 ;
     RECT  5.568 46.693 5.592 47.269 ;
     RECT  5.568 47.269 5.736 47.845 ;
     RECT  6.912 46.021 8.112 47.845 ;
     RECT  5.568 47.845 8.112 48.227 ;
     RECT  13.2 46.067 22.152 48.229 ;
     RECT  5.568 48.227 5.736 48.275 ;
     RECT  13.2 48.229 22.248 48.467 ;
     RECT  3.696 47.461 3.72 48.515 ;
     RECT  6.912 48.227 8.112 48.997 ;
     RECT  6.912 48.997 9.048 49.043 ;
     RECT  13.2 48.467 22.152 49.861 ;
     RECT  13.2 49.861 22.344 50.051 ;
     RECT  7.8 49.043 9.048 50.771 ;
     RECT  5.568 48.275 5.592 50.819 ;
     RECT  134.688 41.075 137.712 51.301 ;
     RECT  9.744 50.821 9.768 52.163 ;
     RECT  13.2 50.051 22.2 52.357 ;
     RECT  134.544 51.301 137.712 52.451 ;
     RECT  7.8 50.771 8.112 52.981 ;
     RECT  132 46.787 132.312 52.981 ;
     RECT  133.296 42.851 133.32 52.981 ;
     RECT  7.344 52.981 8.112 53.603 ;
     RECT  12.24 52.357 22.2 53.845 ;
     RECT  12.24 53.845 22.392 53.939 ;
     RECT  13.2 53.939 22.392 54.035 ;
     RECT  4.56 52.693 4.584 54.371 ;
     RECT  7.8 53.603 8.112 55.237 ;
     RECT  12.096 54.661 12.12 55.283 ;
     RECT  13.2 54.035 22.2 55.667 ;
     RECT  7.8 55.237 8.232 56.003 ;
     RECT  132 52.981 133.32 56.291 ;
     RECT  5.76 55.813 5.784 56.435 ;
     RECT  9.792 52.405 9.816 56.725 ;
     RECT  9.696 56.725 9.816 56.771 ;
     RECT  7.8 56.003 8.112 56.821 ;
     RECT  9.696 56.771 9.72 56.867 ;
     RECT  13.2 55.667 21.096 57.011 ;
     RECT  13.2 57.011 20.712 57.059 ;
     RECT  4.464 56.869 4.488 58.163 ;
     RECT  13.2 57.059 20.52 58.355 ;
     RECT  20.016 58.355 20.52 59.027 ;
     RECT  20.016 59.027 20.28 59.123 ;
     RECT  20.016 59.123 20.232 59.411 ;
     RECT  5.664 58.693 5.688 59.797 ;
     RECT  134.64 52.451 137.712 59.797 ;
     RECT  5.664 59.797 5.88 59.843 ;
     RECT  11.424 59.221 11.448 60.467 ;
     RECT  5.856 59.843 5.88 60.851 ;
     RECT  13.2 58.355 18.912 61.333 ;
     RECT  10.32 61.189 10.344 61.525 ;
     RECT  13.056 61.333 18.912 62.195 ;
     RECT  10.32 61.525 10.824 62.291 ;
     RECT  13.2 62.195 18.912 62.293 ;
     RECT  20.016 59.411 20.04 62.293 ;
     RECT  5.088 61.525 5.112 62.339 ;
     RECT  10.32 62.291 10.344 62.435 ;
     RECT  13.2 62.293 20.04 62.483 ;
     RECT  20.016 62.483 20.04 62.629 ;
     RECT  134.544 59.797 137.712 63.299 ;
     RECT  20.016 62.629 20.136 63.781 ;
     RECT  133.296 56.291 133.32 64.213 ;
     RECT  7.68 56.821 8.112 64.309 ;
     RECT  13.2 62.483 18.912 64.403 ;
     RECT  136.272 63.299 137.712 64.451 ;
     RECT  7.488 64.309 8.112 65.027 ;
     RECT  20.016 63.781 20.328 65.027 ;
     RECT  132 56.291 132.312 65.509 ;
     RECT  133.296 64.213 133.368 65.555 ;
     RECT  16.176 64.403 18.912 65.843 ;
     RECT  134.544 63.299 135.288 65.987 ;
     RECT  7.68 65.027 8.112 66.085 ;
     RECT  134.64 65.987 135.288 66.131 ;
     RECT  20.016 65.027 20.136 66.179 ;
     RECT  133.296 65.555 133.32 66.179 ;
     RECT  110.4 2.151 110.712 66.181 ;
     RECT  16.416 65.843 18.912 66.275 ;
     RECT  13.2 64.403 15.144 66.515 ;
     RECT  20.016 66.179 20.04 66.515 ;
     RECT  6.528 66.469 6.552 66.613 ;
     RECT  7.68 66.085 9.096 66.613 ;
     RECT  136.272 64.451 136.296 66.661 ;
     RECT  137.4 64.451 137.712 66.661 ;
     RECT  99.6 21.637 100.008 67.141 ;
     RECT  131.616 65.509 132.312 67.283 ;
     RECT  136.272 66.661 137.712 67.283 ;
     RECT  6.528 66.613 9.096 67.331 ;
     RECT  22.176 55.667 22.2 67.571 ;
     RECT  88.8 2.151 89.112 67.669 ;
     RECT  98.736 67.141 100.008 67.765 ;
     RECT  105 2.151 105.312 67.765 ;
     RECT  136.416 67.283 137.712 67.811 ;
     RECT  88.8 67.669 90.072 67.813 ;
     RECT  110.4 66.181 111.288 67.907 ;
     RECT  11.472 66.709 11.496 68.099 ;
     RECT  94.2 2.151 94.512 68.101 ;
     RECT  95.712 67.813 95.736 68.101 ;
     RECT  94.2 68.101 95.736 68.243 ;
     RECT  88.608 67.813 90.072 68.245 ;
     RECT  98.736 67.765 100.68 68.339 ;
     RECT  16.416 66.275 16.584 68.341 ;
     RECT  17.616 66.275 18.912 68.341 ;
     RECT  78 2.151 78.312 68.341 ;
     RECT  83.4 2.151 83.712 68.389 ;
     RECT  94.2 68.243 94.512 68.677 ;
     RECT  132 67.283 132.312 68.773 ;
     RECT  137.4 67.811 137.712 68.917 ;
     RECT  75.984 68.341 76.008 69.011 ;
     RECT  102.048 68.821 102.072 69.251 ;
     RECT  137.4 68.917 137.832 69.251 ;
     RECT  99.6 68.339 100.68 69.299 ;
     RECT  88.56 68.245 90.072 69.395 ;
     RECT  83.4 68.389 84.696 69.539 ;
     RECT  95.712 68.243 95.736 69.539 ;
     RECT  86.832 68.485 86.856 69.587 ;
     RECT  96.912 69.157 96.936 69.683 ;
     RECT  107.76 68.197 107.784 69.779 ;
     RECT  121.104 33.589 121.512 69.827 ;
     RECT  132 68.773 132.552 69.829 ;
     RECT  132 69.829 133.368 69.875 ;
     RECT  104.304 67.765 105.312 69.877 ;
     RECT  97.104 69.781 97.128 69.923 ;
     RECT  108.816 69.781 108.84 69.973 ;
     RECT  108.72 69.973 108.84 70.019 ;
     RECT  135.264 66.131 135.288 70.069 ;
     RECT  6.528 67.331 6.552 70.117 ;
     RECT  4.224 68.245 4.248 70.163 ;
     RECT  110.4 67.907 111.24 70.163 ;
     RECT  6.336 70.117 6.552 70.165 ;
     RECT  104.112 69.877 105.312 70.549 ;
     RECT  5.712 70.165 6.552 70.645 ;
     RECT  7.8 67.331 8.112 70.645 ;
     RECT  5.712 70.645 8.112 70.691 ;
     RECT  78 68.341 78.408 70.741 ;
     RECT  86.88 70.597 86.904 70.741 ;
     RECT  16.416 68.341 18.912 70.835 ;
     RECT  133.344 69.875 133.368 70.979 ;
     RECT  103.152 70.549 105.312 71.077 ;
     RECT  94.08 68.677 94.512 71.173 ;
     RECT  102.432 71.077 105.312 71.219 ;
     RECT  94.08 71.173 94.632 71.221 ;
     RECT  110.4 70.163 111.192 71.269 ;
     RECT  6.336 70.691 8.112 71.315 ;
     RECT  86.88 70.741 87.096 71.317 ;
     RECT  88.56 69.395 89.112 71.317 ;
     RECT  91.344 68.629 91.368 71.365 ;
     RECT  93.648 71.221 94.632 71.411 ;
     RECT  86.88 71.317 89.112 71.459 ;
     RECT  99.6 69.299 100.008 71.461 ;
     RECT  108.72 70.019 108.744 71.509 ;
     RECT  102.672 71.219 105.312 71.699 ;
     RECT  78 70.741 79.032 71.701 ;
     RECT  91.248 71.365 91.368 71.843 ;
     RECT  96.96 71.797 96.984 71.893 ;
     RECT  96.96 71.893 97.272 72.035 ;
     RECT  97.248 72.035 97.272 72.083 ;
     RECT  107.712 71.077 107.736 72.179 ;
     RECT  94.08 71.411 94.632 72.325 ;
     RECT  4.464 70.645 4.488 72.419 ;
     RECT  94.08 72.325 95.592 72.419 ;
     RECT  108.72 71.509 108.84 72.419 ;
     RECT  134.496 70.069 135.288 72.419 ;
     RECT  110.4 71.269 111.576 72.421 ;
     RECT  112.8 71.221 112.824 72.467 ;
     RECT  110.4 72.421 111.72 72.757 ;
     RECT  91.248 71.843 91.272 72.803 ;
     RECT  97.344 72.709 97.368 72.851 ;
     RECT  86.88 71.459 87.096 72.949 ;
     RECT  16.512 70.835 18.912 72.995 ;
     RECT  104.256 71.699 105.312 73.093 ;
     RECT  78 71.701 79.8 73.235 ;
     RECT  99.456 71.461 100.008 73.285 ;
     RECT  94.08 72.419 94.512 73.331 ;
     RECT  92.592 68.629 92.616 73.333 ;
     RECT  86.88 72.949 87.192 73.381 ;
     RECT  110.4 72.757 111.768 73.381 ;
     RECT  137.4 69.251 137.712 73.477 ;
     RECT  99.456 73.285 100.92 73.523 ;
     RECT  110.016 73.381 111.768 73.765 ;
     RECT  110.016 73.765 112.104 73.811 ;
     RECT  108.72 72.419 108.744 73.909 ;
     RECT  104.256 73.093 105.768 73.955 ;
     RECT  74.784 70.069 74.808 74.053 ;
     RECT  97.008 73.813 97.032 74.099 ;
     RECT  74.448 74.053 74.808 74.101 ;
     RECT  88.56 71.459 89.112 74.147 ;
     RECT  86.88 73.381 87.528 74.339 ;
     RECT  83.4 69.539 83.712 74.389 ;
     RECT  134.496 72.419 134.52 74.437 ;
     RECT  102.672 71.699 103.176 74.483 ;
     RECT  94.2 73.331 94.512 74.485 ;
     RECT  95.568 72.419 95.592 74.485 ;
     RECT  7.8 71.315 8.112 74.629 ;
     RECT  74.448 74.101 75.24 74.629 ;
     RECT  111.744 73.811 112.104 74.675 ;
     RECT  13.2 66.515 14.76 74.723 ;
     RECT  137.4 73.477 137.928 74.723 ;
     RECT  107.76 73.909 108.744 74.771 ;
     RECT  92.4 73.333 92.616 74.819 ;
     RECT  67.2 2.151 67.512 74.869 ;
     RECT  99.456 73.523 100.008 74.917 ;
     RECT  99.456 74.917 100.824 75.059 ;
     RECT  4.08 72.901 4.104 75.107 ;
     RECT  94.2 74.485 95.592 75.109 ;
     RECT  78 73.235 79.032 75.157 ;
     RECT  104.256 73.955 105.48 75.251 ;
     RECT  110.016 73.811 110.712 75.251 ;
     RECT  134.496 74.437 134.76 75.253 ;
     RECT  16.512 72.995 16.584 75.299 ;
     RECT  103.152 74.483 103.176 75.395 ;
     RECT  6.336 71.315 6.36 75.397 ;
     RECT  7.8 74.629 8.232 75.397 ;
     RECT  6.336 75.397 8.232 75.443 ;
     RECT  17.616 72.995 18.912 75.539 ;
     RECT  71.28 74.725 71.304 75.683 ;
     RECT  74.064 74.629 76.344 75.683 ;
     RECT  99.456 75.059 100.008 75.683 ;
     RECT  74.448 75.683 76.344 75.731 ;
     RECT  134.208 75.253 134.76 75.731 ;
     RECT  18.192 75.539 18.912 75.779 ;
     RECT  81.312 73.957 81.336 75.781 ;
     RECT  82.512 74.389 83.712 75.781 ;
     RECT  132 69.875 132.312 75.781 ;
     RECT  75.216 75.731 76.344 75.827 ;
     RECT  81.312 75.781 83.712 75.827 ;
     RECT  68.976 75.157 69 75.875 ;
     RECT  81.312 75.827 81.672 75.875 ;
     RECT  88.656 74.147 89.112 75.875 ;
     RECT  113.472 74.629 113.496 75.923 ;
     RECT  84.72 70.645 84.744 75.925 ;
     RECT  84.72 75.925 84.984 75.971 ;
     RECT  112.08 74.675 112.104 76.021 ;
     RECT  87.072 74.339 87.528 76.067 ;
     RECT  92.592 74.819 92.616 76.163 ;
     RECT  67.056 74.869 67.512 76.211 ;
     RECT  84.96 75.971 84.984 76.213 ;
     RECT  108.24 74.771 108.744 76.213 ;
     RECT  78 75.157 79.224 76.259 ;
     RECT  84.96 76.213 85.08 76.259 ;
     RECT  110.4 75.251 110.712 76.309 ;
     RECT  111.792 76.021 112.104 76.309 ;
     RECT  104.256 75.251 105.312 76.355 ;
     RECT  87.216 76.067 87.528 76.357 ;
     RECT  98.4 76.261 98.424 76.357 ;
     RECT  108.192 76.213 108.744 76.357 ;
     RECT  132 75.781 132.696 76.357 ;
     RECT  6.336 75.443 8.112 76.403 ;
     RECT  129.36 75.253 129.384 76.403 ;
     RECT  83.4 75.827 83.712 76.453 ;
     RECT  107.424 76.357 108.744 76.453 ;
     RECT  81.648 75.875 81.672 76.499 ;
     RECT  98.352 76.357 98.424 76.499 ;
     RECT  98.352 76.499 98.376 76.501 ;
     RECT  83.4 76.453 83.832 76.595 ;
     RECT  96.816 76.261 96.84 76.691 ;
     RECT  98.064 76.501 98.376 76.787 ;
     RECT  105 76.355 105.312 76.837 ;
     RECT  115.8 23.603 116.112 76.885 ;
     RECT  135.984 76.693 136.008 76.885 ;
     RECT  91.2 76.357 91.224 76.931 ;
     RECT  87.216 76.357 87.624 76.979 ;
     RECT  107.424 76.453 108.84 77.027 ;
     RECT  111.792 76.309 112.488 77.027 ;
     RECT  94.08 75.109 95.592 77.267 ;
     RECT  132 76.357 133.08 77.267 ;
     RECT  72.6 2.151 72.912 77.269 ;
     RECT  110.304 76.309 110.712 77.269 ;
     RECT  75.216 75.827 75.24 77.315 ;
     RECT  105 76.837 105.432 77.365 ;
     RECT  110.304 77.269 110.808 77.413 ;
     RECT  135.216 76.885 136.008 77.413 ;
     RECT  137.4 74.723 137.712 77.413 ;
     RECT  137.4 77.413 137.928 77.461 ;
     RECT  104.64 77.365 105.432 77.507 ;
     RECT  125.088 76.309 125.112 77.507 ;
     RECT  79.488 76.357 79.512 77.555 ;
     RECT  103.008 76.741 103.032 77.555 ;
     RECT  67.2 76.211 67.512 77.557 ;
     RECT  54.288 67.141 54.312 77.651 ;
     RECT  105 77.507 105.432 77.941 ;
     RECT  6.336 76.403 6.792 77.987 ;
     RECT  85.056 76.259 85.08 77.989 ;
     RECT  70.128 21.637 70.152 78.037 ;
     RECT  111.792 77.027 111.816 78.037 ;
     RECT  115.104 76.885 116.112 78.037 ;
     RECT  70.128 78.037 70.248 78.083 ;
     RECT  111.792 78.037 112.68 78.083 ;
     RECT  114.144 78.037 116.112 78.083 ;
     RECT  99.6 75.683 100.008 78.131 ;
     RECT  135.216 77.413 136.2 78.229 ;
     RECT  137.28 77.461 137.928 78.229 ;
     RECT  109.968 77.413 110.808 78.469 ;
     RECT  115.8 78.083 116.112 78.469 ;
     RECT  78 76.259 78.312 78.565 ;
     RECT  94.2 77.267 95.592 78.611 ;
     RECT  109.68 78.469 110.808 78.611 ;
     RECT  67.2 77.557 67.608 78.659 ;
     RECT  114.144 78.083 114.168 78.707 ;
     RECT  132 77.267 132.84 78.707 ;
     RECT  134.208 75.731 134.232 78.853 ;
     RECT  135.216 78.229 137.928 78.853 ;
     RECT  134.208 78.853 137.928 78.899 ;
     RECT  92.928 78.901 92.952 79.043 ;
     RECT  80.304 78.325 80.328 79.141 ;
     RECT  76.368 76.213 76.392 79.187 ;
     RECT  79.824 79.141 80.328 79.187 ;
     RECT  87.216 76.979 87.24 79.189 ;
     RECT  107.424 77.027 108.264 79.189 ;
     RECT  6.336 77.987 6.36 79.237 ;
     RECT  78 78.565 78.504 79.283 ;
     RECT  112.656 78.083 112.68 79.283 ;
     RECT  134.784 78.899 137.928 79.379 ;
     RECT  105 77.941 105.576 79.427 ;
     RECT  4.56 78.613 4.584 79.475 ;
     RECT  109.68 78.611 110.712 79.475 ;
     RECT  13.2 74.723 14.088 79.523 ;
     RECT  84.816 77.989 85.08 79.523 ;
     RECT  83.4 76.595 83.712 79.525 ;
     RECT  16.512 75.299 16.536 79.571 ;
     RECT  126.6 2.151 126.912 79.621 ;
     RECT  86.256 79.189 87.24 79.715 ;
     RECT  7.8 76.403 8.112 79.717 ;
     RECT  132 78.707 132.312 79.717 ;
     RECT  6.336 79.237 6.456 79.763 ;
     RECT  72.6 77.269 73.416 79.765 ;
     RECT  83.4 79.525 83.832 79.811 ;
     RECT  90.48 78.517 90.504 79.811 ;
     RECT  94.2 78.611 94.632 79.813 ;
     RECT  79.824 79.187 79.848 79.859 ;
     RECT  103.296 79.813 103.32 79.909 ;
     RECT  68.64 78.613 68.664 80.003 ;
     RECT  94.2 79.813 95.304 80.003 ;
     RECT  102.864 79.909 103.32 80.243 ;
     RECT  107.424 79.189 108.6 80.245 ;
     RECT  134.784 79.379 137.88 80.245 ;
     RECT  72.6 79.765 73.608 80.293 ;
     RECT  134.496 80.245 137.88 80.341 ;
     RECT  98.352 76.787 98.376 80.389 ;
     RECT  132 79.717 132.84 80.435 ;
     RECT  7.536 79.717 8.112 80.483 ;
     RECT  106.608 80.245 108.6 80.483 ;
     RECT  75.792 79.333 75.816 80.531 ;
     RECT  102.864 80.243 103.032 80.579 ;
     RECT  102.864 80.579 102.888 80.675 ;
     RECT  101.76 77.701 101.784 80.723 ;
     RECT  98.064 80.389 98.376 80.773 ;
     RECT  99.6 78.131 99.912 80.773 ;
     RECT  85.056 79.523 85.08 80.821 ;
     RECT  72.384 80.293 73.608 80.867 ;
     RECT  134.448 80.341 137.88 80.917 ;
     RECT  84.864 80.821 85.08 80.963 ;
     RECT  72.384 80.867 73.416 81.061 ;
     RECT  88.8 75.875 89.112 81.061 ;
     RECT  80.688 81.013 80.712 81.203 ;
     RECT  106.608 80.483 108.264 81.203 ;
     RECT  88.704 81.061 89.112 81.251 ;
     RECT  105 79.427 105.312 81.397 ;
     RECT  102.336 80.917 102.36 81.539 ;
     RECT  83.4 79.811 83.712 81.589 ;
     RECT  98.064 80.773 99.912 81.635 ;
     RECT  124.8 80.773 124.824 81.637 ;
     RECT  125.904 79.621 126.912 81.637 ;
     RECT  78 79.283 78.312 81.877 ;
     RECT  121.2 69.827 121.512 81.877 ;
     RECT  132 80.435 132.312 81.973 ;
     RECT  133.584 80.917 137.88 81.973 ;
     RECT  124.8 81.637 126.912 82.019 ;
     RECT  6.336 79.763 6.36 82.021 ;
     RECT  132 81.973 137.88 82.021 ;
     RECT  6.336 82.021 6.552 82.067 ;
     RECT  109.344 80.869 109.368 82.067 ;
     RECT  71.76 81.061 73.416 82.163 ;
     RECT  81.456 81.205 81.48 82.307 ;
     RECT  107.424 81.203 108.264 82.405 ;
     RECT  111.744 81.541 111.768 82.451 ;
     RECT  88.8 81.251 89.112 82.453 ;
     RECT  124.8 82.019 125.16 82.691 ;
     RECT  6.528 82.067 6.552 82.693 ;
     RECT  7.8 80.483 8.112 82.693 ;
     RECT  4.752 82.597 4.776 82.739 ;
     RECT  77.904 81.877 78.312 82.789 ;
     RECT  121.2 81.877 122.424 82.885 ;
     RECT  83.4 81.589 83.832 82.979 ;
     RECT  121.2 82.885 122.568 83.027 ;
     RECT  115.8 78.469 116.232 83.173 ;
     RECT  118.848 82.837 118.872 83.173 ;
     RECT  6.528 82.693 8.112 83.267 ;
     RECT  32.832 75.205 32.856 83.267 ;
     RECT  107.424 82.405 108.888 83.267 ;
     RECT  85.056 80.963 85.08 83.269 ;
     RECT  45.6 2.151 45.912 83.365 ;
     RECT  87.84 82.453 89.112 83.411 ;
     RECT  84.768 83.269 85.08 83.555 ;
     RECT  105 81.397 105.576 83.555 ;
     RECT  84.96 83.555 85.08 83.795 ;
     RECT  98.112 81.635 99.912 83.843 ;
     RECT  108.864 83.267 108.888 83.843 ;
     RECT  125.136 82.691 125.16 83.843 ;
     RECT  130.56 83.173 130.584 83.843 ;
     RECT  80.064 83.173 80.088 84.035 ;
     RECT  24 2.151 24.312 84.037 ;
     RECT  105 83.555 105.312 84.037 ;
     RECT  104.88 84.037 105.312 84.179 ;
     RECT  107.424 83.267 107.736 84.179 ;
     RECT  118.272 83.173 118.872 84.179 ;
     RECT  67.2 78.659 67.512 84.229 ;
     RECT  118.272 84.179 118.296 84.323 ;
     RECT  54.816 83.749 54.84 84.371 ;
     RECT  45.504 83.365 45.912 84.419 ;
     RECT  132 82.021 138.024 84.419 ;
     RECT  88.8 83.411 89.112 84.517 ;
     RECT  59.904 83.461 59.928 84.563 ;
     RECT  81.792 82.981 81.816 84.563 ;
     RECT  132 84.419 133.272 84.611 ;
     RECT  40.2 2.151 40.512 84.613 ;
     RECT  94.2 80.003 94.512 84.613 ;
     RECT  38.304 84.373 38.328 84.659 ;
     RECT  88.8 84.517 89.544 84.659 ;
     RECT  121.2 83.027 122.424 84.803 ;
     RECT  101.568 83.749 101.592 84.901 ;
     RECT  67.2 84.229 67.8 84.947 ;
     RECT  84.96 83.795 84.984 84.947 ;
     RECT  101.568 84.901 102.504 84.947 ;
     RECT  39.84 84.613 41.4 84.995 ;
     RECT  134.448 84.419 138.024 84.995 ;
     RECT  92.928 83.749 92.952 85.043 ;
     RECT  115.8 83.173 116.568 85.043 ;
     RECT  39.84 84.995 40.512 85.091 ;
     RECT  52.416 83.797 52.44 85.091 ;
     RECT  72.6 82.163 73.416 85.139 ;
     RECT  107.712 84.179 107.736 85.139 ;
     RECT  23.616 84.037 24.312 85.187 ;
     RECT  2.4 45.731 2.712 85.189 ;
     RECT  77.472 82.789 78.312 85.189 ;
     RECT  92.208 85.093 92.232 85.283 ;
     RECT  61.8 2.151 62.112 85.285 ;
     RECT  76.944 85.189 78.312 85.427 ;
     RECT  98.112 83.843 98.136 85.427 ;
     RECT  54.72 85.237 54.744 85.475 ;
     RECT  61.152 85.285 62.112 85.475 ;
     RECT  27.744 84.757 27.768 85.523 ;
     RECT  36.864 84.325 36.888 85.523 ;
     RECT  102.48 84.947 102.504 85.523 ;
     RECT  134.448 84.995 137.928 85.523 ;
     RECT  77.472 85.427 78.312 85.571 ;
     RECT  134.448 85.523 137.832 85.571 ;
     RECT  94.2 84.613 95.304 85.619 ;
     RECT  134.496 85.571 137.832 85.619 ;
     RECT  134.496 85.619 135 85.667 ;
     RECT  6.528 83.267 6.552 85.955 ;
     RECT  38.16 85.429 38.184 86.099 ;
     RECT  44.448 84.853 44.472 86.099 ;
     RECT  134.976 85.667 135 86.099 ;
     RECT  71.232 84.853 71.256 86.195 ;
     RECT  72.6 85.139 72.912 86.341 ;
     RECT  7.8 83.267 8.112 86.409 ;
     RECT  13.2 79.523 13.512 86.409 ;
     RECT  18.6 75.779 18.912 86.409 ;
     RECT  24 85.187 24.312 86.409 ;
     RECT  29.4 2.151 29.712 86.409 ;
     RECT  34.8 21.539 35.112 86.409 ;
     RECT  40.2 85.091 40.512 86.409 ;
     RECT  45.6 84.419 45.912 86.409 ;
     RECT  51 2.151 51.312 86.409 ;
     RECT  56.4 2.151 56.712 86.409 ;
     RECT  61.8 85.475 62.112 86.409 ;
     RECT  78 85.571 78.312 86.409 ;
     RECT  83.4 82.979 83.712 86.409 ;
     RECT  94.2 85.619 94.512 86.409 ;
     RECT  99.6 83.843 99.912 86.409 ;
     RECT  105 84.179 105.312 86.409 ;
     RECT  110.4 79.475 110.712 86.409 ;
     RECT  115.8 85.043 116.112 86.409 ;
     RECT  121.2 84.803 121.512 86.409 ;
     RECT  126.6 82.019 126.912 86.409 ;
     RECT  132 84.611 132.312 86.409 ;
     RECT  2.4 85.189 2.952 86.423 ;
     RECT  7.8 86.409 7.92 86.423 ;
     RECT  13.2 86.409 13.32 86.423 ;
     RECT  18.6 86.409 18.72 86.423 ;
     RECT  24 86.409 24.12 86.423 ;
     RECT  29.4 86.409 29.52 86.423 ;
     RECT  34.8 86.409 34.92 86.423 ;
     RECT  40.2 86.409 40.32 86.423 ;
     RECT  45.6 86.409 45.72 86.423 ;
     RECT  51 86.409 51.12 86.423 ;
     RECT  56.4 86.409 56.52 86.423 ;
     RECT  61.8 86.409 61.92 86.423 ;
     RECT  67.2 84.947 67.512 86.423 ;
     RECT  72.6 86.341 73.224 86.423 ;
     RECT  78 86.409 78.12 86.423 ;
     RECT  83.4 86.409 83.52 86.423 ;
     RECT  88.8 84.659 89.112 86.423 ;
     RECT  94.2 86.409 94.32 86.423 ;
     RECT  99.6 86.409 99.72 86.423 ;
     RECT  105 86.409 105.12 86.423 ;
     RECT  110.4 86.409 110.52 86.423 ;
     RECT  115.8 86.409 115.92 86.423 ;
     RECT  121.2 86.409 121.32 86.423 ;
     RECT  126.6 86.409 126.72 86.423 ;
     RECT  132 86.409 132.12 86.423 ;
     RECT  136.032 85.619 137.832 86.629 ;
     RECT  136.032 86.629 138.744 86.867 ;
     RECT  136.032 86.867 137.304 87.443 ;
     RECT  70.224 78.083 70.248 87.781 ;
     RECT  136.032 87.443 136.728 87.827 ;
     RECT  13.104 86.485 13.128 88.405 ;
     RECT  16.272 86.581 16.296 88.405 ;
     RECT  21.312 86.581 21.336 88.405 ;
     RECT  31.488 86.581 31.512 88.405 ;
     RECT  34.512 86.581 34.536 88.405 ;
     RECT  36.576 86.005 36.6 88.405 ;
     RECT  49.776 86.341 49.8 88.405 ;
     RECT  52.656 86.581 52.68 88.405 ;
     RECT  73.2 86.423 73.224 88.405 ;
     RECT  75.888 86.581 75.912 88.405 ;
     RECT  81.072 86.581 81.096 88.405 ;
     RECT  13.104 88.405 13.416 88.451 ;
     RECT  15.984 88.405 16.296 88.451 ;
     RECT  21.216 88.405 21.336 88.451 ;
     RECT  31.488 88.405 31.704 88.451 ;
     RECT  34.272 88.405 34.536 88.451 ;
     RECT  36.576 88.405 36.936 88.451 ;
     RECT  49.776 88.405 49.992 88.451 ;
     RECT  52.56 88.405 52.68 88.451 ;
     RECT  73.2 88.405 73.464 88.451 ;
     RECT  75.888 88.405 76.104 88.451 ;
     RECT  81.072 88.405 81.288 88.451 ;
     RECT  136.032 87.827 136.152 88.451 ;
     RECT  4.272 86.245 4.296 88.499 ;
     RECT  13.512 3.301 14.592 6.035 ;
     RECT  134.904 3.301 136.176 3.349 ;
     RECT  136.2 3.301 137.4 4.067 ;
     RECT  134.952 3.349 136.176 4.019 ;
     RECT  114.648 3.829 115.8 14.291 ;
     RECT  134.904 4.019 136.176 4.067 ;
     RECT  16.632 4.117 17.76 4.405 ;
     RECT  16.776 4.405 17.76 8.965 ;
     RECT  5.832 5.077 6.816 6.419 ;
     RECT  19.752 5.509 20.88 14.629 ;
     RECT  13.512 6.035 14.784 7.427 ;
     RECT  7.68 6.419 7.8 7.909 ;
     RECT  134.904 7.381 136.272 9.539 ;
     RECT  136.296 7.381 137.4 9.539 ;
     RECT  132.312 7.909 133.296 9.155 ;
     RECT  2.712 8.533 3.984 9.491 ;
     RECT  13.512 11.653 14.976 11.941 ;
     RECT  15 11.653 16.368 11.701 ;
     RECT  15.288 11.701 16.368 17.941 ;
     RECT  13.512 11.941 14.544 12.469 ;
     RECT  116.112 14.197 117.36 21.445 ;
     RECT  22.776 14.389 24 14.867 ;
     RECT  4.584 14.773 6 14.867 ;
     RECT  6.408 14.773 7.8 15.349 ;
     RECT  132.312 16.357 133.344 19.379 ;
     RECT  133.368 16.357 134.64 18.037 ;
     RECT  133.464 18.037 134.64 18.179 ;
     RECT  133.368 18.179 134.64 19.379 ;
     RECT  22.488 19.237 24 21.205 ;
     RECT  6.792 19.667 7.8 21.155 ;
     RECT  10.296 20.917 11.376 21.155 ;
     RECT  8.76 21.061 10.272 21.635 ;
     RECT  5.928 21.155 7.8 22.117 ;
     RECT  10.296 21.155 10.536 21.589 ;
     RECT  22.584 21.205 24 21.347 ;
     RECT  22.488 21.347 24 23.651 ;
     RECT  134.664 22.021 136.032 23.317 ;
     RECT  136.056 22.021 137.4 26.437 ;
     RECT  4.44 22.693 5.904 23.555 ;
     RECT  2.712 22.741 4.224 23.027 ;
     RECT  6.744 22.931 7.8 23.027 ;
     RECT  5.928 23.027 7.8 23.893 ;
     RECT  134.664 23.317 135.744 26.533 ;
     RECT  5.76 23.555 5.904 24.277 ;
     RECT  116.112 23.603 117.36 37.187 ;
     RECT  22.2 23.651 22.392 24.661 ;
     RECT  5.928 23.893 7.104 24.323 ;
     RECT  5.784 24.323 7.104 24.659 ;
     RECT  133.32 24.469 134.64 30.757 ;
     RECT  132.312 25.187 133.296 27.877 ;
     RECT  136.392 26.437 137.4 27.877 ;
     RECT  134.664 28.547 135.744 30.661 ;
     RECT  132.312 28.691 133.296 30.805 ;
     RECT  134.664 30.661 135.648 30.757 ;
     RECT  133.32 30.757 134.496 30.805 ;
     RECT  133.32 30.805 134.4 31.285 ;
     RECT  6.648 31.285 7.8 31.861 ;
     RECT  11.544 31.285 12.912 32.581 ;
     RECT  8.112 31.861 9.168 32.485 ;
     RECT  133.32 32.243 134.64 34.117 ;
     RECT  134.712 32.531 135.744 34.069 ;
     RECT  132.312 33.395 133.296 39.781 ;
     RECT  133.464 34.117 134.64 34.165 ;
     RECT  133.656 34.165 134.64 34.883 ;
     RECT  2.712 34.741 3.936 34.837 ;
     RECT  2.712 34.837 3.696 35.459 ;
     RECT  133.464 34.883 134.64 35.699 ;
     RECT  134.76 34.979 135.792 36.515 ;
     RECT  2.712 35.459 3.72 36.469 ;
     RECT  133.32 35.699 134.64 37.573 ;
     RECT  2.712 36.469 4.224 37.091 ;
     RECT  134.712 36.515 135.792 37.573 ;
     RECT  133.32 37.573 134.544 38.387 ;
     RECT  133.32 38.387 134.64 41.075 ;
     RECT  116.112 39.253 117.36 39.635 ;
     RECT  116.112 39.635 117.384 40.069 ;
     RECT  116.112 40.069 117.408 40.259 ;
     RECT  3.336 40.261 4.656 41.363 ;
     RECT  4.68 40.261 6.048 41.363 ;
     RECT  133.32 41.075 134.688 41.557 ;
     RECT  133.512 41.557 134.688 41.939 ;
     RECT  11.832 41.605 13.2 45.059 ;
     RECT  133.32 41.939 134.688 51.301 ;
     RECT  132.312 42.851 133.296 52.981 ;
     RECT  22.152 44.723 22.344 45.733 ;
     RECT  10.872 45.059 13.2 45.109 ;
     RECT  10.872 45.109 12.144 45.155 ;
     RECT  12.168 45.109 13.2 46.067 ;
     RECT  22.296 45.733 22.344 45.877 ;
     RECT  5.592 46.693 6.912 47.269 ;
     RECT  5.736 47.269 6.912 47.845 ;
     RECT  2.712 47.461 3.696 48.515 ;
     RECT  5.736 48.227 6.912 48.275 ;
     RECT  5.592 48.275 6.912 49.043 ;
     RECT  22.152 48.467 22.248 49.861 ;
     RECT  133.32 51.301 134.544 52.451 ;
     RECT  133.32 52.451 134.64 59.797 ;
     RECT  12.24 53.939 13.2 54.661 ;
     RECT  12.12 54.661 13.2 55.283 ;
     RECT  21.096 55.667 22.176 57.011 ;
     RECT  132.312 56.291 133.296 66.179 ;
     RECT  20.712 57.011 22.176 57.059 ;
     RECT  18.912 58.355 20.016 62.293 ;
     RECT  133.32 59.797 134.544 64.213 ;
     RECT  18.912 62.483 20.016 66.515 ;
     RECT  135.288 63.299 136.272 67.283 ;
     RECT  133.368 64.213 134.544 65.555 ;
     RECT  15.144 64.403 16.176 65.843 ;
     RECT  136.296 64.451 137.4 66.661 ;
     RECT  7.488 65.027 7.68 66.469 ;
     RECT  133.32 65.555 134.544 65.987 ;
     RECT  15.144 65.843 16.416 66.515 ;
     RECT  133.32 65.987 134.64 66.131 ;
     RECT  16.584 66.275 17.616 68.341 ;
     RECT  6.552 66.469 7.68 66.613 ;
     RECT  135.288 67.283 136.416 67.811 ;
     RECT  6.552 67.331 7.8 70.645 ;
     RECT  94.512 67.813 95.712 68.101 ;
     RECT  94.512 68.243 95.712 69.539 ;
     RECT  2.712 68.245 4.224 70.163 ;
     RECT  90.072 68.629 91.344 69.395 ;
     RECT  91.368 68.629 92.592 71.843 ;
     RECT  92.616 68.677 94.08 71.221 ;
     RECT  100.68 68.821 102.048 69.251 ;
     RECT  95.736 69.157 96.912 69.539 ;
     RECT  83.712 69.539 84.696 70.645 ;
     RECT  107.76 69.779 107.784 69.781 ;
     RECT  107.76 69.781 108.816 69.973 ;
     RECT  132.312 69.875 133.344 70.979 ;
     RECT  107.76 69.973 108.72 71.077 ;
     RECT  108.744 70.019 108.84 71.509 ;
     RECT  133.368 70.069 134.496 70.979 ;
     RECT  111.192 70.163 111.24 71.269 ;
     RECT  4.488 70.645 5.712 70.691 ;
     RECT  83.712 70.645 84.72 75.971 ;
     RECT  87.096 70.741 88.56 71.317 ;
     RECT  107.736 71.077 108.72 72.179 ;
     RECT  92.616 71.221 93.648 71.411 ;
     RECT  111.576 71.269 112.8 72.421 ;
     RECT  6.36 71.315 7.8 75.397 ;
     RECT  92.616 71.411 94.08 73.331 ;
     RECT  87.096 71.459 88.56 72.949 ;
     RECT  103.176 71.699 104.256 75.395 ;
     RECT  91.272 71.843 92.592 72.803 ;
     RECT  94.512 72.419 95.568 74.485 ;
     RECT  108.744 72.419 108.84 73.381 ;
     RECT  111.72 72.421 112.8 72.467 ;
     RECT  111.72 72.467 112.104 72.757 ;
     RECT  111.768 72.757 112.104 73.765 ;
     RECT  92.4 72.803 92.592 73.333 ;
     RECT  2.712 72.901 4.08 75.107 ;
     RECT  87.192 72.949 88.56 73.381 ;
     RECT  16.584 72.995 17.616 75.299 ;
     RECT  87.528 73.381 88.56 74.147 ;
     RECT  108.744 73.381 110.016 75.251 ;
     RECT  100.008 73.523 100.824 74.917 ;
     RECT  110.712 73.811 111.744 74.675 ;
     RECT  95.592 73.813 97.008 74.099 ;
     RECT  87.528 74.147 88.656 75.875 ;
     RECT  81.336 74.389 82.512 75.781 ;
     RECT  72.912 74.629 74.064 75.683 ;
     RECT  112.104 74.629 113.472 75.923 ;
     RECT  110.712 74.675 112.08 76.021 ;
     RECT  70.152 74.725 71.28 75.683 ;
     RECT  71.304 74.725 72.6 75.683 ;
     RECT  108.192 74.771 108.24 76.213 ;
     RECT  92.616 75.109 94.08 76.163 ;
     RECT  67.512 75.157 68.976 75.875 ;
     RECT  69 75.157 70.128 75.875 ;
     RECT  108.744 75.251 110.4 76.309 ;
     RECT  16.536 75.299 17.616 75.539 ;
     RECT  99.456 75.683 99.6 76.261 ;
     RECT  134.232 75.731 134.76 76.693 ;
     RECT  132.696 75.781 134.208 76.357 ;
     RECT  75.24 75.827 76.344 76.213 ;
     RECT  87.528 75.875 88.8 76.357 ;
     RECT  112.104 75.923 112.488 76.309 ;
     RECT  83.712 75.971 84.96 76.259 ;
     RECT  110.712 76.021 111.792 77.269 ;
     RECT  75.24 76.213 76.368 77.315 ;
     RECT  78.312 76.259 79.224 76.357 ;
     RECT  83.712 76.259 85.056 76.453 ;
     RECT  95.592 76.261 96.816 76.691 ;
     RECT  98.424 76.261 99.6 76.499 ;
     RECT  108.744 76.309 110.304 76.453 ;
     RECT  125.112 76.309 126.6 77.507 ;
     RECT  104.64 76.355 105 77.365 ;
     RECT  78.312 76.357 79.488 77.555 ;
     RECT  87.624 76.357 88.8 76.979 ;
     RECT  96.84 76.357 98.352 76.501 ;
     RECT  133.08 76.357 134.208 77.267 ;
     RECT  6.792 76.403 7.8 77.987 ;
     RECT  83.832 76.453 85.056 76.595 ;
     RECT  108.84 76.453 110.304 77.027 ;
     RECT  98.376 76.499 99.6 80.773 ;
     RECT  96.84 76.501 98.064 76.691 ;
     RECT  83.712 76.595 85.056 77.989 ;
     RECT  134.232 76.693 135.984 76.885 ;
     RECT  136.008 76.693 137.4 77.413 ;
     RECT  134.232 76.885 135.216 78.853 ;
     RECT  108.264 77.027 110.304 77.413 ;
     RECT  111.816 77.027 112.488 78.037 ;
     RECT  132.84 77.267 134.208 78.707 ;
     RECT  110.808 77.269 111.792 78.083 ;
     RECT  108.264 77.413 109.968 78.469 ;
     RECT  136.2 77.413 137.4 77.461 ;
     RECT  136.2 77.461 137.28 78.229 ;
     RECT  78.312 77.555 78.504 78.565 ;
     RECT  6.36 77.987 7.8 79.237 ;
     RECT  83.712 77.989 84.816 79.523 ;
     RECT  112.68 78.037 114.144 78.707 ;
     RECT  108.264 78.469 109.68 79.189 ;
     RECT  89.112 78.517 90.48 79.811 ;
     RECT  94.632 78.611 95.304 79.813 ;
     RECT  67.608 78.613 68.64 78.659 ;
     RECT  67.512 78.659 68.64 80.003 ;
     RECT  132.312 78.707 134.208 78.899 ;
     RECT  132.312 78.899 132.84 79.717 ;
     RECT  134.448 78.899 134.784 80.245 ;
     RECT  92.952 78.901 94.2 79.043 ;
     RECT  78.504 79.141 79.824 79.283 ;
     RECT  85.08 79.189 86.256 79.715 ;
     RECT  108.6 79.189 109.68 79.475 ;
     RECT  6.456 79.237 7.8 79.717 ;
     RECT  78.312 79.283 79.824 79.859 ;
     RECT  105.312 79.427 105.576 80.245 ;
     RECT  108.6 79.475 110.4 80.483 ;
     RECT  83.712 79.523 85.056 79.525 ;
     RECT  83.832 79.525 85.056 79.811 ;
     RECT  6.456 79.717 7.536 79.763 ;
     RECT  6.36 79.763 7.536 80.483 ;
     RECT  83.712 79.811 85.056 80.821 ;
     RECT  101.784 79.813 103.296 79.909 ;
     RECT  101.784 79.909 102.864 80.675 ;
     RECT  105.312 80.245 106.608 81.203 ;
     RECT  134.448 80.245 134.496 80.341 ;
     RECT  132.312 80.435 132.84 80.917 ;
     RECT  6.36 80.483 7.8 82.021 ;
     RECT  108.264 80.483 110.4 80.869 ;
     RECT  101.784 80.675 102.36 80.723 ;
     RECT  102.336 80.723 102.36 80.917 ;
     RECT  124.824 80.773 125.904 81.637 ;
     RECT  83.712 80.821 84.864 80.963 ;
     RECT  108.264 80.869 109.344 82.067 ;
     RECT  109.368 80.869 110.4 82.067 ;
     RECT  132.312 80.917 133.584 81.973 ;
     RECT  83.712 80.963 85.056 81.589 ;
     RECT  70.248 81.061 71.76 82.163 ;
     RECT  105.312 81.203 105.576 81.397 ;
     RECT  88.704 81.251 88.8 82.453 ;
     RECT  110.712 81.541 111.744 82.451 ;
     RECT  83.832 81.589 85.056 82.979 ;
     RECT  125.16 82.019 126.6 83.843 ;
     RECT  6.552 82.021 7.8 82.693 ;
     RECT  108.264 82.067 110.4 82.405 ;
     RECT  108.888 82.405 110.4 83.843 ;
     RECT  83.712 82.979 85.056 83.269 ;
     RECT  130.584 83.173 132 83.843 ;
     RECT  6.552 83.267 7.8 85.955 ;
     RECT  107.736 83.267 108.864 83.843 ;
     RECT  83.712 83.269 84.768 83.555 ;
     RECT  83.712 83.555 84.96 84.947 ;
     RECT  92.952 83.749 94.2 85.043 ;
     RECT  51.312 83.797 52.416 85.091 ;
     RECT  98.136 83.843 99.6 85.427 ;
     RECT  36.888 84.373 38.304 84.659 ;
     RECT  45.504 84.419 45.6 84.853 ;
     RECT  133.272 84.419 134.448 84.611 ;
     RECT  38.328 84.613 39.84 84.659 ;
     RECT  36.888 84.659 38.184 85.429 ;
     RECT  44.472 84.853 45.6 86.099 ;
     RECT  70.248 84.853 71.232 86.195 ;
     RECT  71.256 84.853 72.6 86.195 ;
     RECT  72.912 85.139 73.224 86.341 ;
     RECT  36.888 85.429 38.16 85.523 ;
     RECT  137.832 85.523 137.928 86.629 ;
     RECT  135 85.619 136.032 86.099 ;
     RECT  35.112 86.005 36.576 86.409 ;
     RECT  2.952 86.245 4.272 86.375 ;
     RECT  49.8 86.341 51 86.423 ;
     RECT  3 86.375 4.272 86.423 ;
  END
END qkd_static_kv_landing_lane
END LIBRARY
